VERSION 5.8 ;
BUSBITCHARS "[]" ;
DIVIDERCHAR "/" ;
UNITS
    DATABASE MICRONS 1000 ;
END UNITS

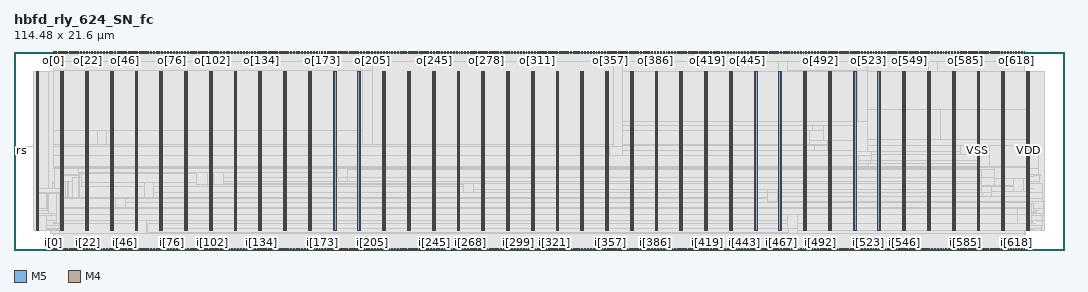
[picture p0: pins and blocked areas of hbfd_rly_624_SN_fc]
MACRO hbfd_rly_624_SN_fc
  FOREIGN hbfd_rly_624_SN_fc 0 0 ;
  CLASS BLOCK ;
  SIZE 114.48 BY 21.6 ;
  PIN clk_in
    DIRECTION INPUT ;
    USE SIGNAL ;
    PORT
      LAYER M5 ;
        RECT  57.216 0 57.24 0.192 ;
    END
  END clk_in
  PIN clk_out
    DIRECTION OUTPUT ;
    USE SIGNAL ;
    PORT
      LAYER M5 ;
        RECT  57.216 21.408 57.24 21.6 ;
    END
  END clk_out
  PIN i[0]
    DIRECTION INPUT ;
    USE SIGNAL ;
    PORT
      LAYER M5 ;
        RECT  4.32 0 4.344 0.192 ;
    END
  END i[0]
  PIN i[100]
    DIRECTION INPUT ;
    USE SIGNAL ;
    PORT
      LAYER M5 ;
        RECT  21.264 0 21.288 0.192 ;
    END
  END i[100]
  PIN i[101]
    DIRECTION INPUT ;
    USE SIGNAL ;
    PORT
      LAYER M5 ;
        RECT  21.456 0 21.48 0.192 ;
    END
  END i[101]
  PIN i[102]
    DIRECTION INPUT ;
    USE SIGNAL ;
    PORT
      LAYER M5 ;
        RECT  21.6 0 21.624 0.192 ;
    END
  END i[102]
  PIN i[103]
    DIRECTION INPUT ;
    USE SIGNAL ;
    PORT
      LAYER M5 ;
        RECT  21.792 0 21.816 0.192 ;
    END
  END i[103]
  PIN i[104]
    DIRECTION INPUT ;
    USE SIGNAL ;
    PORT
      LAYER M5 ;
        RECT  21.936 0 21.96 0.192 ;
    END
  END i[104]
  PIN i[105]
    DIRECTION INPUT ;
    USE SIGNAL ;
    PORT
      LAYER M5 ;
        RECT  22.128 0 22.152 0.192 ;
    END
  END i[105]
  PIN i[106]
    DIRECTION INPUT ;
    USE SIGNAL ;
    PORT
      LAYER M5 ;
        RECT  22.272 0 22.296 0.192 ;
    END
  END i[106]
  PIN i[107]
    DIRECTION INPUT ;
    USE SIGNAL ;
    PORT
      LAYER M5 ;
        RECT  22.464 0 22.488 0.192 ;
    END
  END i[107]
  PIN i[108]
    DIRECTION INPUT ;
    USE SIGNAL ;
    PORT
      LAYER M5 ;
        RECT  22.608 0 22.632 0.192 ;
    END
  END i[108]
  PIN i[109]
    DIRECTION INPUT ;
    USE SIGNAL ;
    PORT
      LAYER M5 ;
        RECT  22.8 0 22.824 0.192 ;
    END
  END i[109]
  PIN i[10]
    DIRECTION INPUT ;
    USE SIGNAL ;
    PORT
      LAYER M5 ;
        RECT  6 0 6.024 0.192 ;
    END
  END i[10]
  PIN i[110]
    DIRECTION INPUT ;
    USE SIGNAL ;
    PORT
      LAYER M5 ;
        RECT  22.944 0 22.968 0.192 ;
    END
  END i[110]
  PIN i[111]
    DIRECTION INPUT ;
    USE SIGNAL ;
    PORT
      LAYER M5 ;
        RECT  23.136 0 23.16 0.192 ;
    END
  END i[111]
  PIN i[112]
    DIRECTION INPUT ;
    USE SIGNAL ;
    PORT
      LAYER M5 ;
        RECT  23.328 0 23.352 0.192 ;
    END
  END i[112]
  PIN i[113]
    DIRECTION INPUT ;
    USE SIGNAL ;
    PORT
      LAYER M5 ;
        RECT  23.472 0 23.496 0.192 ;
    END
  END i[113]
  PIN i[114]
    DIRECTION INPUT ;
    USE SIGNAL ;
    PORT
      LAYER M5 ;
        RECT  23.664 0 23.688 0.192 ;
    END
  END i[114]
  PIN i[115]
    DIRECTION INPUT ;
    USE SIGNAL ;
    PORT
      LAYER M5 ;
        RECT  23.808 0 23.832 0.192 ;
    END
  END i[115]
  PIN i[116]
    DIRECTION INPUT ;
    USE SIGNAL ;
    PORT
      LAYER M5 ;
        RECT  24 0 24.024 0.192 ;
    END
  END i[116]
  PIN i[117]
    DIRECTION INPUT ;
    USE SIGNAL ;
    PORT
      LAYER M5 ;
        RECT  24.144 0 24.168 0.192 ;
    END
  END i[117]
  PIN i[118]
    DIRECTION INPUT ;
    USE SIGNAL ;
    PORT
      LAYER M5 ;
        RECT  24.336 0 24.36 0.192 ;
    END
  END i[118]
  PIN i[119]
    DIRECTION INPUT ;
    USE SIGNAL ;
    PORT
      LAYER M5 ;
        RECT  24.48 0 24.504 0.192 ;
    END
  END i[119]
  PIN i[11]
    DIRECTION INPUT ;
    USE SIGNAL ;
    PORT
      LAYER M5 ;
        RECT  6.192 0 6.216 0.192 ;
    END
  END i[11]
  PIN i[120]
    DIRECTION INPUT ;
    USE SIGNAL ;
    PORT
      LAYER M5 ;
        RECT  24.672 0 24.696 0.192 ;
    END
  END i[120]
  PIN i[121]
    DIRECTION INPUT ;
    USE SIGNAL ;
    PORT
      LAYER M5 ;
        RECT  24.816 0 24.84 0.192 ;
    END
  END i[121]
  PIN i[122]
    DIRECTION INPUT ;
    USE SIGNAL ;
    PORT
      LAYER M5 ;
        RECT  25.008 0 25.032 0.192 ;
    END
  END i[122]
  PIN i[123]
    DIRECTION INPUT ;
    USE SIGNAL ;
    PORT
      LAYER M5 ;
        RECT  25.152 0 25.176 0.192 ;
    END
  END i[123]
  PIN i[124]
    DIRECTION INPUT ;
    USE SIGNAL ;
    PORT
      LAYER M5 ;
        RECT  25.344 0 25.368 0.192 ;
    END
  END i[124]
  PIN i[125]
    DIRECTION INPUT ;
    USE SIGNAL ;
    PORT
      LAYER M5 ;
        RECT  25.488 0 25.512 0.192 ;
    END
  END i[125]
  PIN i[126]
    DIRECTION INPUT ;
    USE SIGNAL ;
    PORT
      LAYER M5 ;
        RECT  25.68 0 25.704 0.192 ;
    END
  END i[126]
  PIN i[127]
    DIRECTION INPUT ;
    USE SIGNAL ;
    PORT
      LAYER M5 ;
        RECT  25.872 0 25.896 0.192 ;
    END
  END i[127]
  PIN i[128]
    DIRECTION INPUT ;
    USE SIGNAL ;
    PORT
      LAYER M5 ;
        RECT  26.016 0 26.04 0.192 ;
    END
  END i[128]
  PIN i[129]
    DIRECTION INPUT ;
    USE SIGNAL ;
    PORT
      LAYER M5 ;
        RECT  26.208 0 26.232 0.192 ;
    END
  END i[129]
  PIN i[12]
    DIRECTION INPUT ;
    USE SIGNAL ;
    PORT
      LAYER M5 ;
        RECT  6.336 0 6.36 0.192 ;
    END
  END i[12]
  PIN i[130]
    DIRECTION INPUT ;
    USE SIGNAL ;
    PORT
      LAYER M5 ;
        RECT  26.352 0 26.376 0.192 ;
    END
  END i[130]
  PIN i[131]
    DIRECTION INPUT ;
    USE SIGNAL ;
    PORT
      LAYER M5 ;
        RECT  26.544 0 26.568 0.192 ;
    END
  END i[131]
  PIN i[132]
    DIRECTION INPUT ;
    USE SIGNAL ;
    PORT
      LAYER M5 ;
        RECT  26.688 0 26.712 0.192 ;
    END
  END i[132]
  PIN i[133]
    DIRECTION INPUT ;
    USE SIGNAL ;
    PORT
      LAYER M5 ;
        RECT  26.88 0 26.904 0.192 ;
    END
  END i[133]
  PIN i[134]
    DIRECTION INPUT ;
    USE SIGNAL ;
    PORT
      LAYER M5 ;
        RECT  27.024 0 27.048 0.192 ;
    END
  END i[134]
  PIN i[135]
    DIRECTION INPUT ;
    USE SIGNAL ;
    PORT
      LAYER M5 ;
        RECT  27.216 0 27.24 0.192 ;
    END
  END i[135]
  PIN i[136]
    DIRECTION INPUT ;
    USE SIGNAL ;
    PORT
      LAYER M5 ;
        RECT  27.36 0 27.384 0.192 ;
    END
  END i[136]
  PIN i[137]
    DIRECTION INPUT ;
    USE SIGNAL ;
    PORT
      LAYER M5 ;
        RECT  27.552 0 27.576 0.192 ;
    END
  END i[137]
  PIN i[138]
    DIRECTION INPUT ;
    USE SIGNAL ;
    PORT
      LAYER M5 ;
        RECT  27.696 0 27.72 0.192 ;
    END
  END i[138]
  PIN i[139]
    DIRECTION INPUT ;
    USE SIGNAL ;
    PORT
      LAYER M5 ;
        RECT  27.888 0 27.912 0.192 ;
    END
  END i[139]
  PIN i[13]
    DIRECTION INPUT ;
    USE SIGNAL ;
    PORT
      LAYER M5 ;
        RECT  6.528 0 6.552 0.192 ;
    END
  END i[13]
  PIN i[140]
    DIRECTION INPUT ;
    USE SIGNAL ;
    PORT
      LAYER M5 ;
        RECT  28.032 0 28.056 0.192 ;
    END
  END i[140]
  PIN i[141]
    DIRECTION INPUT ;
    USE SIGNAL ;
    PORT
      LAYER M5 ;
        RECT  28.224 0 28.248 0.192 ;
    END
  END i[141]
  PIN i[142]
    DIRECTION INPUT ;
    USE SIGNAL ;
    PORT
      LAYER M5 ;
        RECT  28.416 0 28.44 0.192 ;
    END
  END i[142]
  PIN i[143]
    DIRECTION INPUT ;
    USE SIGNAL ;
    PORT
      LAYER M5 ;
        RECT  28.56 0 28.584 0.192 ;
    END
  END i[143]
  PIN i[144]
    DIRECTION INPUT ;
    USE SIGNAL ;
    PORT
      LAYER M5 ;
        RECT  28.752 0 28.776 0.192 ;
    END
  END i[144]
  PIN i[145]
    DIRECTION INPUT ;
    USE SIGNAL ;
    PORT
      LAYER M5 ;
        RECT  28.896 0 28.92 0.192 ;
    END
  END i[145]
  PIN i[146]
    DIRECTION INPUT ;
    USE SIGNAL ;
    PORT
      LAYER M5 ;
        RECT  29.088 0 29.112 0.192 ;
    END
  END i[146]
  PIN i[147]
    DIRECTION INPUT ;
    USE SIGNAL ;
    PORT
      LAYER M5 ;
        RECT  29.232 0 29.256 0.192 ;
    END
  END i[147]
  PIN i[148]
    DIRECTION INPUT ;
    USE SIGNAL ;
    PORT
      LAYER M5 ;
        RECT  29.424 0 29.448 0.192 ;
    END
  END i[148]
  PIN i[149]
    DIRECTION INPUT ;
    USE SIGNAL ;
    PORT
      LAYER M5 ;
        RECT  29.568 0 29.592 0.192 ;
    END
  END i[149]
  PIN i[14]
    DIRECTION INPUT ;
    USE SIGNAL ;
    PORT
      LAYER M5 ;
        RECT  6.672 0 6.696 0.192 ;
    END
  END i[14]
  PIN i[150]
    DIRECTION INPUT ;
    USE SIGNAL ;
    PORT
      LAYER M5 ;
        RECT  29.76 0 29.784 0.192 ;
    END
  END i[150]
  PIN i[151]
    DIRECTION INPUT ;
    USE SIGNAL ;
    PORT
      LAYER M5 ;
        RECT  29.904 0 29.928 0.192 ;
    END
  END i[151]
  PIN i[152]
    DIRECTION INPUT ;
    USE SIGNAL ;
    PORT
      LAYER M5 ;
        RECT  30.096 0 30.12 0.192 ;
    END
  END i[152]
  PIN i[153]
    DIRECTION INPUT ;
    USE SIGNAL ;
    PORT
      LAYER M5 ;
        RECT  30.24 0 30.264 0.192 ;
    END
  END i[153]
  PIN i[154]
    DIRECTION INPUT ;
    USE SIGNAL ;
    PORT
      LAYER M5 ;
        RECT  30.432 0 30.456 0.192 ;
    END
  END i[154]
  PIN i[155]
    DIRECTION INPUT ;
    USE SIGNAL ;
    PORT
      LAYER M5 ;
        RECT  30.576 0 30.6 0.192 ;
    END
  END i[155]
  PIN i[156]
    DIRECTION INPUT ;
    USE SIGNAL ;
    PORT
      LAYER M5 ;
        RECT  30.768 0 30.792 0.192 ;
    END
  END i[156]
  PIN i[157]
    DIRECTION INPUT ;
    USE SIGNAL ;
    PORT
      LAYER M5 ;
        RECT  30.96 0 30.984 0.192 ;
    END
  END i[157]
  PIN i[158]
    DIRECTION INPUT ;
    USE SIGNAL ;
    PORT
      LAYER M5 ;
        RECT  31.104 0 31.128 0.192 ;
    END
  END i[158]
  PIN i[159]
    DIRECTION INPUT ;
    USE SIGNAL ;
    PORT
      LAYER M5 ;
        RECT  31.296 0 31.32 0.192 ;
    END
  END i[159]
  PIN i[15]
    DIRECTION INPUT ;
    USE SIGNAL ;
    PORT
      LAYER M5 ;
        RECT  6.864 0 6.888 0.192 ;
    END
  END i[15]
  PIN i[160]
    DIRECTION INPUT ;
    USE SIGNAL ;
    PORT
      LAYER M5 ;
        RECT  31.44 0 31.464 0.192 ;
    END
  END i[160]
  PIN i[161]
    DIRECTION INPUT ;
    USE SIGNAL ;
    PORT
      LAYER M5 ;
        RECT  31.632 0 31.656 0.192 ;
    END
  END i[161]
  PIN i[162]
    DIRECTION INPUT ;
    USE SIGNAL ;
    PORT
      LAYER M5 ;
        RECT  31.776 0 31.8 0.192 ;
    END
  END i[162]
  PIN i[163]
    DIRECTION INPUT ;
    USE SIGNAL ;
    PORT
      LAYER M5 ;
        RECT  31.968 0 31.992 0.192 ;
    END
  END i[163]
  PIN i[164]
    DIRECTION INPUT ;
    USE SIGNAL ;
    PORT
      LAYER M5 ;
        RECT  32.112 0 32.136 0.192 ;
    END
  END i[164]
  PIN i[165]
    DIRECTION INPUT ;
    USE SIGNAL ;
    PORT
      LAYER M5 ;
        RECT  32.304 0 32.328 0.192 ;
    END
  END i[165]
  PIN i[166]
    DIRECTION INPUT ;
    USE SIGNAL ;
    PORT
      LAYER M5 ;
        RECT  32.448 0 32.472 0.192 ;
    END
  END i[166]
  PIN i[167]
    DIRECTION INPUT ;
    USE SIGNAL ;
    PORT
      LAYER M5 ;
        RECT  32.64 0 32.664 0.192 ;
    END
  END i[167]
  PIN i[168]
    DIRECTION INPUT ;
    USE SIGNAL ;
    PORT
      LAYER M5 ;
        RECT  32.784 0 32.808 0.192 ;
    END
  END i[168]
  PIN i[169]
    DIRECTION INPUT ;
    USE SIGNAL ;
    PORT
      LAYER M5 ;
        RECT  32.976 0 33 0.192 ;
    END
  END i[169]
  PIN i[16]
    DIRECTION INPUT ;
    USE SIGNAL ;
    PORT
      LAYER M5 ;
        RECT  7.008 0 7.032 0.192 ;
    END
  END i[16]
  PIN i[170]
    DIRECTION INPUT ;
    USE SIGNAL ;
    PORT
      LAYER M5 ;
        RECT  33.12 0 33.144 0.192 ;
    END
  END i[170]
  PIN i[171]
    DIRECTION INPUT ;
    USE SIGNAL ;
    PORT
      LAYER M5 ;
        RECT  33.312 0 33.336 0.192 ;
    END
  END i[171]
  PIN i[172]
    DIRECTION INPUT ;
    USE SIGNAL ;
    PORT
      LAYER M5 ;
        RECT  33.504 0 33.528 0.192 ;
    END
  END i[172]
  PIN i[173]
    DIRECTION INPUT ;
    USE SIGNAL ;
    PORT
      LAYER M5 ;
        RECT  33.648 0 33.672 0.192 ;
    END
  END i[173]
  PIN i[174]
    DIRECTION INPUT ;
    USE SIGNAL ;
    PORT
      LAYER M5 ;
        RECT  33.84 0 33.864 0.192 ;
    END
  END i[174]
  PIN i[175]
    DIRECTION INPUT ;
    USE SIGNAL ;
    PORT
      LAYER M5 ;
        RECT  33.984 0 34.008 0.192 ;
    END
  END i[175]
  PIN i[176]
    DIRECTION INPUT ;
    USE SIGNAL ;
    PORT
      LAYER M5 ;
        RECT  34.176 0 34.2 0.192 ;
    END
  END i[176]
  PIN i[177]
    DIRECTION INPUT ;
    USE SIGNAL ;
    PORT
      LAYER M5 ;
        RECT  34.32 0 34.344 0.192 ;
    END
  END i[177]
  PIN i[178]
    DIRECTION INPUT ;
    USE SIGNAL ;
    PORT
      LAYER M5 ;
        RECT  34.512 0 34.536 0.192 ;
    END
  END i[178]
  PIN i[179]
    DIRECTION INPUT ;
    USE SIGNAL ;
    PORT
      LAYER M5 ;
        RECT  34.656 0 34.68 0.192 ;
    END
  END i[179]
  PIN i[17]
    DIRECTION INPUT ;
    USE SIGNAL ;
    PORT
      LAYER M5 ;
        RECT  7.2 0 7.224 0.192 ;
    END
  END i[17]
  PIN i[180]
    DIRECTION INPUT ;
    USE SIGNAL ;
    PORT
      LAYER M5 ;
        RECT  34.848 0 34.872 0.192 ;
    END
  END i[180]
  PIN i[181]
    DIRECTION INPUT ;
    USE SIGNAL ;
    PORT
      LAYER M5 ;
        RECT  34.992 0 35.016 0.192 ;
    END
  END i[181]
  PIN i[182]
    DIRECTION INPUT ;
    USE SIGNAL ;
    PORT
      LAYER M5 ;
        RECT  35.184 0 35.208 0.192 ;
    END
  END i[182]
  PIN i[183]
    DIRECTION INPUT ;
    USE SIGNAL ;
    PORT
      LAYER M5 ;
        RECT  35.328 0 35.352 0.192 ;
    END
  END i[183]
  PIN i[184]
    DIRECTION INPUT ;
    USE SIGNAL ;
    PORT
      LAYER M5 ;
        RECT  35.52 0 35.544 0.192 ;
    END
  END i[184]
  PIN i[185]
    DIRECTION INPUT ;
    USE SIGNAL ;
    PORT
      LAYER M5 ;
        RECT  35.664 0 35.688 0.192 ;
    END
  END i[185]
  PIN i[186]
    DIRECTION INPUT ;
    USE SIGNAL ;
    PORT
      LAYER M5 ;
        RECT  35.856 0 35.88 0.192 ;
    END
  END i[186]
  PIN i[187]
    DIRECTION INPUT ;
    USE SIGNAL ;
    PORT
      LAYER M5 ;
        RECT  36.048 0 36.072 0.192 ;
    END
  END i[187]
  PIN i[188]
    DIRECTION INPUT ;
    USE SIGNAL ;
    PORT
      LAYER M5 ;
        RECT  36.192 0 36.216 0.192 ;
    END
  END i[188]
  PIN i[189]
    DIRECTION INPUT ;
    USE SIGNAL ;
    PORT
      LAYER M5 ;
        RECT  36.384 0 36.408 0.192 ;
    END
  END i[189]
  PIN i[18]
    DIRECTION INPUT ;
    USE SIGNAL ;
    PORT
      LAYER M5 ;
        RECT  7.344 0 7.368 0.192 ;
    END
  END i[18]
  PIN i[190]
    DIRECTION INPUT ;
    USE SIGNAL ;
    PORT
      LAYER M5 ;
        RECT  36.528 0 36.552 0.192 ;
    END
  END i[190]
  PIN i[191]
    DIRECTION INPUT ;
    USE SIGNAL ;
    PORT
      LAYER M5 ;
        RECT  36.72 0 36.744 0.192 ;
    END
  END i[191]
  PIN i[192]
    DIRECTION INPUT ;
    USE SIGNAL ;
    PORT
      LAYER M5 ;
        RECT  36.864 0 36.888 0.192 ;
    END
  END i[192]
  PIN i[193]
    DIRECTION INPUT ;
    USE SIGNAL ;
    PORT
      LAYER M5 ;
        RECT  37.056 0 37.08 0.192 ;
    END
  END i[193]
  PIN i[194]
    DIRECTION INPUT ;
    USE SIGNAL ;
    PORT
      LAYER M5 ;
        RECT  37.2 0 37.224 0.192 ;
    END
  END i[194]
  PIN i[195]
    DIRECTION INPUT ;
    USE SIGNAL ;
    PORT
      LAYER M5 ;
        RECT  37.392 0 37.416 0.192 ;
    END
  END i[195]
  PIN i[196]
    DIRECTION INPUT ;
    USE SIGNAL ;
    PORT
      LAYER M5 ;
        RECT  37.536 0 37.56 0.192 ;
    END
  END i[196]
  PIN i[197]
    DIRECTION INPUT ;
    USE SIGNAL ;
    PORT
      LAYER M5 ;
        RECT  37.728 0 37.752 0.192 ;
    END
  END i[197]
  PIN i[198]
    DIRECTION INPUT ;
    USE SIGNAL ;
    PORT
      LAYER M5 ;
        RECT  37.872 0 37.896 0.192 ;
    END
  END i[198]
  PIN i[199]
    DIRECTION INPUT ;
    USE SIGNAL ;
    PORT
      LAYER M5 ;
        RECT  38.064 0 38.088 0.192 ;
    END
  END i[199]
  PIN i[19]
    DIRECTION INPUT ;
    USE SIGNAL ;
    PORT
      LAYER M5 ;
        RECT  7.536 0 7.56 0.192 ;
    END
  END i[19]
  PIN i[1]
    DIRECTION INPUT ;
    USE SIGNAL ;
    PORT
      LAYER M5 ;
        RECT  4.464 0 4.488 0.192 ;
    END
  END i[1]
  PIN i[200]
    DIRECTION INPUT ;
    USE SIGNAL ;
    PORT
      LAYER M5 ;
        RECT  38.208 0 38.232 0.192 ;
    END
  END i[200]
  PIN i[201]
    DIRECTION INPUT ;
    USE SIGNAL ;
    PORT
      LAYER M5 ;
        RECT  38.4 0 38.424 0.192 ;
    END
  END i[201]
  PIN i[202]
    DIRECTION INPUT ;
    USE SIGNAL ;
    PORT
      LAYER M5 ;
        RECT  38.592 0 38.616 0.192 ;
    END
  END i[202]
  PIN i[203]
    DIRECTION INPUT ;
    USE SIGNAL ;
    PORT
      LAYER M5 ;
        RECT  38.736 0 38.76 0.192 ;
    END
  END i[203]
  PIN i[204]
    DIRECTION INPUT ;
    USE SIGNAL ;
    PORT
      LAYER M5 ;
        RECT  38.928 0 38.952 0.192 ;
    END
  END i[204]
  PIN i[205]
    DIRECTION INPUT ;
    USE SIGNAL ;
    PORT
      LAYER M5 ;
        RECT  39.072 0 39.096 0.192 ;
    END
  END i[205]
  PIN i[206]
    DIRECTION INPUT ;
    USE SIGNAL ;
    PORT
      LAYER M5 ;
        RECT  39.264 0 39.288 0.192 ;
    END
  END i[206]
  PIN i[207]
    DIRECTION INPUT ;
    USE SIGNAL ;
    PORT
      LAYER M5 ;
        RECT  39.408 0 39.432 0.192 ;
    END
  END i[207]
  PIN i[208]
    DIRECTION INPUT ;
    USE SIGNAL ;
    PORT
      LAYER M5 ;
        RECT  39.6 0 39.624 0.192 ;
    END
  END i[208]
  PIN i[209]
    DIRECTION INPUT ;
    USE SIGNAL ;
    PORT
      LAYER M5 ;
        RECT  39.744 0 39.768 0.192 ;
    END
  END i[209]
  PIN i[20]
    DIRECTION INPUT ;
    USE SIGNAL ;
    PORT
      LAYER M5 ;
        RECT  7.68 0 7.704 0.192 ;
    END
  END i[20]
  PIN i[210]
    DIRECTION INPUT ;
    USE SIGNAL ;
    PORT
      LAYER M5 ;
        RECT  39.936 0 39.96 0.192 ;
    END
  END i[210]
  PIN i[211]
    DIRECTION INPUT ;
    USE SIGNAL ;
    PORT
      LAYER M5 ;
        RECT  40.08 0 40.104 0.192 ;
    END
  END i[211]
  PIN i[212]
    DIRECTION INPUT ;
    USE SIGNAL ;
    PORT
      LAYER M5 ;
        RECT  40.272 0 40.296 0.192 ;
    END
  END i[212]
  PIN i[213]
    DIRECTION INPUT ;
    USE SIGNAL ;
    PORT
      LAYER M5 ;
        RECT  40.416 0 40.44 0.192 ;
    END
  END i[213]
  PIN i[214]
    DIRECTION INPUT ;
    USE SIGNAL ;
    PORT
      LAYER M5 ;
        RECT  40.608 0 40.632 0.192 ;
    END
  END i[214]
  PIN i[215]
    DIRECTION INPUT ;
    USE SIGNAL ;
    PORT
      LAYER M5 ;
        RECT  40.752 0 40.776 0.192 ;
    END
  END i[215]
  PIN i[216]
    DIRECTION INPUT ;
    USE SIGNAL ;
    PORT
      LAYER M5 ;
        RECT  40.944 0 40.968 0.192 ;
    END
  END i[216]
  PIN i[217]
    DIRECTION INPUT ;
    USE SIGNAL ;
    PORT
      LAYER M5 ;
        RECT  41.136 0 41.16 0.192 ;
    END
  END i[217]
  PIN i[218]
    DIRECTION INPUT ;
    USE SIGNAL ;
    PORT
      LAYER M5 ;
        RECT  41.28 0 41.304 0.192 ;
    END
  END i[218]
  PIN i[219]
    DIRECTION INPUT ;
    USE SIGNAL ;
    PORT
      LAYER M5 ;
        RECT  41.472 0 41.496 0.192 ;
    END
  END i[219]
  PIN i[21]
    DIRECTION INPUT ;
    USE SIGNAL ;
    PORT
      LAYER M5 ;
        RECT  7.872 0 7.896 0.192 ;
    END
  END i[21]
  PIN i[220]
    DIRECTION INPUT ;
    USE SIGNAL ;
    PORT
      LAYER M5 ;
        RECT  41.616 0 41.64 0.192 ;
    END
  END i[220]
  PIN i[221]
    DIRECTION INPUT ;
    USE SIGNAL ;
    PORT
      LAYER M5 ;
        RECT  41.808 0 41.832 0.192 ;
    END
  END i[221]
  PIN i[222]
    DIRECTION INPUT ;
    USE SIGNAL ;
    PORT
      LAYER M5 ;
        RECT  41.952 0 41.976 0.192 ;
    END
  END i[222]
  PIN i[223]
    DIRECTION INPUT ;
    USE SIGNAL ;
    PORT
      LAYER M5 ;
        RECT  42.144 0 42.168 0.192 ;
    END
  END i[223]
  PIN i[224]
    DIRECTION INPUT ;
    USE SIGNAL ;
    PORT
      LAYER M5 ;
        RECT  42.288 0 42.312 0.192 ;
    END
  END i[224]
  PIN i[225]
    DIRECTION INPUT ;
    USE SIGNAL ;
    PORT
      LAYER M5 ;
        RECT  42.48 0 42.504 0.192 ;
    END
  END i[225]
  PIN i[226]
    DIRECTION INPUT ;
    USE SIGNAL ;
    PORT
      LAYER M5 ;
        RECT  42.624 0 42.648 0.192 ;
    END
  END i[226]
  PIN i[227]
    DIRECTION INPUT ;
    USE SIGNAL ;
    PORT
      LAYER M5 ;
        RECT  42.816 0 42.84 0.192 ;
    END
  END i[227]
  PIN i[228]
    DIRECTION INPUT ;
    USE SIGNAL ;
    PORT
      LAYER M5 ;
        RECT  42.96 0 42.984 0.192 ;
    END
  END i[228]
  PIN i[229]
    DIRECTION INPUT ;
    USE SIGNAL ;
    PORT
      LAYER M5 ;
        RECT  43.152 0 43.176 0.192 ;
    END
  END i[229]
  PIN i[22]
    DIRECTION INPUT ;
    USE SIGNAL ;
    PORT
      LAYER M5 ;
        RECT  8.016 0 8.04 0.192 ;
    END
  END i[22]
  PIN i[230]
    DIRECTION INPUT ;
    USE SIGNAL ;
    PORT
      LAYER M5 ;
        RECT  43.296 0 43.32 0.192 ;
    END
  END i[230]
  PIN i[231]
    DIRECTION INPUT ;
    USE SIGNAL ;
    PORT
      LAYER M5 ;
        RECT  43.488 0 43.512 0.192 ;
    END
  END i[231]
  PIN i[232]
    DIRECTION INPUT ;
    USE SIGNAL ;
    PORT
      LAYER M5 ;
        RECT  43.68 0 43.704 0.192 ;
    END
  END i[232]
  PIN i[233]
    DIRECTION INPUT ;
    USE SIGNAL ;
    PORT
      LAYER M5 ;
        RECT  43.824 0 43.848 0.192 ;
    END
  END i[233]
  PIN i[234]
    DIRECTION INPUT ;
    USE SIGNAL ;
    PORT
      LAYER M5 ;
        RECT  44.016 0 44.04 0.192 ;
    END
  END i[234]
  PIN i[235]
    DIRECTION INPUT ;
    USE SIGNAL ;
    PORT
      LAYER M5 ;
        RECT  44.16 0 44.184 0.192 ;
    END
  END i[235]
  PIN i[236]
    DIRECTION INPUT ;
    USE SIGNAL ;
    PORT
      LAYER M5 ;
        RECT  44.352 0 44.376 0.192 ;
    END
  END i[236]
  PIN i[237]
    DIRECTION INPUT ;
    USE SIGNAL ;
    PORT
      LAYER M5 ;
        RECT  44.496 0 44.52 0.192 ;
    END
  END i[237]
  PIN i[238]
    DIRECTION INPUT ;
    USE SIGNAL ;
    PORT
      LAYER M5 ;
        RECT  44.688 0 44.712 0.192 ;
    END
  END i[238]
  PIN i[239]
    DIRECTION INPUT ;
    USE SIGNAL ;
    PORT
      LAYER M5 ;
        RECT  44.832 0 44.856 0.192 ;
    END
  END i[239]
  PIN i[23]
    DIRECTION INPUT ;
    USE SIGNAL ;
    PORT
      LAYER M5 ;
        RECT  8.208 0 8.232 0.192 ;
    END
  END i[23]
  PIN i[240]
    DIRECTION INPUT ;
    USE SIGNAL ;
    PORT
      LAYER M5 ;
        RECT  45.024 0 45.048 0.192 ;
    END
  END i[240]
  PIN i[241]
    DIRECTION INPUT ;
    USE SIGNAL ;
    PORT
      LAYER M5 ;
        RECT  45.168 0 45.192 0.192 ;
    END
  END i[241]
  PIN i[242]
    DIRECTION INPUT ;
    USE SIGNAL ;
    PORT
      LAYER M5 ;
        RECT  45.36 0 45.384 0.192 ;
    END
  END i[242]
  PIN i[243]
    DIRECTION INPUT ;
    USE SIGNAL ;
    PORT
      LAYER M5 ;
        RECT  45.504 0 45.528 0.192 ;
    END
  END i[243]
  PIN i[244]
    DIRECTION INPUT ;
    USE SIGNAL ;
    PORT
      LAYER M5 ;
        RECT  45.696 0 45.72 0.192 ;
    END
  END i[244]
  PIN i[245]
    DIRECTION INPUT ;
    USE SIGNAL ;
    PORT
      LAYER M5 ;
        RECT  45.84 0 45.864 0.192 ;
    END
  END i[245]
  PIN i[246]
    DIRECTION INPUT ;
    USE SIGNAL ;
    PORT
      LAYER M5 ;
        RECT  46.032 0 46.056 0.192 ;
    END
  END i[246]
  PIN i[247]
    DIRECTION INPUT ;
    USE SIGNAL ;
    PORT
      LAYER M5 ;
        RECT  46.224 0 46.248 0.192 ;
    END
  END i[247]
  PIN i[248]
    DIRECTION INPUT ;
    USE SIGNAL ;
    PORT
      LAYER M5 ;
        RECT  46.368 0 46.392 0.192 ;
    END
  END i[248]
  PIN i[249]
    DIRECTION INPUT ;
    USE SIGNAL ;
    PORT
      LAYER M5 ;
        RECT  46.56 0 46.584 0.192 ;
    END
  END i[249]
  PIN i[24]
    DIRECTION INPUT ;
    USE SIGNAL ;
    PORT
      LAYER M5 ;
        RECT  8.4 0 8.424 0.192 ;
    END
  END i[24]
  PIN i[250]
    DIRECTION INPUT ;
    USE SIGNAL ;
    PORT
      LAYER M5 ;
        RECT  46.704 0 46.728 0.192 ;
    END
  END i[250]
  PIN i[251]
    DIRECTION INPUT ;
    USE SIGNAL ;
    PORT
      LAYER M5 ;
        RECT  46.896 0 46.92 0.192 ;
    END
  END i[251]
  PIN i[252]
    DIRECTION INPUT ;
    USE SIGNAL ;
    PORT
      LAYER M5 ;
        RECT  47.04 0 47.064 0.192 ;
    END
  END i[252]
  PIN i[253]
    DIRECTION INPUT ;
    USE SIGNAL ;
    PORT
      LAYER M5 ;
        RECT  47.232 0 47.256 0.192 ;
    END
  END i[253]
  PIN i[254]
    DIRECTION INPUT ;
    USE SIGNAL ;
    PORT
      LAYER M5 ;
        RECT  47.376 0 47.4 0.192 ;
    END
  END i[254]
  PIN i[255]
    DIRECTION INPUT ;
    USE SIGNAL ;
    PORT
      LAYER M5 ;
        RECT  47.568 0 47.592 0.192 ;
    END
  END i[255]
  PIN i[256]
    DIRECTION INPUT ;
    USE SIGNAL ;
    PORT
      LAYER M5 ;
        RECT  47.712 0 47.736 0.192 ;
    END
  END i[256]
  PIN i[257]
    DIRECTION INPUT ;
    USE SIGNAL ;
    PORT
      LAYER M5 ;
        RECT  47.904 0 47.928 0.192 ;
    END
  END i[257]
  PIN i[258]
    DIRECTION INPUT ;
    USE SIGNAL ;
    PORT
      LAYER M5 ;
        RECT  48.048 0 48.072 0.192 ;
    END
  END i[258]
  PIN i[259]
    DIRECTION INPUT ;
    USE SIGNAL ;
    PORT
      LAYER M5 ;
        RECT  48.24 0 48.264 0.192 ;
    END
  END i[259]
  PIN i[25]
    DIRECTION INPUT ;
    USE SIGNAL ;
    PORT
      LAYER M5 ;
        RECT  8.544 0 8.568 0.192 ;
    END
  END i[25]
  PIN i[260]
    DIRECTION INPUT ;
    USE SIGNAL ;
    PORT
      LAYER M5 ;
        RECT  48.384 0 48.408 0.192 ;
    END
  END i[260]
  PIN i[261]
    DIRECTION INPUT ;
    USE SIGNAL ;
    PORT
      LAYER M5 ;
        RECT  48.576 0 48.6 0.192 ;
    END
  END i[261]
  PIN i[262]
    DIRECTION INPUT ;
    USE SIGNAL ;
    PORT
      LAYER M5 ;
        RECT  48.768 0 48.792 0.192 ;
    END
  END i[262]
  PIN i[263]
    DIRECTION INPUT ;
    USE SIGNAL ;
    PORT
      LAYER M5 ;
        RECT  48.912 0 48.936 0.192 ;
    END
  END i[263]
  PIN i[264]
    DIRECTION INPUT ;
    USE SIGNAL ;
    PORT
      LAYER M5 ;
        RECT  49.104 0 49.128 0.192 ;
    END
  END i[264]
  PIN i[265]
    DIRECTION INPUT ;
    USE SIGNAL ;
    PORT
      LAYER M5 ;
        RECT  49.248 0 49.272 0.192 ;
    END
  END i[265]
  PIN i[266]
    DIRECTION INPUT ;
    USE SIGNAL ;
    PORT
      LAYER M5 ;
        RECT  49.44 0 49.464 0.192 ;
    END
  END i[266]
  PIN i[267]
    DIRECTION INPUT ;
    USE SIGNAL ;
    PORT
      LAYER M5 ;
        RECT  49.584 0 49.608 0.192 ;
    END
  END i[267]
  PIN i[268]
    DIRECTION INPUT ;
    USE SIGNAL ;
    PORT
      LAYER M5 ;
        RECT  49.776 0 49.8 0.192 ;
    END
  END i[268]
  PIN i[269]
    DIRECTION INPUT ;
    USE SIGNAL ;
    PORT
      LAYER M5 ;
        RECT  49.92 0 49.944 0.192 ;
    END
  END i[269]
  PIN i[26]
    DIRECTION INPUT ;
    USE SIGNAL ;
    PORT
      LAYER M5 ;
        RECT  8.736 0 8.76 0.192 ;
    END
  END i[26]
  PIN i[270]
    DIRECTION INPUT ;
    USE SIGNAL ;
    PORT
      LAYER M5 ;
        RECT  50.112 0 50.136 0.192 ;
    END
  END i[270]
  PIN i[271]
    DIRECTION INPUT ;
    USE SIGNAL ;
    PORT
      LAYER M5 ;
        RECT  50.256 0 50.28 0.192 ;
    END
  END i[271]
  PIN i[272]
    DIRECTION INPUT ;
    USE SIGNAL ;
    PORT
      LAYER M5 ;
        RECT  50.448 0 50.472 0.192 ;
    END
  END i[272]
  PIN i[273]
    DIRECTION INPUT ;
    USE SIGNAL ;
    PORT
      LAYER M5 ;
        RECT  50.592 0 50.616 0.192 ;
    END
  END i[273]
  PIN i[274]
    DIRECTION INPUT ;
    USE SIGNAL ;
    PORT
      LAYER M5 ;
        RECT  50.784 0 50.808 0.192 ;
    END
  END i[274]
  PIN i[275]
    DIRECTION INPUT ;
    USE SIGNAL ;
    PORT
      LAYER M5 ;
        RECT  50.976 0 51 0.192 ;
    END
  END i[275]
  PIN i[276]
    DIRECTION INPUT ;
    USE SIGNAL ;
    PORT
      LAYER M5 ;
        RECT  51.12 0 51.144 0.192 ;
    END
  END i[276]
  PIN i[277]
    DIRECTION INPUT ;
    USE SIGNAL ;
    PORT
      LAYER M5 ;
        RECT  51.312 0 51.336 0.192 ;
    END
  END i[277]
  PIN i[278]
    DIRECTION INPUT ;
    USE SIGNAL ;
    PORT
      LAYER M5 ;
        RECT  51.456 0 51.48 0.192 ;
    END
  END i[278]
  PIN i[279]
    DIRECTION INPUT ;
    USE SIGNAL ;
    PORT
      LAYER M5 ;
        RECT  51.648 0 51.672 0.192 ;
    END
  END i[279]
  PIN i[27]
    DIRECTION INPUT ;
    USE SIGNAL ;
    PORT
      LAYER M5 ;
        RECT  8.88 0 8.904 0.192 ;
    END
  END i[27]
  PIN i[280]
    DIRECTION INPUT ;
    USE SIGNAL ;
    PORT
      LAYER M5 ;
        RECT  51.792 0 51.816 0.192 ;
    END
  END i[280]
  PIN i[281]
    DIRECTION INPUT ;
    USE SIGNAL ;
    PORT
      LAYER M5 ;
        RECT  51.984 0 52.008 0.192 ;
    END
  END i[281]
  PIN i[282]
    DIRECTION INPUT ;
    USE SIGNAL ;
    PORT
      LAYER M5 ;
        RECT  52.128 0 52.152 0.192 ;
    END
  END i[282]
  PIN i[283]
    DIRECTION INPUT ;
    USE SIGNAL ;
    PORT
      LAYER M5 ;
        RECT  52.32 0 52.344 0.192 ;
    END
  END i[283]
  PIN i[284]
    DIRECTION INPUT ;
    USE SIGNAL ;
    PORT
      LAYER M5 ;
        RECT  52.464 0 52.488 0.192 ;
    END
  END i[284]
  PIN i[285]
    DIRECTION INPUT ;
    USE SIGNAL ;
    PORT
      LAYER M5 ;
        RECT  52.656 0 52.68 0.192 ;
    END
  END i[285]
  PIN i[286]
    DIRECTION INPUT ;
    USE SIGNAL ;
    PORT
      LAYER M5 ;
        RECT  52.8 0 52.824 0.192 ;
    END
  END i[286]
  PIN i[287]
    DIRECTION INPUT ;
    USE SIGNAL ;
    PORT
      LAYER M5 ;
        RECT  52.992 0 53.016 0.192 ;
    END
  END i[287]
  PIN i[288]
    DIRECTION INPUT ;
    USE SIGNAL ;
    PORT
      LAYER M5 ;
        RECT  53.136 0 53.16 0.192 ;
    END
  END i[288]
  PIN i[289]
    DIRECTION INPUT ;
    USE SIGNAL ;
    PORT
      LAYER M5 ;
        RECT  53.328 0 53.352 0.192 ;
    END
  END i[289]
  PIN i[28]
    DIRECTION INPUT ;
    USE SIGNAL ;
    PORT
      LAYER M5 ;
        RECT  9.072 0 9.096 0.192 ;
    END
  END i[28]
  PIN i[290]
    DIRECTION INPUT ;
    USE SIGNAL ;
    PORT
      LAYER M5 ;
        RECT  53.52 0 53.544 0.192 ;
    END
  END i[290]
  PIN i[291]
    DIRECTION INPUT ;
    USE SIGNAL ;
    PORT
      LAYER M5 ;
        RECT  53.664 0 53.688 0.192 ;
    END
  END i[291]
  PIN i[292]
    DIRECTION INPUT ;
    USE SIGNAL ;
    PORT
      LAYER M5 ;
        RECT  53.856 0 53.88 0.192 ;
    END
  END i[292]
  PIN i[293]
    DIRECTION INPUT ;
    USE SIGNAL ;
    PORT
      LAYER M5 ;
        RECT  54 0 54.024 0.192 ;
    END
  END i[293]
  PIN i[294]
    DIRECTION INPUT ;
    USE SIGNAL ;
    PORT
      LAYER M5 ;
        RECT  54.192 0 54.216 0.192 ;
    END
  END i[294]
  PIN i[295]
    DIRECTION INPUT ;
    USE SIGNAL ;
    PORT
      LAYER M5 ;
        RECT  54.336 0 54.36 0.192 ;
    END
  END i[295]
  PIN i[296]
    DIRECTION INPUT ;
    USE SIGNAL ;
    PORT
      LAYER M5 ;
        RECT  54.528 0 54.552 0.192 ;
    END
  END i[296]
  PIN i[297]
    DIRECTION INPUT ;
    USE SIGNAL ;
    PORT
      LAYER M5 ;
        RECT  54.672 0 54.696 0.192 ;
    END
  END i[297]
  PIN i[298]
    DIRECTION INPUT ;
    USE SIGNAL ;
    PORT
      LAYER M5 ;
        RECT  54.864 0 54.888 0.192 ;
    END
  END i[298]
  PIN i[299]
    DIRECTION INPUT ;
    USE SIGNAL ;
    PORT
      LAYER M5 ;
        RECT  55.008 0 55.032 0.192 ;
    END
  END i[299]
  PIN i[29]
    DIRECTION INPUT ;
    USE SIGNAL ;
    PORT
      LAYER M5 ;
        RECT  9.216 0 9.24 0.192 ;
    END
  END i[29]
  PIN i[2]
    DIRECTION INPUT ;
    USE SIGNAL ;
    PORT
      LAYER M5 ;
        RECT  4.656 0 4.68 0.192 ;
    END
  END i[2]
  PIN i[300]
    DIRECTION INPUT ;
    USE SIGNAL ;
    PORT
      LAYER M5 ;
        RECT  55.2 0 55.224 0.192 ;
    END
  END i[300]
  PIN i[301]
    DIRECTION INPUT ;
    USE SIGNAL ;
    PORT
      LAYER M5 ;
        RECT  55.344 0 55.368 0.192 ;
    END
  END i[301]
  PIN i[302]
    DIRECTION INPUT ;
    USE SIGNAL ;
    PORT
      LAYER M5 ;
        RECT  55.536 0 55.56 0.192 ;
    END
  END i[302]
  PIN i[303]
    DIRECTION INPUT ;
    USE SIGNAL ;
    PORT
      LAYER M5 ;
        RECT  55.68 0 55.704 0.192 ;
    END
  END i[303]
  PIN i[304]
    DIRECTION INPUT ;
    USE SIGNAL ;
    PORT
      LAYER M5 ;
        RECT  55.872 0 55.896 0.192 ;
    END
  END i[304]
  PIN i[305]
    DIRECTION INPUT ;
    USE SIGNAL ;
    PORT
      LAYER M5 ;
        RECT  56.064 0 56.088 0.192 ;
    END
  END i[305]
  PIN i[306]
    DIRECTION INPUT ;
    USE SIGNAL ;
    PORT
      LAYER M5 ;
        RECT  56.208 0 56.232 0.192 ;
    END
  END i[306]
  PIN i[307]
    DIRECTION INPUT ;
    USE SIGNAL ;
    PORT
      LAYER M5 ;
        RECT  56.4 0 56.424 0.192 ;
    END
  END i[307]
  PIN i[308]
    DIRECTION INPUT ;
    USE SIGNAL ;
    PORT
      LAYER M5 ;
        RECT  56.544 0 56.568 0.192 ;
    END
  END i[308]
  PIN i[309]
    DIRECTION INPUT ;
    USE SIGNAL ;
    PORT
      LAYER M5 ;
        RECT  56.736 0 56.76 0.192 ;
    END
  END i[309]
  PIN i[30]
    DIRECTION INPUT ;
    USE SIGNAL ;
    PORT
      LAYER M5 ;
        RECT  9.408 0 9.432 0.192 ;
    END
  END i[30]
  PIN i[310]
    DIRECTION INPUT ;
    USE SIGNAL ;
    PORT
      LAYER M5 ;
        RECT  56.88 0 56.904 0.192 ;
    END
  END i[310]
  PIN i[311]
    DIRECTION INPUT ;
    USE SIGNAL ;
    PORT
      LAYER M5 ;
        RECT  57.072 0 57.096 0.192 ;
    END
  END i[311]
  PIN i[312]
    DIRECTION INPUT ;
    USE SIGNAL ;
    PORT
      LAYER M5 ;
        RECT  57.408 0 57.432 0.192 ;
    END
  END i[312]
  PIN i[313]
    DIRECTION INPUT ;
    USE SIGNAL ;
    PORT
      LAYER M5 ;
        RECT  57.552 0 57.576 0.192 ;
    END
  END i[313]
  PIN i[314]
    DIRECTION INPUT ;
    USE SIGNAL ;
    PORT
      LAYER M5 ;
        RECT  57.744 0 57.768 0.192 ;
    END
  END i[314]
  PIN i[315]
    DIRECTION INPUT ;
    USE SIGNAL ;
    PORT
      LAYER M5 ;
        RECT  57.888 0 57.912 0.192 ;
    END
  END i[315]
  PIN i[316]
    DIRECTION INPUT ;
    USE SIGNAL ;
    PORT
      LAYER M5 ;
        RECT  58.08 0 58.104 0.192 ;
    END
  END i[316]
  PIN i[317]
    DIRECTION INPUT ;
    USE SIGNAL ;
    PORT
      LAYER M5 ;
        RECT  58.224 0 58.248 0.192 ;
    END
  END i[317]
  PIN i[318]
    DIRECTION INPUT ;
    USE SIGNAL ;
    PORT
      LAYER M5 ;
        RECT  58.416 0 58.44 0.192 ;
    END
  END i[318]
  PIN i[319]
    DIRECTION INPUT ;
    USE SIGNAL ;
    PORT
      LAYER M5 ;
        RECT  58.608 0 58.632 0.192 ;
    END
  END i[319]
  PIN i[31]
    DIRECTION INPUT ;
    USE SIGNAL ;
    PORT
      LAYER M5 ;
        RECT  9.552 0 9.576 0.192 ;
    END
  END i[31]
  PIN i[320]
    DIRECTION INPUT ;
    USE SIGNAL ;
    PORT
      LAYER M5 ;
        RECT  58.752 0 58.776 0.192 ;
    END
  END i[320]
  PIN i[321]
    DIRECTION INPUT ;
    USE SIGNAL ;
    PORT
      LAYER M5 ;
        RECT  58.944 0 58.968 0.192 ;
    END
  END i[321]
  PIN i[322]
    DIRECTION INPUT ;
    USE SIGNAL ;
    PORT
      LAYER M5 ;
        RECT  59.088 0 59.112 0.192 ;
    END
  END i[322]
  PIN i[323]
    DIRECTION INPUT ;
    USE SIGNAL ;
    PORT
      LAYER M5 ;
        RECT  59.28 0 59.304 0.192 ;
    END
  END i[323]
  PIN i[324]
    DIRECTION INPUT ;
    USE SIGNAL ;
    PORT
      LAYER M5 ;
        RECT  59.424 0 59.448 0.192 ;
    END
  END i[324]
  PIN i[325]
    DIRECTION INPUT ;
    USE SIGNAL ;
    PORT
      LAYER M5 ;
        RECT  59.616 0 59.64 0.192 ;
    END
  END i[325]
  PIN i[326]
    DIRECTION INPUT ;
    USE SIGNAL ;
    PORT
      LAYER M5 ;
        RECT  59.76 0 59.784 0.192 ;
    END
  END i[326]
  PIN i[327]
    DIRECTION INPUT ;
    USE SIGNAL ;
    PORT
      LAYER M5 ;
        RECT  59.952 0 59.976 0.192 ;
    END
  END i[327]
  PIN i[328]
    DIRECTION INPUT ;
    USE SIGNAL ;
    PORT
      LAYER M5 ;
        RECT  60.096 0 60.12 0.192 ;
    END
  END i[328]
  PIN i[329]
    DIRECTION INPUT ;
    USE SIGNAL ;
    PORT
      LAYER M5 ;
        RECT  60.288 0 60.312 0.192 ;
    END
  END i[329]
  PIN i[32]
    DIRECTION INPUT ;
    USE SIGNAL ;
    PORT
      LAYER M5 ;
        RECT  9.744 0 9.768 0.192 ;
    END
  END i[32]
  PIN i[330]
    DIRECTION INPUT ;
    USE SIGNAL ;
    PORT
      LAYER M5 ;
        RECT  60.432 0 60.456 0.192 ;
    END
  END i[330]
  PIN i[331]
    DIRECTION INPUT ;
    USE SIGNAL ;
    PORT
      LAYER M5 ;
        RECT  60.624 0 60.648 0.192 ;
    END
  END i[331]
  PIN i[332]
    DIRECTION INPUT ;
    USE SIGNAL ;
    PORT
      LAYER M5 ;
        RECT  60.768 0 60.792 0.192 ;
    END
  END i[332]
  PIN i[333]
    DIRECTION INPUT ;
    USE SIGNAL ;
    PORT
      LAYER M5 ;
        RECT  60.96 0 60.984 0.192 ;
    END
  END i[333]
  PIN i[334]
    DIRECTION INPUT ;
    USE SIGNAL ;
    PORT
      LAYER M5 ;
        RECT  61.152 0 61.176 0.192 ;
    END
  END i[334]
  PIN i[335]
    DIRECTION INPUT ;
    USE SIGNAL ;
    PORT
      LAYER M5 ;
        RECT  61.296 0 61.32 0.192 ;
    END
  END i[335]
  PIN i[336]
    DIRECTION INPUT ;
    USE SIGNAL ;
    PORT
      LAYER M5 ;
        RECT  61.488 0 61.512 0.192 ;
    END
  END i[336]
  PIN i[337]
    DIRECTION INPUT ;
    USE SIGNAL ;
    PORT
      LAYER M5 ;
        RECT  61.632 0 61.656 0.192 ;
    END
  END i[337]
  PIN i[338]
    DIRECTION INPUT ;
    USE SIGNAL ;
    PORT
      LAYER M5 ;
        RECT  61.824 0 61.848 0.192 ;
    END
  END i[338]
  PIN i[339]
    DIRECTION INPUT ;
    USE SIGNAL ;
    PORT
      LAYER M5 ;
        RECT  61.968 0 61.992 0.192 ;
    END
  END i[339]
  PIN i[33]
    DIRECTION INPUT ;
    USE SIGNAL ;
    PORT
      LAYER M5 ;
        RECT  9.888 0 9.912 0.192 ;
    END
  END i[33]
  PIN i[340]
    DIRECTION INPUT ;
    USE SIGNAL ;
    PORT
      LAYER M5 ;
        RECT  62.16 0 62.184 0.192 ;
    END
  END i[340]
  PIN i[341]
    DIRECTION INPUT ;
    USE SIGNAL ;
    PORT
      LAYER M5 ;
        RECT  62.304 0 62.328 0.192 ;
    END
  END i[341]
  PIN i[342]
    DIRECTION INPUT ;
    USE SIGNAL ;
    PORT
      LAYER M5 ;
        RECT  62.496 0 62.52 0.192 ;
    END
  END i[342]
  PIN i[343]
    DIRECTION INPUT ;
    USE SIGNAL ;
    PORT
      LAYER M5 ;
        RECT  62.64 0 62.664 0.192 ;
    END
  END i[343]
  PIN i[344]
    DIRECTION INPUT ;
    USE SIGNAL ;
    PORT
      LAYER M5 ;
        RECT  62.832 0 62.856 0.192 ;
    END
  END i[344]
  PIN i[345]
    DIRECTION INPUT ;
    USE SIGNAL ;
    PORT
      LAYER M5 ;
        RECT  62.976 0 63 0.192 ;
    END
  END i[345]
  PIN i[346]
    DIRECTION INPUT ;
    USE SIGNAL ;
    PORT
      LAYER M5 ;
        RECT  63.168 0 63.192 0.192 ;
    END
  END i[346]
  PIN i[347]
    DIRECTION INPUT ;
    USE SIGNAL ;
    PORT
      LAYER M5 ;
        RECT  63.312 0 63.336 0.192 ;
    END
  END i[347]
  PIN i[348]
    DIRECTION INPUT ;
    USE SIGNAL ;
    PORT
      LAYER M5 ;
        RECT  63.504 0 63.528 0.192 ;
    END
  END i[348]
  PIN i[349]
    DIRECTION INPUT ;
    USE SIGNAL ;
    PORT
      LAYER M5 ;
        RECT  63.696 0 63.72 0.192 ;
    END
  END i[349]
  PIN i[34]
    DIRECTION INPUT ;
    USE SIGNAL ;
    PORT
      LAYER M5 ;
        RECT  10.08 0 10.104 0.192 ;
    END
  END i[34]
  PIN i[350]
    DIRECTION INPUT ;
    USE SIGNAL ;
    PORT
      LAYER M5 ;
        RECT  63.84 0 63.864 0.192 ;
    END
  END i[350]
  PIN i[351]
    DIRECTION INPUT ;
    USE SIGNAL ;
    PORT
      LAYER M5 ;
        RECT  64.032 0 64.056 0.192 ;
    END
  END i[351]
  PIN i[352]
    DIRECTION INPUT ;
    USE SIGNAL ;
    PORT
      LAYER M5 ;
        RECT  64.176 0 64.2 0.192 ;
    END
  END i[352]
  PIN i[353]
    DIRECTION INPUT ;
    USE SIGNAL ;
    PORT
      LAYER M5 ;
        RECT  64.368 0 64.392 0.192 ;
    END
  END i[353]
  PIN i[354]
    DIRECTION INPUT ;
    USE SIGNAL ;
    PORT
      LAYER M5 ;
        RECT  64.512 0 64.536 0.192 ;
    END
  END i[354]
  PIN i[355]
    DIRECTION INPUT ;
    USE SIGNAL ;
    PORT
      LAYER M5 ;
        RECT  64.704 0 64.728 0.192 ;
    END
  END i[355]
  PIN i[356]
    DIRECTION INPUT ;
    USE SIGNAL ;
    PORT
      LAYER M5 ;
        RECT  64.848 0 64.872 0.192 ;
    END
  END i[356]
  PIN i[357]
    DIRECTION INPUT ;
    USE SIGNAL ;
    PORT
      LAYER M5 ;
        RECT  65.04 0 65.064 0.192 ;
    END
  END i[357]
  PIN i[358]
    DIRECTION INPUT ;
    USE SIGNAL ;
    PORT
      LAYER M5 ;
        RECT  65.184 0 65.208 0.192 ;
    END
  END i[358]
  PIN i[359]
    DIRECTION INPUT ;
    USE SIGNAL ;
    PORT
      LAYER M5 ;
        RECT  65.376 0 65.4 0.192 ;
    END
  END i[359]
  PIN i[35]
    DIRECTION INPUT ;
    USE SIGNAL ;
    PORT
      LAYER M5 ;
        RECT  10.224 0 10.248 0.192 ;
    END
  END i[35]
  PIN i[360]
    DIRECTION INPUT ;
    USE SIGNAL ;
    PORT
      LAYER M5 ;
        RECT  65.52 0 65.544 0.192 ;
    END
  END i[360]
  PIN i[361]
    DIRECTION INPUT ;
    USE SIGNAL ;
    PORT
      LAYER M5 ;
        RECT  65.712 0 65.736 0.192 ;
    END
  END i[361]
  PIN i[362]
    DIRECTION INPUT ;
    USE SIGNAL ;
    PORT
      LAYER M5 ;
        RECT  65.856 0 65.88 0.192 ;
    END
  END i[362]
  PIN i[363]
    DIRECTION INPUT ;
    USE SIGNAL ;
    PORT
      LAYER M5 ;
        RECT  66.048 0 66.072 0.192 ;
    END
  END i[363]
  PIN i[364]
    DIRECTION INPUT ;
    USE SIGNAL ;
    PORT
      LAYER M5 ;
        RECT  66.24 0 66.264 0.192 ;
    END
  END i[364]
  PIN i[365]
    DIRECTION INPUT ;
    USE SIGNAL ;
    PORT
      LAYER M5 ;
        RECT  66.384 0 66.408 0.192 ;
    END
  END i[365]
  PIN i[366]
    DIRECTION INPUT ;
    USE SIGNAL ;
    PORT
      LAYER M5 ;
        RECT  66.576 0 66.6 0.192 ;
    END
  END i[366]
  PIN i[367]
    DIRECTION INPUT ;
    USE SIGNAL ;
    PORT
      LAYER M5 ;
        RECT  66.72 0 66.744 0.192 ;
    END
  END i[367]
  PIN i[368]
    DIRECTION INPUT ;
    USE SIGNAL ;
    PORT
      LAYER M5 ;
        RECT  66.912 0 66.936 0.192 ;
    END
  END i[368]
  PIN i[369]
    DIRECTION INPUT ;
    USE SIGNAL ;
    PORT
      LAYER M5 ;
        RECT  67.056 0 67.08 0.192 ;
    END
  END i[369]
  PIN i[36]
    DIRECTION INPUT ;
    USE SIGNAL ;
    PORT
      LAYER M5 ;
        RECT  10.416 0 10.44 0.192 ;
    END
  END i[36]
  PIN i[370]
    DIRECTION INPUT ;
    USE SIGNAL ;
    PORT
      LAYER M5 ;
        RECT  67.248 0 67.272 0.192 ;
    END
  END i[370]
  PIN i[371]
    DIRECTION INPUT ;
    USE SIGNAL ;
    PORT
      LAYER M5 ;
        RECT  67.392 0 67.416 0.192 ;
    END
  END i[371]
  PIN i[372]
    DIRECTION INPUT ;
    USE SIGNAL ;
    PORT
      LAYER M5 ;
        RECT  67.584 0 67.608 0.192 ;
    END
  END i[372]
  PIN i[373]
    DIRECTION INPUT ;
    USE SIGNAL ;
    PORT
      LAYER M5 ;
        RECT  67.728 0 67.752 0.192 ;
    END
  END i[373]
  PIN i[374]
    DIRECTION INPUT ;
    USE SIGNAL ;
    PORT
      LAYER M5 ;
        RECT  67.92 0 67.944 0.192 ;
    END
  END i[374]
  PIN i[375]
    DIRECTION INPUT ;
    USE SIGNAL ;
    PORT
      LAYER M5 ;
        RECT  68.064 0 68.088 0.192 ;
    END
  END i[375]
  PIN i[376]
    DIRECTION INPUT ;
    USE SIGNAL ;
    PORT
      LAYER M5 ;
        RECT  68.256 0 68.28 0.192 ;
    END
  END i[376]
  PIN i[377]
    DIRECTION INPUT ;
    USE SIGNAL ;
    PORT
      LAYER M5 ;
        RECT  68.4 0 68.424 0.192 ;
    END
  END i[377]
  PIN i[378]
    DIRECTION INPUT ;
    USE SIGNAL ;
    PORT
      LAYER M5 ;
        RECT  68.592 0 68.616 0.192 ;
    END
  END i[378]
  PIN i[379]
    DIRECTION INPUT ;
    USE SIGNAL ;
    PORT
      LAYER M5 ;
        RECT  68.784 0 68.808 0.192 ;
    END
  END i[379]
  PIN i[37]
    DIRECTION INPUT ;
    USE SIGNAL ;
    PORT
      LAYER M5 ;
        RECT  10.56 0 10.584 0.192 ;
    END
  END i[37]
  PIN i[380]
    DIRECTION INPUT ;
    USE SIGNAL ;
    PORT
      LAYER M5 ;
        RECT  68.928 0 68.952 0.192 ;
    END
  END i[380]
  PIN i[381]
    DIRECTION INPUT ;
    USE SIGNAL ;
    PORT
      LAYER M5 ;
        RECT  69.12 0 69.144 0.192 ;
    END
  END i[381]
  PIN i[382]
    DIRECTION INPUT ;
    USE SIGNAL ;
    PORT
      LAYER M5 ;
        RECT  69.264 0 69.288 0.192 ;
    END
  END i[382]
  PIN i[383]
    DIRECTION INPUT ;
    USE SIGNAL ;
    PORT
      LAYER M5 ;
        RECT  69.456 0 69.48 0.192 ;
    END
  END i[383]
  PIN i[384]
    DIRECTION INPUT ;
    USE SIGNAL ;
    PORT
      LAYER M5 ;
        RECT  69.6 0 69.624 0.192 ;
    END
  END i[384]
  PIN i[385]
    DIRECTION INPUT ;
    USE SIGNAL ;
    PORT
      LAYER M5 ;
        RECT  69.792 0 69.816 0.192 ;
    END
  END i[385]
  PIN i[386]
    DIRECTION INPUT ;
    USE SIGNAL ;
    PORT
      LAYER M5 ;
        RECT  69.936 0 69.96 0.192 ;
    END
  END i[386]
  PIN i[387]
    DIRECTION INPUT ;
    USE SIGNAL ;
    PORT
      LAYER M5 ;
        RECT  70.128 0 70.152 0.192 ;
    END
  END i[387]
  PIN i[388]
    DIRECTION INPUT ;
    USE SIGNAL ;
    PORT
      LAYER M5 ;
        RECT  70.272 0 70.296 0.192 ;
    END
  END i[388]
  PIN i[389]
    DIRECTION INPUT ;
    USE SIGNAL ;
    PORT
      LAYER M5 ;
        RECT  70.464 0 70.488 0.192 ;
    END
  END i[389]
  PIN i[38]
    DIRECTION INPUT ;
    USE SIGNAL ;
    PORT
      LAYER M5 ;
        RECT  10.752 0 10.776 0.192 ;
    END
  END i[38]
  PIN i[390]
    DIRECTION INPUT ;
    USE SIGNAL ;
    PORT
      LAYER M5 ;
        RECT  70.608 0 70.632 0.192 ;
    END
  END i[390]
  PIN i[391]
    DIRECTION INPUT ;
    USE SIGNAL ;
    PORT
      LAYER M5 ;
        RECT  70.8 0 70.824 0.192 ;
    END
  END i[391]
  PIN i[392]
    DIRECTION INPUT ;
    USE SIGNAL ;
    PORT
      LAYER M5 ;
        RECT  70.944 0 70.968 0.192 ;
    END
  END i[392]
  PIN i[393]
    DIRECTION INPUT ;
    USE SIGNAL ;
    PORT
      LAYER M5 ;
        RECT  71.136 0 71.16 0.192 ;
    END
  END i[393]
  PIN i[394]
    DIRECTION INPUT ;
    USE SIGNAL ;
    PORT
      LAYER M5 ;
        RECT  71.328 0 71.352 0.192 ;
    END
  END i[394]
  PIN i[395]
    DIRECTION INPUT ;
    USE SIGNAL ;
    PORT
      LAYER M5 ;
        RECT  71.472 0 71.496 0.192 ;
    END
  END i[395]
  PIN i[396]
    DIRECTION INPUT ;
    USE SIGNAL ;
    PORT
      LAYER M5 ;
        RECT  71.664 0 71.688 0.192 ;
    END
  END i[396]
  PIN i[397]
    DIRECTION INPUT ;
    USE SIGNAL ;
    PORT
      LAYER M5 ;
        RECT  71.808 0 71.832 0.192 ;
    END
  END i[397]
  PIN i[398]
    DIRECTION INPUT ;
    USE SIGNAL ;
    PORT
      LAYER M5 ;
        RECT  72 0 72.024 0.192 ;
    END
  END i[398]
  PIN i[399]
    DIRECTION INPUT ;
    USE SIGNAL ;
    PORT
      LAYER M5 ;
        RECT  72.144 0 72.168 0.192 ;
    END
  END i[399]
  PIN i[39]
    DIRECTION INPUT ;
    USE SIGNAL ;
    PORT
      LAYER M5 ;
        RECT  10.944 0 10.968 0.192 ;
    END
  END i[39]
  PIN i[3]
    DIRECTION INPUT ;
    USE SIGNAL ;
    PORT
      LAYER M5 ;
        RECT  4.8 0 4.824 0.192 ;
    END
  END i[3]
  PIN i[400]
    DIRECTION INPUT ;
    USE SIGNAL ;
    PORT
      LAYER M5 ;
        RECT  72.336 0 72.36 0.192 ;
    END
  END i[400]
  PIN i[401]
    DIRECTION INPUT ;
    USE SIGNAL ;
    PORT
      LAYER M5 ;
        RECT  72.48 0 72.504 0.192 ;
    END
  END i[401]
  PIN i[402]
    DIRECTION INPUT ;
    USE SIGNAL ;
    PORT
      LAYER M5 ;
        RECT  72.672 0 72.696 0.192 ;
    END
  END i[402]
  PIN i[403]
    DIRECTION INPUT ;
    USE SIGNAL ;
    PORT
      LAYER M5 ;
        RECT  72.816 0 72.84 0.192 ;
    END
  END i[403]
  PIN i[404]
    DIRECTION INPUT ;
    USE SIGNAL ;
    PORT
      LAYER M5 ;
        RECT  73.008 0 73.032 0.192 ;
    END
  END i[404]
  PIN i[405]
    DIRECTION INPUT ;
    USE SIGNAL ;
    PORT
      LAYER M5 ;
        RECT  73.152 0 73.176 0.192 ;
    END
  END i[405]
  PIN i[406]
    DIRECTION INPUT ;
    USE SIGNAL ;
    PORT
      LAYER M5 ;
        RECT  73.344 0 73.368 0.192 ;
    END
  END i[406]
  PIN i[407]
    DIRECTION INPUT ;
    USE SIGNAL ;
    PORT
      LAYER M5 ;
        RECT  73.488 0 73.512 0.192 ;
    END
  END i[407]
  PIN i[408]
    DIRECTION INPUT ;
    USE SIGNAL ;
    PORT
      LAYER M5 ;
        RECT  73.68 0 73.704 0.192 ;
    END
  END i[408]
  PIN i[409]
    DIRECTION INPUT ;
    USE SIGNAL ;
    PORT
      LAYER M5 ;
        RECT  73.872 0 73.896 0.192 ;
    END
  END i[409]
  PIN i[40]
    DIRECTION INPUT ;
    USE SIGNAL ;
    PORT
      LAYER M5 ;
        RECT  11.088 0 11.112 0.192 ;
    END
  END i[40]
  PIN i[410]
    DIRECTION INPUT ;
    USE SIGNAL ;
    PORT
      LAYER M5 ;
        RECT  74.016 0 74.04 0.192 ;
    END
  END i[410]
  PIN i[411]
    DIRECTION INPUT ;
    USE SIGNAL ;
    PORT
      LAYER M5 ;
        RECT  74.208 0 74.232 0.192 ;
    END
  END i[411]
  PIN i[412]
    DIRECTION INPUT ;
    USE SIGNAL ;
    PORT
      LAYER M5 ;
        RECT  74.352 0 74.376 0.192 ;
    END
  END i[412]
  PIN i[413]
    DIRECTION INPUT ;
    USE SIGNAL ;
    PORT
      LAYER M5 ;
        RECT  74.544 0 74.568 0.192 ;
    END
  END i[413]
  PIN i[414]
    DIRECTION INPUT ;
    USE SIGNAL ;
    PORT
      LAYER M5 ;
        RECT  74.688 0 74.712 0.192 ;
    END
  END i[414]
  PIN i[415]
    DIRECTION INPUT ;
    USE SIGNAL ;
    PORT
      LAYER M5 ;
        RECT  74.88 0 74.904 0.192 ;
    END
  END i[415]
  PIN i[416]
    DIRECTION INPUT ;
    USE SIGNAL ;
    PORT
      LAYER M5 ;
        RECT  75.024 0 75.048 0.192 ;
    END
  END i[416]
  PIN i[417]
    DIRECTION INPUT ;
    USE SIGNAL ;
    PORT
      LAYER M5 ;
        RECT  75.216 0 75.24 0.192 ;
    END
  END i[417]
  PIN i[418]
    DIRECTION INPUT ;
    USE SIGNAL ;
    PORT
      LAYER M5 ;
        RECT  75.36 0 75.384 0.192 ;
    END
  END i[418]
  PIN i[419]
    DIRECTION INPUT ;
    USE SIGNAL ;
    PORT
      LAYER M5 ;
        RECT  75.552 0 75.576 0.192 ;
    END
  END i[419]
  PIN i[41]
    DIRECTION INPUT ;
    USE SIGNAL ;
    PORT
      LAYER M5 ;
        RECT  11.28 0 11.304 0.192 ;
    END
  END i[41]
  PIN i[420]
    DIRECTION INPUT ;
    USE SIGNAL ;
    PORT
      LAYER M5 ;
        RECT  75.696 0 75.72 0.192 ;
    END
  END i[420]
  PIN i[421]
    DIRECTION INPUT ;
    USE SIGNAL ;
    PORT
      LAYER M5 ;
        RECT  75.888 0 75.912 0.192 ;
    END
  END i[421]
  PIN i[422]
    DIRECTION INPUT ;
    USE SIGNAL ;
    PORT
      LAYER M5 ;
        RECT  76.032 0 76.056 0.192 ;
    END
  END i[422]
  PIN i[423]
    DIRECTION INPUT ;
    USE SIGNAL ;
    PORT
      LAYER M5 ;
        RECT  76.224 0 76.248 0.192 ;
    END
  END i[423]
  PIN i[424]
    DIRECTION INPUT ;
    USE SIGNAL ;
    PORT
      LAYER M5 ;
        RECT  76.416 0 76.44 0.192 ;
    END
  END i[424]
  PIN i[425]
    DIRECTION INPUT ;
    USE SIGNAL ;
    PORT
      LAYER M5 ;
        RECT  76.56 0 76.584 0.192 ;
    END
  END i[425]
  PIN i[426]
    DIRECTION INPUT ;
    USE SIGNAL ;
    PORT
      LAYER M5 ;
        RECT  76.752 0 76.776 0.192 ;
    END
  END i[426]
  PIN i[427]
    DIRECTION INPUT ;
    USE SIGNAL ;
    PORT
      LAYER M5 ;
        RECT  76.896 0 76.92 0.192 ;
    END
  END i[427]
  PIN i[428]
    DIRECTION INPUT ;
    USE SIGNAL ;
    PORT
      LAYER M5 ;
        RECT  77.088 0 77.112 0.192 ;
    END
  END i[428]
  PIN i[429]
    DIRECTION INPUT ;
    USE SIGNAL ;
    PORT
      LAYER M5 ;
        RECT  77.232 0 77.256 0.192 ;
    END
  END i[429]
  PIN i[42]
    DIRECTION INPUT ;
    USE SIGNAL ;
    PORT
      LAYER M5 ;
        RECT  11.424 0 11.448 0.192 ;
    END
  END i[42]
  PIN i[430]
    DIRECTION INPUT ;
    USE SIGNAL ;
    PORT
      LAYER M5 ;
        RECT  77.424 0 77.448 0.192 ;
    END
  END i[430]
  PIN i[431]
    DIRECTION INPUT ;
    USE SIGNAL ;
    PORT
      LAYER M5 ;
        RECT  77.568 0 77.592 0.192 ;
    END
  END i[431]
  PIN i[432]
    DIRECTION INPUT ;
    USE SIGNAL ;
    PORT
      LAYER M5 ;
        RECT  77.76 0 77.784 0.192 ;
    END
  END i[432]
  PIN i[433]
    DIRECTION INPUT ;
    USE SIGNAL ;
    PORT
      LAYER M5 ;
        RECT  77.904 0 77.928 0.192 ;
    END
  END i[433]
  PIN i[434]
    DIRECTION INPUT ;
    USE SIGNAL ;
    PORT
      LAYER M5 ;
        RECT  78.096 0 78.12 0.192 ;
    END
  END i[434]
  PIN i[435]
    DIRECTION INPUT ;
    USE SIGNAL ;
    PORT
      LAYER M5 ;
        RECT  78.24 0 78.264 0.192 ;
    END
  END i[435]
  PIN i[436]
    DIRECTION INPUT ;
    USE SIGNAL ;
    PORT
      LAYER M5 ;
        RECT  78.432 0 78.456 0.192 ;
    END
  END i[436]
  PIN i[437]
    DIRECTION INPUT ;
    USE SIGNAL ;
    PORT
      LAYER M5 ;
        RECT  78.576 0 78.6 0.192 ;
    END
  END i[437]
  PIN i[438]
    DIRECTION INPUT ;
    USE SIGNAL ;
    PORT
      LAYER M5 ;
        RECT  78.768 0 78.792 0.192 ;
    END
  END i[438]
  PIN i[439]
    DIRECTION INPUT ;
    USE SIGNAL ;
    PORT
      LAYER M5 ;
        RECT  78.96 0 78.984 0.192 ;
    END
  END i[439]
  PIN i[43]
    DIRECTION INPUT ;
    USE SIGNAL ;
    PORT
      LAYER M5 ;
        RECT  11.616 0 11.64 0.192 ;
    END
  END i[43]
  PIN i[440]
    DIRECTION INPUT ;
    USE SIGNAL ;
    PORT
      LAYER M5 ;
        RECT  79.104 0 79.128 0.192 ;
    END
  END i[440]
  PIN i[441]
    DIRECTION INPUT ;
    USE SIGNAL ;
    PORT
      LAYER M5 ;
        RECT  79.296 0 79.32 0.192 ;
    END
  END i[441]
  PIN i[442]
    DIRECTION INPUT ;
    USE SIGNAL ;
    PORT
      LAYER M5 ;
        RECT  79.44 0 79.464 0.192 ;
    END
  END i[442]
  PIN i[443]
    DIRECTION INPUT ;
    USE SIGNAL ;
    PORT
      LAYER M5 ;
        RECT  79.632 0 79.656 0.192 ;
    END
  END i[443]
  PIN i[444]
    DIRECTION INPUT ;
    USE SIGNAL ;
    PORT
      LAYER M5 ;
        RECT  79.776 0 79.8 0.192 ;
    END
  END i[444]
  PIN i[445]
    DIRECTION INPUT ;
    USE SIGNAL ;
    PORT
      LAYER M5 ;
        RECT  79.968 0 79.992 0.192 ;
    END
  END i[445]
  PIN i[446]
    DIRECTION INPUT ;
    USE SIGNAL ;
    PORT
      LAYER M5 ;
        RECT  80.112 0 80.136 0.192 ;
    END
  END i[446]
  PIN i[447]
    DIRECTION INPUT ;
    USE SIGNAL ;
    PORT
      LAYER M5 ;
        RECT  80.304 0 80.328 0.192 ;
    END
  END i[447]
  PIN i[448]
    DIRECTION INPUT ;
    USE SIGNAL ;
    PORT
      LAYER M5 ;
        RECT  80.448 0 80.472 0.192 ;
    END
  END i[448]
  PIN i[449]
    DIRECTION INPUT ;
    USE SIGNAL ;
    PORT
      LAYER M5 ;
        RECT  80.64 0 80.664 0.192 ;
    END
  END i[449]
  PIN i[44]
    DIRECTION INPUT ;
    USE SIGNAL ;
    PORT
      LAYER M5 ;
        RECT  11.76 0 11.784 0.192 ;
    END
  END i[44]
  PIN i[450]
    DIRECTION INPUT ;
    USE SIGNAL ;
    PORT
      LAYER M5 ;
        RECT  80.784 0 80.808 0.192 ;
    END
  END i[450]
  PIN i[451]
    DIRECTION INPUT ;
    USE SIGNAL ;
    PORT
      LAYER M5 ;
        RECT  80.976 0 81 0.192 ;
    END
  END i[451]
  PIN i[452]
    DIRECTION INPUT ;
    USE SIGNAL ;
    PORT
      LAYER M5 ;
        RECT  81.12 0 81.144 0.192 ;
    END
  END i[452]
  PIN i[453]
    DIRECTION INPUT ;
    USE SIGNAL ;
    PORT
      LAYER M5 ;
        RECT  81.312 0 81.336 0.192 ;
    END
  END i[453]
  PIN i[454]
    DIRECTION INPUT ;
    USE SIGNAL ;
    PORT
      LAYER M5 ;
        RECT  81.504 0 81.528 0.192 ;
    END
  END i[454]
  PIN i[455]
    DIRECTION INPUT ;
    USE SIGNAL ;
    PORT
      LAYER M5 ;
        RECT  81.648 0 81.672 0.192 ;
    END
  END i[455]
  PIN i[456]
    DIRECTION INPUT ;
    USE SIGNAL ;
    PORT
      LAYER M5 ;
        RECT  81.84 0 81.864 0.192 ;
    END
  END i[456]
  PIN i[457]
    DIRECTION INPUT ;
    USE SIGNAL ;
    PORT
      LAYER M5 ;
        RECT  81.984 0 82.008 0.192 ;
    END
  END i[457]
  PIN i[458]
    DIRECTION INPUT ;
    USE SIGNAL ;
    PORT
      LAYER M5 ;
        RECT  82.176 0 82.2 0.192 ;
    END
  END i[458]
  PIN i[459]
    DIRECTION INPUT ;
    USE SIGNAL ;
    PORT
      LAYER M5 ;
        RECT  82.32 0 82.344 0.192 ;
    END
  END i[459]
  PIN i[45]
    DIRECTION INPUT ;
    USE SIGNAL ;
    PORT
      LAYER M5 ;
        RECT  11.952 0 11.976 0.192 ;
    END
  END i[45]
  PIN i[460]
    DIRECTION INPUT ;
    USE SIGNAL ;
    PORT
      LAYER M5 ;
        RECT  82.512 0 82.536 0.192 ;
    END
  END i[460]
  PIN i[461]
    DIRECTION INPUT ;
    USE SIGNAL ;
    PORT
      LAYER M5 ;
        RECT  82.656 0 82.68 0.192 ;
    END
  END i[461]
  PIN i[462]
    DIRECTION INPUT ;
    USE SIGNAL ;
    PORT
      LAYER M5 ;
        RECT  82.848 0 82.872 0.192 ;
    END
  END i[462]
  PIN i[463]
    DIRECTION INPUT ;
    USE SIGNAL ;
    PORT
      LAYER M5 ;
        RECT  82.992 0 83.016 0.192 ;
    END
  END i[463]
  PIN i[464]
    DIRECTION INPUT ;
    USE SIGNAL ;
    PORT
      LAYER M5 ;
        RECT  83.184 0 83.208 0.192 ;
    END
  END i[464]
  PIN i[465]
    DIRECTION INPUT ;
    USE SIGNAL ;
    PORT
      LAYER M5 ;
        RECT  83.328 0 83.352 0.192 ;
    END
  END i[465]
  PIN i[466]
    DIRECTION INPUT ;
    USE SIGNAL ;
    PORT
      LAYER M5 ;
        RECT  83.52 0 83.544 0.192 ;
    END
  END i[466]
  PIN i[467]
    DIRECTION INPUT ;
    USE SIGNAL ;
    PORT
      LAYER M5 ;
        RECT  83.664 0 83.688 0.192 ;
    END
  END i[467]
  PIN i[468]
    DIRECTION INPUT ;
    USE SIGNAL ;
    PORT
      LAYER M5 ;
        RECT  83.856 0 83.88 0.192 ;
    END
  END i[468]
  PIN i[469]
    DIRECTION INPUT ;
    USE SIGNAL ;
    PORT
      LAYER M5 ;
        RECT  84.048 0 84.072 0.192 ;
    END
  END i[469]
  PIN i[46]
    DIRECTION INPUT ;
    USE SIGNAL ;
    PORT
      LAYER M5 ;
        RECT  12.096 0 12.12 0.192 ;
    END
  END i[46]
  PIN i[470]
    DIRECTION INPUT ;
    USE SIGNAL ;
    PORT
      LAYER M5 ;
        RECT  84.192 0 84.216 0.192 ;
    END
  END i[470]
  PIN i[471]
    DIRECTION INPUT ;
    USE SIGNAL ;
    PORT
      LAYER M5 ;
        RECT  84.384 0 84.408 0.192 ;
    END
  END i[471]
  PIN i[472]
    DIRECTION INPUT ;
    USE SIGNAL ;
    PORT
      LAYER M5 ;
        RECT  84.528 0 84.552 0.192 ;
    END
  END i[472]
  PIN i[473]
    DIRECTION INPUT ;
    USE SIGNAL ;
    PORT
      LAYER M5 ;
        RECT  84.72 0 84.744 0.192 ;
    END
  END i[473]
  PIN i[474]
    DIRECTION INPUT ;
    USE SIGNAL ;
    PORT
      LAYER M5 ;
        RECT  84.864 0 84.888 0.192 ;
    END
  END i[474]
  PIN i[475]
    DIRECTION INPUT ;
    USE SIGNAL ;
    PORT
      LAYER M5 ;
        RECT  85.056 0 85.08 0.192 ;
    END
  END i[475]
  PIN i[476]
    DIRECTION INPUT ;
    USE SIGNAL ;
    PORT
      LAYER M5 ;
        RECT  85.2 0 85.224 0.192 ;
    END
  END i[476]
  PIN i[477]
    DIRECTION INPUT ;
    USE SIGNAL ;
    PORT
      LAYER M5 ;
        RECT  85.392 0 85.416 0.192 ;
    END
  END i[477]
  PIN i[478]
    DIRECTION INPUT ;
    USE SIGNAL ;
    PORT
      LAYER M5 ;
        RECT  85.536 0 85.56 0.192 ;
    END
  END i[478]
  PIN i[479]
    DIRECTION INPUT ;
    USE SIGNAL ;
    PORT
      LAYER M5 ;
        RECT  85.728 0 85.752 0.192 ;
    END
  END i[479]
  PIN i[47]
    DIRECTION INPUT ;
    USE SIGNAL ;
    PORT
      LAYER M5 ;
        RECT  12.288 0 12.312 0.192 ;
    END
  END i[47]
  PIN i[480]
    DIRECTION INPUT ;
    USE SIGNAL ;
    PORT
      LAYER M5 ;
        RECT  85.872 0 85.896 0.192 ;
    END
  END i[480]
  PIN i[481]
    DIRECTION INPUT ;
    USE SIGNAL ;
    PORT
      LAYER M5 ;
        RECT  86.064 0 86.088 0.192 ;
    END
  END i[481]
  PIN i[482]
    DIRECTION INPUT ;
    USE SIGNAL ;
    PORT
      LAYER M5 ;
        RECT  86.256 0 86.28 0.192 ;
    END
  END i[482]
  PIN i[483]
    DIRECTION INPUT ;
    USE SIGNAL ;
    PORT
      LAYER M5 ;
        RECT  86.4 0 86.424 0.192 ;
    END
  END i[483]
  PIN i[484]
    DIRECTION INPUT ;
    USE SIGNAL ;
    PORT
      LAYER M5 ;
        RECT  86.592 0 86.616 0.192 ;
    END
  END i[484]
  PIN i[485]
    DIRECTION INPUT ;
    USE SIGNAL ;
    PORT
      LAYER M5 ;
        RECT  86.736 0 86.76 0.192 ;
    END
  END i[485]
  PIN i[486]
    DIRECTION INPUT ;
    USE SIGNAL ;
    PORT
      LAYER M5 ;
        RECT  86.928 0 86.952 0.192 ;
    END
  END i[486]
  PIN i[487]
    DIRECTION INPUT ;
    USE SIGNAL ;
    PORT
      LAYER M5 ;
        RECT  87.072 0 87.096 0.192 ;
    END
  END i[487]
  PIN i[488]
    DIRECTION INPUT ;
    USE SIGNAL ;
    PORT
      LAYER M5 ;
        RECT  87.264 0 87.288 0.192 ;
    END
  END i[488]
  PIN i[489]
    DIRECTION INPUT ;
    USE SIGNAL ;
    PORT
      LAYER M5 ;
        RECT  87.408 0 87.432 0.192 ;
    END
  END i[489]
  PIN i[48]
    DIRECTION INPUT ;
    USE SIGNAL ;
    PORT
      LAYER M5 ;
        RECT  12.432 0 12.456 0.192 ;
    END
  END i[48]
  PIN i[490]
    DIRECTION INPUT ;
    USE SIGNAL ;
    PORT
      LAYER M5 ;
        RECT  87.6 0 87.624 0.192 ;
    END
  END i[490]
  PIN i[491]
    DIRECTION INPUT ;
    USE SIGNAL ;
    PORT
      LAYER M5 ;
        RECT  87.744 0 87.768 0.192 ;
    END
  END i[491]
  PIN i[492]
    DIRECTION INPUT ;
    USE SIGNAL ;
    PORT
      LAYER M5 ;
        RECT  87.936 0 87.96 0.192 ;
    END
  END i[492]
  PIN i[493]
    DIRECTION INPUT ;
    USE SIGNAL ;
    PORT
      LAYER M5 ;
        RECT  88.08 0 88.104 0.192 ;
    END
  END i[493]
  PIN i[494]
    DIRECTION INPUT ;
    USE SIGNAL ;
    PORT
      LAYER M5 ;
        RECT  88.272 0 88.296 0.192 ;
    END
  END i[494]
  PIN i[495]
    DIRECTION INPUT ;
    USE SIGNAL ;
    PORT
      LAYER M5 ;
        RECT  88.416 0 88.44 0.192 ;
    END
  END i[495]
  PIN i[496]
    DIRECTION INPUT ;
    USE SIGNAL ;
    PORT
      LAYER M5 ;
        RECT  88.608 0 88.632 0.192 ;
    END
  END i[496]
  PIN i[497]
    DIRECTION INPUT ;
    USE SIGNAL ;
    PORT
      LAYER M5 ;
        RECT  88.8 0 88.824 0.192 ;
    END
  END i[497]
  PIN i[498]
    DIRECTION INPUT ;
    USE SIGNAL ;
    PORT
      LAYER M5 ;
        RECT  88.944 0 88.968 0.192 ;
    END
  END i[498]
  PIN i[499]
    DIRECTION INPUT ;
    USE SIGNAL ;
    PORT
      LAYER M5 ;
        RECT  89.136 0 89.16 0.192 ;
    END
  END i[499]
  PIN i[49]
    DIRECTION INPUT ;
    USE SIGNAL ;
    PORT
      LAYER M5 ;
        RECT  12.624 0 12.648 0.192 ;
    END
  END i[49]
  PIN i[4]
    DIRECTION INPUT ;
    USE SIGNAL ;
    PORT
      LAYER M5 ;
        RECT  4.992 0 5.016 0.192 ;
    END
  END i[4]
  PIN i[500]
    DIRECTION INPUT ;
    USE SIGNAL ;
    PORT
      LAYER M5 ;
        RECT  89.28 0 89.304 0.192 ;
    END
  END i[500]
  PIN i[501]
    DIRECTION INPUT ;
    USE SIGNAL ;
    PORT
      LAYER M5 ;
        RECT  89.472 0 89.496 0.192 ;
    END
  END i[501]
  PIN i[502]
    DIRECTION INPUT ;
    USE SIGNAL ;
    PORT
      LAYER M5 ;
        RECT  89.616 0 89.64 0.192 ;
    END
  END i[502]
  PIN i[503]
    DIRECTION INPUT ;
    USE SIGNAL ;
    PORT
      LAYER M5 ;
        RECT  89.808 0 89.832 0.192 ;
    END
  END i[503]
  PIN i[504]
    DIRECTION INPUT ;
    USE SIGNAL ;
    PORT
      LAYER M5 ;
        RECT  89.952 0 89.976 0.192 ;
    END
  END i[504]
  PIN i[505]
    DIRECTION INPUT ;
    USE SIGNAL ;
    PORT
      LAYER M5 ;
        RECT  90.144 0 90.168 0.192 ;
    END
  END i[505]
  PIN i[506]
    DIRECTION INPUT ;
    USE SIGNAL ;
    PORT
      LAYER M5 ;
        RECT  90.288 0 90.312 0.192 ;
    END
  END i[506]
  PIN i[507]
    DIRECTION INPUT ;
    USE SIGNAL ;
    PORT
      LAYER M5 ;
        RECT  90.48 0 90.504 0.192 ;
    END
  END i[507]
  PIN i[508]
    DIRECTION INPUT ;
    USE SIGNAL ;
    PORT
      LAYER M5 ;
        RECT  90.624 0 90.648 0.192 ;
    END
  END i[508]
  PIN i[509]
    DIRECTION INPUT ;
    USE SIGNAL ;
    PORT
      LAYER M5 ;
        RECT  90.816 0 90.84 0.192 ;
    END
  END i[509]
  PIN i[50]
    DIRECTION INPUT ;
    USE SIGNAL ;
    PORT
      LAYER M5 ;
        RECT  12.768 0 12.792 0.192 ;
    END
  END i[50]
  PIN i[510]
    DIRECTION INPUT ;
    USE SIGNAL ;
    PORT
      LAYER M5 ;
        RECT  90.96 0 90.984 0.192 ;
    END
  END i[510]
  PIN i[511]
    DIRECTION INPUT ;
    USE SIGNAL ;
    PORT
      LAYER M5 ;
        RECT  91.152 0 91.176 0.192 ;
    END
  END i[511]
  PIN i[512]
    DIRECTION INPUT ;
    USE SIGNAL ;
    PORT
      LAYER M5 ;
        RECT  91.344 0 91.368 0.192 ;
    END
  END i[512]
  PIN i[513]
    DIRECTION INPUT ;
    USE SIGNAL ;
    PORT
      LAYER M5 ;
        RECT  91.488 0 91.512 0.192 ;
    END
  END i[513]
  PIN i[514]
    DIRECTION INPUT ;
    USE SIGNAL ;
    PORT
      LAYER M5 ;
        RECT  91.68 0 91.704 0.192 ;
    END
  END i[514]
  PIN i[515]
    DIRECTION INPUT ;
    USE SIGNAL ;
    PORT
      LAYER M5 ;
        RECT  91.824 0 91.848 0.192 ;
    END
  END i[515]
  PIN i[516]
    DIRECTION INPUT ;
    USE SIGNAL ;
    PORT
      LAYER M5 ;
        RECT  92.016 0 92.04 0.192 ;
    END
  END i[516]
  PIN i[517]
    DIRECTION INPUT ;
    USE SIGNAL ;
    PORT
      LAYER M5 ;
        RECT  92.16 0 92.184 0.192 ;
    END
  END i[517]
  PIN i[518]
    DIRECTION INPUT ;
    USE SIGNAL ;
    PORT
      LAYER M5 ;
        RECT  92.352 0 92.376 0.192 ;
    END
  END i[518]
  PIN i[519]
    DIRECTION INPUT ;
    USE SIGNAL ;
    PORT
      LAYER M5 ;
        RECT  92.496 0 92.52 0.192 ;
    END
  END i[519]
  PIN i[51]
    DIRECTION INPUT ;
    USE SIGNAL ;
    PORT
      LAYER M5 ;
        RECT  12.96 0 12.984 0.192 ;
    END
  END i[51]
  PIN i[520]
    DIRECTION INPUT ;
    USE SIGNAL ;
    PORT
      LAYER M5 ;
        RECT  92.688 0 92.712 0.192 ;
    END
  END i[520]
  PIN i[521]
    DIRECTION INPUT ;
    USE SIGNAL ;
    PORT
      LAYER M5 ;
        RECT  92.832 0 92.856 0.192 ;
    END
  END i[521]
  PIN i[522]
    DIRECTION INPUT ;
    USE SIGNAL ;
    PORT
      LAYER M5 ;
        RECT  93.024 0 93.048 0.192 ;
    END
  END i[522]
  PIN i[523]
    DIRECTION INPUT ;
    USE SIGNAL ;
    PORT
      LAYER M5 ;
        RECT  93.168 0 93.192 0.192 ;
    END
  END i[523]
  PIN i[524]
    DIRECTION INPUT ;
    USE SIGNAL ;
    PORT
      LAYER M5 ;
        RECT  93.36 0 93.384 0.192 ;
    END
  END i[524]
  PIN i[525]
    DIRECTION INPUT ;
    USE SIGNAL ;
    PORT
      LAYER M5 ;
        RECT  93.504 0 93.528 0.192 ;
    END
  END i[525]
  PIN i[526]
    DIRECTION INPUT ;
    USE SIGNAL ;
    PORT
      LAYER M5 ;
        RECT  93.696 0 93.72 0.192 ;
    END
  END i[526]
  PIN i[527]
    DIRECTION INPUT ;
    USE SIGNAL ;
    PORT
      LAYER M5 ;
        RECT  93.888 0 93.912 0.192 ;
    END
  END i[527]
  PIN i[528]
    DIRECTION INPUT ;
    USE SIGNAL ;
    PORT
      LAYER M5 ;
        RECT  94.032 0 94.056 0.192 ;
    END
  END i[528]
  PIN i[529]
    DIRECTION INPUT ;
    USE SIGNAL ;
    PORT
      LAYER M5 ;
        RECT  94.224 0 94.248 0.192 ;
    END
  END i[529]
  PIN i[52]
    DIRECTION INPUT ;
    USE SIGNAL ;
    PORT
      LAYER M5 ;
        RECT  13.152 0 13.176 0.192 ;
    END
  END i[52]
  PIN i[530]
    DIRECTION INPUT ;
    USE SIGNAL ;
    PORT
      LAYER M5 ;
        RECT  94.368 0 94.392 0.192 ;
    END
  END i[530]
  PIN i[531]
    DIRECTION INPUT ;
    USE SIGNAL ;
    PORT
      LAYER M5 ;
        RECT  94.56 0 94.584 0.192 ;
    END
  END i[531]
  PIN i[532]
    DIRECTION INPUT ;
    USE SIGNAL ;
    PORT
      LAYER M5 ;
        RECT  94.704 0 94.728 0.192 ;
    END
  END i[532]
  PIN i[533]
    DIRECTION INPUT ;
    USE SIGNAL ;
    PORT
      LAYER M5 ;
        RECT  94.896 0 94.92 0.192 ;
    END
  END i[533]
  PIN i[534]
    DIRECTION INPUT ;
    USE SIGNAL ;
    PORT
      LAYER M5 ;
        RECT  95.04 0 95.064 0.192 ;
    END
  END i[534]
  PIN i[535]
    DIRECTION INPUT ;
    USE SIGNAL ;
    PORT
      LAYER M5 ;
        RECT  95.232 0 95.256 0.192 ;
    END
  END i[535]
  PIN i[536]
    DIRECTION INPUT ;
    USE SIGNAL ;
    PORT
      LAYER M5 ;
        RECT  95.376 0 95.4 0.192 ;
    END
  END i[536]
  PIN i[537]
    DIRECTION INPUT ;
    USE SIGNAL ;
    PORT
      LAYER M5 ;
        RECT  95.568 0 95.592 0.192 ;
    END
  END i[537]
  PIN i[538]
    DIRECTION INPUT ;
    USE SIGNAL ;
    PORT
      LAYER M5 ;
        RECT  95.712 0 95.736 0.192 ;
    END
  END i[538]
  PIN i[539]
    DIRECTION INPUT ;
    USE SIGNAL ;
    PORT
      LAYER M5 ;
        RECT  95.904 0 95.928 0.192 ;
    END
  END i[539]
  PIN i[53]
    DIRECTION INPUT ;
    USE SIGNAL ;
    PORT
      LAYER M5 ;
        RECT  13.296 0 13.32 0.192 ;
    END
  END i[53]
  PIN i[540]
    DIRECTION INPUT ;
    USE SIGNAL ;
    PORT
      LAYER M5 ;
        RECT  96.048 0 96.072 0.192 ;
    END
  END i[540]
  PIN i[541]
    DIRECTION INPUT ;
    USE SIGNAL ;
    PORT
      LAYER M5 ;
        RECT  96.24 0 96.264 0.192 ;
    END
  END i[541]
  PIN i[542]
    DIRECTION INPUT ;
    USE SIGNAL ;
    PORT
      LAYER M5 ;
        RECT  96.432 0 96.456 0.192 ;
    END
  END i[542]
  PIN i[543]
    DIRECTION INPUT ;
    USE SIGNAL ;
    PORT
      LAYER M5 ;
        RECT  96.576 0 96.6 0.192 ;
    END
  END i[543]
  PIN i[544]
    DIRECTION INPUT ;
    USE SIGNAL ;
    PORT
      LAYER M5 ;
        RECT  96.768 0 96.792 0.192 ;
    END
  END i[544]
  PIN i[545]
    DIRECTION INPUT ;
    USE SIGNAL ;
    PORT
      LAYER M5 ;
        RECT  96.912 0 96.936 0.192 ;
    END
  END i[545]
  PIN i[546]
    DIRECTION INPUT ;
    USE SIGNAL ;
    PORT
      LAYER M5 ;
        RECT  97.104 0 97.128 0.192 ;
    END
  END i[546]
  PIN i[547]
    DIRECTION INPUT ;
    USE SIGNAL ;
    PORT
      LAYER M5 ;
        RECT  97.248 0 97.272 0.192 ;
    END
  END i[547]
  PIN i[548]
    DIRECTION INPUT ;
    USE SIGNAL ;
    PORT
      LAYER M5 ;
        RECT  97.44 0 97.464 0.192 ;
    END
  END i[548]
  PIN i[549]
    DIRECTION INPUT ;
    USE SIGNAL ;
    PORT
      LAYER M5 ;
        RECT  97.584 0 97.608 0.192 ;
    END
  END i[549]
  PIN i[54]
    DIRECTION INPUT ;
    USE SIGNAL ;
    PORT
      LAYER M5 ;
        RECT  13.488 0 13.512 0.192 ;
    END
  END i[54]
  PIN i[550]
    DIRECTION INPUT ;
    USE SIGNAL ;
    PORT
      LAYER M5 ;
        RECT  97.776 0 97.8 0.192 ;
    END
  END i[550]
  PIN i[551]
    DIRECTION INPUT ;
    USE SIGNAL ;
    PORT
      LAYER M5 ;
        RECT  97.92 0 97.944 0.192 ;
    END
  END i[551]
  PIN i[552]
    DIRECTION INPUT ;
    USE SIGNAL ;
    PORT
      LAYER M5 ;
        RECT  98.112 0 98.136 0.192 ;
    END
  END i[552]
  PIN i[553]
    DIRECTION INPUT ;
    USE SIGNAL ;
    PORT
      LAYER M5 ;
        RECT  98.256 0 98.28 0.192 ;
    END
  END i[553]
  PIN i[554]
    DIRECTION INPUT ;
    USE SIGNAL ;
    PORT
      LAYER M5 ;
        RECT  98.448 0 98.472 0.192 ;
    END
  END i[554]
  PIN i[555]
    DIRECTION INPUT ;
    USE SIGNAL ;
    PORT
      LAYER M5 ;
        RECT  98.592 0 98.616 0.192 ;
    END
  END i[555]
  PIN i[556]
    DIRECTION INPUT ;
    USE SIGNAL ;
    PORT
      LAYER M5 ;
        RECT  98.784 0 98.808 0.192 ;
    END
  END i[556]
  PIN i[557]
    DIRECTION INPUT ;
    USE SIGNAL ;
    PORT
      LAYER M5 ;
        RECT  98.976 0 99 0.192 ;
    END
  END i[557]
  PIN i[558]
    DIRECTION INPUT ;
    USE SIGNAL ;
    PORT
      LAYER M5 ;
        RECT  99.12 0 99.144 0.192 ;
    END
  END i[558]
  PIN i[559]
    DIRECTION INPUT ;
    USE SIGNAL ;
    PORT
      LAYER M5 ;
        RECT  99.312 0 99.336 0.192 ;
    END
  END i[559]
  PIN i[55]
    DIRECTION INPUT ;
    USE SIGNAL ;
    PORT
      LAYER M5 ;
        RECT  13.632 0 13.656 0.192 ;
    END
  END i[55]
  PIN i[560]
    DIRECTION INPUT ;
    USE SIGNAL ;
    PORT
      LAYER M5 ;
        RECT  99.456 0 99.48 0.192 ;
    END
  END i[560]
  PIN i[561]
    DIRECTION INPUT ;
    USE SIGNAL ;
    PORT
      LAYER M5 ;
        RECT  99.648 0 99.672 0.192 ;
    END
  END i[561]
  PIN i[562]
    DIRECTION INPUT ;
    USE SIGNAL ;
    PORT
      LAYER M5 ;
        RECT  99.792 0 99.816 0.192 ;
    END
  END i[562]
  PIN i[563]
    DIRECTION INPUT ;
    USE SIGNAL ;
    PORT
      LAYER M5 ;
        RECT  99.984 0 100.008 0.192 ;
    END
  END i[563]
  PIN i[564]
    DIRECTION INPUT ;
    USE SIGNAL ;
    PORT
      LAYER M5 ;
        RECT  100.128 0 100.152 0.192 ;
    END
  END i[564]
  PIN i[565]
    DIRECTION INPUT ;
    USE SIGNAL ;
    PORT
      LAYER M5 ;
        RECT  100.32 0 100.344 0.192 ;
    END
  END i[565]
  PIN i[566]
    DIRECTION INPUT ;
    USE SIGNAL ;
    PORT
      LAYER M5 ;
        RECT  100.464 0 100.488 0.192 ;
    END
  END i[566]
  PIN i[567]
    DIRECTION INPUT ;
    USE SIGNAL ;
    PORT
      LAYER M5 ;
        RECT  100.656 0 100.68 0.192 ;
    END
  END i[567]
  PIN i[568]
    DIRECTION INPUT ;
    USE SIGNAL ;
    PORT
      LAYER M5 ;
        RECT  100.8 0 100.824 0.192 ;
    END
  END i[568]
  PIN i[569]
    DIRECTION INPUT ;
    USE SIGNAL ;
    PORT
      LAYER M5 ;
        RECT  100.992 0 101.016 0.192 ;
    END
  END i[569]
  PIN i[56]
    DIRECTION INPUT ;
    USE SIGNAL ;
    PORT
      LAYER M5 ;
        RECT  13.824 0 13.848 0.192 ;
    END
  END i[56]
  PIN i[570]
    DIRECTION INPUT ;
    USE SIGNAL ;
    PORT
      LAYER M5 ;
        RECT  101.136 0 101.16 0.192 ;
    END
  END i[570]
  PIN i[571]
    DIRECTION INPUT ;
    USE SIGNAL ;
    PORT
      LAYER M5 ;
        RECT  101.328 0 101.352 0.192 ;
    END
  END i[571]
  PIN i[572]
    DIRECTION INPUT ;
    USE SIGNAL ;
    PORT
      LAYER M5 ;
        RECT  101.52 0 101.544 0.192 ;
    END
  END i[572]
  PIN i[573]
    DIRECTION INPUT ;
    USE SIGNAL ;
    PORT
      LAYER M5 ;
        RECT  101.664 0 101.688 0.192 ;
    END
  END i[573]
  PIN i[574]
    DIRECTION INPUT ;
    USE SIGNAL ;
    PORT
      LAYER M5 ;
        RECT  101.856 0 101.88 0.192 ;
    END
  END i[574]
  PIN i[575]
    DIRECTION INPUT ;
    USE SIGNAL ;
    PORT
      LAYER M5 ;
        RECT  102 0 102.024 0.192 ;
    END
  END i[575]
  PIN i[576]
    DIRECTION INPUT ;
    USE SIGNAL ;
    PORT
      LAYER M5 ;
        RECT  102.192 0 102.216 0.192 ;
    END
  END i[576]
  PIN i[577]
    DIRECTION INPUT ;
    USE SIGNAL ;
    PORT
      LAYER M5 ;
        RECT  102.336 0 102.36 0.192 ;
    END
  END i[577]
  PIN i[578]
    DIRECTION INPUT ;
    USE SIGNAL ;
    PORT
      LAYER M5 ;
        RECT  102.528 0 102.552 0.192 ;
    END
  END i[578]
  PIN i[579]
    DIRECTION INPUT ;
    USE SIGNAL ;
    PORT
      LAYER M5 ;
        RECT  102.672 0 102.696 0.192 ;
    END
  END i[579]
  PIN i[57]
    DIRECTION INPUT ;
    USE SIGNAL ;
    PORT
      LAYER M5 ;
        RECT  13.968 0 13.992 0.192 ;
    END
  END i[57]
  PIN i[580]
    DIRECTION INPUT ;
    USE SIGNAL ;
    PORT
      LAYER M5 ;
        RECT  102.864 0 102.888 0.192 ;
    END
  END i[580]
  PIN i[581]
    DIRECTION INPUT ;
    USE SIGNAL ;
    PORT
      LAYER M5 ;
        RECT  103.008 0 103.032 0.192 ;
    END
  END i[581]
  PIN i[582]
    DIRECTION INPUT ;
    USE SIGNAL ;
    PORT
      LAYER M5 ;
        RECT  103.2 0 103.224 0.192 ;
    END
  END i[582]
  PIN i[583]
    DIRECTION INPUT ;
    USE SIGNAL ;
    PORT
      LAYER M5 ;
        RECT  103.344 0 103.368 0.192 ;
    END
  END i[583]
  PIN i[584]
    DIRECTION INPUT ;
    USE SIGNAL ;
    PORT
      LAYER M5 ;
        RECT  103.536 0 103.56 0.192 ;
    END
  END i[584]
  PIN i[585]
    DIRECTION INPUT ;
    USE SIGNAL ;
    PORT
      LAYER M5 ;
        RECT  103.68 0 103.704 0.192 ;
    END
  END i[585]
  PIN i[586]
    DIRECTION INPUT ;
    USE SIGNAL ;
    PORT
      LAYER M5 ;
        RECT  103.872 0 103.896 0.192 ;
    END
  END i[586]
  PIN i[587]
    DIRECTION INPUT ;
    USE SIGNAL ;
    PORT
      LAYER M5 ;
        RECT  104.064 0 104.088 0.192 ;
    END
  END i[587]
  PIN i[588]
    DIRECTION INPUT ;
    USE SIGNAL ;
    PORT
      LAYER M5 ;
        RECT  104.208 0 104.232 0.192 ;
    END
  END i[588]
  PIN i[589]
    DIRECTION INPUT ;
    USE SIGNAL ;
    PORT
      LAYER M5 ;
        RECT  104.4 0 104.424 0.192 ;
    END
  END i[589]
  PIN i[58]
    DIRECTION INPUT ;
    USE SIGNAL ;
    PORT
      LAYER M5 ;
        RECT  14.16 0 14.184 0.192 ;
    END
  END i[58]
  PIN i[590]
    DIRECTION INPUT ;
    USE SIGNAL ;
    PORT
      LAYER M5 ;
        RECT  104.544 0 104.568 0.192 ;
    END
  END i[590]
  PIN i[591]
    DIRECTION INPUT ;
    USE SIGNAL ;
    PORT
      LAYER M5 ;
        RECT  104.736 0 104.76 0.192 ;
    END
  END i[591]
  PIN i[592]
    DIRECTION INPUT ;
    USE SIGNAL ;
    PORT
      LAYER M5 ;
        RECT  104.88 0 104.904 0.192 ;
    END
  END i[592]
  PIN i[593]
    DIRECTION INPUT ;
    USE SIGNAL ;
    PORT
      LAYER M5 ;
        RECT  105.072 0 105.096 0.192 ;
    END
  END i[593]
  PIN i[594]
    DIRECTION INPUT ;
    USE SIGNAL ;
    PORT
      LAYER M5 ;
        RECT  105.216 0 105.24 0.192 ;
    END
  END i[594]
  PIN i[595]
    DIRECTION INPUT ;
    USE SIGNAL ;
    PORT
      LAYER M5 ;
        RECT  105.408 0 105.432 0.192 ;
    END
  END i[595]
  PIN i[596]
    DIRECTION INPUT ;
    USE SIGNAL ;
    PORT
      LAYER M5 ;
        RECT  105.552 0 105.576 0.192 ;
    END
  END i[596]
  PIN i[597]
    DIRECTION INPUT ;
    USE SIGNAL ;
    PORT
      LAYER M5 ;
        RECT  105.744 0 105.768 0.192 ;
    END
  END i[597]
  PIN i[598]
    DIRECTION INPUT ;
    USE SIGNAL ;
    PORT
      LAYER M5 ;
        RECT  105.888 0 105.912 0.192 ;
    END
  END i[598]
  PIN i[599]
    DIRECTION INPUT ;
    USE SIGNAL ;
    PORT
      LAYER M5 ;
        RECT  106.08 0 106.104 0.192 ;
    END
  END i[599]
  PIN i[59]
    DIRECTION INPUT ;
    USE SIGNAL ;
    PORT
      LAYER M5 ;
        RECT  14.304 0 14.328 0.192 ;
    END
  END i[59]
  PIN i[5]
    DIRECTION INPUT ;
    USE SIGNAL ;
    PORT
      LAYER M5 ;
        RECT  5.136 0 5.16 0.192 ;
    END
  END i[5]
  PIN i[600]
    DIRECTION INPUT ;
    USE SIGNAL ;
    PORT
      LAYER M5 ;
        RECT  106.224 0 106.248 0.192 ;
    END
  END i[600]
  PIN i[601]
    DIRECTION INPUT ;
    USE SIGNAL ;
    PORT
      LAYER M5 ;
        RECT  106.416 0 106.44 0.192 ;
    END
  END i[601]
  PIN i[602]
    DIRECTION INPUT ;
    USE SIGNAL ;
    PORT
      LAYER M5 ;
        RECT  106.608 0 106.632 0.192 ;
    END
  END i[602]
  PIN i[603]
    DIRECTION INPUT ;
    USE SIGNAL ;
    PORT
      LAYER M5 ;
        RECT  106.752 0 106.776 0.192 ;
    END
  END i[603]
  PIN i[604]
    DIRECTION INPUT ;
    USE SIGNAL ;
    PORT
      LAYER M5 ;
        RECT  106.944 0 106.968 0.192 ;
    END
  END i[604]
  PIN i[605]
    DIRECTION INPUT ;
    USE SIGNAL ;
    PORT
      LAYER M5 ;
        RECT  107.088 0 107.112 0.192 ;
    END
  END i[605]
  PIN i[606]
    DIRECTION INPUT ;
    USE SIGNAL ;
    PORT
      LAYER M5 ;
        RECT  107.28 0 107.304 0.192 ;
    END
  END i[606]
  PIN i[607]
    DIRECTION INPUT ;
    USE SIGNAL ;
    PORT
      LAYER M5 ;
        RECT  107.424 0 107.448 0.192 ;
    END
  END i[607]
  PIN i[608]
    DIRECTION INPUT ;
    USE SIGNAL ;
    PORT
      LAYER M5 ;
        RECT  107.616 0 107.64 0.192 ;
    END
  END i[608]
  PIN i[609]
    DIRECTION INPUT ;
    USE SIGNAL ;
    PORT
      LAYER M5 ;
        RECT  107.76 0 107.784 0.192 ;
    END
  END i[609]
  PIN i[60]
    DIRECTION INPUT ;
    USE SIGNAL ;
    PORT
      LAYER M5 ;
        RECT  14.496 0 14.52 0.192 ;
    END
  END i[60]
  PIN i[610]
    DIRECTION INPUT ;
    USE SIGNAL ;
    PORT
      LAYER M5 ;
        RECT  107.952 0 107.976 0.192 ;
    END
  END i[610]
  PIN i[611]
    DIRECTION INPUT ;
    USE SIGNAL ;
    PORT
      LAYER M5 ;
        RECT  108.096 0 108.12 0.192 ;
    END
  END i[611]
  PIN i[612]
    DIRECTION INPUT ;
    USE SIGNAL ;
    PORT
      LAYER M5 ;
        RECT  108.288 0 108.312 0.192 ;
    END
  END i[612]
  PIN i[613]
    DIRECTION INPUT ;
    USE SIGNAL ;
    PORT
      LAYER M5 ;
        RECT  108.432 0 108.456 0.192 ;
    END
  END i[613]
  PIN i[614]
    DIRECTION INPUT ;
    USE SIGNAL ;
    PORT
      LAYER M5 ;
        RECT  108.624 0 108.648 0.192 ;
    END
  END i[614]
  PIN i[615]
    DIRECTION INPUT ;
    USE SIGNAL ;
    PORT
      LAYER M5 ;
        RECT  108.768 0 108.792 0.192 ;
    END
  END i[615]
  PIN i[616]
    DIRECTION INPUT ;
    USE SIGNAL ;
    PORT
      LAYER M5 ;
        RECT  108.96 0 108.984 0.192 ;
    END
  END i[616]
  PIN i[617]
    DIRECTION INPUT ;
    USE SIGNAL ;
    PORT
      LAYER M5 ;
        RECT  109.152 0 109.176 0.192 ;
    END
  END i[617]
  PIN i[618]
    DIRECTION INPUT ;
    USE SIGNAL ;
    PORT
      LAYER M5 ;
        RECT  109.296 0 109.32 0.192 ;
    END
  END i[618]
  PIN i[619]
    DIRECTION INPUT ;
    USE SIGNAL ;
    PORT
      LAYER M5 ;
        RECT  109.488 0 109.512 0.192 ;
    END
  END i[619]
  PIN i[61]
    DIRECTION INPUT ;
    USE SIGNAL ;
    PORT
      LAYER M5 ;
        RECT  14.64 0 14.664 0.192 ;
    END
  END i[61]
  PIN i[620]
    DIRECTION INPUT ;
    USE SIGNAL ;
    PORT
      LAYER M5 ;
        RECT  109.632 0 109.656 0.192 ;
    END
  END i[620]
  PIN i[621]
    DIRECTION INPUT ;
    USE SIGNAL ;
    PORT
      LAYER M5 ;
        RECT  109.824 0 109.848 0.192 ;
    END
  END i[621]
  PIN i[622]
    DIRECTION INPUT ;
    USE SIGNAL ;
    PORT
      LAYER M5 ;
        RECT  109.968 0 109.992 0.192 ;
    END
  END i[622]
  PIN i[623]
    DIRECTION INPUT ;
    USE SIGNAL ;
    PORT
      LAYER M5 ;
        RECT  110.16 0 110.184 0.192 ;
    END
  END i[623]
  PIN i[62]
    DIRECTION INPUT ;
    USE SIGNAL ;
    PORT
      LAYER M5 ;
        RECT  14.832 0 14.856 0.192 ;
    END
  END i[62]
  PIN i[63]
    DIRECTION INPUT ;
    USE SIGNAL ;
    PORT
      LAYER M5 ;
        RECT  14.976 0 15 0.192 ;
    END
  END i[63]
  PIN i[64]
    DIRECTION INPUT ;
    USE SIGNAL ;
    PORT
      LAYER M5 ;
        RECT  15.168 0 15.192 0.192 ;
    END
  END i[64]
  PIN i[65]
    DIRECTION INPUT ;
    USE SIGNAL ;
    PORT
      LAYER M5 ;
        RECT  15.312 0 15.336 0.192 ;
    END
  END i[65]
  PIN i[66]
    DIRECTION INPUT ;
    USE SIGNAL ;
    PORT
      LAYER M5 ;
        RECT  15.504 0 15.528 0.192 ;
    END
  END i[66]
  PIN i[67]
    DIRECTION INPUT ;
    USE SIGNAL ;
    PORT
      LAYER M5 ;
        RECT  15.696 0 15.72 0.192 ;
    END
  END i[67]
  PIN i[68]
    DIRECTION INPUT ;
    USE SIGNAL ;
    PORT
      LAYER M5 ;
        RECT  15.84 0 15.864 0.192 ;
    END
  END i[68]
  PIN i[69]
    DIRECTION INPUT ;
    USE SIGNAL ;
    PORT
      LAYER M5 ;
        RECT  16.032 0 16.056 0.192 ;
    END
  END i[69]
  PIN i[6]
    DIRECTION INPUT ;
    USE SIGNAL ;
    PORT
      LAYER M5 ;
        RECT  5.328 0 5.352 0.192 ;
    END
  END i[6]
  PIN i[70]
    DIRECTION INPUT ;
    USE SIGNAL ;
    PORT
      LAYER M5 ;
        RECT  16.176 0 16.2 0.192 ;
    END
  END i[70]
  PIN i[71]
    DIRECTION INPUT ;
    USE SIGNAL ;
    PORT
      LAYER M5 ;
        RECT  16.368 0 16.392 0.192 ;
    END
  END i[71]
  PIN i[72]
    DIRECTION INPUT ;
    USE SIGNAL ;
    PORT
      LAYER M5 ;
        RECT  16.512 0 16.536 0.192 ;
    END
  END i[72]
  PIN i[73]
    DIRECTION INPUT ;
    USE SIGNAL ;
    PORT
      LAYER M5 ;
        RECT  16.704 0 16.728 0.192 ;
    END
  END i[73]
  PIN i[74]
    DIRECTION INPUT ;
    USE SIGNAL ;
    PORT
      LAYER M5 ;
        RECT  16.848 0 16.872 0.192 ;
    END
  END i[74]
  PIN i[75]
    DIRECTION INPUT ;
    USE SIGNAL ;
    PORT
      LAYER M5 ;
        RECT  17.04 0 17.064 0.192 ;
    END
  END i[75]
  PIN i[76]
    DIRECTION INPUT ;
    USE SIGNAL ;
    PORT
      LAYER M5 ;
        RECT  17.184 0 17.208 0.192 ;
    END
  END i[76]
  PIN i[77]
    DIRECTION INPUT ;
    USE SIGNAL ;
    PORT
      LAYER M5 ;
        RECT  17.376 0 17.4 0.192 ;
    END
  END i[77]
  PIN i[78]
    DIRECTION INPUT ;
    USE SIGNAL ;
    PORT
      LAYER M5 ;
        RECT  17.52 0 17.544 0.192 ;
    END
  END i[78]
  PIN i[79]
    DIRECTION INPUT ;
    USE SIGNAL ;
    PORT
      LAYER M5 ;
        RECT  17.712 0 17.736 0.192 ;
    END
  END i[79]
  PIN i[7]
    DIRECTION INPUT ;
    USE SIGNAL ;
    PORT
      LAYER M5 ;
        RECT  5.472 0 5.496 0.192 ;
    END
  END i[7]
  PIN i[80]
    DIRECTION INPUT ;
    USE SIGNAL ;
    PORT
      LAYER M5 ;
        RECT  17.856 0 17.88 0.192 ;
    END
  END i[80]
  PIN i[81]
    DIRECTION INPUT ;
    USE SIGNAL ;
    PORT
      LAYER M5 ;
        RECT  18.048 0 18.072 0.192 ;
    END
  END i[81]
  PIN i[82]
    DIRECTION INPUT ;
    USE SIGNAL ;
    PORT
      LAYER M5 ;
        RECT  18.24 0 18.264 0.192 ;
    END
  END i[82]
  PIN i[83]
    DIRECTION INPUT ;
    USE SIGNAL ;
    PORT
      LAYER M5 ;
        RECT  18.384 0 18.408 0.192 ;
    END
  END i[83]
  PIN i[84]
    DIRECTION INPUT ;
    USE SIGNAL ;
    PORT
      LAYER M5 ;
        RECT  18.576 0 18.6 0.192 ;
    END
  END i[84]
  PIN i[85]
    DIRECTION INPUT ;
    USE SIGNAL ;
    PORT
      LAYER M5 ;
        RECT  18.72 0 18.744 0.192 ;
    END
  END i[85]
  PIN i[86]
    DIRECTION INPUT ;
    USE SIGNAL ;
    PORT
      LAYER M5 ;
        RECT  18.912 0 18.936 0.192 ;
    END
  END i[86]
  PIN i[87]
    DIRECTION INPUT ;
    USE SIGNAL ;
    PORT
      LAYER M5 ;
        RECT  19.056 0 19.08 0.192 ;
    END
  END i[87]
  PIN i[88]
    DIRECTION INPUT ;
    USE SIGNAL ;
    PORT
      LAYER M5 ;
        RECT  19.248 0 19.272 0.192 ;
    END
  END i[88]
  PIN i[89]
    DIRECTION INPUT ;
    USE SIGNAL ;
    PORT
      LAYER M5 ;
        RECT  19.392 0 19.416 0.192 ;
    END
  END i[89]
  PIN i[8]
    DIRECTION INPUT ;
    USE SIGNAL ;
    PORT
      LAYER M5 ;
        RECT  5.664 0 5.688 0.192 ;
    END
  END i[8]
  PIN i[90]
    DIRECTION INPUT ;
    USE SIGNAL ;
    PORT
      LAYER M5 ;
        RECT  19.584 0 19.608 0.192 ;
    END
  END i[90]
  PIN i[91]
    DIRECTION INPUT ;
    USE SIGNAL ;
    PORT
      LAYER M5 ;
        RECT  19.728 0 19.752 0.192 ;
    END
  END i[91]
  PIN i[92]
    DIRECTION INPUT ;
    USE SIGNAL ;
    PORT
      LAYER M5 ;
        RECT  19.92 0 19.944 0.192 ;
    END
  END i[92]
  PIN i[93]
    DIRECTION INPUT ;
    USE SIGNAL ;
    PORT
      LAYER M5 ;
        RECT  20.064 0 20.088 0.192 ;
    END
  END i[93]
  PIN i[94]
    DIRECTION INPUT ;
    USE SIGNAL ;
    PORT
      LAYER M5 ;
        RECT  20.256 0 20.28 0.192 ;
    END
  END i[94]
  PIN i[95]
    DIRECTION INPUT ;
    USE SIGNAL ;
    PORT
      LAYER M5 ;
        RECT  20.4 0 20.424 0.192 ;
    END
  END i[95]
  PIN i[96]
    DIRECTION INPUT ;
    USE SIGNAL ;
    PORT
      LAYER M5 ;
        RECT  20.592 0 20.616 0.192 ;
    END
  END i[96]
  PIN i[97]
    DIRECTION INPUT ;
    USE SIGNAL ;
    PORT
      LAYER M5 ;
        RECT  20.784 0 20.808 0.192 ;
    END
  END i[97]
  PIN i[98]
    DIRECTION INPUT ;
    USE SIGNAL ;
    PORT
      LAYER M5 ;
        RECT  20.928 0 20.952 0.192 ;
    END
  END i[98]
  PIN i[99]
    DIRECTION INPUT ;
    USE SIGNAL ;
    PORT
      LAYER M5 ;
        RECT  21.12 0 21.144 0.192 ;
    END
  END i[99]
  PIN i[9]
    DIRECTION INPUT ;
    USE SIGNAL ;
    PORT
      LAYER M5 ;
        RECT  5.856 0 5.88 0.192 ;
    END
  END i[9]
  PIN o[0]
    DIRECTION OUTPUT ;
    USE SIGNAL ;
    PORT
      LAYER M5 ;
        RECT  4.32 21.408 4.344 21.6 ;
    END
  END o[0]
  PIN o[100]
    DIRECTION OUTPUT ;
    USE SIGNAL ;
    PORT
      LAYER M5 ;
        RECT  21.264 21.408 21.288 21.6 ;
    END
  END o[100]
  PIN o[101]
    DIRECTION OUTPUT ;
    USE SIGNAL ;
    PORT
      LAYER M5 ;
        RECT  21.456 21.408 21.48 21.6 ;
    END
  END o[101]
  PIN o[102]
    DIRECTION OUTPUT ;
    USE SIGNAL ;
    PORT
      LAYER M5 ;
        RECT  21.6 21.408 21.624 21.6 ;
    END
  END o[102]
  PIN o[103]
    DIRECTION OUTPUT ;
    USE SIGNAL ;
    PORT
      LAYER M5 ;
        RECT  21.792 21.408 21.816 21.6 ;
    END
  END o[103]
  PIN o[104]
    DIRECTION OUTPUT ;
    USE SIGNAL ;
    PORT
      LAYER M5 ;
        RECT  21.936 21.408 21.96 21.6 ;
    END
  END o[104]
  PIN o[105]
    DIRECTION OUTPUT ;
    USE SIGNAL ;
    PORT
      LAYER M5 ;
        RECT  22.128 21.408 22.152 21.6 ;
    END
  END o[105]
  PIN o[106]
    DIRECTION OUTPUT ;
    USE SIGNAL ;
    PORT
      LAYER M5 ;
        RECT  22.272 21.408 22.296 21.6 ;
    END
  END o[106]
  PIN o[107]
    DIRECTION OUTPUT ;
    USE SIGNAL ;
    PORT
      LAYER M5 ;
        RECT  22.464 21.408 22.488 21.6 ;
    END
  END o[107]
  PIN o[108]
    DIRECTION OUTPUT ;
    USE SIGNAL ;
    PORT
      LAYER M5 ;
        RECT  22.608 21.408 22.632 21.6 ;
    END
  END o[108]
  PIN o[109]
    DIRECTION OUTPUT ;
    USE SIGNAL ;
    PORT
      LAYER M5 ;
        RECT  22.8 21.408 22.824 21.6 ;
    END
  END o[109]
  PIN o[10]
    DIRECTION OUTPUT ;
    USE SIGNAL ;
    PORT
      LAYER M5 ;
        RECT  6 21.408 6.024 21.6 ;
    END
  END o[10]
  PIN o[110]
    DIRECTION OUTPUT ;
    USE SIGNAL ;
    PORT
      LAYER M5 ;
        RECT  22.944 21.408 22.968 21.6 ;
    END
  END o[110]
  PIN o[111]
    DIRECTION OUTPUT ;
    USE SIGNAL ;
    PORT
      LAYER M5 ;
        RECT  23.136 21.408 23.16 21.6 ;
    END
  END o[111]
  PIN o[112]
    DIRECTION OUTPUT ;
    USE SIGNAL ;
    PORT
      LAYER M5 ;
        RECT  23.328 21.408 23.352 21.6 ;
    END
  END o[112]
  PIN o[113]
    DIRECTION OUTPUT ;
    USE SIGNAL ;
    PORT
      LAYER M5 ;
        RECT  23.472 21.408 23.496 21.6 ;
    END
  END o[113]
  PIN o[114]
    DIRECTION OUTPUT ;
    USE SIGNAL ;
    PORT
      LAYER M5 ;
        RECT  23.664 21.408 23.688 21.6 ;
    END
  END o[114]
  PIN o[115]
    DIRECTION OUTPUT ;
    USE SIGNAL ;
    PORT
      LAYER M5 ;
        RECT  23.808 21.408 23.832 21.6 ;
    END
  END o[115]
  PIN o[116]
    DIRECTION OUTPUT ;
    USE SIGNAL ;
    PORT
      LAYER M5 ;
        RECT  24 21.408 24.024 21.6 ;
    END
  END o[116]
  PIN o[117]
    DIRECTION OUTPUT ;
    USE SIGNAL ;
    PORT
      LAYER M5 ;
        RECT  24.144 21.408 24.168 21.6 ;
    END
  END o[117]
  PIN o[118]
    DIRECTION OUTPUT ;
    USE SIGNAL ;
    PORT
      LAYER M5 ;
        RECT  24.336 21.408 24.36 21.6 ;
    END
  END o[118]
  PIN o[119]
    DIRECTION OUTPUT ;
    USE SIGNAL ;
    PORT
      LAYER M5 ;
        RECT  24.48 21.408 24.504 21.6 ;
    END
  END o[119]
  PIN o[11]
    DIRECTION OUTPUT ;
    USE SIGNAL ;
    PORT
      LAYER M5 ;
        RECT  6.192 21.408 6.216 21.6 ;
    END
  END o[11]
  PIN o[120]
    DIRECTION OUTPUT ;
    USE SIGNAL ;
    PORT
      LAYER M5 ;
        RECT  24.672 21.408 24.696 21.6 ;
    END
  END o[120]
  PIN o[121]
    DIRECTION OUTPUT ;
    USE SIGNAL ;
    PORT
      LAYER M5 ;
        RECT  24.816 21.408 24.84 21.6 ;
    END
  END o[121]
  PIN o[122]
    DIRECTION OUTPUT ;
    USE SIGNAL ;
    PORT
      LAYER M5 ;
        RECT  25.008 21.408 25.032 21.6 ;
    END
  END o[122]
  PIN o[123]
    DIRECTION OUTPUT ;
    USE SIGNAL ;
    PORT
      LAYER M5 ;
        RECT  25.152 21.408 25.176 21.6 ;
    END
  END o[123]
  PIN o[124]
    DIRECTION OUTPUT ;
    USE SIGNAL ;
    PORT
      LAYER M5 ;
        RECT  25.344 21.408 25.368 21.6 ;
    END
  END o[124]
  PIN o[125]
    DIRECTION OUTPUT ;
    USE SIGNAL ;
    PORT
      LAYER M5 ;
        RECT  25.488 21.408 25.512 21.6 ;
    END
  END o[125]
  PIN o[126]
    DIRECTION OUTPUT ;
    USE SIGNAL ;
    PORT
      LAYER M5 ;
        RECT  25.68 21.408 25.704 21.6 ;
    END
  END o[126]
  PIN o[127]
    DIRECTION OUTPUT ;
    USE SIGNAL ;
    PORT
      LAYER M5 ;
        RECT  25.872 21.408 25.896 21.6 ;
    END
  END o[127]
  PIN o[128]
    DIRECTION OUTPUT ;
    USE SIGNAL ;
    PORT
      LAYER M5 ;
        RECT  26.016 21.408 26.04 21.6 ;
    END
  END o[128]
  PIN o[129]
    DIRECTION OUTPUT ;
    USE SIGNAL ;
    PORT
      LAYER M5 ;
        RECT  26.208 21.408 26.232 21.6 ;
    END
  END o[129]
  PIN o[12]
    DIRECTION OUTPUT ;
    USE SIGNAL ;
    PORT
      LAYER M5 ;
        RECT  6.336 21.408 6.36 21.6 ;
    END
  END o[12]
  PIN o[130]
    DIRECTION OUTPUT ;
    USE SIGNAL ;
    PORT
      LAYER M5 ;
        RECT  26.352 21.408 26.376 21.6 ;
    END
  END o[130]
  PIN o[131]
    DIRECTION OUTPUT ;
    USE SIGNAL ;
    PORT
      LAYER M5 ;
        RECT  26.544 21.408 26.568 21.6 ;
    END
  END o[131]
  PIN o[132]
    DIRECTION OUTPUT ;
    USE SIGNAL ;
    PORT
      LAYER M5 ;
        RECT  26.688 21.408 26.712 21.6 ;
    END
  END o[132]
  PIN o[133]
    DIRECTION OUTPUT ;
    USE SIGNAL ;
    PORT
      LAYER M5 ;
        RECT  26.88 21.408 26.904 21.6 ;
    END
  END o[133]
  PIN o[134]
    DIRECTION OUTPUT ;
    USE SIGNAL ;
    PORT
      LAYER M5 ;
        RECT  27.024 21.408 27.048 21.6 ;
    END
  END o[134]
  PIN o[135]
    DIRECTION OUTPUT ;
    USE SIGNAL ;
    PORT
      LAYER M5 ;
        RECT  27.216 21.408 27.24 21.6 ;
    END
  END o[135]
  PIN o[136]
    DIRECTION OUTPUT ;
    USE SIGNAL ;
    PORT
      LAYER M5 ;
        RECT  27.36 21.408 27.384 21.6 ;
    END
  END o[136]
  PIN o[137]
    DIRECTION OUTPUT ;
    USE SIGNAL ;
    PORT
      LAYER M5 ;
        RECT  27.552 21.408 27.576 21.6 ;
    END
  END o[137]
  PIN o[138]
    DIRECTION OUTPUT ;
    USE SIGNAL ;
    PORT
      LAYER M5 ;
        RECT  27.696 21.408 27.72 21.6 ;
    END
  END o[138]
  PIN o[139]
    DIRECTION OUTPUT ;
    USE SIGNAL ;
    PORT
      LAYER M5 ;
        RECT  27.888 21.408 27.912 21.6 ;
    END
  END o[139]
  PIN o[13]
    DIRECTION OUTPUT ;
    USE SIGNAL ;
    PORT
      LAYER M5 ;
        RECT  6.528 21.408 6.552 21.6 ;
    END
  END o[13]
  PIN o[140]
    DIRECTION OUTPUT ;
    USE SIGNAL ;
    PORT
      LAYER M5 ;
        RECT  28.032 21.408 28.056 21.6 ;
    END
  END o[140]
  PIN o[141]
    DIRECTION OUTPUT ;
    USE SIGNAL ;
    PORT
      LAYER M5 ;
        RECT  28.224 21.408 28.248 21.6 ;
    END
  END o[141]
  PIN o[142]
    DIRECTION OUTPUT ;
    USE SIGNAL ;
    PORT
      LAYER M5 ;
        RECT  28.416 21.408 28.44 21.6 ;
    END
  END o[142]
  PIN o[143]
    DIRECTION OUTPUT ;
    USE SIGNAL ;
    PORT
      LAYER M5 ;
        RECT  28.56 21.408 28.584 21.6 ;
    END
  END o[143]
  PIN o[144]
    DIRECTION OUTPUT ;
    USE SIGNAL ;
    PORT
      LAYER M5 ;
        RECT  28.752 21.408 28.776 21.6 ;
    END
  END o[144]
  PIN o[145]
    DIRECTION OUTPUT ;
    USE SIGNAL ;
    PORT
      LAYER M5 ;
        RECT  28.896 21.408 28.92 21.6 ;
    END
  END o[145]
  PIN o[146]
    DIRECTION OUTPUT ;
    USE SIGNAL ;
    PORT
      LAYER M5 ;
        RECT  29.088 21.408 29.112 21.6 ;
    END
  END o[146]
  PIN o[147]
    DIRECTION OUTPUT ;
    USE SIGNAL ;
    PORT
      LAYER M5 ;
        RECT  29.232 21.408 29.256 21.6 ;
    END
  END o[147]
  PIN o[148]
    DIRECTION OUTPUT ;
    USE SIGNAL ;
    PORT
      LAYER M5 ;
        RECT  29.424 21.408 29.448 21.6 ;
    END
  END o[148]
  PIN o[149]
    DIRECTION OUTPUT ;
    USE SIGNAL ;
    PORT
      LAYER M5 ;
        RECT  29.568 21.408 29.592 21.6 ;
    END
  END o[149]
  PIN o[14]
    DIRECTION OUTPUT ;
    USE SIGNAL ;
    PORT
      LAYER M5 ;
        RECT  6.672 21.408 6.696 21.6 ;
    END
  END o[14]
  PIN o[150]
    DIRECTION OUTPUT ;
    USE SIGNAL ;
    PORT
      LAYER M5 ;
        RECT  29.76 21.408 29.784 21.6 ;
    END
  END o[150]
  PIN o[151]
    DIRECTION OUTPUT ;
    USE SIGNAL ;
    PORT
      LAYER M5 ;
        RECT  29.904 21.408 29.928 21.6 ;
    END
  END o[151]
  PIN o[152]
    DIRECTION OUTPUT ;
    USE SIGNAL ;
    PORT
      LAYER M5 ;
        RECT  30.096 21.408 30.12 21.6 ;
    END
  END o[152]
  PIN o[153]
    DIRECTION OUTPUT ;
    USE SIGNAL ;
    PORT
      LAYER M5 ;
        RECT  30.24 21.408 30.264 21.6 ;
    END
  END o[153]
  PIN o[154]
    DIRECTION OUTPUT ;
    USE SIGNAL ;
    PORT
      LAYER M5 ;
        RECT  30.432 21.408 30.456 21.6 ;
    END
  END o[154]
  PIN o[155]
    DIRECTION OUTPUT ;
    USE SIGNAL ;
    PORT
      LAYER M5 ;
        RECT  30.576 21.408 30.6 21.6 ;
    END
  END o[155]
  PIN o[156]
    DIRECTION OUTPUT ;
    USE SIGNAL ;
    PORT
      LAYER M5 ;
        RECT  30.768 21.408 30.792 21.6 ;
    END
  END o[156]
  PIN o[157]
    DIRECTION OUTPUT ;
    USE SIGNAL ;
    PORT
      LAYER M5 ;
        RECT  30.96 21.408 30.984 21.6 ;
    END
  END o[157]
  PIN o[158]
    DIRECTION OUTPUT ;
    USE SIGNAL ;
    PORT
      LAYER M5 ;
        RECT  31.104 21.408 31.128 21.6 ;
    END
  END o[158]
  PIN o[159]
    DIRECTION OUTPUT ;
    USE SIGNAL ;
    PORT
      LAYER M5 ;
        RECT  31.296 21.408 31.32 21.6 ;
    END
  END o[159]
  PIN o[15]
    DIRECTION OUTPUT ;
    USE SIGNAL ;
    PORT
      LAYER M5 ;
        RECT  6.864 21.408 6.888 21.6 ;
    END
  END o[15]
  PIN o[160]
    DIRECTION OUTPUT ;
    USE SIGNAL ;
    PORT
      LAYER M5 ;
        RECT  31.44 21.408 31.464 21.6 ;
    END
  END o[160]
  PIN o[161]
    DIRECTION OUTPUT ;
    USE SIGNAL ;
    PORT
      LAYER M5 ;
        RECT  31.632 21.408 31.656 21.6 ;
    END
  END o[161]
  PIN o[162]
    DIRECTION OUTPUT ;
    USE SIGNAL ;
    PORT
      LAYER M5 ;
        RECT  31.776 21.408 31.8 21.6 ;
    END
  END o[162]
  PIN o[163]
    DIRECTION OUTPUT ;
    USE SIGNAL ;
    PORT
      LAYER M5 ;
        RECT  31.968 21.408 31.992 21.6 ;
    END
  END o[163]
  PIN o[164]
    DIRECTION OUTPUT ;
    USE SIGNAL ;
    PORT
      LAYER M5 ;
        RECT  32.112 21.408 32.136 21.6 ;
    END
  END o[164]
  PIN o[165]
    DIRECTION OUTPUT ;
    USE SIGNAL ;
    PORT
      LAYER M5 ;
        RECT  32.304 21.408 32.328 21.6 ;
    END
  END o[165]
  PIN o[166]
    DIRECTION OUTPUT ;
    USE SIGNAL ;
    PORT
      LAYER M5 ;
        RECT  32.448 21.408 32.472 21.6 ;
    END
  END o[166]
  PIN o[167]
    DIRECTION OUTPUT ;
    USE SIGNAL ;
    PORT
      LAYER M5 ;
        RECT  32.64 21.408 32.664 21.6 ;
    END
  END o[167]
  PIN o[168]
    DIRECTION OUTPUT ;
    USE SIGNAL ;
    PORT
      LAYER M5 ;
        RECT  32.784 21.408 32.808 21.6 ;
    END
  END o[168]
  PIN o[169]
    DIRECTION OUTPUT ;
    USE SIGNAL ;
    PORT
      LAYER M5 ;
        RECT  32.976 21.408 33 21.6 ;
    END
  END o[169]
  PIN o[16]
    DIRECTION OUTPUT ;
    USE SIGNAL ;
    PORT
      LAYER M5 ;
        RECT  7.008 21.408 7.032 21.6 ;
    END
  END o[16]
  PIN o[170]
    DIRECTION OUTPUT ;
    USE SIGNAL ;
    PORT
      LAYER M5 ;
        RECT  33.12 21.408 33.144 21.6 ;
    END
  END o[170]
  PIN o[171]
    DIRECTION OUTPUT ;
    USE SIGNAL ;
    PORT
      LAYER M5 ;
        RECT  33.312 21.408 33.336 21.6 ;
    END
  END o[171]
  PIN o[172]
    DIRECTION OUTPUT ;
    USE SIGNAL ;
    PORT
      LAYER M5 ;
        RECT  33.504 21.408 33.528 21.6 ;
    END
  END o[172]
  PIN o[173]
    DIRECTION OUTPUT ;
    USE SIGNAL ;
    PORT
      LAYER M5 ;
        RECT  33.648 21.408 33.672 21.6 ;
    END
  END o[173]
  PIN o[174]
    DIRECTION OUTPUT ;
    USE SIGNAL ;
    PORT
      LAYER M5 ;
        RECT  33.84 21.408 33.864 21.6 ;
    END
  END o[174]
  PIN o[175]
    DIRECTION OUTPUT ;
    USE SIGNAL ;
    PORT
      LAYER M5 ;
        RECT  33.984 21.408 34.008 21.6 ;
    END
  END o[175]
  PIN o[176]
    DIRECTION OUTPUT ;
    USE SIGNAL ;
    PORT
      LAYER M5 ;
        RECT  34.176 21.408 34.2 21.6 ;
    END
  END o[176]
  PIN o[177]
    DIRECTION OUTPUT ;
    USE SIGNAL ;
    PORT
      LAYER M5 ;
        RECT  34.32 21.408 34.344 21.6 ;
    END
  END o[177]
  PIN o[178]
    DIRECTION OUTPUT ;
    USE SIGNAL ;
    PORT
      LAYER M5 ;
        RECT  34.512 21.408 34.536 21.6 ;
    END
  END o[178]
  PIN o[179]
    DIRECTION OUTPUT ;
    USE SIGNAL ;
    PORT
      LAYER M5 ;
        RECT  34.656 21.408 34.68 21.6 ;
    END
  END o[179]
  PIN o[17]
    DIRECTION OUTPUT ;
    USE SIGNAL ;
    PORT
      LAYER M5 ;
        RECT  7.2 21.408 7.224 21.6 ;
    END
  END o[17]
  PIN o[180]
    DIRECTION OUTPUT ;
    USE SIGNAL ;
    PORT
      LAYER M5 ;
        RECT  34.848 21.408 34.872 21.6 ;
    END
  END o[180]
  PIN o[181]
    DIRECTION OUTPUT ;
    USE SIGNAL ;
    PORT
      LAYER M5 ;
        RECT  34.992 21.408 35.016 21.6 ;
    END
  END o[181]
  PIN o[182]
    DIRECTION OUTPUT ;
    USE SIGNAL ;
    PORT
      LAYER M5 ;
        RECT  35.184 21.408 35.208 21.6 ;
    END
  END o[182]
  PIN o[183]
    DIRECTION OUTPUT ;
    USE SIGNAL ;
    PORT
      LAYER M5 ;
        RECT  35.328 21.408 35.352 21.6 ;
    END
  END o[183]
  PIN o[184]
    DIRECTION OUTPUT ;
    USE SIGNAL ;
    PORT
      LAYER M5 ;
        RECT  35.52 21.408 35.544 21.6 ;
    END
  END o[184]
  PIN o[185]
    DIRECTION OUTPUT ;
    USE SIGNAL ;
    PORT
      LAYER M5 ;
        RECT  35.664 21.408 35.688 21.6 ;
    END
  END o[185]
  PIN o[186]
    DIRECTION OUTPUT ;
    USE SIGNAL ;
    PORT
      LAYER M5 ;
        RECT  35.856 21.408 35.88 21.6 ;
    END
  END o[186]
  PIN o[187]
    DIRECTION OUTPUT ;
    USE SIGNAL ;
    PORT
      LAYER M5 ;
        RECT  36.048 21.408 36.072 21.6 ;
    END
  END o[187]
  PIN o[188]
    DIRECTION OUTPUT ;
    USE SIGNAL ;
    PORT
      LAYER M5 ;
        RECT  36.192 21.408 36.216 21.6 ;
    END
  END o[188]
  PIN o[189]
    DIRECTION OUTPUT ;
    USE SIGNAL ;
    PORT
      LAYER M5 ;
        RECT  36.384 21.408 36.408 21.6 ;
    END
  END o[189]
  PIN o[18]
    DIRECTION OUTPUT ;
    USE SIGNAL ;
    PORT
      LAYER M5 ;
        RECT  7.344 21.408 7.368 21.6 ;
    END
  END o[18]
  PIN o[190]
    DIRECTION OUTPUT ;
    USE SIGNAL ;
    PORT
      LAYER M5 ;
        RECT  36.528 21.408 36.552 21.6 ;
    END
  END o[190]
  PIN o[191]
    DIRECTION OUTPUT ;
    USE SIGNAL ;
    PORT
      LAYER M5 ;
        RECT  36.72 21.408 36.744 21.6 ;
    END
  END o[191]
  PIN o[192]
    DIRECTION OUTPUT ;
    USE SIGNAL ;
    PORT
      LAYER M5 ;
        RECT  36.864 21.408 36.888 21.6 ;
    END
  END o[192]
  PIN o[193]
    DIRECTION OUTPUT ;
    USE SIGNAL ;
    PORT
      LAYER M5 ;
        RECT  37.056 21.408 37.08 21.6 ;
    END
  END o[193]
  PIN o[194]
    DIRECTION OUTPUT ;
    USE SIGNAL ;
    PORT
      LAYER M5 ;
        RECT  37.2 21.408 37.224 21.6 ;
    END
  END o[194]
  PIN o[195]
    DIRECTION OUTPUT ;
    USE SIGNAL ;
    PORT
      LAYER M5 ;
        RECT  37.392 21.408 37.416 21.6 ;
    END
  END o[195]
  PIN o[196]
    DIRECTION OUTPUT ;
    USE SIGNAL ;
    PORT
      LAYER M5 ;
        RECT  37.536 21.408 37.56 21.6 ;
    END
  END o[196]
  PIN o[197]
    DIRECTION OUTPUT ;
    USE SIGNAL ;
    PORT
      LAYER M5 ;
        RECT  37.728 21.408 37.752 21.6 ;
    END
  END o[197]
  PIN o[198]
    DIRECTION OUTPUT ;
    USE SIGNAL ;
    PORT
      LAYER M5 ;
        RECT  37.872 21.408 37.896 21.6 ;
    END
  END o[198]
  PIN o[199]
    DIRECTION OUTPUT ;
    USE SIGNAL ;
    PORT
      LAYER M5 ;
        RECT  38.064 21.408 38.088 21.6 ;
    END
  END o[199]
  PIN o[19]
    DIRECTION OUTPUT ;
    USE SIGNAL ;
    PORT
      LAYER M5 ;
        RECT  7.536 21.408 7.56 21.6 ;
    END
  END o[19]
  PIN o[1]
    DIRECTION OUTPUT ;
    USE SIGNAL ;
    PORT
      LAYER M5 ;
        RECT  4.464 21.408 4.488 21.6 ;
    END
  END o[1]
  PIN o[200]
    DIRECTION OUTPUT ;
    USE SIGNAL ;
    PORT
      LAYER M5 ;
        RECT  38.208 21.408 38.232 21.6 ;
    END
  END o[200]
  PIN o[201]
    DIRECTION OUTPUT ;
    USE SIGNAL ;
    PORT
      LAYER M5 ;
        RECT  38.4 21.408 38.424 21.6 ;
    END
  END o[201]
  PIN o[202]
    DIRECTION OUTPUT ;
    USE SIGNAL ;
    PORT
      LAYER M5 ;
        RECT  38.592 21.408 38.616 21.6 ;
    END
  END o[202]
  PIN o[203]
    DIRECTION OUTPUT ;
    USE SIGNAL ;
    PORT
      LAYER M5 ;
        RECT  38.736 21.408 38.76 21.6 ;
    END
  END o[203]
  PIN o[204]
    DIRECTION OUTPUT ;
    USE SIGNAL ;
    PORT
      LAYER M5 ;
        RECT  38.928 21.408 38.952 21.6 ;
    END
  END o[204]
  PIN o[205]
    DIRECTION OUTPUT ;
    USE SIGNAL ;
    PORT
      LAYER M5 ;
        RECT  39.072 21.408 39.096 21.6 ;
    END
  END o[205]
  PIN o[206]
    DIRECTION OUTPUT ;
    USE SIGNAL ;
    PORT
      LAYER M5 ;
        RECT  39.264 21.408 39.288 21.6 ;
    END
  END o[206]
  PIN o[207]
    DIRECTION OUTPUT ;
    USE SIGNAL ;
    PORT
      LAYER M5 ;
        RECT  39.408 21.408 39.432 21.6 ;
    END
  END o[207]
  PIN o[208]
    DIRECTION OUTPUT ;
    USE SIGNAL ;
    PORT
      LAYER M5 ;
        RECT  39.6 21.408 39.624 21.6 ;
    END
  END o[208]
  PIN o[209]
    DIRECTION OUTPUT ;
    USE SIGNAL ;
    PORT
      LAYER M5 ;
        RECT  39.744 21.408 39.768 21.6 ;
    END
  END o[209]
  PIN o[20]
    DIRECTION OUTPUT ;
    USE SIGNAL ;
    PORT
      LAYER M5 ;
        RECT  7.68 21.408 7.704 21.6 ;
    END
  END o[20]
  PIN o[210]
    DIRECTION OUTPUT ;
    USE SIGNAL ;
    PORT
      LAYER M5 ;
        RECT  39.936 21.408 39.96 21.6 ;
    END
  END o[210]
  PIN o[211]
    DIRECTION OUTPUT ;
    USE SIGNAL ;
    PORT
      LAYER M5 ;
        RECT  40.08 21.408 40.104 21.6 ;
    END
  END o[211]
  PIN o[212]
    DIRECTION OUTPUT ;
    USE SIGNAL ;
    PORT
      LAYER M5 ;
        RECT  40.272 21.408 40.296 21.6 ;
    END
  END o[212]
  PIN o[213]
    DIRECTION OUTPUT ;
    USE SIGNAL ;
    PORT
      LAYER M5 ;
        RECT  40.416 21.408 40.44 21.6 ;
    END
  END o[213]
  PIN o[214]
    DIRECTION OUTPUT ;
    USE SIGNAL ;
    PORT
      LAYER M5 ;
        RECT  40.608 21.408 40.632 21.6 ;
    END
  END o[214]
  PIN o[215]
    DIRECTION OUTPUT ;
    USE SIGNAL ;
    PORT
      LAYER M5 ;
        RECT  40.752 21.408 40.776 21.6 ;
    END
  END o[215]
  PIN o[216]
    DIRECTION OUTPUT ;
    USE SIGNAL ;
    PORT
      LAYER M5 ;
        RECT  40.944 21.408 40.968 21.6 ;
    END
  END o[216]
  PIN o[217]
    DIRECTION OUTPUT ;
    USE SIGNAL ;
    PORT
      LAYER M5 ;
        RECT  41.136 21.408 41.16 21.6 ;
    END
  END o[217]
  PIN o[218]
    DIRECTION OUTPUT ;
    USE SIGNAL ;
    PORT
      LAYER M5 ;
        RECT  41.28 21.408 41.304 21.6 ;
    END
  END o[218]
  PIN o[219]
    DIRECTION OUTPUT ;
    USE SIGNAL ;
    PORT
      LAYER M5 ;
        RECT  41.472 21.408 41.496 21.6 ;
    END
  END o[219]
  PIN o[21]
    DIRECTION OUTPUT ;
    USE SIGNAL ;
    PORT
      LAYER M5 ;
        RECT  7.872 21.408 7.896 21.6 ;
    END
  END o[21]
  PIN o[220]
    DIRECTION OUTPUT ;
    USE SIGNAL ;
    PORT
      LAYER M5 ;
        RECT  41.616 21.408 41.64 21.6 ;
    END
  END o[220]
  PIN o[221]
    DIRECTION OUTPUT ;
    USE SIGNAL ;
    PORT
      LAYER M5 ;
        RECT  41.808 21.408 41.832 21.6 ;
    END
  END o[221]
  PIN o[222]
    DIRECTION OUTPUT ;
    USE SIGNAL ;
    PORT
      LAYER M5 ;
        RECT  41.952 21.408 41.976 21.6 ;
    END
  END o[222]
  PIN o[223]
    DIRECTION OUTPUT ;
    USE SIGNAL ;
    PORT
      LAYER M5 ;
        RECT  42.144 21.408 42.168 21.6 ;
    END
  END o[223]
  PIN o[224]
    DIRECTION OUTPUT ;
    USE SIGNAL ;
    PORT
      LAYER M5 ;
        RECT  42.288 21.408 42.312 21.6 ;
    END
  END o[224]
  PIN o[225]
    DIRECTION OUTPUT ;
    USE SIGNAL ;
    PORT
      LAYER M5 ;
        RECT  42.48 21.408 42.504 21.6 ;
    END
  END o[225]
  PIN o[226]
    DIRECTION OUTPUT ;
    USE SIGNAL ;
    PORT
      LAYER M5 ;
        RECT  42.624 21.408 42.648 21.6 ;
    END
  END o[226]
  PIN o[227]
    DIRECTION OUTPUT ;
    USE SIGNAL ;
    PORT
      LAYER M5 ;
        RECT  42.816 21.408 42.84 21.6 ;
    END
  END o[227]
  PIN o[228]
    DIRECTION OUTPUT ;
    USE SIGNAL ;
    PORT
      LAYER M5 ;
        RECT  42.96 21.408 42.984 21.6 ;
    END
  END o[228]
  PIN o[229]
    DIRECTION OUTPUT ;
    USE SIGNAL ;
    PORT
      LAYER M5 ;
        RECT  43.152 21.408 43.176 21.6 ;
    END
  END o[229]
  PIN o[22]
    DIRECTION OUTPUT ;
    USE SIGNAL ;
    PORT
      LAYER M5 ;
        RECT  8.016 21.408 8.04 21.6 ;
    END
  END o[22]
  PIN o[230]
    DIRECTION OUTPUT ;
    USE SIGNAL ;
    PORT
      LAYER M5 ;
        RECT  43.296 21.408 43.32 21.6 ;
    END
  END o[230]
  PIN o[231]
    DIRECTION OUTPUT ;
    USE SIGNAL ;
    PORT
      LAYER M5 ;
        RECT  43.488 21.408 43.512 21.6 ;
    END
  END o[231]
  PIN o[232]
    DIRECTION OUTPUT ;
    USE SIGNAL ;
    PORT
      LAYER M5 ;
        RECT  43.68 21.408 43.704 21.6 ;
    END
  END o[232]
  PIN o[233]
    DIRECTION OUTPUT ;
    USE SIGNAL ;
    PORT
      LAYER M5 ;
        RECT  43.824 21.408 43.848 21.6 ;
    END
  END o[233]
  PIN o[234]
    DIRECTION OUTPUT ;
    USE SIGNAL ;
    PORT
      LAYER M5 ;
        RECT  44.016 21.408 44.04 21.6 ;
    END
  END o[234]
  PIN o[235]
    DIRECTION OUTPUT ;
    USE SIGNAL ;
    PORT
      LAYER M5 ;
        RECT  44.16 21.408 44.184 21.6 ;
    END
  END o[235]
  PIN o[236]
    DIRECTION OUTPUT ;
    USE SIGNAL ;
    PORT
      LAYER M5 ;
        RECT  44.352 21.408 44.376 21.6 ;
    END
  END o[236]
  PIN o[237]
    DIRECTION OUTPUT ;
    USE SIGNAL ;
    PORT
      LAYER M5 ;
        RECT  44.496 21.408 44.52 21.6 ;
    END
  END o[237]
  PIN o[238]
    DIRECTION OUTPUT ;
    USE SIGNAL ;
    PORT
      LAYER M5 ;
        RECT  44.688 21.408 44.712 21.6 ;
    END
  END o[238]
  PIN o[239]
    DIRECTION OUTPUT ;
    USE SIGNAL ;
    PORT
      LAYER M5 ;
        RECT  44.832 21.408 44.856 21.6 ;
    END
  END o[239]
  PIN o[23]
    DIRECTION OUTPUT ;
    USE SIGNAL ;
    PORT
      LAYER M5 ;
        RECT  8.208 21.408 8.232 21.6 ;
    END
  END o[23]
  PIN o[240]
    DIRECTION OUTPUT ;
    USE SIGNAL ;
    PORT
      LAYER M5 ;
        RECT  45.024 21.408 45.048 21.6 ;
    END
  END o[240]
  PIN o[241]
    DIRECTION OUTPUT ;
    USE SIGNAL ;
    PORT
      LAYER M5 ;
        RECT  45.168 21.408 45.192 21.6 ;
    END
  END o[241]
  PIN o[242]
    DIRECTION OUTPUT ;
    USE SIGNAL ;
    PORT
      LAYER M5 ;
        RECT  45.36 21.408 45.384 21.6 ;
    END
  END o[242]
  PIN o[243]
    DIRECTION OUTPUT ;
    USE SIGNAL ;
    PORT
      LAYER M5 ;
        RECT  45.504 21.408 45.528 21.6 ;
    END
  END o[243]
  PIN o[244]
    DIRECTION OUTPUT ;
    USE SIGNAL ;
    PORT
      LAYER M5 ;
        RECT  45.696 21.408 45.72 21.6 ;
    END
  END o[244]
  PIN o[245]
    DIRECTION OUTPUT ;
    USE SIGNAL ;
    PORT
      LAYER M5 ;
        RECT  45.84 21.408 45.864 21.6 ;
    END
  END o[245]
  PIN o[246]
    DIRECTION OUTPUT ;
    USE SIGNAL ;
    PORT
      LAYER M5 ;
        RECT  46.032 21.408 46.056 21.6 ;
    END
  END o[246]
  PIN o[247]
    DIRECTION OUTPUT ;
    USE SIGNAL ;
    PORT
      LAYER M5 ;
        RECT  46.224 21.408 46.248 21.6 ;
    END
  END o[247]
  PIN o[248]
    DIRECTION OUTPUT ;
    USE SIGNAL ;
    PORT
      LAYER M5 ;
        RECT  46.368 21.408 46.392 21.6 ;
    END
  END o[248]
  PIN o[249]
    DIRECTION OUTPUT ;
    USE SIGNAL ;
    PORT
      LAYER M5 ;
        RECT  46.56 21.408 46.584 21.6 ;
    END
  END o[249]
  PIN o[24]
    DIRECTION OUTPUT ;
    USE SIGNAL ;
    PORT
      LAYER M5 ;
        RECT  8.4 21.408 8.424 21.6 ;
    END
  END o[24]
  PIN o[250]
    DIRECTION OUTPUT ;
    USE SIGNAL ;
    PORT
      LAYER M5 ;
        RECT  46.704 21.408 46.728 21.6 ;
    END
  END o[250]
  PIN o[251]
    DIRECTION OUTPUT ;
    USE SIGNAL ;
    PORT
      LAYER M5 ;
        RECT  46.896 21.408 46.92 21.6 ;
    END
  END o[251]
  PIN o[252]
    DIRECTION OUTPUT ;
    USE SIGNAL ;
    PORT
      LAYER M5 ;
        RECT  47.04 21.408 47.064 21.6 ;
    END
  END o[252]
  PIN o[253]
    DIRECTION OUTPUT ;
    USE SIGNAL ;
    PORT
      LAYER M5 ;
        RECT  47.232 21.408 47.256 21.6 ;
    END
  END o[253]
  PIN o[254]
    DIRECTION OUTPUT ;
    USE SIGNAL ;
    PORT
      LAYER M5 ;
        RECT  47.376 21.408 47.4 21.6 ;
    END
  END o[254]
  PIN o[255]
    DIRECTION OUTPUT ;
    USE SIGNAL ;
    PORT
      LAYER M5 ;
        RECT  47.568 21.408 47.592 21.6 ;
    END
  END o[255]
  PIN o[256]
    DIRECTION OUTPUT ;
    USE SIGNAL ;
    PORT
      LAYER M5 ;
        RECT  47.712 21.408 47.736 21.6 ;
    END
  END o[256]
  PIN o[257]
    DIRECTION OUTPUT ;
    USE SIGNAL ;
    PORT
      LAYER M5 ;
        RECT  47.904 21.408 47.928 21.6 ;
    END
  END o[257]
  PIN o[258]
    DIRECTION OUTPUT ;
    USE SIGNAL ;
    PORT
      LAYER M5 ;
        RECT  48.048 21.408 48.072 21.6 ;
    END
  END o[258]
  PIN o[259]
    DIRECTION OUTPUT ;
    USE SIGNAL ;
    PORT
      LAYER M5 ;
        RECT  48.24 21.408 48.264 21.6 ;
    END
  END o[259]
  PIN o[25]
    DIRECTION OUTPUT ;
    USE SIGNAL ;
    PORT
      LAYER M5 ;
        RECT  8.544 21.408 8.568 21.6 ;
    END
  END o[25]
  PIN o[260]
    DIRECTION OUTPUT ;
    USE SIGNAL ;
    PORT
      LAYER M5 ;
        RECT  48.384 21.408 48.408 21.6 ;
    END
  END o[260]
  PIN o[261]
    DIRECTION OUTPUT ;
    USE SIGNAL ;
    PORT
      LAYER M5 ;
        RECT  48.576 21.408 48.6 21.6 ;
    END
  END o[261]
  PIN o[262]
    DIRECTION OUTPUT ;
    USE SIGNAL ;
    PORT
      LAYER M5 ;
        RECT  48.768 21.408 48.792 21.6 ;
    END
  END o[262]
  PIN o[263]
    DIRECTION OUTPUT ;
    USE SIGNAL ;
    PORT
      LAYER M5 ;
        RECT  48.912 21.408 48.936 21.6 ;
    END
  END o[263]
  PIN o[264]
    DIRECTION OUTPUT ;
    USE SIGNAL ;
    PORT
      LAYER M5 ;
        RECT  49.104 21.408 49.128 21.6 ;
    END
  END o[264]
  PIN o[265]
    DIRECTION OUTPUT ;
    USE SIGNAL ;
    PORT
      LAYER M5 ;
        RECT  49.248 21.408 49.272 21.6 ;
    END
  END o[265]
  PIN o[266]
    DIRECTION OUTPUT ;
    USE SIGNAL ;
    PORT
      LAYER M5 ;
        RECT  49.44 21.408 49.464 21.6 ;
    END
  END o[266]
  PIN o[267]
    DIRECTION OUTPUT ;
    USE SIGNAL ;
    PORT
      LAYER M5 ;
        RECT  49.584 21.408 49.608 21.6 ;
    END
  END o[267]
  PIN o[268]
    DIRECTION OUTPUT ;
    USE SIGNAL ;
    PORT
      LAYER M5 ;
        RECT  49.776 21.408 49.8 21.6 ;
    END
  END o[268]
  PIN o[269]
    DIRECTION OUTPUT ;
    USE SIGNAL ;
    PORT
      LAYER M5 ;
        RECT  49.92 21.408 49.944 21.6 ;
    END
  END o[269]
  PIN o[26]
    DIRECTION OUTPUT ;
    USE SIGNAL ;
    PORT
      LAYER M5 ;
        RECT  8.736 21.408 8.76 21.6 ;
    END
  END o[26]
  PIN o[270]
    DIRECTION OUTPUT ;
    USE SIGNAL ;
    PORT
      LAYER M5 ;
        RECT  50.112 21.408 50.136 21.6 ;
    END
  END o[270]
  PIN o[271]
    DIRECTION OUTPUT ;
    USE SIGNAL ;
    PORT
      LAYER M5 ;
        RECT  50.256 21.408 50.28 21.6 ;
    END
  END o[271]
  PIN o[272]
    DIRECTION OUTPUT ;
    USE SIGNAL ;
    PORT
      LAYER M5 ;
        RECT  50.448 21.408 50.472 21.6 ;
    END
  END o[272]
  PIN o[273]
    DIRECTION OUTPUT ;
    USE SIGNAL ;
    PORT
      LAYER M5 ;
        RECT  50.592 21.408 50.616 21.6 ;
    END
  END o[273]
  PIN o[274]
    DIRECTION OUTPUT ;
    USE SIGNAL ;
    PORT
      LAYER M5 ;
        RECT  50.784 21.408 50.808 21.6 ;
    END
  END o[274]
  PIN o[275]
    DIRECTION OUTPUT ;
    USE SIGNAL ;
    PORT
      LAYER M5 ;
        RECT  50.976 21.408 51 21.6 ;
    END
  END o[275]
  PIN o[276]
    DIRECTION OUTPUT ;
    USE SIGNAL ;
    PORT
      LAYER M5 ;
        RECT  51.12 21.408 51.144 21.6 ;
    END
  END o[276]
  PIN o[277]
    DIRECTION OUTPUT ;
    USE SIGNAL ;
    PORT
      LAYER M5 ;
        RECT  51.312 21.408 51.336 21.6 ;
    END
  END o[277]
  PIN o[278]
    DIRECTION OUTPUT ;
    USE SIGNAL ;
    PORT
      LAYER M5 ;
        RECT  51.456 21.408 51.48 21.6 ;
    END
  END o[278]
  PIN o[279]
    DIRECTION OUTPUT ;
    USE SIGNAL ;
    PORT
      LAYER M5 ;
        RECT  51.648 21.408 51.672 21.6 ;
    END
  END o[279]
  PIN o[27]
    DIRECTION OUTPUT ;
    USE SIGNAL ;
    PORT
      LAYER M5 ;
        RECT  8.88 21.408 8.904 21.6 ;
    END
  END o[27]
  PIN o[280]
    DIRECTION OUTPUT ;
    USE SIGNAL ;
    PORT
      LAYER M5 ;
        RECT  51.792 21.408 51.816 21.6 ;
    END
  END o[280]
  PIN o[281]
    DIRECTION OUTPUT ;
    USE SIGNAL ;
    PORT
      LAYER M5 ;
        RECT  51.984 21.408 52.008 21.6 ;
    END
  END o[281]
  PIN o[282]
    DIRECTION OUTPUT ;
    USE SIGNAL ;
    PORT
      LAYER M5 ;
        RECT  52.128 21.408 52.152 21.6 ;
    END
  END o[282]
  PIN o[283]
    DIRECTION OUTPUT ;
    USE SIGNAL ;
    PORT
      LAYER M5 ;
        RECT  52.32 21.408 52.344 21.6 ;
    END
  END o[283]
  PIN o[284]
    DIRECTION OUTPUT ;
    USE SIGNAL ;
    PORT
      LAYER M5 ;
        RECT  52.464 21.408 52.488 21.6 ;
    END
  END o[284]
  PIN o[285]
    DIRECTION OUTPUT ;
    USE SIGNAL ;
    PORT
      LAYER M5 ;
        RECT  52.656 21.408 52.68 21.6 ;
    END
  END o[285]
  PIN o[286]
    DIRECTION OUTPUT ;
    USE SIGNAL ;
    PORT
      LAYER M5 ;
        RECT  52.8 21.408 52.824 21.6 ;
    END
  END o[286]
  PIN o[287]
    DIRECTION OUTPUT ;
    USE SIGNAL ;
    PORT
      LAYER M5 ;
        RECT  52.992 21.408 53.016 21.6 ;
    END
  END o[287]
  PIN o[288]
    DIRECTION OUTPUT ;
    USE SIGNAL ;
    PORT
      LAYER M5 ;
        RECT  53.136 21.408 53.16 21.6 ;
    END
  END o[288]
  PIN o[289]
    DIRECTION OUTPUT ;
    USE SIGNAL ;
    PORT
      LAYER M5 ;
        RECT  53.328 21.408 53.352 21.6 ;
    END
  END o[289]
  PIN o[28]
    DIRECTION OUTPUT ;
    USE SIGNAL ;
    PORT
      LAYER M5 ;
        RECT  9.072 21.408 9.096 21.6 ;
    END
  END o[28]
  PIN o[290]
    DIRECTION OUTPUT ;
    USE SIGNAL ;
    PORT
      LAYER M5 ;
        RECT  53.52 21.408 53.544 21.6 ;
    END
  END o[290]
  PIN o[291]
    DIRECTION OUTPUT ;
    USE SIGNAL ;
    PORT
      LAYER M5 ;
        RECT  53.664 21.408 53.688 21.6 ;
    END
  END o[291]
  PIN o[292]
    DIRECTION OUTPUT ;
    USE SIGNAL ;
    PORT
      LAYER M5 ;
        RECT  53.856 21.408 53.88 21.6 ;
    END
  END o[292]
  PIN o[293]
    DIRECTION OUTPUT ;
    USE SIGNAL ;
    PORT
      LAYER M5 ;
        RECT  54 21.408 54.024 21.6 ;
    END
  END o[293]
  PIN o[294]
    DIRECTION OUTPUT ;
    USE SIGNAL ;
    PORT
      LAYER M5 ;
        RECT  54.192 21.408 54.216 21.6 ;
    END
  END o[294]
  PIN o[295]
    DIRECTION OUTPUT ;
    USE SIGNAL ;
    PORT
      LAYER M5 ;
        RECT  54.336 21.408 54.36 21.6 ;
    END
  END o[295]
  PIN o[296]
    DIRECTION OUTPUT ;
    USE SIGNAL ;
    PORT
      LAYER M5 ;
        RECT  54.528 21.408 54.552 21.6 ;
    END
  END o[296]
  PIN o[297]
    DIRECTION OUTPUT ;
    USE SIGNAL ;
    PORT
      LAYER M5 ;
        RECT  54.672 21.408 54.696 21.6 ;
    END
  END o[297]
  PIN o[298]
    DIRECTION OUTPUT ;
    USE SIGNAL ;
    PORT
      LAYER M5 ;
        RECT  54.864 21.408 54.888 21.6 ;
    END
  END o[298]
  PIN o[299]
    DIRECTION OUTPUT ;
    USE SIGNAL ;
    PORT
      LAYER M5 ;
        RECT  55.008 21.408 55.032 21.6 ;
    END
  END o[299]
  PIN o[29]
    DIRECTION OUTPUT ;
    USE SIGNAL ;
    PORT
      LAYER M5 ;
        RECT  9.216 21.408 9.24 21.6 ;
    END
  END o[29]
  PIN o[2]
    DIRECTION OUTPUT ;
    USE SIGNAL ;
    PORT
      LAYER M5 ;
        RECT  4.656 21.408 4.68 21.6 ;
    END
  END o[2]
  PIN o[300]
    DIRECTION OUTPUT ;
    USE SIGNAL ;
    PORT
      LAYER M5 ;
        RECT  55.2 21.408 55.224 21.6 ;
    END
  END o[300]
  PIN o[301]
    DIRECTION OUTPUT ;
    USE SIGNAL ;
    PORT
      LAYER M5 ;
        RECT  55.344 21.408 55.368 21.6 ;
    END
  END o[301]
  PIN o[302]
    DIRECTION OUTPUT ;
    USE SIGNAL ;
    PORT
      LAYER M5 ;
        RECT  55.536 21.408 55.56 21.6 ;
    END
  END o[302]
  PIN o[303]
    DIRECTION OUTPUT ;
    USE SIGNAL ;
    PORT
      LAYER M5 ;
        RECT  55.68 21.408 55.704 21.6 ;
    END
  END o[303]
  PIN o[304]
    DIRECTION OUTPUT ;
    USE SIGNAL ;
    PORT
      LAYER M5 ;
        RECT  55.872 21.408 55.896 21.6 ;
    END
  END o[304]
  PIN o[305]
    DIRECTION OUTPUT ;
    USE SIGNAL ;
    PORT
      LAYER M5 ;
        RECT  56.064 21.408 56.088 21.6 ;
    END
  END o[305]
  PIN o[306]
    DIRECTION OUTPUT ;
    USE SIGNAL ;
    PORT
      LAYER M5 ;
        RECT  56.208 21.408 56.232 21.6 ;
    END
  END o[306]
  PIN o[307]
    DIRECTION OUTPUT ;
    USE SIGNAL ;
    PORT
      LAYER M5 ;
        RECT  56.4 21.408 56.424 21.6 ;
    END
  END o[307]
  PIN o[308]
    DIRECTION OUTPUT ;
    USE SIGNAL ;
    PORT
      LAYER M5 ;
        RECT  56.544 21.408 56.568 21.6 ;
    END
  END o[308]
  PIN o[309]
    DIRECTION OUTPUT ;
    USE SIGNAL ;
    PORT
      LAYER M5 ;
        RECT  56.736 21.408 56.76 21.6 ;
    END
  END o[309]
  PIN o[30]
    DIRECTION OUTPUT ;
    USE SIGNAL ;
    PORT
      LAYER M5 ;
        RECT  9.408 21.408 9.432 21.6 ;
    END
  END o[30]
  PIN o[310]
    DIRECTION OUTPUT ;
    USE SIGNAL ;
    PORT
      LAYER M5 ;
        RECT  56.88 21.408 56.904 21.6 ;
    END
  END o[310]
  PIN o[311]
    DIRECTION OUTPUT ;
    USE SIGNAL ;
    PORT
      LAYER M5 ;
        RECT  57.072 21.408 57.096 21.6 ;
    END
  END o[311]
  PIN o[312]
    DIRECTION OUTPUT ;
    USE SIGNAL ;
    PORT
      LAYER M5 ;
        RECT  57.408 21.408 57.432 21.6 ;
    END
  END o[312]
  PIN o[313]
    DIRECTION OUTPUT ;
    USE SIGNAL ;
    PORT
      LAYER M5 ;
        RECT  57.552 21.408 57.576 21.6 ;
    END
  END o[313]
  PIN o[314]
    DIRECTION OUTPUT ;
    USE SIGNAL ;
    PORT
      LAYER M5 ;
        RECT  57.744 21.408 57.768 21.6 ;
    END
  END o[314]
  PIN o[315]
    DIRECTION OUTPUT ;
    USE SIGNAL ;
    PORT
      LAYER M5 ;
        RECT  57.888 21.408 57.912 21.6 ;
    END
  END o[315]
  PIN o[316]
    DIRECTION OUTPUT ;
    USE SIGNAL ;
    PORT
      LAYER M5 ;
        RECT  58.08 21.408 58.104 21.6 ;
    END
  END o[316]
  PIN o[317]
    DIRECTION OUTPUT ;
    USE SIGNAL ;
    PORT
      LAYER M5 ;
        RECT  58.224 21.408 58.248 21.6 ;
    END
  END o[317]
  PIN o[318]
    DIRECTION OUTPUT ;
    USE SIGNAL ;
    PORT
      LAYER M5 ;
        RECT  58.416 21.408 58.44 21.6 ;
    END
  END o[318]
  PIN o[319]
    DIRECTION OUTPUT ;
    USE SIGNAL ;
    PORT
      LAYER M5 ;
        RECT  58.608 21.408 58.632 21.6 ;
    END
  END o[319]
  PIN o[31]
    DIRECTION OUTPUT ;
    USE SIGNAL ;
    PORT
      LAYER M5 ;
        RECT  9.552 21.408 9.576 21.6 ;
    END
  END o[31]
  PIN o[320]
    DIRECTION OUTPUT ;
    USE SIGNAL ;
    PORT
      LAYER M5 ;
        RECT  58.752 21.408 58.776 21.6 ;
    END
  END o[320]
  PIN o[321]
    DIRECTION OUTPUT ;
    USE SIGNAL ;
    PORT
      LAYER M5 ;
        RECT  58.944 21.408 58.968 21.6 ;
    END
  END o[321]
  PIN o[322]
    DIRECTION OUTPUT ;
    USE SIGNAL ;
    PORT
      LAYER M5 ;
        RECT  59.088 21.408 59.112 21.6 ;
    END
  END o[322]
  PIN o[323]
    DIRECTION OUTPUT ;
    USE SIGNAL ;
    PORT
      LAYER M5 ;
        RECT  59.28 21.408 59.304 21.6 ;
    END
  END o[323]
  PIN o[324]
    DIRECTION OUTPUT ;
    USE SIGNAL ;
    PORT
      LAYER M5 ;
        RECT  59.424 21.408 59.448 21.6 ;
    END
  END o[324]
  PIN o[325]
    DIRECTION OUTPUT ;
    USE SIGNAL ;
    PORT
      LAYER M5 ;
        RECT  59.616 21.408 59.64 21.6 ;
    END
  END o[325]
  PIN o[326]
    DIRECTION OUTPUT ;
    USE SIGNAL ;
    PORT
      LAYER M5 ;
        RECT  59.76 21.408 59.784 21.6 ;
    END
  END o[326]
  PIN o[327]
    DIRECTION OUTPUT ;
    USE SIGNAL ;
    PORT
      LAYER M5 ;
        RECT  59.952 21.408 59.976 21.6 ;
    END
  END o[327]
  PIN o[328]
    DIRECTION OUTPUT ;
    USE SIGNAL ;
    PORT
      LAYER M5 ;
        RECT  60.096 21.408 60.12 21.6 ;
    END
  END o[328]
  PIN o[329]
    DIRECTION OUTPUT ;
    USE SIGNAL ;
    PORT
      LAYER M5 ;
        RECT  60.288 21.408 60.312 21.6 ;
    END
  END o[329]
  PIN o[32]
    DIRECTION OUTPUT ;
    USE SIGNAL ;
    PORT
      LAYER M5 ;
        RECT  9.744 21.408 9.768 21.6 ;
    END
  END o[32]
  PIN o[330]
    DIRECTION OUTPUT ;
    USE SIGNAL ;
    PORT
      LAYER M5 ;
        RECT  60.432 21.408 60.456 21.6 ;
    END
  END o[330]
  PIN o[331]
    DIRECTION OUTPUT ;
    USE SIGNAL ;
    PORT
      LAYER M5 ;
        RECT  60.624 21.408 60.648 21.6 ;
    END
  END o[331]
  PIN o[332]
    DIRECTION OUTPUT ;
    USE SIGNAL ;
    PORT
      LAYER M5 ;
        RECT  60.768 21.408 60.792 21.6 ;
    END
  END o[332]
  PIN o[333]
    DIRECTION OUTPUT ;
    USE SIGNAL ;
    PORT
      LAYER M5 ;
        RECT  60.96 21.408 60.984 21.6 ;
    END
  END o[333]
  PIN o[334]
    DIRECTION OUTPUT ;
    USE SIGNAL ;
    PORT
      LAYER M5 ;
        RECT  61.152 21.408 61.176 21.6 ;
    END
  END o[334]
  PIN o[335]
    DIRECTION OUTPUT ;
    USE SIGNAL ;
    PORT
      LAYER M5 ;
        RECT  61.296 21.408 61.32 21.6 ;
    END
  END o[335]
  PIN o[336]
    DIRECTION OUTPUT ;
    USE SIGNAL ;
    PORT
      LAYER M5 ;
        RECT  61.488 21.408 61.512 21.6 ;
    END
  END o[336]
  PIN o[337]
    DIRECTION OUTPUT ;
    USE SIGNAL ;
    PORT
      LAYER M5 ;
        RECT  61.632 21.408 61.656 21.6 ;
    END
  END o[337]
  PIN o[338]
    DIRECTION OUTPUT ;
    USE SIGNAL ;
    PORT
      LAYER M5 ;
        RECT  61.824 21.408 61.848 21.6 ;
    END
  END o[338]
  PIN o[339]
    DIRECTION OUTPUT ;
    USE SIGNAL ;
    PORT
      LAYER M5 ;
        RECT  61.968 21.408 61.992 21.6 ;
    END
  END o[339]
  PIN o[33]
    DIRECTION OUTPUT ;
    USE SIGNAL ;
    PORT
      LAYER M5 ;
        RECT  9.888 21.408 9.912 21.6 ;
    END
  END o[33]
  PIN o[340]
    DIRECTION OUTPUT ;
    USE SIGNAL ;
    PORT
      LAYER M5 ;
        RECT  62.16 21.408 62.184 21.6 ;
    END
  END o[340]
  PIN o[341]
    DIRECTION OUTPUT ;
    USE SIGNAL ;
    PORT
      LAYER M5 ;
        RECT  62.304 21.408 62.328 21.6 ;
    END
  END o[341]
  PIN o[342]
    DIRECTION OUTPUT ;
    USE SIGNAL ;
    PORT
      LAYER M5 ;
        RECT  62.496 21.408 62.52 21.6 ;
    END
  END o[342]
  PIN o[343]
    DIRECTION OUTPUT ;
    USE SIGNAL ;
    PORT
      LAYER M5 ;
        RECT  62.64 21.408 62.664 21.6 ;
    END
  END o[343]
  PIN o[344]
    DIRECTION OUTPUT ;
    USE SIGNAL ;
    PORT
      LAYER M5 ;
        RECT  62.832 21.408 62.856 21.6 ;
    END
  END o[344]
  PIN o[345]
    DIRECTION OUTPUT ;
    USE SIGNAL ;
    PORT
      LAYER M5 ;
        RECT  62.976 21.408 63 21.6 ;
    END
  END o[345]
  PIN o[346]
    DIRECTION OUTPUT ;
    USE SIGNAL ;
    PORT
      LAYER M5 ;
        RECT  63.168 21.408 63.192 21.6 ;
    END
  END o[346]
  PIN o[347]
    DIRECTION OUTPUT ;
    USE SIGNAL ;
    PORT
      LAYER M5 ;
        RECT  63.312 21.408 63.336 21.6 ;
    END
  END o[347]
  PIN o[348]
    DIRECTION OUTPUT ;
    USE SIGNAL ;
    PORT
      LAYER M5 ;
        RECT  63.504 21.408 63.528 21.6 ;
    END
  END o[348]
  PIN o[349]
    DIRECTION OUTPUT ;
    USE SIGNAL ;
    PORT
      LAYER M5 ;
        RECT  63.696 21.408 63.72 21.6 ;
    END
  END o[349]
  PIN o[34]
    DIRECTION OUTPUT ;
    USE SIGNAL ;
    PORT
      LAYER M5 ;
        RECT  10.08 21.408 10.104 21.6 ;
    END
  END o[34]
  PIN o[350]
    DIRECTION OUTPUT ;
    USE SIGNAL ;
    PORT
      LAYER M5 ;
        RECT  63.84 21.408 63.864 21.6 ;
    END
  END o[350]
  PIN o[351]
    DIRECTION OUTPUT ;
    USE SIGNAL ;
    PORT
      LAYER M5 ;
        RECT  64.032 21.408 64.056 21.6 ;
    END
  END o[351]
  PIN o[352]
    DIRECTION OUTPUT ;
    USE SIGNAL ;
    PORT
      LAYER M5 ;
        RECT  64.176 21.408 64.2 21.6 ;
    END
  END o[352]
  PIN o[353]
    DIRECTION OUTPUT ;
    USE SIGNAL ;
    PORT
      LAYER M5 ;
        RECT  64.368 21.408 64.392 21.6 ;
    END
  END o[353]
  PIN o[354]
    DIRECTION OUTPUT ;
    USE SIGNAL ;
    PORT
      LAYER M5 ;
        RECT  64.512 21.408 64.536 21.6 ;
    END
  END o[354]
  PIN o[355]
    DIRECTION OUTPUT ;
    USE SIGNAL ;
    PORT
      LAYER M5 ;
        RECT  64.704 21.408 64.728 21.6 ;
    END
  END o[355]
  PIN o[356]
    DIRECTION OUTPUT ;
    USE SIGNAL ;
    PORT
      LAYER M5 ;
        RECT  64.848 21.408 64.872 21.6 ;
    END
  END o[356]
  PIN o[357]
    DIRECTION OUTPUT ;
    USE SIGNAL ;
    PORT
      LAYER M5 ;
        RECT  65.04 21.408 65.064 21.6 ;
    END
  END o[357]
  PIN o[358]
    DIRECTION OUTPUT ;
    USE SIGNAL ;
    PORT
      LAYER M5 ;
        RECT  65.184 21.408 65.208 21.6 ;
    END
  END o[358]
  PIN o[359]
    DIRECTION OUTPUT ;
    USE SIGNAL ;
    PORT
      LAYER M5 ;
        RECT  65.376 21.408 65.4 21.6 ;
    END
  END o[359]
  PIN o[35]
    DIRECTION OUTPUT ;
    USE SIGNAL ;
    PORT
      LAYER M5 ;
        RECT  10.224 21.408 10.248 21.6 ;
    END
  END o[35]
  PIN o[360]
    DIRECTION OUTPUT ;
    USE SIGNAL ;
    PORT
      LAYER M5 ;
        RECT  65.52 21.408 65.544 21.6 ;
    END
  END o[360]
  PIN o[361]
    DIRECTION OUTPUT ;
    USE SIGNAL ;
    PORT
      LAYER M5 ;
        RECT  65.712 21.408 65.736 21.6 ;
    END
  END o[361]
  PIN o[362]
    DIRECTION OUTPUT ;
    USE SIGNAL ;
    PORT
      LAYER M5 ;
        RECT  65.856 21.408 65.88 21.6 ;
    END
  END o[362]
  PIN o[363]
    DIRECTION OUTPUT ;
    USE SIGNAL ;
    PORT
      LAYER M5 ;
        RECT  66.048 21.408 66.072 21.6 ;
    END
  END o[363]
  PIN o[364]
    DIRECTION OUTPUT ;
    USE SIGNAL ;
    PORT
      LAYER M5 ;
        RECT  66.24 21.408 66.264 21.6 ;
    END
  END o[364]
  PIN o[365]
    DIRECTION OUTPUT ;
    USE SIGNAL ;
    PORT
      LAYER M5 ;
        RECT  66.384 21.408 66.408 21.6 ;
    END
  END o[365]
  PIN o[366]
    DIRECTION OUTPUT ;
    USE SIGNAL ;
    PORT
      LAYER M5 ;
        RECT  66.576 21.408 66.6 21.6 ;
    END
  END o[366]
  PIN o[367]
    DIRECTION OUTPUT ;
    USE SIGNAL ;
    PORT
      LAYER M5 ;
        RECT  66.72 21.408 66.744 21.6 ;
    END
  END o[367]
  PIN o[368]
    DIRECTION OUTPUT ;
    USE SIGNAL ;
    PORT
      LAYER M5 ;
        RECT  66.912 21.408 66.936 21.6 ;
    END
  END o[368]
  PIN o[369]
    DIRECTION OUTPUT ;
    USE SIGNAL ;
    PORT
      LAYER M5 ;
        RECT  67.056 21.408 67.08 21.6 ;
    END
  END o[369]
  PIN o[36]
    DIRECTION OUTPUT ;
    USE SIGNAL ;
    PORT
      LAYER M5 ;
        RECT  10.416 21.408 10.44 21.6 ;
    END
  END o[36]
  PIN o[370]
    DIRECTION OUTPUT ;
    USE SIGNAL ;
    PORT
      LAYER M5 ;
        RECT  67.248 21.408 67.272 21.6 ;
    END
  END o[370]
  PIN o[371]
    DIRECTION OUTPUT ;
    USE SIGNAL ;
    PORT
      LAYER M5 ;
        RECT  67.392 21.408 67.416 21.6 ;
    END
  END o[371]
  PIN o[372]
    DIRECTION OUTPUT ;
    USE SIGNAL ;
    PORT
      LAYER M5 ;
        RECT  67.584 21.408 67.608 21.6 ;
    END
  END o[372]
  PIN o[373]
    DIRECTION OUTPUT ;
    USE SIGNAL ;
    PORT
      LAYER M5 ;
        RECT  67.728 21.408 67.752 21.6 ;
    END
  END o[373]
  PIN o[374]
    DIRECTION OUTPUT ;
    USE SIGNAL ;
    PORT
      LAYER M5 ;
        RECT  67.92 21.408 67.944 21.6 ;
    END
  END o[374]
  PIN o[375]
    DIRECTION OUTPUT ;
    USE SIGNAL ;
    PORT
      LAYER M5 ;
        RECT  68.064 21.408 68.088 21.6 ;
    END
  END o[375]
  PIN o[376]
    DIRECTION OUTPUT ;
    USE SIGNAL ;
    PORT
      LAYER M5 ;
        RECT  68.256 21.408 68.28 21.6 ;
    END
  END o[376]
  PIN o[377]
    DIRECTION OUTPUT ;
    USE SIGNAL ;
    PORT
      LAYER M5 ;
        RECT  68.4 21.408 68.424 21.6 ;
    END
  END o[377]
  PIN o[378]
    DIRECTION OUTPUT ;
    USE SIGNAL ;
    PORT
      LAYER M5 ;
        RECT  68.592 21.408 68.616 21.6 ;
    END
  END o[378]
  PIN o[379]
    DIRECTION OUTPUT ;
    USE SIGNAL ;
    PORT
      LAYER M5 ;
        RECT  68.784 21.408 68.808 21.6 ;
    END
  END o[379]
  PIN o[37]
    DIRECTION OUTPUT ;
    USE SIGNAL ;
    PORT
      LAYER M5 ;
        RECT  10.56 21.408 10.584 21.6 ;
    END
  END o[37]
  PIN o[380]
    DIRECTION OUTPUT ;
    USE SIGNAL ;
    PORT
      LAYER M5 ;
        RECT  68.928 21.408 68.952 21.6 ;
    END
  END o[380]
  PIN o[381]
    DIRECTION OUTPUT ;
    USE SIGNAL ;
    PORT
      LAYER M5 ;
        RECT  69.12 21.408 69.144 21.6 ;
    END
  END o[381]
  PIN o[382]
    DIRECTION OUTPUT ;
    USE SIGNAL ;
    PORT
      LAYER M5 ;
        RECT  69.264 21.408 69.288 21.6 ;
    END
  END o[382]
  PIN o[383]
    DIRECTION OUTPUT ;
    USE SIGNAL ;
    PORT
      LAYER M5 ;
        RECT  69.456 21.408 69.48 21.6 ;
    END
  END o[383]
  PIN o[384]
    DIRECTION OUTPUT ;
    USE SIGNAL ;
    PORT
      LAYER M5 ;
        RECT  69.6 21.408 69.624 21.6 ;
    END
  END o[384]
  PIN o[385]
    DIRECTION OUTPUT ;
    USE SIGNAL ;
    PORT
      LAYER M5 ;
        RECT  69.792 21.408 69.816 21.6 ;
    END
  END o[385]
  PIN o[386]
    DIRECTION OUTPUT ;
    USE SIGNAL ;
    PORT
      LAYER M5 ;
        RECT  69.936 21.408 69.96 21.6 ;
    END
  END o[386]
  PIN o[387]
    DIRECTION OUTPUT ;
    USE SIGNAL ;
    PORT
      LAYER M5 ;
        RECT  70.128 21.408 70.152 21.6 ;
    END
  END o[387]
  PIN o[388]
    DIRECTION OUTPUT ;
    USE SIGNAL ;
    PORT
      LAYER M5 ;
        RECT  70.272 21.408 70.296 21.6 ;
    END
  END o[388]
  PIN o[389]
    DIRECTION OUTPUT ;
    USE SIGNAL ;
    PORT
      LAYER M5 ;
        RECT  70.464 21.408 70.488 21.6 ;
    END
  END o[389]
  PIN o[38]
    DIRECTION OUTPUT ;
    USE SIGNAL ;
    PORT
      LAYER M5 ;
        RECT  10.752 21.408 10.776 21.6 ;
    END
  END o[38]
  PIN o[390]
    DIRECTION OUTPUT ;
    USE SIGNAL ;
    PORT
      LAYER M5 ;
        RECT  70.608 21.408 70.632 21.6 ;
    END
  END o[390]
  PIN o[391]
    DIRECTION OUTPUT ;
    USE SIGNAL ;
    PORT
      LAYER M5 ;
        RECT  70.8 21.408 70.824 21.6 ;
    END
  END o[391]
  PIN o[392]
    DIRECTION OUTPUT ;
    USE SIGNAL ;
    PORT
      LAYER M5 ;
        RECT  70.944 21.408 70.968 21.6 ;
    END
  END o[392]
  PIN o[393]
    DIRECTION OUTPUT ;
    USE SIGNAL ;
    PORT
      LAYER M5 ;
        RECT  71.136 21.408 71.16 21.6 ;
    END
  END o[393]
  PIN o[394]
    DIRECTION OUTPUT ;
    USE SIGNAL ;
    PORT
      LAYER M5 ;
        RECT  71.328 21.408 71.352 21.6 ;
    END
  END o[394]
  PIN o[395]
    DIRECTION OUTPUT ;
    USE SIGNAL ;
    PORT
      LAYER M5 ;
        RECT  71.472 21.408 71.496 21.6 ;
    END
  END o[395]
  PIN o[396]
    DIRECTION OUTPUT ;
    USE SIGNAL ;
    PORT
      LAYER M5 ;
        RECT  71.664 21.408 71.688 21.6 ;
    END
  END o[396]
  PIN o[397]
    DIRECTION OUTPUT ;
    USE SIGNAL ;
    PORT
      LAYER M5 ;
        RECT  71.808 21.408 71.832 21.6 ;
    END
  END o[397]
  PIN o[398]
    DIRECTION OUTPUT ;
    USE SIGNAL ;
    PORT
      LAYER M5 ;
        RECT  72 21.408 72.024 21.6 ;
    END
  END o[398]
  PIN o[399]
    DIRECTION OUTPUT ;
    USE SIGNAL ;
    PORT
      LAYER M5 ;
        RECT  72.144 21.408 72.168 21.6 ;
    END
  END o[399]
  PIN o[39]
    DIRECTION OUTPUT ;
    USE SIGNAL ;
    PORT
      LAYER M5 ;
        RECT  10.944 21.408 10.968 21.6 ;
    END
  END o[39]
  PIN o[3]
    DIRECTION OUTPUT ;
    USE SIGNAL ;
    PORT
      LAYER M5 ;
        RECT  4.8 21.408 4.824 21.6 ;
    END
  END o[3]
  PIN o[400]
    DIRECTION OUTPUT ;
    USE SIGNAL ;
    PORT
      LAYER M5 ;
        RECT  72.336 21.408 72.36 21.6 ;
    END
  END o[400]
  PIN o[401]
    DIRECTION OUTPUT ;
    USE SIGNAL ;
    PORT
      LAYER M5 ;
        RECT  72.48 21.408 72.504 21.6 ;
    END
  END o[401]
  PIN o[402]
    DIRECTION OUTPUT ;
    USE SIGNAL ;
    PORT
      LAYER M5 ;
        RECT  72.672 21.408 72.696 21.6 ;
    END
  END o[402]
  PIN o[403]
    DIRECTION OUTPUT ;
    USE SIGNAL ;
    PORT
      LAYER M5 ;
        RECT  72.816 21.408 72.84 21.6 ;
    END
  END o[403]
  PIN o[404]
    DIRECTION OUTPUT ;
    USE SIGNAL ;
    PORT
      LAYER M5 ;
        RECT  73.008 21.408 73.032 21.6 ;
    END
  END o[404]
  PIN o[405]
    DIRECTION OUTPUT ;
    USE SIGNAL ;
    PORT
      LAYER M5 ;
        RECT  73.152 21.408 73.176 21.6 ;
    END
  END o[405]
  PIN o[406]
    DIRECTION OUTPUT ;
    USE SIGNAL ;
    PORT
      LAYER M5 ;
        RECT  73.344 21.408 73.368 21.6 ;
    END
  END o[406]
  PIN o[407]
    DIRECTION OUTPUT ;
    USE SIGNAL ;
    PORT
      LAYER M5 ;
        RECT  73.488 21.408 73.512 21.6 ;
    END
  END o[407]
  PIN o[408]
    DIRECTION OUTPUT ;
    USE SIGNAL ;
    PORT
      LAYER M5 ;
        RECT  73.68 21.408 73.704 21.6 ;
    END
  END o[408]
  PIN o[409]
    DIRECTION OUTPUT ;
    USE SIGNAL ;
    PORT
      LAYER M5 ;
        RECT  73.872 21.408 73.896 21.6 ;
    END
  END o[409]
  PIN o[40]
    DIRECTION OUTPUT ;
    USE SIGNAL ;
    PORT
      LAYER M5 ;
        RECT  11.088 21.408 11.112 21.6 ;
    END
  END o[40]
  PIN o[410]
    DIRECTION OUTPUT ;
    USE SIGNAL ;
    PORT
      LAYER M5 ;
        RECT  74.016 21.408 74.04 21.6 ;
    END
  END o[410]
  PIN o[411]
    DIRECTION OUTPUT ;
    USE SIGNAL ;
    PORT
      LAYER M5 ;
        RECT  74.208 21.408 74.232 21.6 ;
    END
  END o[411]
  PIN o[412]
    DIRECTION OUTPUT ;
    USE SIGNAL ;
    PORT
      LAYER M5 ;
        RECT  74.352 21.408 74.376 21.6 ;
    END
  END o[412]
  PIN o[413]
    DIRECTION OUTPUT ;
    USE SIGNAL ;
    PORT
      LAYER M5 ;
        RECT  74.544 21.408 74.568 21.6 ;
    END
  END o[413]
  PIN o[414]
    DIRECTION OUTPUT ;
    USE SIGNAL ;
    PORT
      LAYER M5 ;
        RECT  74.688 21.408 74.712 21.6 ;
    END
  END o[414]
  PIN o[415]
    DIRECTION OUTPUT ;
    USE SIGNAL ;
    PORT
      LAYER M5 ;
        RECT  74.88 21.408 74.904 21.6 ;
    END
  END o[415]
  PIN o[416]
    DIRECTION OUTPUT ;
    USE SIGNAL ;
    PORT
      LAYER M5 ;
        RECT  75.024 21.408 75.048 21.6 ;
    END
  END o[416]
  PIN o[417]
    DIRECTION OUTPUT ;
    USE SIGNAL ;
    PORT
      LAYER M5 ;
        RECT  75.216 21.408 75.24 21.6 ;
    END
  END o[417]
  PIN o[418]
    DIRECTION OUTPUT ;
    USE SIGNAL ;
    PORT
      LAYER M5 ;
        RECT  75.36 21.408 75.384 21.6 ;
    END
  END o[418]
  PIN o[419]
    DIRECTION OUTPUT ;
    USE SIGNAL ;
    PORT
      LAYER M5 ;
        RECT  75.552 21.408 75.576 21.6 ;
    END
  END o[419]
  PIN o[41]
    DIRECTION OUTPUT ;
    USE SIGNAL ;
    PORT
      LAYER M5 ;
        RECT  11.28 21.408 11.304 21.6 ;
    END
  END o[41]
  PIN o[420]
    DIRECTION OUTPUT ;
    USE SIGNAL ;
    PORT
      LAYER M5 ;
        RECT  75.696 21.408 75.72 21.6 ;
    END
  END o[420]
  PIN o[421]
    DIRECTION OUTPUT ;
    USE SIGNAL ;
    PORT
      LAYER M5 ;
        RECT  75.888 21.408 75.912 21.6 ;
    END
  END o[421]
  PIN o[422]
    DIRECTION OUTPUT ;
    USE SIGNAL ;
    PORT
      LAYER M5 ;
        RECT  76.032 21.408 76.056 21.6 ;
    END
  END o[422]
  PIN o[423]
    DIRECTION OUTPUT ;
    USE SIGNAL ;
    PORT
      LAYER M5 ;
        RECT  76.224 21.408 76.248 21.6 ;
    END
  END o[423]
  PIN o[424]
    DIRECTION OUTPUT ;
    USE SIGNAL ;
    PORT
      LAYER M5 ;
        RECT  76.416 21.408 76.44 21.6 ;
    END
  END o[424]
  PIN o[425]
    DIRECTION OUTPUT ;
    USE SIGNAL ;
    PORT
      LAYER M5 ;
        RECT  76.56 21.408 76.584 21.6 ;
    END
  END o[425]
  PIN o[426]
    DIRECTION OUTPUT ;
    USE SIGNAL ;
    PORT
      LAYER M5 ;
        RECT  76.752 21.408 76.776 21.6 ;
    END
  END o[426]
  PIN o[427]
    DIRECTION OUTPUT ;
    USE SIGNAL ;
    PORT
      LAYER M5 ;
        RECT  76.896 21.408 76.92 21.6 ;
    END
  END o[427]
  PIN o[428]
    DIRECTION OUTPUT ;
    USE SIGNAL ;
    PORT
      LAYER M5 ;
        RECT  77.088 21.408 77.112 21.6 ;
    END
  END o[428]
  PIN o[429]
    DIRECTION OUTPUT ;
    USE SIGNAL ;
    PORT
      LAYER M5 ;
        RECT  77.232 21.408 77.256 21.6 ;
    END
  END o[429]
  PIN o[42]
    DIRECTION OUTPUT ;
    USE SIGNAL ;
    PORT
      LAYER M5 ;
        RECT  11.424 21.408 11.448 21.6 ;
    END
  END o[42]
  PIN o[430]
    DIRECTION OUTPUT ;
    USE SIGNAL ;
    PORT
      LAYER M5 ;
        RECT  77.424 21.408 77.448 21.6 ;
    END
  END o[430]
  PIN o[431]
    DIRECTION OUTPUT ;
    USE SIGNAL ;
    PORT
      LAYER M5 ;
        RECT  77.568 21.408 77.592 21.6 ;
    END
  END o[431]
  PIN o[432]
    DIRECTION OUTPUT ;
    USE SIGNAL ;
    PORT
      LAYER M5 ;
        RECT  77.76 21.408 77.784 21.6 ;
    END
  END o[432]
  PIN o[433]
    DIRECTION OUTPUT ;
    USE SIGNAL ;
    PORT
      LAYER M5 ;
        RECT  77.904 21.408 77.928 21.6 ;
    END
  END o[433]
  PIN o[434]
    DIRECTION OUTPUT ;
    USE SIGNAL ;
    PORT
      LAYER M5 ;
        RECT  78.096 21.408 78.12 21.6 ;
    END
  END o[434]
  PIN o[435]
    DIRECTION OUTPUT ;
    USE SIGNAL ;
    PORT
      LAYER M5 ;
        RECT  78.24 21.408 78.264 21.6 ;
    END
  END o[435]
  PIN o[436]
    DIRECTION OUTPUT ;
    USE SIGNAL ;
    PORT
      LAYER M5 ;
        RECT  78.432 21.408 78.456 21.6 ;
    END
  END o[436]
  PIN o[437]
    DIRECTION OUTPUT ;
    USE SIGNAL ;
    PORT
      LAYER M5 ;
        RECT  78.576 21.408 78.6 21.6 ;
    END
  END o[437]
  PIN o[438]
    DIRECTION OUTPUT ;
    USE SIGNAL ;
    PORT
      LAYER M5 ;
        RECT  78.768 21.408 78.792 21.6 ;
    END
  END o[438]
  PIN o[439]
    DIRECTION OUTPUT ;
    USE SIGNAL ;
    PORT
      LAYER M5 ;
        RECT  78.96 21.408 78.984 21.6 ;
    END
  END o[439]
  PIN o[43]
    DIRECTION OUTPUT ;
    USE SIGNAL ;
    PORT
      LAYER M5 ;
        RECT  11.616 21.408 11.64 21.6 ;
    END
  END o[43]
  PIN o[440]
    DIRECTION OUTPUT ;
    USE SIGNAL ;
    PORT
      LAYER M5 ;
        RECT  79.104 21.408 79.128 21.6 ;
    END
  END o[440]
  PIN o[441]
    DIRECTION OUTPUT ;
    USE SIGNAL ;
    PORT
      LAYER M5 ;
        RECT  79.296 21.408 79.32 21.6 ;
    END
  END o[441]
  PIN o[442]
    DIRECTION OUTPUT ;
    USE SIGNAL ;
    PORT
      LAYER M5 ;
        RECT  79.44 21.408 79.464 21.6 ;
    END
  END o[442]
  PIN o[443]
    DIRECTION OUTPUT ;
    USE SIGNAL ;
    PORT
      LAYER M5 ;
        RECT  79.632 21.408 79.656 21.6 ;
    END
  END o[443]
  PIN o[444]
    DIRECTION OUTPUT ;
    USE SIGNAL ;
    PORT
      LAYER M5 ;
        RECT  79.776 21.408 79.8 21.6 ;
    END
  END o[444]
  PIN o[445]
    DIRECTION OUTPUT ;
    USE SIGNAL ;
    PORT
      LAYER M5 ;
        RECT  79.968 21.408 79.992 21.6 ;
    END
  END o[445]
  PIN o[446]
    DIRECTION OUTPUT ;
    USE SIGNAL ;
    PORT
      LAYER M5 ;
        RECT  80.112 21.408 80.136 21.6 ;
    END
  END o[446]
  PIN o[447]
    DIRECTION OUTPUT ;
    USE SIGNAL ;
    PORT
      LAYER M5 ;
        RECT  80.304 21.408 80.328 21.6 ;
    END
  END o[447]
  PIN o[448]
    DIRECTION OUTPUT ;
    USE SIGNAL ;
    PORT
      LAYER M5 ;
        RECT  80.448 21.408 80.472 21.6 ;
    END
  END o[448]
  PIN o[449]
    DIRECTION OUTPUT ;
    USE SIGNAL ;
    PORT
      LAYER M5 ;
        RECT  80.64 21.408 80.664 21.6 ;
    END
  END o[449]
  PIN o[44]
    DIRECTION OUTPUT ;
    USE SIGNAL ;
    PORT
      LAYER M5 ;
        RECT  11.76 21.408 11.784 21.6 ;
    END
  END o[44]
  PIN o[450]
    DIRECTION OUTPUT ;
    USE SIGNAL ;
    PORT
      LAYER M5 ;
        RECT  80.784 21.408 80.808 21.6 ;
    END
  END o[450]
  PIN o[451]
    DIRECTION OUTPUT ;
    USE SIGNAL ;
    PORT
      LAYER M5 ;
        RECT  80.976 21.408 81 21.6 ;
    END
  END o[451]
  PIN o[452]
    DIRECTION OUTPUT ;
    USE SIGNAL ;
    PORT
      LAYER M5 ;
        RECT  81.12 21.408 81.144 21.6 ;
    END
  END o[452]
  PIN o[453]
    DIRECTION OUTPUT ;
    USE SIGNAL ;
    PORT
      LAYER M5 ;
        RECT  81.312 21.408 81.336 21.6 ;
    END
  END o[453]
  PIN o[454]
    DIRECTION OUTPUT ;
    USE SIGNAL ;
    PORT
      LAYER M5 ;
        RECT  81.504 21.408 81.528 21.6 ;
    END
  END o[454]
  PIN o[455]
    DIRECTION OUTPUT ;
    USE SIGNAL ;
    PORT
      LAYER M5 ;
        RECT  81.648 21.408 81.672 21.6 ;
    END
  END o[455]
  PIN o[456]
    DIRECTION OUTPUT ;
    USE SIGNAL ;
    PORT
      LAYER M5 ;
        RECT  81.84 21.408 81.864 21.6 ;
    END
  END o[456]
  PIN o[457]
    DIRECTION OUTPUT ;
    USE SIGNAL ;
    PORT
      LAYER M5 ;
        RECT  81.984 21.408 82.008 21.6 ;
    END
  END o[457]
  PIN o[458]
    DIRECTION OUTPUT ;
    USE SIGNAL ;
    PORT
      LAYER M5 ;
        RECT  82.176 21.408 82.2 21.6 ;
    END
  END o[458]
  PIN o[459]
    DIRECTION OUTPUT ;
    USE SIGNAL ;
    PORT
      LAYER M5 ;
        RECT  82.32 21.408 82.344 21.6 ;
    END
  END o[459]
  PIN o[45]
    DIRECTION OUTPUT ;
    USE SIGNAL ;
    PORT
      LAYER M5 ;
        RECT  11.952 21.408 11.976 21.6 ;
    END
  END o[45]
  PIN o[460]
    DIRECTION OUTPUT ;
    USE SIGNAL ;
    PORT
      LAYER M5 ;
        RECT  82.512 21.408 82.536 21.6 ;
    END
  END o[460]
  PIN o[461]
    DIRECTION OUTPUT ;
    USE SIGNAL ;
    PORT
      LAYER M5 ;
        RECT  82.656 21.408 82.68 21.6 ;
    END
  END o[461]
  PIN o[462]
    DIRECTION OUTPUT ;
    USE SIGNAL ;
    PORT
      LAYER M5 ;
        RECT  82.848 21.408 82.872 21.6 ;
    END
  END o[462]
  PIN o[463]
    DIRECTION OUTPUT ;
    USE SIGNAL ;
    PORT
      LAYER M5 ;
        RECT  82.992 21.408 83.016 21.6 ;
    END
  END o[463]
  PIN o[464]
    DIRECTION OUTPUT ;
    USE SIGNAL ;
    PORT
      LAYER M5 ;
        RECT  83.184 21.408 83.208 21.6 ;
    END
  END o[464]
  PIN o[465]
    DIRECTION OUTPUT ;
    USE SIGNAL ;
    PORT
      LAYER M5 ;
        RECT  83.328 21.408 83.352 21.6 ;
    END
  END o[465]
  PIN o[466]
    DIRECTION OUTPUT ;
    USE SIGNAL ;
    PORT
      LAYER M5 ;
        RECT  83.52 21.408 83.544 21.6 ;
    END
  END o[466]
  PIN o[467]
    DIRECTION OUTPUT ;
    USE SIGNAL ;
    PORT
      LAYER M5 ;
        RECT  83.664 21.408 83.688 21.6 ;
    END
  END o[467]
  PIN o[468]
    DIRECTION OUTPUT ;
    USE SIGNAL ;
    PORT
      LAYER M5 ;
        RECT  83.856 21.408 83.88 21.6 ;
    END
  END o[468]
  PIN o[469]
    DIRECTION OUTPUT ;
    USE SIGNAL ;
    PORT
      LAYER M5 ;
        RECT  84.048 21.408 84.072 21.6 ;
    END
  END o[469]
  PIN o[46]
    DIRECTION OUTPUT ;
    USE SIGNAL ;
    PORT
      LAYER M5 ;
        RECT  12.096 21.408 12.12 21.6 ;
    END
  END o[46]
  PIN o[470]
    DIRECTION OUTPUT ;
    USE SIGNAL ;
    PORT
      LAYER M5 ;
        RECT  84.192 21.408 84.216 21.6 ;
    END
  END o[470]
  PIN o[471]
    DIRECTION OUTPUT ;
    USE SIGNAL ;
    PORT
      LAYER M5 ;
        RECT  84.384 21.408 84.408 21.6 ;
    END
  END o[471]
  PIN o[472]
    DIRECTION OUTPUT ;
    USE SIGNAL ;
    PORT
      LAYER M5 ;
        RECT  84.528 21.408 84.552 21.6 ;
    END
  END o[472]
  PIN o[473]
    DIRECTION OUTPUT ;
    USE SIGNAL ;
    PORT
      LAYER M5 ;
        RECT  84.72 21.408 84.744 21.6 ;
    END
  END o[473]
  PIN o[474]
    DIRECTION OUTPUT ;
    USE SIGNAL ;
    PORT
      LAYER M5 ;
        RECT  84.864 21.408 84.888 21.6 ;
    END
  END o[474]
  PIN o[475]
    DIRECTION OUTPUT ;
    USE SIGNAL ;
    PORT
      LAYER M5 ;
        RECT  85.056 21.408 85.08 21.6 ;
    END
  END o[475]
  PIN o[476]
    DIRECTION OUTPUT ;
    USE SIGNAL ;
    PORT
      LAYER M5 ;
        RECT  85.2 21.408 85.224 21.6 ;
    END
  END o[476]
  PIN o[477]
    DIRECTION OUTPUT ;
    USE SIGNAL ;
    PORT
      LAYER M5 ;
        RECT  85.392 21.408 85.416 21.6 ;
    END
  END o[477]
  PIN o[478]
    DIRECTION OUTPUT ;
    USE SIGNAL ;
    PORT
      LAYER M5 ;
        RECT  85.536 21.408 85.56 21.6 ;
    END
  END o[478]
  PIN o[479]
    DIRECTION OUTPUT ;
    USE SIGNAL ;
    PORT
      LAYER M5 ;
        RECT  85.728 21.408 85.752 21.6 ;
    END
  END o[479]
  PIN o[47]
    DIRECTION OUTPUT ;
    USE SIGNAL ;
    PORT
      LAYER M5 ;
        RECT  12.288 21.408 12.312 21.6 ;
    END
  END o[47]
  PIN o[480]
    DIRECTION OUTPUT ;
    USE SIGNAL ;
    PORT
      LAYER M5 ;
        RECT  85.872 21.408 85.896 21.6 ;
    END
  END o[480]
  PIN o[481]
    DIRECTION OUTPUT ;
    USE SIGNAL ;
    PORT
      LAYER M5 ;
        RECT  86.064 21.408 86.088 21.6 ;
    END
  END o[481]
  PIN o[482]
    DIRECTION OUTPUT ;
    USE SIGNAL ;
    PORT
      LAYER M5 ;
        RECT  86.256 21.408 86.28 21.6 ;
    END
  END o[482]
  PIN o[483]
    DIRECTION OUTPUT ;
    USE SIGNAL ;
    PORT
      LAYER M5 ;
        RECT  86.4 21.408 86.424 21.6 ;
    END
  END o[483]
  PIN o[484]
    DIRECTION OUTPUT ;
    USE SIGNAL ;
    PORT
      LAYER M5 ;
        RECT  86.592 21.408 86.616 21.6 ;
    END
  END o[484]
  PIN o[485]
    DIRECTION OUTPUT ;
    USE SIGNAL ;
    PORT
      LAYER M5 ;
        RECT  86.736 21.408 86.76 21.6 ;
    END
  END o[485]
  PIN o[486]
    DIRECTION OUTPUT ;
    USE SIGNAL ;
    PORT
      LAYER M5 ;
        RECT  86.928 21.408 86.952 21.6 ;
    END
  END o[486]
  PIN o[487]
    DIRECTION OUTPUT ;
    USE SIGNAL ;
    PORT
      LAYER M5 ;
        RECT  87.072 21.408 87.096 21.6 ;
    END
  END o[487]
  PIN o[488]
    DIRECTION OUTPUT ;
    USE SIGNAL ;
    PORT
      LAYER M5 ;
        RECT  87.264 21.408 87.288 21.6 ;
    END
  END o[488]
  PIN o[489]
    DIRECTION OUTPUT ;
    USE SIGNAL ;
    PORT
      LAYER M5 ;
        RECT  87.408 21.408 87.432 21.6 ;
    END
  END o[489]
  PIN o[48]
    DIRECTION OUTPUT ;
    USE SIGNAL ;
    PORT
      LAYER M5 ;
        RECT  12.432 21.408 12.456 21.6 ;
    END
  END o[48]
  PIN o[490]
    DIRECTION OUTPUT ;
    USE SIGNAL ;
    PORT
      LAYER M5 ;
        RECT  87.6 21.408 87.624 21.6 ;
    END
  END o[490]
  PIN o[491]
    DIRECTION OUTPUT ;
    USE SIGNAL ;
    PORT
      LAYER M5 ;
        RECT  87.744 21.408 87.768 21.6 ;
    END
  END o[491]
  PIN o[492]
    DIRECTION OUTPUT ;
    USE SIGNAL ;
    PORT
      LAYER M5 ;
        RECT  87.936 21.408 87.96 21.6 ;
    END
  END o[492]
  PIN o[493]
    DIRECTION OUTPUT ;
    USE SIGNAL ;
    PORT
      LAYER M5 ;
        RECT  88.08 21.408 88.104 21.6 ;
    END
  END o[493]
  PIN o[494]
    DIRECTION OUTPUT ;
    USE SIGNAL ;
    PORT
      LAYER M5 ;
        RECT  88.272 21.408 88.296 21.6 ;
    END
  END o[494]
  PIN o[495]
    DIRECTION OUTPUT ;
    USE SIGNAL ;
    PORT
      LAYER M5 ;
        RECT  88.416 21.408 88.44 21.6 ;
    END
  END o[495]
  PIN o[496]
    DIRECTION OUTPUT ;
    USE SIGNAL ;
    PORT
      LAYER M5 ;
        RECT  88.608 21.408 88.632 21.6 ;
    END
  END o[496]
  PIN o[497]
    DIRECTION OUTPUT ;
    USE SIGNAL ;
    PORT
      LAYER M5 ;
        RECT  88.8 21.408 88.824 21.6 ;
    END
  END o[497]
  PIN o[498]
    DIRECTION OUTPUT ;
    USE SIGNAL ;
    PORT
      LAYER M5 ;
        RECT  88.944 21.408 88.968 21.6 ;
    END
  END o[498]
  PIN o[499]
    DIRECTION OUTPUT ;
    USE SIGNAL ;
    PORT
      LAYER M5 ;
        RECT  89.136 21.408 89.16 21.6 ;
    END
  END o[499]
  PIN o[49]
    DIRECTION OUTPUT ;
    USE SIGNAL ;
    PORT
      LAYER M5 ;
        RECT  12.624 21.408 12.648 21.6 ;
    END
  END o[49]
  PIN o[4]
    DIRECTION OUTPUT ;
    USE SIGNAL ;
    PORT
      LAYER M5 ;
        RECT  4.992 21.408 5.016 21.6 ;
    END
  END o[4]
  PIN o[500]
    DIRECTION OUTPUT ;
    USE SIGNAL ;
    PORT
      LAYER M5 ;
        RECT  89.28 21.408 89.304 21.6 ;
    END
  END o[500]
  PIN o[501]
    DIRECTION OUTPUT ;
    USE SIGNAL ;
    PORT
      LAYER M5 ;
        RECT  89.472 21.408 89.496 21.6 ;
    END
  END o[501]
  PIN o[502]
    DIRECTION OUTPUT ;
    USE SIGNAL ;
    PORT
      LAYER M5 ;
        RECT  89.616 21.408 89.64 21.6 ;
    END
  END o[502]
  PIN o[503]
    DIRECTION OUTPUT ;
    USE SIGNAL ;
    PORT
      LAYER M5 ;
        RECT  89.808 21.408 89.832 21.6 ;
    END
  END o[503]
  PIN o[504]
    DIRECTION OUTPUT ;
    USE SIGNAL ;
    PORT
      LAYER M5 ;
        RECT  89.952 21.408 89.976 21.6 ;
    END
  END o[504]
  PIN o[505]
    DIRECTION OUTPUT ;
    USE SIGNAL ;
    PORT
      LAYER M5 ;
        RECT  90.144 21.408 90.168 21.6 ;
    END
  END o[505]
  PIN o[506]
    DIRECTION OUTPUT ;
    USE SIGNAL ;
    PORT
      LAYER M5 ;
        RECT  90.288 21.408 90.312 21.6 ;
    END
  END o[506]
  PIN o[507]
    DIRECTION OUTPUT ;
    USE SIGNAL ;
    PORT
      LAYER M5 ;
        RECT  90.48 21.408 90.504 21.6 ;
    END
  END o[507]
  PIN o[508]
    DIRECTION OUTPUT ;
    USE SIGNAL ;
    PORT
      LAYER M5 ;
        RECT  90.624 21.408 90.648 21.6 ;
    END
  END o[508]
  PIN o[509]
    DIRECTION OUTPUT ;
    USE SIGNAL ;
    PORT
      LAYER M5 ;
        RECT  90.816 21.408 90.84 21.6 ;
    END
  END o[509]
  PIN o[50]
    DIRECTION OUTPUT ;
    USE SIGNAL ;
    PORT
      LAYER M5 ;
        RECT  12.768 21.408 12.792 21.6 ;
    END
  END o[50]
  PIN o[510]
    DIRECTION OUTPUT ;
    USE SIGNAL ;
    PORT
      LAYER M5 ;
        RECT  90.96 21.408 90.984 21.6 ;
    END
  END o[510]
  PIN o[511]
    DIRECTION OUTPUT ;
    USE SIGNAL ;
    PORT
      LAYER M5 ;
        RECT  91.152 21.408 91.176 21.6 ;
    END
  END o[511]
  PIN o[512]
    DIRECTION OUTPUT ;
    USE SIGNAL ;
    PORT
      LAYER M5 ;
        RECT  91.344 21.408 91.368 21.6 ;
    END
  END o[512]
  PIN o[513]
    DIRECTION OUTPUT ;
    USE SIGNAL ;
    PORT
      LAYER M5 ;
        RECT  91.488 21.408 91.512 21.6 ;
    END
  END o[513]
  PIN o[514]
    DIRECTION OUTPUT ;
    USE SIGNAL ;
    PORT
      LAYER M5 ;
        RECT  91.68 21.408 91.704 21.6 ;
    END
  END o[514]
  PIN o[515]
    DIRECTION OUTPUT ;
    USE SIGNAL ;
    PORT
      LAYER M5 ;
        RECT  91.824 21.408 91.848 21.6 ;
    END
  END o[515]
  PIN o[516]
    DIRECTION OUTPUT ;
    USE SIGNAL ;
    PORT
      LAYER M5 ;
        RECT  92.016 21.408 92.04 21.6 ;
    END
  END o[516]
  PIN o[517]
    DIRECTION OUTPUT ;
    USE SIGNAL ;
    PORT
      LAYER M5 ;
        RECT  92.16 21.408 92.184 21.6 ;
    END
  END o[517]
  PIN o[518]
    DIRECTION OUTPUT ;
    USE SIGNAL ;
    PORT
      LAYER M5 ;
        RECT  92.352 21.408 92.376 21.6 ;
    END
  END o[518]
  PIN o[519]
    DIRECTION OUTPUT ;
    USE SIGNAL ;
    PORT
      LAYER M5 ;
        RECT  92.496 21.408 92.52 21.6 ;
    END
  END o[519]
  PIN o[51]
    DIRECTION OUTPUT ;
    USE SIGNAL ;
    PORT
      LAYER M5 ;
        RECT  12.96 21.408 12.984 21.6 ;
    END
  END o[51]
  PIN o[520]
    DIRECTION OUTPUT ;
    USE SIGNAL ;
    PORT
      LAYER M5 ;
        RECT  92.688 21.408 92.712 21.6 ;
    END
  END o[520]
  PIN o[521]
    DIRECTION OUTPUT ;
    USE SIGNAL ;
    PORT
      LAYER M5 ;
        RECT  92.832 21.408 92.856 21.6 ;
    END
  END o[521]
  PIN o[522]
    DIRECTION OUTPUT ;
    USE SIGNAL ;
    PORT
      LAYER M5 ;
        RECT  93.024 21.408 93.048 21.6 ;
    END
  END o[522]
  PIN o[523]
    DIRECTION OUTPUT ;
    USE SIGNAL ;
    PORT
      LAYER M5 ;
        RECT  93.168 21.408 93.192 21.6 ;
    END
  END o[523]
  PIN o[524]
    DIRECTION OUTPUT ;
    USE SIGNAL ;
    PORT
      LAYER M5 ;
        RECT  93.36 21.408 93.384 21.6 ;
    END
  END o[524]
  PIN o[525]
    DIRECTION OUTPUT ;
    USE SIGNAL ;
    PORT
      LAYER M5 ;
        RECT  93.504 21.408 93.528 21.6 ;
    END
  END o[525]
  PIN o[526]
    DIRECTION OUTPUT ;
    USE SIGNAL ;
    PORT
      LAYER M5 ;
        RECT  93.696 21.408 93.72 21.6 ;
    END
  END o[526]
  PIN o[527]
    DIRECTION OUTPUT ;
    USE SIGNAL ;
    PORT
      LAYER M5 ;
        RECT  93.888 21.408 93.912 21.6 ;
    END
  END o[527]
  PIN o[528]
    DIRECTION OUTPUT ;
    USE SIGNAL ;
    PORT
      LAYER M5 ;
        RECT  94.032 21.408 94.056 21.6 ;
    END
  END o[528]
  PIN o[529]
    DIRECTION OUTPUT ;
    USE SIGNAL ;
    PORT
      LAYER M5 ;
        RECT  94.224 21.408 94.248 21.6 ;
    END
  END o[529]
  PIN o[52]
    DIRECTION OUTPUT ;
    USE SIGNAL ;
    PORT
      LAYER M5 ;
        RECT  13.152 21.408 13.176 21.6 ;
    END
  END o[52]
  PIN o[530]
    DIRECTION OUTPUT ;
    USE SIGNAL ;
    PORT
      LAYER M5 ;
        RECT  94.368 21.408 94.392 21.6 ;
    END
  END o[530]
  PIN o[531]
    DIRECTION OUTPUT ;
    USE SIGNAL ;
    PORT
      LAYER M5 ;
        RECT  94.56 21.408 94.584 21.6 ;
    END
  END o[531]
  PIN o[532]
    DIRECTION OUTPUT ;
    USE SIGNAL ;
    PORT
      LAYER M5 ;
        RECT  94.704 21.408 94.728 21.6 ;
    END
  END o[532]
  PIN o[533]
    DIRECTION OUTPUT ;
    USE SIGNAL ;
    PORT
      LAYER M5 ;
        RECT  94.896 21.408 94.92 21.6 ;
    END
  END o[533]
  PIN o[534]
    DIRECTION OUTPUT ;
    USE SIGNAL ;
    PORT
      LAYER M5 ;
        RECT  95.04 21.408 95.064 21.6 ;
    END
  END o[534]
  PIN o[535]
    DIRECTION OUTPUT ;
    USE SIGNAL ;
    PORT
      LAYER M5 ;
        RECT  95.232 21.408 95.256 21.6 ;
    END
  END o[535]
  PIN o[536]
    DIRECTION OUTPUT ;
    USE SIGNAL ;
    PORT
      LAYER M5 ;
        RECT  95.376 21.408 95.4 21.6 ;
    END
  END o[536]
  PIN o[537]
    DIRECTION OUTPUT ;
    USE SIGNAL ;
    PORT
      LAYER M5 ;
        RECT  95.568 21.408 95.592 21.6 ;
    END
  END o[537]
  PIN o[538]
    DIRECTION OUTPUT ;
    USE SIGNAL ;
    PORT
      LAYER M5 ;
        RECT  95.712 21.408 95.736 21.6 ;
    END
  END o[538]
  PIN o[539]
    DIRECTION OUTPUT ;
    USE SIGNAL ;
    PORT
      LAYER M5 ;
        RECT  95.904 21.408 95.928 21.6 ;
    END
  END o[539]
  PIN o[53]
    DIRECTION OUTPUT ;
    USE SIGNAL ;
    PORT
      LAYER M5 ;
        RECT  13.296 21.408 13.32 21.6 ;
    END
  END o[53]
  PIN o[540]
    DIRECTION OUTPUT ;
    USE SIGNAL ;
    PORT
      LAYER M5 ;
        RECT  96.048 21.408 96.072 21.6 ;
    END
  END o[540]
  PIN o[541]
    DIRECTION OUTPUT ;
    USE SIGNAL ;
    PORT
      LAYER M5 ;
        RECT  96.24 21.408 96.264 21.6 ;
    END
  END o[541]
  PIN o[542]
    DIRECTION OUTPUT ;
    USE SIGNAL ;
    PORT
      LAYER M5 ;
        RECT  96.432 21.408 96.456 21.6 ;
    END
  END o[542]
  PIN o[543]
    DIRECTION OUTPUT ;
    USE SIGNAL ;
    PORT
      LAYER M5 ;
        RECT  96.576 21.408 96.6 21.6 ;
    END
  END o[543]
  PIN o[544]
    DIRECTION OUTPUT ;
    USE SIGNAL ;
    PORT
      LAYER M5 ;
        RECT  96.768 21.408 96.792 21.6 ;
    END
  END o[544]
  PIN o[545]
    DIRECTION OUTPUT ;
    USE SIGNAL ;
    PORT
      LAYER M5 ;
        RECT  96.912 21.408 96.936 21.6 ;
    END
  END o[545]
  PIN o[546]
    DIRECTION OUTPUT ;
    USE SIGNAL ;
    PORT
      LAYER M5 ;
        RECT  97.104 21.408 97.128 21.6 ;
    END
  END o[546]
  PIN o[547]
    DIRECTION OUTPUT ;
    USE SIGNAL ;
    PORT
      LAYER M5 ;
        RECT  97.248 21.408 97.272 21.6 ;
    END
  END o[547]
  PIN o[548]
    DIRECTION OUTPUT ;
    USE SIGNAL ;
    PORT
      LAYER M5 ;
        RECT  97.44 21.408 97.464 21.6 ;
    END
  END o[548]
  PIN o[549]
    DIRECTION OUTPUT ;
    USE SIGNAL ;
    PORT
      LAYER M5 ;
        RECT  97.584 21.408 97.608 21.6 ;
    END
  END o[549]
  PIN o[54]
    DIRECTION OUTPUT ;
    USE SIGNAL ;
    PORT
      LAYER M5 ;
        RECT  13.488 21.408 13.512 21.6 ;
    END
  END o[54]
  PIN o[550]
    DIRECTION OUTPUT ;
    USE SIGNAL ;
    PORT
      LAYER M5 ;
        RECT  97.776 21.408 97.8 21.6 ;
    END
  END o[550]
  PIN o[551]
    DIRECTION OUTPUT ;
    USE SIGNAL ;
    PORT
      LAYER M5 ;
        RECT  97.92 21.408 97.944 21.6 ;
    END
  END o[551]
  PIN o[552]
    DIRECTION OUTPUT ;
    USE SIGNAL ;
    PORT
      LAYER M5 ;
        RECT  98.112 21.408 98.136 21.6 ;
    END
  END o[552]
  PIN o[553]
    DIRECTION OUTPUT ;
    USE SIGNAL ;
    PORT
      LAYER M5 ;
        RECT  98.256 21.408 98.28 21.6 ;
    END
  END o[553]
  PIN o[554]
    DIRECTION OUTPUT ;
    USE SIGNAL ;
    PORT
      LAYER M5 ;
        RECT  98.448 21.408 98.472 21.6 ;
    END
  END o[554]
  PIN o[555]
    DIRECTION OUTPUT ;
    USE SIGNAL ;
    PORT
      LAYER M5 ;
        RECT  98.592 21.408 98.616 21.6 ;
    END
  END o[555]
  PIN o[556]
    DIRECTION OUTPUT ;
    USE SIGNAL ;
    PORT
      LAYER M5 ;
        RECT  98.784 21.408 98.808 21.6 ;
    END
  END o[556]
  PIN o[557]
    DIRECTION OUTPUT ;
    USE SIGNAL ;
    PORT
      LAYER M5 ;
        RECT  98.976 21.408 99 21.6 ;
    END
  END o[557]
  PIN o[558]
    DIRECTION OUTPUT ;
    USE SIGNAL ;
    PORT
      LAYER M5 ;
        RECT  99.12 21.408 99.144 21.6 ;
    END
  END o[558]
  PIN o[559]
    DIRECTION OUTPUT ;
    USE SIGNAL ;
    PORT
      LAYER M5 ;
        RECT  99.312 21.408 99.336 21.6 ;
    END
  END o[559]
  PIN o[55]
    DIRECTION OUTPUT ;
    USE SIGNAL ;
    PORT
      LAYER M5 ;
        RECT  13.632 21.408 13.656 21.6 ;
    END
  END o[55]
  PIN o[560]
    DIRECTION OUTPUT ;
    USE SIGNAL ;
    PORT
      LAYER M5 ;
        RECT  99.456 21.408 99.48 21.6 ;
    END
  END o[560]
  PIN o[561]
    DIRECTION OUTPUT ;
    USE SIGNAL ;
    PORT
      LAYER M5 ;
        RECT  99.648 21.408 99.672 21.6 ;
    END
  END o[561]
  PIN o[562]
    DIRECTION OUTPUT ;
    USE SIGNAL ;
    PORT
      LAYER M5 ;
        RECT  99.792 21.408 99.816 21.6 ;
    END
  END o[562]
  PIN o[563]
    DIRECTION OUTPUT ;
    USE SIGNAL ;
    PORT
      LAYER M5 ;
        RECT  99.984 21.408 100.008 21.6 ;
    END
  END o[563]
  PIN o[564]
    DIRECTION OUTPUT ;
    USE SIGNAL ;
    PORT
      LAYER M5 ;
        RECT  100.128 21.408 100.152 21.6 ;
    END
  END o[564]
  PIN o[565]
    DIRECTION OUTPUT ;
    USE SIGNAL ;
    PORT
      LAYER M5 ;
        RECT  100.32 21.408 100.344 21.6 ;
    END
  END o[565]
  PIN o[566]
    DIRECTION OUTPUT ;
    USE SIGNAL ;
    PORT
      LAYER M5 ;
        RECT  100.464 21.408 100.488 21.6 ;
    END
  END o[566]
  PIN o[567]
    DIRECTION OUTPUT ;
    USE SIGNAL ;
    PORT
      LAYER M5 ;
        RECT  100.656 21.408 100.68 21.6 ;
    END
  END o[567]
  PIN o[568]
    DIRECTION OUTPUT ;
    USE SIGNAL ;
    PORT
      LAYER M5 ;
        RECT  100.8 21.408 100.824 21.6 ;
    END
  END o[568]
  PIN o[569]
    DIRECTION OUTPUT ;
    USE SIGNAL ;
    PORT
      LAYER M5 ;
        RECT  100.992 21.408 101.016 21.6 ;
    END
  END o[569]
  PIN o[56]
    DIRECTION OUTPUT ;
    USE SIGNAL ;
    PORT
      LAYER M5 ;
        RECT  13.824 21.408 13.848 21.6 ;
    END
  END o[56]
  PIN o[570]
    DIRECTION OUTPUT ;
    USE SIGNAL ;
    PORT
      LAYER M5 ;
        RECT  101.136 21.408 101.16 21.6 ;
    END
  END o[570]
  PIN o[571]
    DIRECTION OUTPUT ;
    USE SIGNAL ;
    PORT
      LAYER M5 ;
        RECT  101.328 21.408 101.352 21.6 ;
    END
  END o[571]
  PIN o[572]
    DIRECTION OUTPUT ;
    USE SIGNAL ;
    PORT
      LAYER M5 ;
        RECT  101.52 21.408 101.544 21.6 ;
    END
  END o[572]
  PIN o[573]
    DIRECTION OUTPUT ;
    USE SIGNAL ;
    PORT
      LAYER M5 ;
        RECT  101.664 21.408 101.688 21.6 ;
    END
  END o[573]
  PIN o[574]
    DIRECTION OUTPUT ;
    USE SIGNAL ;
    PORT
      LAYER M5 ;
        RECT  101.856 21.408 101.88 21.6 ;
    END
  END o[574]
  PIN o[575]
    DIRECTION OUTPUT ;
    USE SIGNAL ;
    PORT
      LAYER M5 ;
        RECT  102 21.408 102.024 21.6 ;
    END
  END o[575]
  PIN o[576]
    DIRECTION OUTPUT ;
    USE SIGNAL ;
    PORT
      LAYER M5 ;
        RECT  102.192 21.408 102.216 21.6 ;
    END
  END o[576]
  PIN o[577]
    DIRECTION OUTPUT ;
    USE SIGNAL ;
    PORT
      LAYER M5 ;
        RECT  102.336 21.408 102.36 21.6 ;
    END
  END o[577]
  PIN o[578]
    DIRECTION OUTPUT ;
    USE SIGNAL ;
    PORT
      LAYER M5 ;
        RECT  102.528 21.408 102.552 21.6 ;
    END
  END o[578]
  PIN o[579]
    DIRECTION OUTPUT ;
    USE SIGNAL ;
    PORT
      LAYER M5 ;
        RECT  102.672 21.408 102.696 21.6 ;
    END
  END o[579]
  PIN o[57]
    DIRECTION OUTPUT ;
    USE SIGNAL ;
    PORT
      LAYER M5 ;
        RECT  13.968 21.408 13.992 21.6 ;
    END
  END o[57]
  PIN o[580]
    DIRECTION OUTPUT ;
    USE SIGNAL ;
    PORT
      LAYER M5 ;
        RECT  102.864 21.408 102.888 21.6 ;
    END
  END o[580]
  PIN o[581]
    DIRECTION OUTPUT ;
    USE SIGNAL ;
    PORT
      LAYER M5 ;
        RECT  103.008 21.408 103.032 21.6 ;
    END
  END o[581]
  PIN o[582]
    DIRECTION OUTPUT ;
    USE SIGNAL ;
    PORT
      LAYER M5 ;
        RECT  103.2 21.408 103.224 21.6 ;
    END
  END o[582]
  PIN o[583]
    DIRECTION OUTPUT ;
    USE SIGNAL ;
    PORT
      LAYER M5 ;
        RECT  103.344 21.408 103.368 21.6 ;
    END
  END o[583]
  PIN o[584]
    DIRECTION OUTPUT ;
    USE SIGNAL ;
    PORT
      LAYER M5 ;
        RECT  103.536 21.408 103.56 21.6 ;
    END
  END o[584]
  PIN o[585]
    DIRECTION OUTPUT ;
    USE SIGNAL ;
    PORT
      LAYER M5 ;
        RECT  103.68 21.408 103.704 21.6 ;
    END
  END o[585]
  PIN o[586]
    DIRECTION OUTPUT ;
    USE SIGNAL ;
    PORT
      LAYER M5 ;
        RECT  103.872 21.408 103.896 21.6 ;
    END
  END o[586]
  PIN o[587]
    DIRECTION OUTPUT ;
    USE SIGNAL ;
    PORT
      LAYER M5 ;
        RECT  104.064 21.408 104.088 21.6 ;
    END
  END o[587]
  PIN o[588]
    DIRECTION OUTPUT ;
    USE SIGNAL ;
    PORT
      LAYER M5 ;
        RECT  104.208 21.408 104.232 21.6 ;
    END
  END o[588]
  PIN o[589]
    DIRECTION OUTPUT ;
    USE SIGNAL ;
    PORT
      LAYER M5 ;
        RECT  104.4 21.408 104.424 21.6 ;
    END
  END o[589]
  PIN o[58]
    DIRECTION OUTPUT ;
    USE SIGNAL ;
    PORT
      LAYER M5 ;
        RECT  14.16 21.408 14.184 21.6 ;
    END
  END o[58]
  PIN o[590]
    DIRECTION OUTPUT ;
    USE SIGNAL ;
    PORT
      LAYER M5 ;
        RECT  104.544 21.408 104.568 21.6 ;
    END
  END o[590]
  PIN o[591]
    DIRECTION OUTPUT ;
    USE SIGNAL ;
    PORT
      LAYER M5 ;
        RECT  104.736 21.408 104.76 21.6 ;
    END
  END o[591]
  PIN o[592]
    DIRECTION OUTPUT ;
    USE SIGNAL ;
    PORT
      LAYER M5 ;
        RECT  104.88 21.408 104.904 21.6 ;
    END
  END o[592]
  PIN o[593]
    DIRECTION OUTPUT ;
    USE SIGNAL ;
    PORT
      LAYER M5 ;
        RECT  105.072 21.408 105.096 21.6 ;
    END
  END o[593]
  PIN o[594]
    DIRECTION OUTPUT ;
    USE SIGNAL ;
    PORT
      LAYER M5 ;
        RECT  105.216 21.408 105.24 21.6 ;
    END
  END o[594]
  PIN o[595]
    DIRECTION OUTPUT ;
    USE SIGNAL ;
    PORT
      LAYER M5 ;
        RECT  105.408 21.408 105.432 21.6 ;
    END
  END o[595]
  PIN o[596]
    DIRECTION OUTPUT ;
    USE SIGNAL ;
    PORT
      LAYER M5 ;
        RECT  105.552 21.408 105.576 21.6 ;
    END
  END o[596]
  PIN o[597]
    DIRECTION OUTPUT ;
    USE SIGNAL ;
    PORT
      LAYER M5 ;
        RECT  105.744 21.408 105.768 21.6 ;
    END
  END o[597]
  PIN o[598]
    DIRECTION OUTPUT ;
    USE SIGNAL ;
    PORT
      LAYER M5 ;
        RECT  105.888 21.408 105.912 21.6 ;
    END
  END o[598]
  PIN o[599]
    DIRECTION OUTPUT ;
    USE SIGNAL ;
    PORT
      LAYER M5 ;
        RECT  106.08 21.408 106.104 21.6 ;
    END
  END o[599]
  PIN o[59]
    DIRECTION OUTPUT ;
    USE SIGNAL ;
    PORT
      LAYER M5 ;
        RECT  14.304 21.408 14.328 21.6 ;
    END
  END o[59]
  PIN o[5]
    DIRECTION OUTPUT ;
    USE SIGNAL ;
    PORT
      LAYER M5 ;
        RECT  5.136 21.408 5.16 21.6 ;
    END
  END o[5]
  PIN o[600]
    DIRECTION OUTPUT ;
    USE SIGNAL ;
    PORT
      LAYER M5 ;
        RECT  106.224 21.408 106.248 21.6 ;
    END
  END o[600]
  PIN o[601]
    DIRECTION OUTPUT ;
    USE SIGNAL ;
    PORT
      LAYER M5 ;
        RECT  106.416 21.408 106.44 21.6 ;
    END
  END o[601]
  PIN o[602]
    DIRECTION OUTPUT ;
    USE SIGNAL ;
    PORT
      LAYER M5 ;
        RECT  106.608 21.408 106.632 21.6 ;
    END
  END o[602]
  PIN o[603]
    DIRECTION OUTPUT ;
    USE SIGNAL ;
    PORT
      LAYER M5 ;
        RECT  106.752 21.408 106.776 21.6 ;
    END
  END o[603]
  PIN o[604]
    DIRECTION OUTPUT ;
    USE SIGNAL ;
    PORT
      LAYER M5 ;
        RECT  106.944 21.408 106.968 21.6 ;
    END
  END o[604]
  PIN o[605]
    DIRECTION OUTPUT ;
    USE SIGNAL ;
    PORT
      LAYER M5 ;
        RECT  107.088 21.408 107.112 21.6 ;
    END
  END o[605]
  PIN o[606]
    DIRECTION OUTPUT ;
    USE SIGNAL ;
    PORT
      LAYER M5 ;
        RECT  107.28 21.408 107.304 21.6 ;
    END
  END o[606]
  PIN o[607]
    DIRECTION OUTPUT ;
    USE SIGNAL ;
    PORT
      LAYER M5 ;
        RECT  107.424 21.408 107.448 21.6 ;
    END
  END o[607]
  PIN o[608]
    DIRECTION OUTPUT ;
    USE SIGNAL ;
    PORT
      LAYER M5 ;
        RECT  107.616 21.408 107.64 21.6 ;
    END
  END o[608]
  PIN o[609]
    DIRECTION OUTPUT ;
    USE SIGNAL ;
    PORT
      LAYER M5 ;
        RECT  107.76 21.408 107.784 21.6 ;
    END
  END o[609]
  PIN o[60]
    DIRECTION OUTPUT ;
    USE SIGNAL ;
    PORT
      LAYER M5 ;
        RECT  14.496 21.408 14.52 21.6 ;
    END
  END o[60]
  PIN o[610]
    DIRECTION OUTPUT ;
    USE SIGNAL ;
    PORT
      LAYER M5 ;
        RECT  107.952 21.408 107.976 21.6 ;
    END
  END o[610]
  PIN o[611]
    DIRECTION OUTPUT ;
    USE SIGNAL ;
    PORT
      LAYER M5 ;
        RECT  108.096 21.408 108.12 21.6 ;
    END
  END o[611]
  PIN o[612]
    DIRECTION OUTPUT ;
    USE SIGNAL ;
    PORT
      LAYER M5 ;
        RECT  108.288 21.408 108.312 21.6 ;
    END
  END o[612]
  PIN o[613]
    DIRECTION OUTPUT ;
    USE SIGNAL ;
    PORT
      LAYER M5 ;
        RECT  108.432 21.408 108.456 21.6 ;
    END
  END o[613]
  PIN o[614]
    DIRECTION OUTPUT ;
    USE SIGNAL ;
    PORT
      LAYER M5 ;
        RECT  108.624 21.408 108.648 21.6 ;
    END
  END o[614]
  PIN o[615]
    DIRECTION OUTPUT ;
    USE SIGNAL ;
    PORT
      LAYER M5 ;
        RECT  108.768 21.408 108.792 21.6 ;
    END
  END o[615]
  PIN o[616]
    DIRECTION OUTPUT ;
    USE SIGNAL ;
    PORT
      LAYER M5 ;
        RECT  108.96 21.408 108.984 21.6 ;
    END
  END o[616]
  PIN o[617]
    DIRECTION OUTPUT ;
    USE SIGNAL ;
    PORT
      LAYER M5 ;
        RECT  109.152 21.408 109.176 21.6 ;
    END
  END o[617]
  PIN o[618]
    DIRECTION OUTPUT ;
    USE SIGNAL ;
    PORT
      LAYER M5 ;
        RECT  109.296 21.408 109.32 21.6 ;
    END
  END o[618]
  PIN o[619]
    DIRECTION OUTPUT ;
    USE SIGNAL ;
    PORT
      LAYER M5 ;
        RECT  109.488 21.408 109.512 21.6 ;
    END
  END o[619]
  PIN o[61]
    DIRECTION OUTPUT ;
    USE SIGNAL ;
    PORT
      LAYER M5 ;
        RECT  14.64 21.408 14.664 21.6 ;
    END
  END o[61]
  PIN o[620]
    DIRECTION OUTPUT ;
    USE SIGNAL ;
    PORT
      LAYER M5 ;
        RECT  109.632 21.408 109.656 21.6 ;
    END
  END o[620]
  PIN o[621]
    DIRECTION OUTPUT ;
    USE SIGNAL ;
    PORT
      LAYER M5 ;
        RECT  109.824 21.408 109.848 21.6 ;
    END
  END o[621]
  PIN o[622]
    DIRECTION OUTPUT ;
    USE SIGNAL ;
    PORT
      LAYER M5 ;
        RECT  109.968 21.408 109.992 21.6 ;
    END
  END o[622]
  PIN o[623]
    DIRECTION OUTPUT ;
    USE SIGNAL ;
    PORT
      LAYER M5 ;
        RECT  110.16 21.408 110.184 21.6 ;
    END
  END o[623]
  PIN o[62]
    DIRECTION OUTPUT ;
    USE SIGNAL ;
    PORT
      LAYER M5 ;
        RECT  14.832 21.408 14.856 21.6 ;
    END
  END o[62]
  PIN o[63]
    DIRECTION OUTPUT ;
    USE SIGNAL ;
    PORT
      LAYER M5 ;
        RECT  14.976 21.408 15 21.6 ;
    END
  END o[63]
  PIN o[64]
    DIRECTION OUTPUT ;
    USE SIGNAL ;
    PORT
      LAYER M5 ;
        RECT  15.168 21.408 15.192 21.6 ;
    END
  END o[64]
  PIN o[65]
    DIRECTION OUTPUT ;
    USE SIGNAL ;
    PORT
      LAYER M5 ;
        RECT  15.312 21.408 15.336 21.6 ;
    END
  END o[65]
  PIN o[66]
    DIRECTION OUTPUT ;
    USE SIGNAL ;
    PORT
      LAYER M5 ;
        RECT  15.504 21.408 15.528 21.6 ;
    END
  END o[66]
  PIN o[67]
    DIRECTION OUTPUT ;
    USE SIGNAL ;
    PORT
      LAYER M5 ;
        RECT  15.696 21.408 15.72 21.6 ;
    END
  END o[67]
  PIN o[68]
    DIRECTION OUTPUT ;
    USE SIGNAL ;
    PORT
      LAYER M5 ;
        RECT  15.84 21.408 15.864 21.6 ;
    END
  END o[68]
  PIN o[69]
    DIRECTION OUTPUT ;
    USE SIGNAL ;
    PORT
      LAYER M5 ;
        RECT  16.032 21.408 16.056 21.6 ;
    END
  END o[69]
  PIN o[6]
    DIRECTION OUTPUT ;
    USE SIGNAL ;
    PORT
      LAYER M5 ;
        RECT  5.328 21.408 5.352 21.6 ;
    END
  END o[6]
  PIN o[70]
    DIRECTION OUTPUT ;
    USE SIGNAL ;
    PORT
      LAYER M5 ;
        RECT  16.176 21.408 16.2 21.6 ;
    END
  END o[70]
  PIN o[71]
    DIRECTION OUTPUT ;
    USE SIGNAL ;
    PORT
      LAYER M5 ;
        RECT  16.368 21.408 16.392 21.6 ;
    END
  END o[71]
  PIN o[72]
    DIRECTION OUTPUT ;
    USE SIGNAL ;
    PORT
      LAYER M5 ;
        RECT  16.512 21.408 16.536 21.6 ;
    END
  END o[72]
  PIN o[73]
    DIRECTION OUTPUT ;
    USE SIGNAL ;
    PORT
      LAYER M5 ;
        RECT  16.704 21.408 16.728 21.6 ;
    END
  END o[73]
  PIN o[74]
    DIRECTION OUTPUT ;
    USE SIGNAL ;
    PORT
      LAYER M5 ;
        RECT  16.848 21.408 16.872 21.6 ;
    END
  END o[74]
  PIN o[75]
    DIRECTION OUTPUT ;
    USE SIGNAL ;
    PORT
      LAYER M5 ;
        RECT  17.04 21.408 17.064 21.6 ;
    END
  END o[75]
  PIN o[76]
    DIRECTION OUTPUT ;
    USE SIGNAL ;
    PORT
      LAYER M5 ;
        RECT  17.184 21.408 17.208 21.6 ;
    END
  END o[76]
  PIN o[77]
    DIRECTION OUTPUT ;
    USE SIGNAL ;
    PORT
      LAYER M5 ;
        RECT  17.376 21.408 17.4 21.6 ;
    END
  END o[77]
  PIN o[78]
    DIRECTION OUTPUT ;
    USE SIGNAL ;
    PORT
      LAYER M5 ;
        RECT  17.52 21.408 17.544 21.6 ;
    END
  END o[78]
  PIN o[79]
    DIRECTION OUTPUT ;
    USE SIGNAL ;
    PORT
      LAYER M5 ;
        RECT  17.712 21.408 17.736 21.6 ;
    END
  END o[79]
  PIN o[7]
    DIRECTION OUTPUT ;
    USE SIGNAL ;
    PORT
      LAYER M5 ;
        RECT  5.472 21.408 5.496 21.6 ;
    END
  END o[7]
  PIN o[80]
    DIRECTION OUTPUT ;
    USE SIGNAL ;
    PORT
      LAYER M5 ;
        RECT  17.856 21.408 17.88 21.6 ;
    END
  END o[80]
  PIN o[81]
    DIRECTION OUTPUT ;
    USE SIGNAL ;
    PORT
      LAYER M5 ;
        RECT  18.048 21.408 18.072 21.6 ;
    END
  END o[81]
  PIN o[82]
    DIRECTION OUTPUT ;
    USE SIGNAL ;
    PORT
      LAYER M5 ;
        RECT  18.24 21.408 18.264 21.6 ;
    END
  END o[82]
  PIN o[83]
    DIRECTION OUTPUT ;
    USE SIGNAL ;
    PORT
      LAYER M5 ;
        RECT  18.384 21.408 18.408 21.6 ;
    END
  END o[83]
  PIN o[84]
    DIRECTION OUTPUT ;
    USE SIGNAL ;
    PORT
      LAYER M5 ;
        RECT  18.576 21.408 18.6 21.6 ;
    END
  END o[84]
  PIN o[85]
    DIRECTION OUTPUT ;
    USE SIGNAL ;
    PORT
      LAYER M5 ;
        RECT  18.72 21.408 18.744 21.6 ;
    END
  END o[85]
  PIN o[86]
    DIRECTION OUTPUT ;
    USE SIGNAL ;
    PORT
      LAYER M5 ;
        RECT  18.912 21.408 18.936 21.6 ;
    END
  END o[86]
  PIN o[87]
    DIRECTION OUTPUT ;
    USE SIGNAL ;
    PORT
      LAYER M5 ;
        RECT  19.056 21.408 19.08 21.6 ;
    END
  END o[87]
  PIN o[88]
    DIRECTION OUTPUT ;
    USE SIGNAL ;
    PORT
      LAYER M5 ;
        RECT  19.248 21.408 19.272 21.6 ;
    END
  END o[88]
  PIN o[89]
    DIRECTION OUTPUT ;
    USE SIGNAL ;
    PORT
      LAYER M5 ;
        RECT  19.392 21.408 19.416 21.6 ;
    END
  END o[89]
  PIN o[8]
    DIRECTION OUTPUT ;
    USE SIGNAL ;
    PORT
      LAYER M5 ;
        RECT  5.664 21.408 5.688 21.6 ;
    END
  END o[8]
  PIN o[90]
    DIRECTION OUTPUT ;
    USE SIGNAL ;
    PORT
      LAYER M5 ;
        RECT  19.584 21.408 19.608 21.6 ;
    END
  END o[90]
  PIN o[91]
    DIRECTION OUTPUT ;
    USE SIGNAL ;
    PORT
      LAYER M5 ;
        RECT  19.728 21.408 19.752 21.6 ;
    END
  END o[91]
  PIN o[92]
    DIRECTION OUTPUT ;
    USE SIGNAL ;
    PORT
      LAYER M5 ;
        RECT  19.92 21.408 19.944 21.6 ;
    END
  END o[92]
  PIN o[93]
    DIRECTION OUTPUT ;
    USE SIGNAL ;
    PORT
      LAYER M5 ;
        RECT  20.064 21.408 20.088 21.6 ;
    END
  END o[93]
  PIN o[94]
    DIRECTION OUTPUT ;
    USE SIGNAL ;
    PORT
      LAYER M5 ;
        RECT  20.256 21.408 20.28 21.6 ;
    END
  END o[94]
  PIN o[95]
    DIRECTION OUTPUT ;
    USE SIGNAL ;
    PORT
      LAYER M5 ;
        RECT  20.4 21.408 20.424 21.6 ;
    END
  END o[95]
  PIN o[96]
    DIRECTION OUTPUT ;
    USE SIGNAL ;
    PORT
      LAYER M5 ;
        RECT  20.592 21.408 20.616 21.6 ;
    END
  END o[96]
  PIN o[97]
    DIRECTION OUTPUT ;
    USE SIGNAL ;
    PORT
      LAYER M5 ;
        RECT  20.784 21.408 20.808 21.6 ;
    END
  END o[97]
  PIN o[98]
    DIRECTION OUTPUT ;
    USE SIGNAL ;
    PORT
      LAYER M5 ;
        RECT  20.928 21.408 20.952 21.6 ;
    END
  END o[98]
  PIN o[99]
    DIRECTION OUTPUT ;
    USE SIGNAL ;
    PORT
      LAYER M5 ;
        RECT  21.12 21.408 21.144 21.6 ;
    END
  END o[99]
  PIN o[9]
    DIRECTION OUTPUT ;
    USE SIGNAL ;
    PORT
      LAYER M5 ;
        RECT  5.856 21.408 5.88 21.6 ;
    END
  END o[9]
  PIN rs
    DIRECTION INPUT ;
    USE SIGNAL ;
    PORT
      LAYER M4 ;
        RECT  0 10.8 0.192 10.824 ;
    END
    PORT
      LAYER M4 ;
        RECT  0.156 10.8 0.245 10.824 ;
    END
  END rs
  PIN VDD
    DIRECTION INOUT ;
    USE POWER ;
    PORT
      LAYER M5 ;
        RECT  110.592 2.151 110.712 19.449 ;
        RECT  107.892 2.151 108.012 19.449 ;
        RECT  105.192 2.151 105.312 19.449 ;
        RECT  102.492 2.151 102.612 19.449 ;
        RECT  99.792 2.151 99.912 19.449 ;
        RECT  97.092 2.151 97.212 19.449 ;
        RECT  94.392 2.151 94.512 19.449 ;
        RECT  91.692 2.151 91.812 19.449 ;
        RECT  88.992 2.151 89.112 19.449 ;
        RECT  86.292 2.151 86.412 19.449 ;
        RECT  83.592 2.151 83.712 19.449 ;
        RECT  80.892 2.151 81.012 19.449 ;
        RECT  78.192 2.151 78.312 19.449 ;
        RECT  75.492 2.151 75.612 19.449 ;
        RECT  72.792 2.151 72.912 19.449 ;
        RECT  70.092 2.151 70.212 19.449 ;
        RECT  67.392 2.151 67.512 19.449 ;
        RECT  64.692 2.151 64.812 19.449 ;
        RECT  61.992 2.151 62.112 19.449 ;
        RECT  59.292 2.151 59.412 19.449 ;
        RECT  56.592 2.151 56.712 19.449 ;
        RECT  53.892 2.151 54.012 19.449 ;
        RECT  51.192 2.151 51.312 19.449 ;
        RECT  48.492 2.151 48.612 19.449 ;
        RECT  45.792 2.151 45.912 19.449 ;
        RECT  43.092 2.151 43.212 19.449 ;
        RECT  40.392 2.151 40.512 19.449 ;
        RECT  37.692 2.151 37.812 19.449 ;
        RECT  34.992 2.151 35.112 19.449 ;
        RECT  32.292 2.151 32.412 19.449 ;
        RECT  29.592 2.151 29.712 19.449 ;
        RECT  26.892 2.151 27.012 19.449 ;
        RECT  24.192 2.151 24.312 19.449 ;
        RECT  21.492 2.151 21.612 19.449 ;
        RECT  18.792 2.151 18.912 19.449 ;
        RECT  16.092 2.151 16.212 19.449 ;
        RECT  13.392 2.151 13.512 19.449 ;
        RECT  10.692 2.151 10.812 19.449 ;
        RECT  7.992 2.151 8.112 19.449 ;
        RECT  5.292 2.151 5.412 19.449 ;
        RECT  2.592 2.151 2.712 19.449 ;
    END
  END VDD
  PIN VSS
    DIRECTION INOUT ;
    USE GROUND ;
    PORT
      LAYER M5 ;
        RECT  110.4 2.137 110.52 19.463 ;
        RECT  107.7 2.137 107.82 19.463 ;
        RECT  105 2.137 105.12 19.463 ;
        RECT  102.3 2.137 102.42 19.463 ;
        RECT  99.6 2.137 99.72 19.463 ;
        RECT  96.9 2.137 97.02 19.463 ;
        RECT  94.2 2.137 94.32 19.463 ;
        RECT  91.5 2.137 91.62 19.463 ;
        RECT  88.8 2.137 88.92 19.463 ;
        RECT  86.1 2.137 86.22 19.463 ;
        RECT  83.4 2.137 83.52 19.463 ;
        RECT  80.7 2.137 80.82 19.463 ;
        RECT  78 2.137 78.12 19.463 ;
        RECT  75.3 2.137 75.42 19.463 ;
        RECT  72.6 2.137 72.72 19.463 ;
        RECT  69.9 2.137 70.02 19.463 ;
        RECT  67.2 2.137 67.32 19.463 ;
        RECT  64.5 2.137 64.62 19.463 ;
        RECT  61.8 2.137 61.92 19.463 ;
        RECT  59.1 2.137 59.22 19.463 ;
        RECT  56.4 2.137 56.52 19.463 ;
        RECT  53.7 2.137 53.82 19.463 ;
        RECT  51 2.137 51.12 19.463 ;
        RECT  48.3 2.137 48.42 19.463 ;
        RECT  45.6 2.137 45.72 19.463 ;
        RECT  42.9 2.137 43.02 19.463 ;
        RECT  40.2 2.137 40.32 19.463 ;
        RECT  37.5 2.137 37.62 19.463 ;
        RECT  34.8 2.137 34.92 19.463 ;
        RECT  32.1 2.137 32.22 19.463 ;
        RECT  29.4 2.137 29.52 19.463 ;
        RECT  26.7 2.137 26.82 19.463 ;
        RECT  24 2.137 24.12 19.463 ;
        RECT  21.3 2.137 21.42 19.463 ;
        RECT  18.6 2.137 18.72 19.463 ;
        RECT  15.9 2.137 16.02 19.463 ;
        RECT  13.2 2.137 13.32 19.463 ;
        RECT  10.5 2.137 10.62 19.463 ;
        RECT  7.8 2.137 7.92 19.463 ;
        RECT  5.1 2.137 5.22 19.463 ;
        RECT  2.4 2.137 2.52 19.463 ;
    END
  END VSS
  # OT_OBS_CLOSED layer=M5 d_um=1.536 added=58
  OBS
    LAYER RVTN ;
     RECT  2.16 2.16 112.32 2.295 ;
     RECT  2.16 2.565 112.32 2.835 ;
     RECT  2.16 3.105 112.32 3.375 ;
     RECT  2.16 3.645 112.32 3.915 ;
     RECT  2.16 4.185 112.32 4.455 ;
     RECT  2.16 4.725 112.32 4.995 ;
     RECT  2.16 5.265 112.32 5.535 ;
     RECT  2.16 5.805 112.32 6.075 ;
     RECT  2.16 6.345 112.32 6.615 ;
     RECT  2.16 6.885 112.32 7.155 ;
     RECT  2.16 7.425 112.32 7.695 ;
     RECT  2.16 7.965 112.32 8.235 ;
     RECT  2.16 8.505 112.32 8.775 ;
     RECT  2.16 9.045 112.32 9.315 ;
     RECT  2.16 9.585 112.32 9.855 ;
     RECT  2.16 10.125 112.32 10.395 ;
     RECT  2.16 10.665 112.32 10.935 ;
     RECT  2.16 11.205 112.32 11.475 ;
     RECT  2.16 11.745 112.32 12.015 ;
     RECT  2.16 12.285 112.32 12.555 ;
     RECT  2.16 12.825 112.32 13.095 ;
     RECT  2.16 13.365 112.32 13.635 ;
     RECT  2.16 13.905 112.32 14.175 ;
     RECT  2.16 14.445 112.32 14.715 ;
     RECT  2.16 14.985 112.32 15.255 ;
     RECT  2.16 15.525 112.32 15.795 ;
     RECT  2.16 16.065 112.32 16.335 ;
     RECT  2.16 16.605 112.32 16.875 ;
     RECT  2.16 17.145 112.32 17.415 ;
     RECT  2.16 17.685 112.32 17.955 ;
     RECT  2.16 18.225 112.32 18.495 ;
     RECT  2.16 18.765 112.32 19.035 ;
     RECT  2.16 19.305 112.32 19.44 ;
    LAYER RVTP ;
     RECT  2.16 2.295 112.32 2.565 ;
     RECT  2.16 2.835 112.32 3.105 ;
     RECT  2.16 3.375 112.32 3.645 ;
     RECT  2.16 3.915 112.32 4.185 ;
     RECT  2.16 4.455 112.32 4.725 ;
     RECT  2.16 4.995 112.32 5.265 ;
     RECT  2.16 5.535 112.32 5.805 ;
     RECT  2.16 6.075 112.32 6.345 ;
     RECT  2.16 6.615 112.32 6.885 ;
     RECT  2.16 7.155 112.32 7.425 ;
     RECT  2.16 7.695 112.32 7.965 ;
     RECT  2.16 8.235 112.32 8.505 ;
     RECT  2.16 8.775 112.32 9.045 ;
     RECT  2.16 9.315 112.32 9.585 ;
     RECT  2.16 9.855 112.32 10.125 ;
     RECT  2.16 10.395 112.32 10.665 ;
     RECT  2.16 10.935 112.32 11.205 ;
     RECT  2.16 11.475 112.32 11.745 ;
     RECT  2.16 12.015 112.32 12.285 ;
     RECT  2.16 12.555 112.32 12.825 ;
     RECT  2.16 13.095 112.32 13.365 ;
     RECT  2.16 13.635 112.32 13.905 ;
     RECT  2.16 14.175 112.32 14.445 ;
     RECT  2.16 14.715 112.32 14.985 ;
     RECT  2.16 15.255 112.32 15.525 ;
     RECT  2.16 15.795 112.32 16.065 ;
     RECT  2.16 16.335 112.32 16.605 ;
     RECT  2.16 16.875 112.32 17.145 ;
     RECT  2.16 17.415 112.32 17.685 ;
     RECT  2.16 17.955 112.32 18.225 ;
     RECT  2.16 18.495 112.32 18.765 ;
     RECT  2.16 19.035 112.32 19.305 ;
    LAYER M1 ;
     RECT  2.16 2.151 112.32 19.449 ;
    LAYER M2 ;
     RECT  0.211 11.286 2.16 11.304 ;
     RECT  2.16 2.151 3.811 19.449 ;
     RECT  3.811 2.106 4.639 19.449 ;
     RECT  4.639 2.034 5.063 19.449 ;
     RECT  5.063 2.151 17.959 19.449 ;
     RECT  17.959 2.106 18.239 19.449 ;
     RECT  18.239 2.151 21.199 19.449 ;
     RECT  21.199 2.106 23.495 19.449 ;
     RECT  23.495 2.151 27.859 19.449 ;
     RECT  27.859 2.106 28.031 19.449 ;
     RECT  28.031 2.151 43.843 19.449 ;
     RECT  43.843 2.106 44.023 19.449 ;
     RECT  44.023 2.07 44.519 19.449 ;
     RECT  44.519 2.106 45.527 19.449 ;
     RECT  45.527 2.151 56.191 19.449 ;
     RECT  56.191 2.106 56.615 19.449 ;
     RECT  56.615 2.151 83.371 19.449 ;
     RECT  83.371 2.106 83.867 19.449 ;
     RECT  83.867 2.151 85.099 19.449 ;
     RECT  85.099 2.106 85.523 19.449 ;
     RECT  85.523 2.151 90.607 19.449 ;
     RECT  90.607 2.106 90.995 19.449 ;
     RECT  90.995 2.151 95.827 19.449 ;
     RECT  95.827 2.034 96.143 19.449 ;
     RECT  96.143 2.106 97.115 19.449 ;
     RECT  97.115 2.151 99.463 19.449 ;
     RECT  99.463 2.106 100.463 19.449 ;
     RECT  100.463 2.151 112.32 19.449 ;
    LAYER M3 ;
     RECT  4.5 0.523 4.518 1.147 ;
     RECT  5.256 0.187 5.274 1.147 ;
     RECT  13.716 0.571 13.734 1.147 ;
     RECT  90.648 0.571 90.666 1.147 ;
     RECT  4.5 1.147 5.274 1.723 ;
     RECT  6.264 0.523 6.282 1.723 ;
     RECT  8.568 0.187 8.586 1.723 ;
     RECT  10.908 0.571 10.926 1.723 ;
     RECT  13.716 1.147 14.31 1.723 ;
     RECT  19.332 0.523 19.35 1.723 ;
     RECT  29.88 0.571 29.898 1.723 ;
     RECT  73.548 0.187 73.566 1.723 ;
     RECT  90.468 1.147 90.666 1.723 ;
     RECT  93.852 1.099 93.87 1.723 ;
     RECT  94.644 0.283 94.662 1.723 ;
     RECT  4.356 1.723 33.858 1.771 ;
     RECT  44.892 1.723 52.218 1.771 ;
     RECT  52.956 1.723 56.394 1.771 ;
     RECT  34.776 1.723 35.298 1.819 ;
     RECT  36.108 1.723 44.118 1.819 ;
     RECT  97.272 1.723 110.25 1.963 ;
     RECT  44.892 1.771 56.394 2.011 ;
     RECT  97.236 1.963 110.25 2.011 ;
     RECT  44.892 2.011 56.754 2.059 ;
     RECT  57.528 1.723 59.814 2.059 ;
     RECT  34.776 1.819 44.118 2.065 ;
     RECT  44.892 2.059 59.814 2.065 ;
     RECT  4.032 1.771 33.858 2.101 ;
     RECT  69.732 1.723 96.318 2.143 ;
     RECT  97.056 2.011 110.25 2.143 ;
     RECT  3.816 2.101 33.858 2.191 ;
     RECT  34.776 2.065 59.814 2.191 ;
     RECT  61.2 1.723 62.586 2.191 ;
     RECT  63.36 1.723 68.094 2.191 ;
     RECT  68.868 1.723 68.886 2.191 ;
     RECT  69.732 2.143 110.505 2.191 ;
     RECT  3.816 2.191 111.006 2.263 ;
     RECT  3.528 2.263 111.006 2.299 ;
     RECT  112.032 2.191 112.05 2.299 ;
     RECT  2.415 2.143 2.505 2.413 ;
     RECT  3.528 2.299 112.05 2.641 ;
     RECT  3.528 2.641 112.086 3.181 ;
     RECT  2.415 2.413 2.697 3.721 ;
     RECT  3.528 3.181 112.122 3.721 ;
     RECT  2.415 3.721 112.122 3.955 ;
     RECT  2.415 3.955 112.194 4.523 ;
     RECT  3.492 4.523 112.194 4.541 ;
     RECT  3.708 4.541 112.194 5.261 ;
     RECT  3.708 5.261 112.122 5.575 ;
     RECT  3.564 5.575 112.122 6.221 ;
     RECT  3.852 6.221 112.122 6.269 ;
     RECT  4.176 6.269 112.122 7.259 ;
     RECT  4.176 7.259 111.798 7.421 ;
     RECT  4.788 7.421 111.798 8.131 ;
     RECT  4.788 8.131 111.87 8.189 ;
     RECT  4.788 8.189 111.654 8.851 ;
     RECT  4.752 8.851 111.654 8.909 ;
     RECT  4.788 8.909 111.654 10.661 ;
     RECT  4.788 10.661 111.15 10.685 ;
     RECT  4.788 10.685 77.022 11.003 ;
     RECT  4.788 11.003 21.798 11.039 ;
     RECT  4.788 11.039 18.897 11.129 ;
     RECT  0.216 10.795 0.234 11.309 ;
     RECT  4.788 11.129 6.858 11.399 ;
     RECT  22.536 11.003 77.022 11.399 ;
     RECT  28.08 11.399 77.022 11.419 ;
     RECT  77.904 10.685 111.15 11.419 ;
     RECT  28.08 11.419 111.15 11.435 ;
     RECT  28.08 11.435 58.194 11.543 ;
     RECT  61.668 11.435 68.994 11.669 ;
     RECT  69.768 11.435 110.697 11.669 ;
     RECT  69.915 11.669 110.697 11.705 ;
     RECT  61.668 11.669 67.842 11.777 ;
     RECT  7.776 11.129 18.897 11.821 ;
     RECT  19.728 11.039 21.798 11.821 ;
     RECT  22.536 11.399 27.234 11.821 ;
     RECT  42.228 11.543 58.194 11.849 ;
     RECT  61.668 11.777 67.806 11.849 ;
     RECT  45.396 11.849 58.194 11.939 ;
     RECT  69.915 11.705 79.29 11.939 ;
     RECT  28.08 11.543 41.31 11.975 ;
     RECT  68.796 11.669 68.994 11.975 ;
     RECT  69.915 11.939 79.254 11.981 ;
     RECT  80.208 11.705 110.697 12.119 ;
     RECT  45.432 11.939 56.754 12.209 ;
     RECT  42.228 11.849 44.55 12.353 ;
     RECT  4.788 11.399 6.606 12.361 ;
     RECT  7.776 11.821 27.234 12.361 ;
     RECT  28.08 11.975 30.51 12.361 ;
     RECT  31.284 11.975 41.31 12.361 ;
     RECT  42.228 12.353 44.514 12.361 ;
     RECT  57.672 11.939 58.194 12.361 ;
     RECT  59.004 11.435 60.894 12.361 ;
     RECT  61.668 11.849 63.702 12.361 ;
     RECT  45.468 12.209 56.754 12.479 ;
     RECT  48.24 12.479 56.754 12.515 ;
     RECT  64.476 11.849 67.806 12.515 ;
     RECT  73.692 11.981 79.254 12.515 ;
     RECT  4.788 12.361 30.51 12.557 ;
     RECT  95.256 12.119 110.697 12.557 ;
     RECT  69.915 11.981 72.954 12.631 ;
     RECT  69.912 12.631 72.954 12.721 ;
     RECT  73.692 12.515 79.218 12.721 ;
     RECT  4.788 12.557 27.594 12.749 ;
     RECT  80.208 12.119 94.497 12.785 ;
     RECT  28.368 12.557 30.51 12.821 ;
     RECT  64.476 12.515 67.698 12.821 ;
     RECT  95.256 12.557 97.29 12.821 ;
     RECT  31.284 12.361 44.514 12.893 ;
     RECT  28.44 12.821 30.51 12.901 ;
     RECT  31.284 12.893 41.418 12.901 ;
     RECT  68.904 11.975 68.994 12.901 ;
     RECT  69.912 12.721 79.218 12.901 ;
     RECT  80.208 12.785 84.438 12.901 ;
     RECT  85.248 12.785 94.497 12.901 ;
     RECT  95.256 12.821 97.197 12.901 ;
     RECT  12.348 12.749 27.594 13.055 ;
     RECT  57.672 12.361 63.702 13.063 ;
     RECT  57.6 13.063 63.702 13.085 ;
     RECT  85.248 12.901 97.197 13.085 ;
     RECT  12.348 13.055 27.486 13.091 ;
     RECT  68.904 12.901 79.218 13.091 ;
     RECT  85.248 13.085 93.438 13.091 ;
     RECT  45.468 12.479 47.43 13.261 ;
     RECT  48.24 12.515 51.966 13.261 ;
     RECT  28.44 12.901 41.418 13.289 ;
     RECT  59.004 13.085 63.702 13.289 ;
     RECT  94.215 13.085 97.197 13.361 ;
     RECT  12.348 13.091 21.762 13.433 ;
     RECT  68.904 13.091 74.502 13.433 ;
     RECT  75.24 13.091 79.218 13.441 ;
     RECT  34.668 13.289 41.418 13.517 ;
     RECT  69.84 13.433 74.502 13.517 ;
     RECT  45.468 13.261 51.966 13.531 ;
     RECT  52.704 12.515 56.754 13.531 ;
     RECT  75.24 13.441 79.434 13.531 ;
     RECT  80.172 12.901 84.438 13.531 ;
     RECT  45.468 13.531 56.754 13.559 ;
     RECT  12.348 13.433 14.85 13.595 ;
     RECT  34.668 13.517 36.738 13.595 ;
     RECT  45.468 13.559 47.502 13.631 ;
     RECT  15.588 13.433 21.762 13.661 ;
     RECT  22.536 13.091 27.486 13.661 ;
     RECT  28.44 13.289 33.93 13.661 ;
     RECT  68.724 13.441 68.742 13.661 ;
     RECT  75.24 13.531 84.438 13.661 ;
     RECT  59.076 13.289 63.702 13.829 ;
     RECT  69.84 13.517 71.73 13.865 ;
     RECT  59.115 13.829 63.702 13.909 ;
     RECT  64.476 12.821 64.797 13.909 ;
     RECT  59.115 13.909 64.797 14.009 ;
     RECT  48.24 13.559 56.754 14.071 ;
     RECT  98.1 12.557 110.697 14.099 ;
     RECT  98.1 14.099 101.034 14.135 ;
     RECT  69.876 13.865 71.73 14.141 ;
     RECT  75.24 13.661 79.146 14.141 ;
     RECT  64.515 14.009 64.797 14.203 ;
     RECT  65.52 12.821 67.698 14.203 ;
     RECT  22.536 13.661 26.997 14.237 ;
     RECT  59.115 14.009 63.702 14.237 ;
     RECT  48.24 14.071 56.862 14.243 ;
     RECT  95.256 13.361 97.197 14.251 ;
     RECT  98.1 14.135 98.118 14.251 ;
     RECT  101.844 14.099 110.697 14.405 ;
     RECT  28.44 13.661 30.51 14.521 ;
     RECT  94.215 13.361 94.497 14.521 ;
     RECT  95.256 14.251 98.118 14.521 ;
     RECT  48.24 14.243 56.79 14.675 ;
     RECT  101.844 14.405 106.434 14.711 ;
     RECT  94.215 14.521 98.118 14.813 ;
     RECT  31.284 13.661 33.93 14.819 ;
     RECT  34.815 13.595 36.738 14.819 ;
     RECT  69.915 14.141 71.73 14.819 ;
     RECT  80.208 13.661 84.438 14.819 ;
     RECT  2.415 4.523 2.697 19.187 ;
     RECT  25.38 14.237 26.997 19.187 ;
     RECT  48.24 14.675 56.754 19.187 ;
     RECT  94.215 14.813 97.197 19.187 ;
     RECT  107.172 14.405 110.697 19.187 ;
     RECT  51.948 19.187 56.754 19.435 ;
     RECT  72.615 13.517 74.502 19.435 ;
     RECT  75.315 14.141 79.146 19.435 ;
     RECT  80.208 14.819 82.674 19.435 ;
     RECT  83.415 14.819 84.438 19.435 ;
     RECT  101.844 14.711 102.597 19.435 ;
     RECT  103.428 14.711 106.434 19.435 ;
     RECT  2.415 19.187 2.505 19.457 ;
     RECT  15.876 13.661 21.762 19.457 ;
     RECT  22.536 14.237 24.498 19.457 ;
     RECT  25.38 19.187 26.805 19.457 ;
     RECT  31.284 14.819 33.858 19.457 ;
     RECT  34.815 14.819 35.946 19.457 ;
     RECT  37.515 13.517 41.418 19.457 ;
     RECT  45.468 13.631 46.89 19.457 ;
     RECT  48.24 19.187 51.105 19.457 ;
     RECT  59.115 14.237 59.994 19.457 ;
     RECT  60.876 14.237 63.702 19.457 ;
     RECT  64.515 14.203 67.698 19.457 ;
     RECT  69.915 14.819 71.658 19.457 ;
     RECT  72.615 19.435 79.146 19.457 ;
     RECT  85.248 13.091 93.366 19.457 ;
     RECT  94.215 19.187 97.005 19.457 ;
     RECT  101.844 19.435 106.434 19.457 ;
     RECT  107.172 19.187 110.505 19.457 ;
     RECT  48.24 19.457 50.634 19.483 ;
     RECT  51.948 19.435 56.79 19.565 ;
     RECT  73.044 19.457 79.146 19.565 ;
     RECT  80.208 19.435 84.438 19.565 ;
     RECT  102.708 19.457 106.434 19.565 ;
     RECT  107.172 19.457 109.926 19.565 ;
     RECT  48.204 19.483 50.634 19.613 ;
     RECT  42.444 12.893 44.514 19.661 ;
     RECT  65.016 19.457 67.698 19.757 ;
     RECT  85.248 19.457 91.098 19.805 ;
     RECT  24.48 19.457 24.498 19.901 ;
     RECT  4.788 12.749 11.61 20.573 ;
     RECT  12.456 13.595 14.85 20.573 ;
     RECT  15.876 19.457 17.982 20.573 ;
     RECT  18.756 19.457 21.762 20.573 ;
     RECT  22.536 19.457 23.49 20.573 ;
     RECT  25.38 19.457 26.37 20.573 ;
     RECT  27.792 14.521 30.51 20.573 ;
     RECT  31.284 19.457 32.094 20.573 ;
     RECT  32.868 19.457 33.858 20.573 ;
     RECT  35.244 19.457 35.946 20.573 ;
     RECT  36.72 14.819 36.738 20.573 ;
     RECT  37.944 19.457 40.122 20.573 ;
     RECT  40.896 19.457 41.418 20.573 ;
     RECT  42.444 19.661 42.894 20.573 ;
     RECT  43.74 19.661 44.514 20.573 ;
     RECT  45.468 19.457 45.558 20.573 ;
     RECT  46.332 19.457 46.89 20.573 ;
     RECT  48.24 19.613 50.634 20.573 ;
     RECT  51.948 19.565 56.754 20.573 ;
     RECT  57.6 13.085 58.122 20.573 ;
     RECT  59.868 19.457 59.994 20.573 ;
     RECT  60.876 19.457 61.794 20.573 ;
     RECT  62.568 19.457 63.702 20.573 ;
     RECT  65.448 19.757 67.698 20.573 ;
     RECT  70.236 19.457 71.658 20.573 ;
     RECT  73.044 19.565 74.502 20.573 ;
     RECT  75.636 19.565 79.146 20.573 ;
     RECT  80.208 19.565 82.674 20.573 ;
     RECT  83.772 19.565 84.438 20.573 ;
     RECT  85.248 19.805 85.914 20.573 ;
     RECT  86.976 19.805 91.098 20.573 ;
     RECT  91.944 19.457 93.366 20.573 ;
     RECT  94.356 19.457 96.858 20.573 ;
     RECT  98.1 14.813 98.118 20.573 ;
     RECT  98.856 14.135 101.034 20.573 ;
     RECT  101.844 19.457 101.934 20.573 ;
     RECT  103.428 19.565 106.434 20.573 ;
     RECT  107.172 19.565 107.19 20.573 ;
     RECT  4.788 20.573 4.806 20.621 ;
     RECT  5.58 20.573 6.21 20.621 ;
     RECT  6.948 20.573 6.966 20.621 ;
     RECT  10.008 20.573 10.026 20.621 ;
     RECT  11.088 20.573 11.106 20.621 ;
     RECT  12.456 20.573 13.014 20.621 ;
     RECT  14.472 20.573 14.706 20.621 ;
     RECT  17.568 20.573 17.982 20.621 ;
     RECT  19.152 20.573 19.17 20.621 ;
     RECT  21.744 20.573 21.762 20.621 ;
     RECT  22.932 20.573 22.95 20.621 ;
     RECT  25.92 20.573 26.37 20.621 ;
     RECT  28.44 20.573 28.674 20.621 ;
     RECT  33.552 20.573 33.786 20.621 ;
     RECT  35.892 20.573 35.946 20.621 ;
     RECT  38.196 20.573 39.258 20.621 ;
     RECT  43.992 20.573 44.514 20.621 ;
     RECT  45.468 20.573 45.486 20.621 ;
     RECT  46.368 20.573 46.71 20.621 ;
     RECT  48.996 20.573 49.842 20.621 ;
     RECT  52.956 20.573 52.974 20.621 ;
     RECT  55.8 20.573 56.286 20.621 ;
     RECT  59.976 20.573 59.994 20.621 ;
     RECT  62.604 20.573 63.702 20.621 ;
     RECT  65.592 20.573 66.258 20.621 ;
     RECT  67.608 20.573 67.626 20.621 ;
     RECT  71.46 20.573 71.478 20.621 ;
     RECT  76.284 20.573 76.302 20.621 ;
     RECT  79.128 20.573 79.146 20.621 ;
     RECT  80.208 20.573 80.262 20.621 ;
     RECT  83.952 20.573 84.438 20.621 ;
     RECT  85.248 20.573 85.806 20.621 ;
     RECT  87.516 20.573 87.858 20.621 ;
     RECT  89.532 20.573 90.414 20.621 ;
     RECT  92.124 20.573 92.538 20.621 ;
     RECT  96.804 20.573 96.858 20.621 ;
     RECT  100.188 20.573 100.638 20.621 ;
     RECT  101.916 20.573 101.934 20.621 ;
     RECT  104.688 20.573 104.706 20.621 ;
     RECT  105.732 20.573 106.326 20.621 ;
     RECT  108.252 19.565 109.926 20.621 ;
     RECT  14.688 20.621 14.706 20.669 ;
     RECT  17.964 20.621 17.982 20.669 ;
     RECT  30.096 20.573 30.51 20.669 ;
     RECT  33.552 20.621 33.57 20.669 ;
     RECT  38.196 20.621 38.574 20.669 ;
     RECT  46.368 20.621 46.386 20.669 ;
     RECT  54.576 20.573 54.594 20.669 ;
     RECT  62.604 20.621 62.622 20.669 ;
     RECT  63.684 20.621 63.702 20.669 ;
     RECT  77.976 20.573 77.994 20.669 ;
     RECT  84.348 20.621 84.366 20.669 ;
     RECT  87.84 20.621 87.858 20.669 ;
     RECT  89.532 20.621 89.91 20.669 ;
     RECT  92.52 20.621 92.538 20.669 ;
     RECT  100.188 20.621 100.602 20.669 ;
     RECT  108.252 20.621 108.81 20.669 ;
     RECT  109.8 20.621 109.818 20.669 ;
     RECT  6.192 20.621 6.21 20.717 ;
     RECT  30.492 20.669 30.51 20.717 ;
     RECT  35.928 20.621 35.946 20.717 ;
     RECT  80.244 20.621 80.262 20.717 ;
     RECT  89.532 20.669 89.55 20.717 ;
     RECT  96.804 20.621 96.822 20.717 ;
     RECT  100.584 20.669 100.602 20.717 ;
     RECT  108.252 20.669 108.27 20.717 ;
     RECT  31.284 20.573 31.302 21.389 ;
     RECT  11.124 21.355 11.142 21.485 ;
     RECT  15.3 21.355 15.318 21.485 ;
     RECT  33.012 21.355 33.03 21.485 ;
     RECT  34.164 21.355 34.182 21.485 ;
     RECT  37.368 21.355 37.386 21.485 ;
     RECT  69.624 21.355 69.642 21.485 ;
     RECT  70.488 21.355 71.01 21.485 ;
     RECT  102.168 21.355 102.87 21.485 ;
     RECT  106.452 21.355 106.47 21.485 ;
    LAYER M4 ;
     RECT  2.408 2.148 2.512 19.452 ;
     RECT  2.512 2.418 2.704 19.182 ;
     RECT  2.704 4.272 3.697 4.536 ;
     RECT  2.704 5.76 3.697 6.696 ;
     RECT  3.697 4.272 3.805 6.696 ;
     RECT  4.021 1.776 4.301 1.8 ;
     RECT  4.489 0.528 4.597 0.552 ;
     RECT  4.301 1.728 4.597 1.8 ;
     RECT  4.273 2.928 4.633 2.952 ;
     RECT  3.805 3.936 4.633 6.696 ;
     RECT  4.645 20.544 4.748 20.568 ;
     RECT  4.633 2.928 4.949 6.696 ;
     RECT  4.597 0.528 4.981 1.8 ;
     RECT  4.949 2.832 4.981 6.696 ;
     RECT  4.981 0.528 5.027 6.696 ;
     RECT  5.027 1.728 5.108 6.696 ;
     RECT  4.309 8.88 5.108 8.904 ;
     RECT  4.981 10.704 5.108 10.728 ;
     RECT  5.125 0.288 5.245 0.312 ;
     RECT  5.245 0.192 5.363 0.312 ;
     RECT  5.108 1.728 5.404 19.452 ;
     RECT  5.404 19.44 5.461 19.452 ;
     RECT  5.461 19.44 5.548 19.56 ;
     RECT  5.363 0.288 5.555 0.312 ;
     RECT  5.548 19.44 5.581 19.464 ;
     RECT  5.404 3.984 5.653 7.416 ;
     RECT  5.653 5.136 5.833 7.416 ;
     RECT  4.748 20.544 5.845 20.616 ;
     RECT  5.833 5.232 5.897 7.416 ;
     RECT  5.897 5.664 5.939 7.416 ;
     RECT  5.653 3.984 5.969 4.152 ;
     RECT  5.404 13.488 6.077 13.512 ;
     RECT  5.845 20.544 6.221 20.712 ;
     RECT  5.404 1.728 6.329 2.808 ;
     RECT  6.253 0.528 6.371 0.552 ;
     RECT  5.939 5.712 6.397 7.416 ;
     RECT  6.329 1.728 6.401 2.712 ;
     RECT  5.404 8.88 6.517 8.904 ;
     RECT  6.221 20.544 6.977 20.616 ;
     RECT  6.397 5.712 6.997 7.896 ;
     RECT  6.517 8.88 6.997 9.096 ;
     RECT  5.969 3.984 7.141 4.008 ;
     RECT  6.997 5.712 7.189 9.096 ;
     RECT  7.141 3.984 7.333 4.056 ;
     RECT  7.333 3.984 7.381 4.584 ;
     RECT  7.189 5.712 7.381 9.672 ;
     RECT  7.381 3.984 7.429 9.672 ;
     RECT  7.429 3.936 7.477 9.672 ;
     RECT  7.333 10.944 7.549 10.968 ;
     RECT  7.477 3.408 7.573 9.672 ;
     RECT  7.525 18.816 7.621 18.84 ;
     RECT  6.977 20.544 7.621 20.568 ;
     RECT  6.401 1.728 7.808 1.8 ;
     RECT  7.573 3.36 7.808 9.672 ;
     RECT  7.549 10.848 7.808 10.968 ;
     RECT  7.621 18.816 7.808 20.568 ;
     RECT  7.808 1.728 7.907 20.568 ;
     RECT  7.907 1.728 7.912 19.452 ;
     RECT  7.912 1.728 8.104 19.182 ;
     RECT  8.104 9.696 8.525 11.496 ;
     RECT  8.104 1.728 8.572 7.992 ;
     RECT  8.513 0.192 8.597 0.216 ;
     RECT  8.104 14.544 9.209 14.568 ;
     RECT  8.572 2.736 9.421 7.992 ;
     RECT  9.421 2.736 9.533 8.28 ;
     RECT  7.907 20.544 9.541 20.568 ;
     RECT  8.525 10.368 9.601 11.496 ;
     RECT  9.533 2.784 9.733 8.28 ;
     RECT  8.572 1.728 9.853 1.752 ;
     RECT  9.601 10.272 10.213 11.496 ;
     RECT  10.309 0.192 10.357 0.216 ;
     RECT  10.309 19.536 10.357 19.56 ;
     RECT  9.541 20.544 10.357 20.616 ;
     RECT  9.853 1.728 10.508 1.8 ;
     RECT  9.733 2.784 10.508 9.192 ;
     RECT  10.213 10.272 10.508 11.976 ;
     RECT  9.397 13.056 10.508 13.08 ;
     RECT  10.357 19.536 10.508 20.616 ;
     RECT  10.357 0.192 10.595 0.312 ;
     RECT  10.508 1.728 10.595 20.616 ;
     RECT  10.595 1.728 10.612 19.452 ;
     RECT  10.595 0.288 10.787 0.312 ;
     RECT  10.612 1.728 10.804 19.182 ;
     RECT  10.897 0.576 10.981 0.6 ;
     RECT  10.804 2.832 11.027 3.432 ;
     RECT  10.595 20.544 11.077 20.616 ;
     RECT  11.077 20.544 11.113 21.384 ;
     RECT  11.113 20.544 11.197 21.48 ;
     RECT  10.804 4.512 11.441 12.408 ;
     RECT  11.441 4.56 12.017 12.408 ;
     RECT  11.197 20.544 12.277 20.568 ;
     RECT  11.027 3.216 12.613 3.432 ;
     RECT  12.017 4.56 12.613 7.896 ;
     RECT  12.613 3.216 12.841 7.896 ;
     RECT  10.804 1.728 12.916 1.752 ;
     RECT  12.841 2.832 13.057 7.896 ;
     RECT  12.017 8.928 13.057 12.408 ;
     RECT  12.916 1.728 13.208 1.8 ;
     RECT  13.057 2.832 13.208 12.408 ;
     RECT  13.208 1.728 13.477 19.452 ;
     RECT  13.477 1.728 13.504 19.56 ;
     RECT  13.504 3.216 13.637 10.152 ;
     RECT  13.637 3.216 13.66 9.096 ;
     RECT  13.66 3.552 13.667 9.096 ;
     RECT  13.504 19.536 13.667 19.56 ;
     RECT  13.667 3.648 13.709 9.096 ;
     RECT  13.705 0.576 14.003 0.6 ;
     RECT  13.504 11.424 14.033 12.552 ;
     RECT  14.033 11.424 14.257 11.448 ;
     RECT  13.504 1.728 14.281 1.752 ;
     RECT  12.277 20.544 14.293 20.616 ;
     RECT  14.281 1.152 14.365 1.752 ;
     RECT  14.033 12.528 14.429 12.552 ;
     RECT  13.709 6.288 14.641 9.096 ;
     RECT  13.637 10.128 14.641 10.152 ;
     RECT  13.709 3.648 14.713 5.256 ;
     RECT  14.713 3.312 14.821 5.256 ;
     RECT  14.641 6.288 14.821 10.152 ;
     RECT  14.821 3.312 14.917 10.152 ;
     RECT  14.365 1.728 14.965 1.752 ;
     RECT  14.917 2.976 14.972 10.152 ;
     RECT  14.293 20.544 15.245 20.664 ;
     RECT  15.245 20.544 15.329 21.48 ;
     RECT  15.329 20.544 15.347 21.384 ;
     RECT  14.965 13.632 15.637 13.656 ;
     RECT  14.972 2.88 15.733 10.152 ;
     RECT  15.685 11.136 15.733 11.16 ;
     RECT  15.347 20.544 15.733 20.568 ;
     RECT  15.733 19.584 15.875 20.568 ;
     RECT  14.965 1.728 15.908 1.848 ;
     RECT  15.733 2.88 15.908 11.16 ;
     RECT  15.637 13.056 15.908 13.656 ;
     RECT  15.908 1.728 16.204 19.56 ;
     RECT  16.204 19.536 16.355 19.56 ;
     RECT  15.875 20.544 16.804 20.568 ;
     RECT  16.204 12.384 16.985 12.408 ;
     RECT  16.204 13.632 17.021 13.656 ;
     RECT  16.204 1.728 17.075 10.392 ;
     RECT  17.075 2.784 17.453 10.392 ;
     RECT  17.453 10.272 17.557 10.392 ;
     RECT  16.204 11.376 17.557 11.4 ;
     RECT  16.804 20.544 17.845 20.616 ;
     RECT  17.845 20.544 17.993 20.664 ;
     RECT  17.993 20.544 18.083 20.616 ;
     RECT  18.277 0.288 18.419 0.312 ;
     RECT  17.075 1.728 18.469 1.752 ;
     RECT  17.453 2.784 18.469 9.096 ;
     RECT  18.083 20.544 18.469 20.568 ;
     RECT  18.469 1.728 18.608 9.096 ;
     RECT  17.557 10.272 18.608 11.4 ;
     RECT  17.509 13.008 18.608 13.032 ;
     RECT  18.469 19.584 18.608 20.568 ;
     RECT  18.608 1.728 18.755 20.568 ;
     RECT  18.755 1.728 18.904 19.182 ;
     RECT  18.755 20.544 19.045 20.568 ;
     RECT  19.045 20.544 19.181 20.616 ;
     RECT  19.321 0.528 19.427 0.552 ;
     RECT  18.904 1.728 19.793 10.728 ;
     RECT  19.793 1.728 20.153 10.248 ;
     RECT  18.904 11.952 20.389 11.976 ;
     RECT  20.245 13.488 20.389 13.512 ;
     RECT  19.181 20.544 21.109 20.568 ;
     RECT  20.917 10.704 21.301 10.728 ;
     RECT  20.153 1.728 21.308 9.432 ;
     RECT  21.301 10.704 21.308 10.92 ;
     RECT  20.389 11.952 21.308 13.512 ;
     RECT  21.109 19.584 21.308 20.616 ;
     RECT  21.308 1.728 21.604 20.616 ;
     RECT  21.604 19.68 21.635 20.616 ;
     RECT  21.604 11.904 21.701 13.08 ;
     RECT  21.701 11.904 21.989 12.552 ;
     RECT  21.604 1.728 22.643 10.92 ;
     RECT  21.635 20.544 22.961 20.616 ;
     RECT  21.989 11.904 23.125 11.976 ;
     RECT  22.961 20.544 23.501 20.568 ;
     RECT  22.643 1.728 23.612 2.856 ;
     RECT  22.643 3.936 23.612 10.92 ;
     RECT  23.612 1.728 24.008 10.92 ;
     RECT  23.125 11.904 24.008 12.552 ;
     RECT  22.933 13.536 24.008 13.56 ;
     RECT  23.989 19.584 24.008 19.896 ;
     RECT  24.008 1.728 24.304 19.896 ;
     RECT  24.304 19.584 24.419 19.896 ;
     RECT  24.325 0.288 24.467 0.312 ;
     RECT  24.419 19.68 24.467 19.896 ;
     RECT  24.467 19.776 24.515 19.896 ;
     RECT  24.304 1.728 24.797 11.352 ;
     RECT  24.304 13.632 25.229 14.232 ;
     RECT  25.229 13.632 25.337 13.656 ;
     RECT  24.997 20.544 25.909 20.568 ;
     RECT  24.797 11.328 25.945 11.352 ;
     RECT  25.945 11.328 26.081 12.072 ;
     RECT  26.081 11.328 26.341 12.216 ;
     RECT  25.909 20.544 26.381 20.616 ;
     RECT  26.341 11.232 26.389 12.216 ;
     RECT  24.797 1.728 26.444 9.864 ;
     RECT  26.389 10.896 26.444 12.216 ;
     RECT  26.444 1.728 26.533 12.216 ;
     RECT  25.861 13.488 26.533 13.512 ;
     RECT  26.381 20.544 26.581 20.568 ;
     RECT  26.533 1.728 26.708 13.512 ;
     RECT  26.581 19.584 26.708 20.568 ;
     RECT  26.708 1.728 27.004 20.568 ;
     RECT  27.004 19.536 27.155 20.568 ;
     RECT  27.155 19.632 27.203 20.568 ;
     RECT  27.004 1.728 27.251 13.656 ;
     RECT  27.251 1.728 27.491 12.552 ;
     RECT  27.251 13.632 27.497 13.656 ;
     RECT  27.491 12.528 27.821 12.552 ;
     RECT  27.203 20.544 28.021 20.568 ;
     RECT  28.021 20.544 28.685 20.616 ;
     RECT  27.491 1.728 29.125 11.544 ;
     RECT  28.685 20.544 29.269 20.568 ;
     RECT  29.125 1.728 29.408 11.976 ;
     RECT  28.213 12.96 29.408 13.08 ;
     RECT  28.885 14.784 29.408 14.808 ;
     RECT  29.269 19.584 29.408 20.568 ;
     RECT  29.408 1.728 29.459 20.568 ;
     RECT  29.459 1.728 29.512 19.452 ;
     RECT  29.512 1.728 29.704 19.182 ;
     RECT  29.704 1.728 29.729 11.976 ;
     RECT  29.459 20.544 29.749 20.568 ;
     RECT  29.749 20.544 29.893 20.616 ;
     RECT  29.729 3.264 29.909 11.976 ;
     RECT  29.869 0.576 29.953 0.6 ;
     RECT  29.893 20.544 30.053 20.664 ;
     RECT  30.053 20.592 30.085 20.664 ;
     RECT  29.909 3.264 30.179 9 ;
     RECT  30.085 20.592 30.197 20.712 ;
     RECT  29.909 10.272 30.305 11.976 ;
     RECT  30.197 20.688 30.521 20.712 ;
     RECT  29.704 13.632 30.881 13.656 ;
     RECT  30.757 0.192 30.899 0.216 ;
     RECT  30.179 8.976 30.949 9 ;
     RECT  30.305 10.272 30.949 11.544 ;
     RECT  30.949 13.056 31.091 13.08 ;
     RECT  29.729 1.728 31.093 2.28 ;
     RECT  30.179 3.264 31.093 7.992 ;
     RECT  30.757 21.36 31.313 21.384 ;
     RECT  31.093 1.728 31.765 7.992 ;
     RECT  30.949 8.976 31.765 11.544 ;
     RECT  31.621 20.544 31.909 20.568 ;
     RECT  31.909 19.68 31.957 20.568 ;
     RECT  31.765 1.728 32.108 11.544 ;
     RECT  31.285 12.528 32.108 12.936 ;
     RECT  31.957 19.584 32.108 20.568 ;
     RECT  32.108 1.728 32.339 20.568 ;
     RECT  32.339 1.728 32.404 19.182 ;
     RECT  32.339 20.544 32.965 20.568 ;
     RECT  32.965 20.544 33.001 21.384 ;
     RECT  33.001 20.544 33.085 21.48 ;
     RECT  33.085 20.544 33.875 20.664 ;
     RECT  34.109 21.36 34.193 21.48 ;
     RECT  34.193 21.36 34.211 21.384 ;
     RECT  32.404 1.728 34.501 11.976 ;
     RECT  34.501 1.728 34.808 12.504 ;
     RECT  34.645 13.632 34.808 13.656 ;
     RECT  34.808 1.728 34.837 19.452 ;
     RECT  34.837 1.728 34.981 19.608 ;
     RECT  34.981 1.248 35.104 20.568 ;
     RECT  35.104 1.248 35.173 11.976 ;
     RECT  35.104 19.584 35.173 20.568 ;
     RECT  35.173 19.584 35.267 20.616 ;
     RECT  35.267 20.544 35.273 20.616 ;
     RECT  35.173 1.152 35.315 11.976 ;
     RECT  35.104 13.488 35.489 13.656 ;
     RECT  35.273 20.592 35.653 20.616 ;
     RECT  35.653 20.592 35.957 20.712 ;
     RECT  35.315 1.728 36.029 11.976 ;
     RECT  36.029 1.728 36.065 7.224 ;
     RECT  36.373 20.544 36.749 20.568 ;
     RECT  36.065 1.728 37.045 6.888 ;
     RECT  36.029 8.4 37.189 11.976 ;
     RECT  35.489 13.488 37.189 13.512 ;
     RECT  37.189 8.4 37.333 13.512 ;
     RECT  37.313 21.36 37.397 21.48 ;
     RECT  37.397 21.36 37.427 21.384 ;
     RECT  37.045 1.728 37.508 7.416 ;
     RECT  37.333 8.4 37.508 14.136 ;
     RECT  37.285 19.584 37.508 19.608 ;
     RECT  37.508 1.728 37.571 19.608 ;
     RECT  37.571 1.728 37.804 19.56 ;
     RECT  37.804 14.112 37.937 14.136 ;
     RECT  37.804 19.536 37.955 19.56 ;
     RECT  37.804 8.976 38.261 11.976 ;
     RECT  38.261 8.976 38.627 11.448 ;
     RECT  37.861 20.544 38.627 20.664 ;
     RECT  37.804 1.728 38.773 7.944 ;
     RECT  38.773 1.728 38.86 7.992 ;
     RECT  38.627 8.976 38.869 10.824 ;
     RECT  38.627 20.544 39.269 20.616 ;
     RECT  38.869 8.544 39.589 10.824 ;
     RECT  39.397 11.952 39.589 11.976 ;
     RECT  39.589 8.544 39.973 11.976 ;
     RECT  38.86 1.728 40.021 7.416 ;
     RECT  39.973 8.496 40.021 11.976 ;
     RECT  39.269 20.544 40.021 20.568 ;
     RECT  40.021 1.728 40.208 11.976 ;
     RECT  39.925 13.056 40.208 13.08 ;
     RECT  40.021 19.584 40.208 20.568 ;
     RECT  40.208 1.728 40.307 20.568 ;
     RECT  40.307 1.728 40.312 19.452 ;
     RECT  39.973 0.288 40.451 0.312 ;
     RECT  40.312 1.728 40.504 19.182 ;
     RECT  40.504 1.728 40.745 11.976 ;
     RECT  40.504 13.056 40.961 13.08 ;
     RECT  40.745 1.728 41.645 11.4 ;
     RECT  41.645 1.728 42.757 10.392 ;
     RECT  41.645 11.376 42.757 11.4 ;
     RECT  40.307 20.544 42.757 20.568 ;
     RECT  42.757 19.632 42.805 20.568 ;
     RECT  42.757 1.728 42.908 11.4 ;
     RECT  42.613 12.528 42.908 12.552 ;
     RECT  40.504 14.208 42.908 14.232 ;
     RECT  42.805 19.536 42.908 20.568 ;
     RECT  42.908 1.728 43.204 20.568 ;
     RECT  43.204 19.536 43.331 20.568 ;
     RECT  43.331 19.632 43.372 20.568 ;
     RECT  43.204 1.728 43.379 11.448 ;
     RECT  43.204 12.528 43.409 13.56 ;
     RECT  43.409 13.536 43.661 13.56 ;
     RECT  43.372 20.544 43.813 20.568 ;
     RECT  43.379 2.784 44.193 11.448 ;
     RECT  43.409 12.528 44.339 12.552 ;
     RECT  43.379 1.728 44.341 1.752 ;
     RECT  44.193 2.784 44.341 5.16 ;
     RECT  44.193 6.192 44.597 11.448 ;
     RECT  44.341 1.728 45.241 5.16 ;
     RECT  44.597 6.24 45.253 11.448 ;
     RECT  45.253 6.24 45.493 12.024 ;
     RECT  44.821 13.056 45.493 13.08 ;
     RECT  45.241 1.728 45.565 5.208 ;
     RECT  45.493 6.24 45.565 13.08 ;
     RECT  45.565 1.728 45.608 13.08 ;
     RECT  45.608 1.728 45.685 19.452 ;
     RECT  43.813 20.544 45.685 20.616 ;
     RECT  45.685 1.728 45.904 20.616 ;
     RECT  45.904 1.728 46.019 12.552 ;
     RECT  45.904 19.584 46.067 20.616 ;
     RECT  45.904 14.784 46.115 14.808 ;
     RECT  46.019 12.048 46.181 12.552 ;
     RECT  46.067 20.544 46.213 20.616 ;
     RECT  46.213 20.544 46.397 20.664 ;
     RECT  46.397 20.544 46.739 20.616 ;
     RECT  46.019 1.728 46.787 11.016 ;
     RECT  46.739 20.544 46.901 20.568 ;
     RECT  46.787 5.616 46.937 11.016 ;
     RECT  46.937 5.616 47.905 10.728 ;
     RECT  46.787 1.728 48.013 4.584 ;
     RECT  47.905 5.616 48.013 10.824 ;
     RECT  48.037 20.544 48.133 20.568 ;
     RECT  48.133 19.632 48.149 20.568 ;
     RECT  48.013 1.728 48.308 10.824 ;
     RECT  46.181 12.048 48.308 12.408 ;
     RECT  47.557 13.92 48.308 13.944 ;
     RECT  48.149 19.488 48.308 20.568 ;
     RECT  48.308 1.728 48.419 20.568 ;
     RECT  48.419 1.728 48.604 19.182 ;
     RECT  48.181 0.288 48.755 0.312 ;
     RECT  48.419 20.544 48.757 20.568 ;
     RECT  48.604 12.336 49.241 12.36 ;
     RECT  48.757 20.544 49.853 20.616 ;
     RECT  49.573 12.48 50.245 12.504 ;
     RECT  49.853 20.544 50.645 20.568 ;
     RECT  48.604 1.728 51.008 10.632 ;
     RECT  50.245 12.48 51.008 13.08 ;
     RECT  50.773 14.208 51.008 14.232 ;
     RECT  50.821 19.584 51.008 19.704 ;
     RECT  50.869 0.192 51.155 0.216 ;
     RECT  51.008 1.728 51.155 19.704 ;
     RECT  51.155 1.728 51.304 19.56 ;
     RECT  51.304 12.864 51.365 12.888 ;
     RECT  51.304 14.208 51.365 14.232 ;
     RECT  51.304 19.536 51.443 19.56 ;
     RECT  51.781 20.544 52.309 20.568 ;
     RECT  51.304 1.728 52.453 1.752 ;
     RECT  51.304 2.832 52.453 11.4 ;
     RECT  52.309 20.544 52.985 20.616 ;
     RECT  52.981 15.312 53.125 15.336 ;
     RECT  52.453 1.728 53.708 11.4 ;
     RECT  52.789 12.48 53.708 12.504 ;
     RECT  53.125 14.784 53.708 15.336 ;
     RECT  53.557 19.536 53.708 19.56 ;
     RECT  53.708 1.728 53.845 19.56 ;
     RECT  52.985 20.544 53.845 20.568 ;
     RECT  53.845 1.728 54.004 20.568 ;
     RECT  54.004 12.48 54.029 12.504 ;
     RECT  54.004 19.536 54.035 20.568 ;
     RECT  54.035 19.584 54.131 20.568 ;
     RECT  54.004 15.312 54.173 15.336 ;
     RECT  54.004 5.616 54.323 11.16 ;
     RECT  54.131 20.544 54.325 20.568 ;
     RECT  54.323 5.616 54.425 9.336 ;
     RECT  54.323 10.368 54.461 11.16 ;
     RECT  54.004 1.728 54.569 4.632 ;
     RECT  54.325 20.544 54.605 20.664 ;
     RECT  54.569 3.936 55.177 4.632 ;
     RECT  54.425 5.616 55.177 9.144 ;
     RECT  55.525 13.056 55.669 13.08 ;
     RECT  54.569 1.728 55.789 2.904 ;
     RECT  55.177 3.936 55.789 9.144 ;
     RECT  55.789 1.728 55.861 9.144 ;
     RECT  54.461 10.368 56.005 10.872 ;
     RECT  55.669 12.384 56.005 13.08 ;
     RECT  55.957 0.192 56.243 0.216 ;
     RECT  54.997 14.208 56.293 14.232 ;
     RECT  54.605 20.544 56.293 20.616 ;
     RECT  56.293 19.584 56.297 20.616 ;
     RECT  55.861 1.728 56.408 9.384 ;
     RECT  56.005 10.368 56.408 13.08 ;
     RECT  56.293 14.208 56.408 14.808 ;
     RECT  56.297 19.584 56.408 20.568 ;
     RECT  56.408 1.728 56.435 20.568 ;
     RECT  56.435 1.728 56.449 19.56 ;
     RECT  56.449 2.016 56.704 19.56 ;
     RECT  56.704 19.44 56.812 19.56 ;
     RECT  56.812 19.44 56.845 19.464 ;
     RECT  56.704 14.784 56.963 14.808 ;
     RECT  56.704 2.016 57.491 12.552 ;
     RECT  57.491 2.016 57.517 11.496 ;
     RECT  56.435 20.544 58.133 20.568 ;
     RECT  57.491 12.528 58.405 12.552 ;
     RECT  57.517 1.728 58.597 11.496 ;
     RECT  58.405 12.528 58.597 13.08 ;
     RECT  58.597 1.728 59.108 13.08 ;
     RECT  57.877 14.64 59.108 14.664 ;
     RECT  58.981 19.584 59.108 19.608 ;
     RECT  59.108 1.728 59.404 19.608 ;
     RECT  59.404 19.536 59.413 19.608 ;
     RECT  59.413 19.536 59.555 19.656 ;
     RECT  59.555 19.536 59.603 19.56 ;
     RECT  59.404 1.728 59.825 11.976 ;
     RECT  59.825 2.304 59.933 11.976 ;
     RECT  59.749 20.544 59.941 20.568 ;
     RECT  59.941 20.544 60.028 20.616 ;
     RECT  59.404 14.208 60.221 14.232 ;
     RECT  59.404 13.056 60.613 13.08 ;
     RECT  59.933 2.304 60.821 11.4 ;
     RECT  60.821 2.256 61.141 11.4 ;
     RECT  61.141 1.728 61.808 11.4 ;
     RECT  60.613 13.056 61.808 14.04 ;
     RECT  61.808 1.728 62.104 19.452 ;
     RECT  62.104 1.728 62.245 11.448 ;
     RECT  62.149 19.536 62.291 19.56 ;
     RECT  60.028 20.544 62.293 20.568 ;
     RECT  62.104 12.48 63.101 12.504 ;
     RECT  62.293 20.544 63.677 20.664 ;
     RECT  63.677 20.64 63.713 20.664 ;
     RECT  62.245 1.728 64.117 10.968 ;
     RECT  64.021 11.952 64.117 11.976 ;
     RECT  64.117 1.728 64.508 11.976 ;
     RECT  63.829 13.056 64.508 13.08 ;
     RECT  64.501 19.584 64.508 19.608 ;
     RECT  64.508 1.728 64.693 19.608 ;
     RECT  64.693 1.728 64.804 19.704 ;
     RECT  64.804 19.584 64.837 19.704 ;
     RECT  64.837 19.584 64.931 19.752 ;
     RECT  64.931 19.68 64.979 19.752 ;
     RECT  64.804 14.208 65.009 14.952 ;
     RECT  64.979 19.728 65.029 19.752 ;
     RECT  64.804 9.84 65.045 12.408 ;
     RECT  65.009 14.208 65.045 14.856 ;
     RECT  65.029 19.728 65.045 20.568 ;
     RECT  64.804 1.728 65.125 8.616 ;
     RECT  65.045 20.544 65.476 20.568 ;
     RECT  65.045 9.84 65.693 11.352 ;
     RECT  65.045 12.384 65.765 12.408 ;
     RECT  65.045 14.208 65.945 14.232 ;
     RECT  65.476 20.544 66.275 20.616 ;
     RECT  65.125 1.728 66.337 8.568 ;
     RECT  65.693 9.84 66.337 10.92 ;
     RECT  66.337 1.728 67.045 10.92 ;
     RECT  67.045 1.728 67.208 11.16 ;
     RECT  66.565 12.48 67.208 12.504 ;
     RECT  67.208 1.728 67.381 19.452 ;
     RECT  67.381 1.728 67.504 19.56 ;
     RECT  66.275 20.544 67.573 20.568 ;
     RECT  67.573 20.544 67.66 20.616 ;
     RECT  67.504 18.816 67.667 19.56 ;
     RECT  67.66 20.544 67.709 20.568 ;
     RECT  67.667 18.816 68.387 18.84 ;
     RECT  67.504 1.728 68.531 11.448 ;
     RECT  67.504 13.056 68.753 13.656 ;
     RECT  68.821 0.288 68.963 0.312 ;
     RECT  68.753 13.056 69.445 13.08 ;
     RECT  69.589 21.36 69.613 21.384 ;
     RECT  68.531 1.728 69.733 11.4 ;
     RECT  69.733 1.728 69.908 11.976 ;
     RECT  69.445 13.008 69.908 13.08 ;
     RECT  69.253 14.112 69.908 14.136 ;
     RECT  69.733 19.584 69.908 19.608 ;
     RECT  69.908 1.728 69.971 19.608 ;
     RECT  69.971 1.728 70.204 19.56 ;
     RECT  69.613 21.36 70.22 21.48 ;
     RECT  70.117 0.288 70.355 0.312 ;
     RECT  70.204 19.536 70.355 19.56 ;
     RECT  70.22 20.544 71.065 21.48 ;
     RECT  70.204 1.728 71.129 10.92 ;
     RECT  70.204 11.952 71.129 11.976 ;
     RECT  71.065 20.544 71.489 20.616 ;
     RECT  71.489 20.544 71.669 20.568 ;
     RECT  71.989 13.488 72.133 13.512 ;
     RECT  71.129 1.728 72.181 10.392 ;
     RECT  71.461 11.376 72.181 11.4 ;
     RECT  72.181 1.728 72.421 11.4 ;
     RECT  72.133 12.528 72.421 13.512 ;
     RECT  72.421 1.728 72.608 13.512 ;
     RECT  71.797 14.784 72.608 14.808 ;
     RECT  72.421 19.584 72.608 19.608 ;
     RECT  72.608 1.728 72.707 19.608 ;
     RECT  72.707 1.728 72.712 19.452 ;
     RECT  72.712 1.728 72.904 19.182 ;
     RECT  73.477 0.192 73.577 0.216 ;
     RECT  72.904 1.728 74.005 11.976 ;
     RECT  74.869 14.112 75.013 14.136 ;
     RECT  75.149 19.44 75.164 19.464 ;
     RECT  74.005 1.728 75.308 12.552 ;
     RECT  75.013 14.112 75.308 14.808 ;
     RECT  75.164 19.44 75.308 19.56 ;
     RECT  75.308 1.728 75.604 19.56 ;
     RECT  75.604 19.536 75.779 19.56 ;
     RECT  75.604 1.728 75.925 4.584 ;
     RECT  75.604 5.568 76.205 11.976 ;
     RECT  72.805 20.544 76.213 20.568 ;
     RECT  75.925 2.736 76.307 4.584 ;
     RECT  76.213 20.544 76.313 20.616 ;
     RECT  75.604 14.784 76.691 14.808 ;
     RECT  76.307 2.832 76.885 4.584 ;
     RECT  76.205 5.568 76.885 11.544 ;
     RECT  76.741 13.056 77.221 13.08 ;
     RECT  75.925 1.728 77.269 1.752 ;
     RECT  76.885 2.832 77.269 11.544 ;
     RECT  77.269 1.728 77.317 11.544 ;
     RECT  76.313 20.544 77.749 20.568 ;
     RECT  77.749 20.544 78.005 20.664 ;
     RECT  77.317 1.728 78.008 11.736 ;
     RECT  77.221 13.008 78.008 13.08 ;
     RECT  78.008 1.728 78.085 19.452 ;
     RECT  78.005 20.544 78.085 20.616 ;
     RECT  78.085 1.728 78.304 20.616 ;
     RECT  78.304 19.584 78.419 20.616 ;
     RECT  78.085 0.288 78.515 0.312 ;
     RECT  78.304 14.784 78.515 14.808 ;
     RECT  78.304 1.728 79.139 11.448 ;
     RECT  79.139 3.936 79.337 11.448 ;
     RECT  78.304 13.632 79.621 13.656 ;
     RECT  78.419 20.544 80.101 20.616 ;
     RECT  80.101 20.544 80.273 20.712 ;
     RECT  79.139 1.728 80.293 2.856 ;
     RECT  79.337 3.936 80.293 11.208 ;
     RECT  79.621 13.056 80.389 13.656 ;
     RECT  80.273 20.544 80.485 20.568 ;
     RECT  80.485 19.68 80.533 20.568 ;
     RECT  80.293 1.728 80.708 11.208 ;
     RECT  80.389 12.528 80.708 13.656 ;
     RECT  80.533 19.584 80.708 20.568 ;
     RECT  80.708 1.728 80.819 20.568 ;
     RECT  80.819 1.728 81.004 19.182 ;
     RECT  81.004 14.784 81.251 14.808 ;
     RECT  81.004 1.728 81.389 13.656 ;
     RECT  81.389 1.728 81.929 13.512 ;
     RECT  81.929 1.728 81.971 12.504 ;
     RECT  81.971 9.888 82.037 12.504 ;
     RECT  81.929 13.488 82.217 13.512 ;
     RECT  81.971 1.728 83.077 8.856 ;
     RECT  83.077 1.728 83.185 9.096 ;
     RECT  82.037 10.08 83.185 12.504 ;
     RECT  83.249 19.44 83.276 19.464 ;
     RECT  83.276 19.44 83.363 19.56 ;
     RECT  83.185 1.728 83.408 12.504 ;
     RECT  83.363 19.44 83.408 19.452 ;
     RECT  83.408 1.728 83.512 19.452 ;
     RECT  80.819 20.544 83.653 20.568 ;
     RECT  83.512 1.728 83.704 19.182 ;
     RECT  83.704 1.728 83.765 12.936 ;
     RECT  83.653 20.544 83.845 20.616 ;
     RECT  83.845 20.544 84.377 20.664 ;
     RECT  83.269 0.288 84.563 0.312 ;
     RECT  83.765 1.728 84.953 11.208 ;
     RECT  84.953 8.832 85.525 11.208 ;
     RECT  83.765 12.912 85.717 12.936 ;
     RECT  84.377 20.544 85.817 20.616 ;
     RECT  85.817 20.544 85.948 20.568 ;
     RECT  84.953 1.728 86.108 7.656 ;
     RECT  85.525 8.832 86.108 11.256 ;
     RECT  85.717 12.912 86.108 13.08 ;
     RECT  85.045 14.208 86.108 14.232 ;
     RECT  86.053 19.584 86.108 19.8 ;
     RECT  86.108 1.728 86.404 19.8 ;
     RECT  86.404 14.592 86.573 14.808 ;
     RECT  86.573 14.688 86.627 14.808 ;
     RECT  86.404 19.536 86.627 19.8 ;
     RECT  86.404 1.728 86.969 11.448 ;
     RECT  86.969 8.832 87.113 11.448 ;
     RECT  87.113 8.832 87.299 11.4 ;
     RECT  86.917 20.544 87.397 20.568 ;
     RECT  87.397 20.544 87.589 20.616 ;
     RECT  86.404 13.056 87.733 13.512 ;
     RECT  87.589 20.544 87.869 20.664 ;
     RECT  87.299 8.928 88.261 11.4 ;
     RECT  86.969 1.728 88.693 7.656 ;
     RECT  88.261 8.928 88.693 11.976 ;
     RECT  87.869 20.544 88.693 20.568 ;
     RECT  88.693 1.728 88.808 11.976 ;
     RECT  87.733 13.056 88.808 13.656 ;
     RECT  88.693 19.584 88.808 20.568 ;
     RECT  88.808 1.728 88.835 20.568 ;
     RECT  88.835 1.728 89.104 19.56 ;
     RECT  89.104 19.44 89.212 19.56 ;
     RECT  89.104 1.728 89.237 11.976 ;
     RECT  89.212 19.44 89.245 19.464 ;
     RECT  88.835 20.544 89.521 20.568 ;
     RECT  89.104 14.016 89.669 14.04 ;
     RECT  89.521 20.544 89.987 20.712 ;
     RECT  89.237 1.728 90.277 11.016 ;
     RECT  89.987 20.544 90.425 20.616 ;
     RECT  90.277 1.728 90.457 11.4 ;
     RECT  90.457 1.152 90.541 11.4 ;
     RECT  90.613 0.576 90.7 0.6 ;
     RECT  90.425 20.544 91.189 20.568 ;
     RECT  90.541 1.728 91.508 11.4 ;
     RECT  91.141 12.48 91.508 12.504 ;
     RECT  91.189 19.584 91.508 20.568 ;
     RECT  91.508 1.728 91.523 20.568 ;
     RECT  91.523 1.728 91.804 19.56 ;
     RECT  91.804 19.536 91.955 19.56 ;
     RECT  91.523 20.544 91.972 20.568 ;
     RECT  91.804 12.48 92.261 12.504 ;
     RECT  91.972 20.544 92.485 20.616 ;
     RECT  92.485 20.544 92.572 20.664 ;
     RECT  91.804 14.016 92.585 14.04 ;
     RECT  91.804 1.728 93.013 10.296 ;
     RECT  93.013 1.728 93.493 10.728 ;
     RECT  93.493 1.728 93.841 11.64 ;
     RECT  93.841 1.104 94.069 11.64 ;
     RECT  92.572 20.544 94.069 20.568 ;
     RECT  94.069 1.104 94.208 11.976 ;
     RECT  93.157 13.056 94.208 13.08 ;
     RECT  93.493 14.784 94.208 14.808 ;
     RECT  94.069 19.584 94.208 20.568 ;
     RECT  94.208 1.104 94.259 20.568 ;
     RECT  94.259 1.104 94.312 19.452 ;
     RECT  94.312 1.104 94.357 19.182 ;
     RECT  94.357 0.288 94.504 19.182 ;
     RECT  94.504 0.288 94.645 2.904 ;
     RECT  94.645 0.288 94.673 2.712 ;
     RECT  94.673 1.152 94.684 2.712 ;
     RECT  94.504 3.936 95.429 11.976 ;
     RECT  94.684 1.728 95.701 2.712 ;
     RECT  95.701 1.728 95.965 2.856 ;
     RECT  95.429 3.936 95.965 11.4 ;
     RECT  94.259 20.544 96.004 20.568 ;
     RECT  96.004 20.544 96.421 20.616 ;
     RECT  95.893 13.632 96.661 13.656 ;
     RECT  96.421 20.544 96.833 20.712 ;
     RECT  96.833 20.544 96.869 20.616 ;
     RECT  95.965 1.728 96.908 11.4 ;
     RECT  96.661 13.056 96.908 13.656 ;
     RECT  96.901 19.584 96.908 19.8 ;
     RECT  96.908 1.728 97.204 19.8 ;
     RECT  97.204 19.584 97.379 19.8 ;
     RECT  97.204 14.448 97.409 14.808 ;
     RECT  97.379 19.776 97.427 19.8 ;
     RECT  97.409 14.544 97.475 14.808 ;
     RECT  97.204 1.728 97.517 12.552 ;
     RECT  97.475 14.544 97.553 14.568 ;
     RECT  97.517 1.728 97.715 12.024 ;
     RECT  97.715 1.728 97.913 11.736 ;
     RECT  97.913 5.136 98.051 11.736 ;
     RECT  98.051 5.472 99.097 11.736 ;
     RECT  97.913 1.728 99.164 4.056 ;
     RECT  99.097 5.136 99.164 11.736 ;
     RECT  99.164 1.728 99.397 11.736 ;
     RECT  98.437 13.008 99.397 13.032 ;
     RECT  97.909 20.544 99.493 20.568 ;
     RECT  99.397 1.728 99.608 13.032 ;
     RECT  98.581 14.208 99.608 14.232 ;
     RECT  99.493 19.584 99.608 20.568 ;
     RECT  99.608 1.728 99.683 20.568 ;
     RECT  99.683 1.728 99.712 19.452 ;
     RECT  99.712 1.728 99.904 19.182 ;
     RECT  99.683 20.544 99.973 20.568 ;
     RECT  99.973 20.544 100.117 20.616 ;
     RECT  99.904 1.728 100.289 12.024 ;
     RECT  100.117 20.544 100.453 20.664 ;
     RECT  100.453 20.544 100.613 20.712 ;
     RECT  100.289 12 100.793 12.024 ;
     RECT  99.904 15.36 100.937 15.384 ;
     RECT  100.289 1.728 101.317 10.92 ;
     RECT  100.613 20.544 101.945 20.616 ;
     RECT  101.317 1.728 102.085 11.256 ;
     RECT  102.085 19.68 102.181 19.704 ;
     RECT  102.085 1.728 102.308 11.976 ;
     RECT  101.989 14.784 102.308 14.808 ;
     RECT  102.181 19.584 102.308 19.704 ;
     RECT  102.308 1.728 102.563 19.704 ;
     RECT  102.563 1.728 102.604 19.56 ;
     RECT  102.604 19.44 102.748 19.56 ;
     RECT  102.748 19.44 102.781 19.464 ;
     RECT  102.113 21.36 102.881 21.48 ;
     RECT  102.881 21.36 102.899 21.384 ;
     RECT  102.604 1.728 103.033 12.552 ;
     RECT  103.033 1.728 103.283 12.504 ;
     RECT  103.283 1.728 104.389 1.752 ;
     RECT  103.283 2.784 104.389 12.504 ;
     RECT  104.389 1.728 104.461 12.504 ;
     RECT  103.333 20.544 104.533 20.568 ;
     RECT  104.533 20.544 104.717 20.616 ;
     RECT  104.717 20.544 104.869 20.568 ;
     RECT  104.461 1.728 105.008 13.128 ;
     RECT  104.725 14.208 105.008 14.232 ;
     RECT  104.869 19.584 105.008 20.568 ;
     RECT  105.008 1.728 105.107 20.568 ;
     RECT  105.107 1.728 105.304 19.56 ;
     RECT  105.304 19.536 105.443 19.56 ;
     RECT  105.304 1.728 105.539 11.4 ;
     RECT  105.107 20.544 105.692 20.568 ;
     RECT  105.539 1.728 105.833 7.416 ;
     RECT  105.304 12.48 106.121 12.504 ;
     RECT  105.539 8.736 106.157 11.4 ;
     RECT  105.692 20.544 106.405 20.616 ;
     RECT  106.405 20.544 106.441 21.384 ;
     RECT  106.157 10.848 106.445 11.4 ;
     RECT  106.441 20.544 106.525 21.48 ;
     RECT  105.833 1.728 106.933 7.368 ;
     RECT  106.157 8.736 106.933 9.384 ;
     RECT  106.933 1.728 107.413 9.384 ;
     RECT  106.445 10.848 107.413 11.256 ;
     RECT  107.549 19.44 107.564 19.464 ;
     RECT  107.564 19.44 107.651 19.56 ;
     RECT  107.413 1.728 107.708 11.256 ;
     RECT  106.741 12.384 107.708 12.408 ;
     RECT  106.597 13.536 107.708 13.56 ;
     RECT  107.651 19.44 107.708 19.452 ;
     RECT  107.708 1.728 107.812 19.452 ;
     RECT  106.525 20.544 107.941 20.568 ;
     RECT  107.812 1.728 108.004 19.182 ;
     RECT  107.941 20.544 108.085 20.616 ;
     RECT  107.749 0.288 108.179 0.312 ;
     RECT  108.085 20.544 108.281 20.712 ;
     RECT  108.004 1.728 108.353 10.104 ;
     RECT  108.353 1.728 108.389 10.056 ;
     RECT  108.389 1.728 108.707 6.84 ;
     RECT  108.707 3.84 108.851 6.84 ;
     RECT  108.851 3.936 108.899 6.84 ;
     RECT  108.389 8.16 108.947 10.056 ;
     RECT  108.947 9.696 109.073 10.056 ;
     RECT  108.947 8.16 109.361 8.52 ;
     RECT  108.281 20.544 109.757 20.664 ;
     RECT  109.361 8.16 109.813 8.376 ;
     RECT  109.757 20.592 109.829 20.664 ;
     RECT  109.829 20.592 109.937 20.616 ;
     RECT  108.707 1.728 109.957 2.856 ;
     RECT  108.899 3.936 110.149 6.36 ;
     RECT  109.957 1.728 110.261 2.904 ;
     RECT  110.261 2.148 110.408 2.904 ;
     RECT  110.149 3.936 110.408 6.696 ;
     RECT  109.813 7.776 110.408 8.376 ;
     RECT  109.073 9.696 110.408 9.96 ;
     RECT  109.285 12.912 110.408 12.936 ;
     RECT  110.408 2.148 110.512 19.452 ;
     RECT  110.512 2.418 110.704 19.182 ;
     RECT  110.704 7.968 110.765 8.232 ;
     RECT  110.704 2.88 110.909 5.016 ;
     RECT  110.909 2.88 111.017 3.096 ;
     RECT  110.704 6.672 111.125 6.696 ;
     RECT  110.909 4.128 111.197 5.016 ;
     RECT  110.765 7.968 111.197 8.184 ;
     RECT  111.017 2.88 111.341 2.904 ;
     RECT  111.197 4.128 111.485 4.296 ;
     RECT  111.485 4.272 111.737 4.296 ;
     RECT  111.197 8.16 111.881 8.184 ;
    LAYER M5 ;
     RECT  4.344 0.144 4.464 0.192 ;
     RECT  4.488 0.144 4.656 0.192 ;
     RECT  4.68 0.144 4.8 0.192 ;
     RECT  4.824 0.144 4.992 0.192 ;
     RECT  5.016 0.144 5.136 0.192 ;
     RECT  5.16 0.144 5.328 0.192 ;
     RECT  5.352 0.144 5.472 0.192 ;
     RECT  5.496 0.144 5.664 0.192 ;
     RECT  5.688 0.144 5.856 0.192 ;
     RECT  5.88 0.144 6 0.192 ;
     RECT  6.024 0.144 6.192 0.192 ;
     RECT  6.216 0.144 6.336 0.192 ;
     RECT  6.36 0.144 6.528 0.192 ;
     RECT  6.552 0.144 6.672 0.192 ;
     RECT  6.696 0.144 6.864 0.192 ;
     RECT  6.888 0.144 7.008 0.192 ;
     RECT  7.032 0.144 7.2 0.192 ;
     RECT  7.224 0.144 7.344 0.192 ;
     RECT  7.368 0.144 7.536 0.192 ;
     RECT  7.56 0.144 7.68 0.192 ;
     RECT  7.704 0.144 7.872 0.192 ;
     RECT  7.896 0.144 8.016 0.192 ;
     RECT  8.04 0.144 8.208 0.192 ;
     RECT  8.232 0.144 8.4 0.192 ;
     RECT  8.424 0.144 8.544 0.192 ;
     RECT  8.568 0.144 8.736 0.192 ;
     RECT  8.76 0.144 8.88 0.192 ;
     RECT  8.904 0.144 9.072 0.192 ;
     RECT  9.096 0.144 9.216 0.192 ;
     RECT  9.24 0.144 9.408 0.192 ;
     RECT  9.432 0.144 9.552 0.192 ;
     RECT  9.576 0.144 9.744 0.192 ;
     RECT  9.768 0.144 9.888 0.192 ;
     RECT  9.912 0.144 10.08 0.192 ;
     RECT  10.104 0.144 10.224 0.192 ;
     RECT  10.248 0.144 10.416 0.192 ;
     RECT  10.44 0.144 10.56 0.192 ;
     RECT  10.584 0.144 10.752 0.192 ;
     RECT  10.776 0.144 10.944 0.192 ;
     RECT  10.968 0.144 11.088 0.192 ;
     RECT  11.112 0.144 11.28 0.192 ;
     RECT  11.304 0.144 11.424 0.192 ;
     RECT  11.448 0.144 11.616 0.192 ;
     RECT  11.64 0.144 11.76 0.192 ;
     RECT  11.784 0.144 11.952 0.192 ;
     RECT  11.976 0.144 12.096 0.192 ;
     RECT  12.12 0.144 12.288 0.192 ;
     RECT  12.312 0.144 12.432 0.192 ;
     RECT  12.456 0.144 12.624 0.192 ;
     RECT  12.648 0.144 12.768 0.192 ;
     RECT  12.792 0.144 12.96 0.192 ;
     RECT  12.984 0.144 13.152 0.192 ;
     RECT  13.176 0.144 13.296 0.192 ;
     RECT  13.32 0.144 13.488 0.192 ;
     RECT  13.512 0.144 13.632 0.192 ;
     RECT  13.656 0.144 13.824 0.192 ;
     RECT  13.848 0.144 13.968 0.192 ;
     RECT  13.992 0.144 14.16 0.192 ;
     RECT  14.184 0.144 14.304 0.192 ;
     RECT  14.328 0.144 14.496 0.192 ;
     RECT  14.52 0.144 14.64 0.192 ;
     RECT  14.664 0.144 14.832 0.192 ;
     RECT  14.856 0.144 14.976 0.192 ;
     RECT  15 0.144 15.168 0.192 ;
     RECT  15.192 0.144 15.312 0.192 ;
     RECT  15.336 0.144 15.504 0.192 ;
     RECT  15.528 0.144 15.696 0.192 ;
     RECT  15.72 0.144 15.84 0.192 ;
     RECT  15.864 0.144 16.032 0.192 ;
     RECT  16.056 0.144 16.176 0.192 ;
     RECT  16.2 0.144 16.368 0.192 ;
     RECT  16.392 0.144 16.512 0.192 ;
     RECT  16.536 0.144 16.704 0.192 ;
     RECT  16.728 0.144 16.848 0.192 ;
     RECT  16.872 0.144 17.04 0.192 ;
     RECT  17.064 0.144 17.184 0.192 ;
     RECT  17.208 0.144 17.376 0.192 ;
     RECT  17.4 0.144 17.52 0.192 ;
     RECT  17.544 0.144 17.712 0.192 ;
     RECT  17.736 0.144 17.856 0.192 ;
     RECT  17.88 0.144 18.048 0.192 ;
     RECT  18.072 0.144 18.24 0.192 ;
     RECT  18.264 0.144 18.384 0.192 ;
     RECT  18.408 0.144 18.576 0.192 ;
     RECT  18.6 0.144 18.72 0.192 ;
     RECT  18.744 0.144 18.912 0.192 ;
     RECT  18.936 0.144 19.056 0.192 ;
     RECT  19.08 0.144 19.248 0.192 ;
     RECT  19.272 0.144 19.392 0.192 ;
     RECT  19.416 0.144 19.584 0.192 ;
     RECT  19.608 0.144 19.728 0.192 ;
     RECT  19.752 0.144 19.92 0.192 ;
     RECT  19.944 0.144 20.064 0.192 ;
     RECT  20.088 0.144 20.256 0.192 ;
     RECT  20.28 0.144 20.4 0.192 ;
     RECT  20.424 0.144 20.592 0.192 ;
     RECT  20.616 0.144 20.784 0.192 ;
     RECT  20.808 0.144 20.928 0.192 ;
     RECT  20.952 0.144 21.12 0.192 ;
     RECT  21.144 0.144 21.264 0.192 ;
     RECT  21.288 0.144 21.456 0.192 ;
     RECT  21.48 0.144 21.6 0.192 ;
     RECT  21.624 0.144 21.792 0.192 ;
     RECT  21.816 0.144 21.936 0.192 ;
     RECT  21.96 0.144 22.128 0.192 ;
     RECT  22.152 0.144 22.272 0.192 ;
     RECT  22.296 0.144 22.464 0.192 ;
     RECT  22.488 0.144 22.608 0.192 ;
     RECT  22.632 0.144 22.8 0.192 ;
     RECT  22.824 0.144 22.944 0.192 ;
     RECT  22.968 0.144 23.136 0.192 ;
     RECT  23.16 0.144 23.328 0.192 ;
     RECT  23.352 0.144 23.472 0.192 ;
     RECT  23.496 0.144 23.664 0.192 ;
     RECT  23.688 0.144 23.808 0.192 ;
     RECT  23.832 0.144 24 0.192 ;
     RECT  24.024 0.144 24.144 0.192 ;
     RECT  24.168 0.144 24.336 0.192 ;
     RECT  24.36 0.144 24.48 0.192 ;
     RECT  24.504 0.144 24.672 0.192 ;
     RECT  24.696 0.144 24.816 0.192 ;
     RECT  24.84 0.144 25.008 0.192 ;
     RECT  25.032 0.144 25.152 0.192 ;
     RECT  25.176 0.144 25.344 0.192 ;
     RECT  25.368 0.144 25.488 0.192 ;
     RECT  25.512 0.144 25.68 0.192 ;
     RECT  25.704 0.144 25.872 0.192 ;
     RECT  25.896 0.144 26.016 0.192 ;
     RECT  26.04 0.144 26.208 0.192 ;
     RECT  26.232 0.144 26.352 0.192 ;
     RECT  26.376 0.144 26.544 0.192 ;
     RECT  26.568 0.144 26.688 0.192 ;
     RECT  26.712 0.144 26.88 0.192 ;
     RECT  26.904 0.144 27.024 0.192 ;
     RECT  27.048 0.144 27.216 0.192 ;
     RECT  27.24 0.144 27.36 0.192 ;
     RECT  27.384 0.144 27.552 0.192 ;
     RECT  27.576 0.144 27.696 0.192 ;
     RECT  27.72 0.144 27.888 0.192 ;
     RECT  27.912 0.144 28.032 0.192 ;
     RECT  28.056 0.144 28.224 0.192 ;
     RECT  28.248 0.144 28.416 0.192 ;
     RECT  28.44 0.144 28.56 0.192 ;
     RECT  28.584 0.144 28.752 0.192 ;
     RECT  28.776 0.144 28.896 0.192 ;
     RECT  28.92 0.144 29.088 0.192 ;
     RECT  29.112 0.144 29.232 0.192 ;
     RECT  29.256 0.144 29.424 0.192 ;
     RECT  29.448 0.144 29.568 0.192 ;
     RECT  29.592 0.144 29.76 0.192 ;
     RECT  29.784 0.144 29.904 0.192 ;
     RECT  29.928 0.144 30.096 0.192 ;
     RECT  30.12 0.144 30.24 0.192 ;
     RECT  30.264 0.144 30.432 0.192 ;
     RECT  30.456 0.144 30.576 0.192 ;
     RECT  30.6 0.144 30.768 0.192 ;
     RECT  30.792 0.144 30.96 0.192 ;
     RECT  30.984 0.144 31.104 0.192 ;
     RECT  31.128 0.144 31.296 0.192 ;
     RECT  31.32 0.144 31.44 0.192 ;
     RECT  31.464 0.144 31.632 0.192 ;
     RECT  31.656 0.144 31.776 0.192 ;
     RECT  31.8 0.144 31.968 0.192 ;
     RECT  31.992 0.144 32.112 0.192 ;
     RECT  32.136 0.144 32.304 0.192 ;
     RECT  32.328 0.144 32.448 0.192 ;
     RECT  32.472 0.144 32.64 0.192 ;
     RECT  32.664 0.144 32.784 0.192 ;
     RECT  32.808 0.144 32.976 0.192 ;
     RECT  33 0.144 33.12 0.192 ;
     RECT  33.144 0.144 33.312 0.192 ;
     RECT  33.336 0.144 33.504 0.192 ;
     RECT  33.528 0.144 33.648 0.192 ;
     RECT  33.672 0.144 33.84 0.192 ;
     RECT  33.864 0.144 33.984 0.192 ;
     RECT  34.008 0.144 34.176 0.192 ;
     RECT  34.2 0.144 34.32 0.192 ;
     RECT  34.344 0.144 34.512 0.192 ;
     RECT  34.536 0.144 34.656 0.192 ;
     RECT  34.68 0.144 34.848 0.192 ;
     RECT  34.872 0.144 34.992 0.192 ;
     RECT  35.016 0.144 35.184 0.192 ;
     RECT  35.208 0.144 35.328 0.192 ;
     RECT  35.352 0.144 35.52 0.192 ;
     RECT  35.544 0.144 35.664 0.192 ;
     RECT  35.688 0.144 35.856 0.192 ;
     RECT  35.88 0.144 36.048 0.192 ;
     RECT  36.072 0.144 36.192 0.192 ;
     RECT  36.216 0.144 36.384 0.192 ;
     RECT  36.408 0.144 36.528 0.192 ;
     RECT  36.552 0.144 36.72 0.192 ;
     RECT  36.744 0.144 36.864 0.192 ;
     RECT  36.888 0.144 37.056 0.192 ;
     RECT  37.08 0.144 37.2 0.192 ;
     RECT  37.224 0.144 37.392 0.192 ;
     RECT  37.416 0.144 37.536 0.192 ;
     RECT  37.56 0.144 37.728 0.192 ;
     RECT  37.752 0.144 37.872 0.192 ;
     RECT  37.896 0.144 38.064 0.192 ;
     RECT  38.088 0.144 38.208 0.192 ;
     RECT  38.232 0.144 38.4 0.192 ;
     RECT  38.424 0.144 38.592 0.192 ;
     RECT  38.616 0.144 38.736 0.192 ;
     RECT  38.76 0.144 38.928 0.192 ;
     RECT  38.952 0.144 39.072 0.192 ;
     RECT  39.096 0.144 39.264 0.192 ;
     RECT  39.288 0.144 39.408 0.192 ;
     RECT  39.432 0.144 39.6 0.192 ;
     RECT  39.624 0.144 39.744 0.192 ;
     RECT  39.768 0.144 39.936 0.192 ;
     RECT  39.96 0.144 40.08 0.192 ;
     RECT  40.104 0.144 40.272 0.192 ;
     RECT  40.296 0.144 40.416 0.192 ;
     RECT  40.44 0.144 40.608 0.192 ;
     RECT  40.632 0.144 40.752 0.192 ;
     RECT  40.776 0.144 40.944 0.192 ;
     RECT  40.968 0.144 41.136 0.192 ;
     RECT  41.16 0.144 41.28 0.192 ;
     RECT  41.304 0.144 41.472 0.192 ;
     RECT  41.496 0.144 41.616 0.192 ;
     RECT  41.64 0.144 41.808 0.192 ;
     RECT  41.832 0.144 41.952 0.192 ;
     RECT  41.976 0.144 42.144 0.192 ;
     RECT  42.168 0.144 42.288 0.192 ;
     RECT  42.312 0.144 42.48 0.192 ;
     RECT  42.504 0.144 42.624 0.192 ;
     RECT  42.648 0.144 42.816 0.192 ;
     RECT  42.84 0.144 42.96 0.192 ;
     RECT  42.984 0.144 43.152 0.192 ;
     RECT  43.176 0.144 43.296 0.192 ;
     RECT  43.32 0.144 43.488 0.192 ;
     RECT  43.512 0.144 43.68 0.192 ;
     RECT  43.704 0.144 43.824 0.192 ;
     RECT  43.848 0.144 44.016 0.192 ;
     RECT  44.04 0.144 44.16 0.192 ;
     RECT  44.184 0.144 44.352 0.192 ;
     RECT  44.376 0.144 44.496 0.192 ;
     RECT  44.52 0.144 44.688 0.192 ;
     RECT  44.712 0.144 44.832 0.192 ;
     RECT  44.856 0.144 45.024 0.192 ;
     RECT  45.048 0.144 45.168 0.192 ;
     RECT  45.192 0.144 45.36 0.192 ;
     RECT  45.384 0.144 45.504 0.192 ;
     RECT  45.528 0.144 45.696 0.192 ;
     RECT  45.72 0.144 45.84 0.192 ;
     RECT  45.864 0.144 46.032 0.192 ;
     RECT  46.056 0.144 46.224 0.192 ;
     RECT  46.248 0.144 46.368 0.192 ;
     RECT  46.392 0.144 46.56 0.192 ;
     RECT  46.584 0.144 46.704 0.192 ;
     RECT  46.728 0.144 46.896 0.192 ;
     RECT  46.92 0.144 47.04 0.192 ;
     RECT  47.064 0.144 47.232 0.192 ;
     RECT  47.256 0.144 47.376 0.192 ;
     RECT  47.4 0.144 47.568 0.192 ;
     RECT  47.592 0.144 47.712 0.192 ;
     RECT  47.736 0.144 47.904 0.192 ;
     RECT  47.928 0.144 48.048 0.192 ;
     RECT  48.072 0.144 48.24 0.192 ;
     RECT  48.264 0.144 48.384 0.192 ;
     RECT  48.408 0.144 48.576 0.192 ;
     RECT  48.6 0.144 48.768 0.192 ;
     RECT  48.792 0.144 48.912 0.192 ;
     RECT  48.936 0.144 49.104 0.192 ;
     RECT  49.128 0.144 49.248 0.192 ;
     RECT  49.272 0.144 49.44 0.192 ;
     RECT  49.464 0.144 49.584 0.192 ;
     RECT  49.608 0.144 49.776 0.192 ;
     RECT  49.8 0.144 49.92 0.192 ;
     RECT  49.944 0.144 50.112 0.192 ;
     RECT  50.136 0.144 50.256 0.192 ;
     RECT  50.28 0.144 50.448 0.192 ;
     RECT  50.472 0.144 50.592 0.192 ;
     RECT  50.616 0.144 50.784 0.192 ;
     RECT  50.808 0.144 50.976 0.192 ;
     RECT  51 0.144 51.12 0.192 ;
     RECT  51.144 0.144 51.312 0.192 ;
     RECT  51.336 0.144 51.456 0.192 ;
     RECT  51.48 0.144 51.648 0.192 ;
     RECT  51.672 0.144 51.792 0.192 ;
     RECT  51.816 0.144 51.984 0.192 ;
     RECT  52.008 0.144 52.128 0.192 ;
     RECT  52.152 0.144 52.32 0.192 ;
     RECT  52.344 0.144 52.464 0.192 ;
     RECT  52.488 0.144 52.656 0.192 ;
     RECT  52.68 0.144 52.8 0.192 ;
     RECT  52.824 0.144 52.992 0.192 ;
     RECT  53.016 0.144 53.136 0.192 ;
     RECT  53.16 0.144 53.328 0.192 ;
     RECT  53.352 0.144 53.52 0.192 ;
     RECT  53.544 0.144 53.664 0.192 ;
     RECT  53.688 0.144 53.856 0.192 ;
     RECT  53.88 0.144 54 0.192 ;
     RECT  54.024 0.144 54.192 0.192 ;
     RECT  54.216 0.144 54.336 0.192 ;
     RECT  54.36 0.144 54.528 0.192 ;
     RECT  54.552 0.144 54.672 0.192 ;
     RECT  54.696 0.144 54.864 0.192 ;
     RECT  54.888 0.144 55.008 0.192 ;
     RECT  55.032 0.144 55.2 0.192 ;
     RECT  55.224 0.144 55.344 0.192 ;
     RECT  55.368 0.144 55.536 0.192 ;
     RECT  55.56 0.144 55.68 0.192 ;
     RECT  55.704 0.144 55.872 0.192 ;
     RECT  55.896 0.144 56.064 0.192 ;
     RECT  56.088 0.144 56.208 0.192 ;
     RECT  56.232 0.144 56.4 0.192 ;
     RECT  56.424 0.144 56.544 0.192 ;
     RECT  56.568 0.144 56.736 0.192 ;
     RECT  56.76 0.144 56.88 0.192 ;
     RECT  56.904 0.144 57.072 0.192 ;
     RECT  57.096 0.144 57.216 0.192 ;
     RECT  57.24 0.144 57.408 0.192 ;
     RECT  57.432 0.144 57.552 0.192 ;
     RECT  57.576 0.144 57.744 0.192 ;
     RECT  57.768 0.144 57.888 0.192 ;
     RECT  57.912 0.144 58.08 0.192 ;
     RECT  58.104 0.144 58.224 0.192 ;
     RECT  58.248 0.144 58.416 0.192 ;
     RECT  58.44 0.144 58.608 0.192 ;
     RECT  58.632 0.144 58.752 0.192 ;
     RECT  58.776 0.144 58.944 0.192 ;
     RECT  58.968 0.144 59.088 0.192 ;
     RECT  59.112 0.144 59.28 0.192 ;
     RECT  59.304 0.144 59.424 0.192 ;
     RECT  59.448 0.144 59.616 0.192 ;
     RECT  59.64 0.144 59.76 0.192 ;
     RECT  59.784 0.144 59.952 0.192 ;
     RECT  59.976 0.144 60.096 0.192 ;
     RECT  60.12 0.144 60.288 0.192 ;
     RECT  60.312 0.144 60.432 0.192 ;
     RECT  60.456 0.144 60.624 0.192 ;
     RECT  60.648 0.144 60.768 0.192 ;
     RECT  60.792 0.144 60.96 0.192 ;
     RECT  60.984 0.144 61.152 0.192 ;
     RECT  61.176 0.144 61.296 0.192 ;
     RECT  61.32 0.144 61.488 0.192 ;
     RECT  61.512 0.144 61.632 0.192 ;
     RECT  61.656 0.144 61.824 0.192 ;
     RECT  61.848 0.144 61.968 0.192 ;
     RECT  61.992 0.144 62.16 0.192 ;
     RECT  62.184 0.144 62.304 0.192 ;
     RECT  62.328 0.144 62.496 0.192 ;
     RECT  62.52 0.144 62.64 0.192 ;
     RECT  62.664 0.144 62.832 0.192 ;
     RECT  62.856 0.144 62.976 0.192 ;
     RECT  63 0.144 63.168 0.192 ;
     RECT  63.192 0.144 63.312 0.192 ;
     RECT  63.336 0.144 63.504 0.192 ;
     RECT  63.528 0.144 63.696 0.192 ;
     RECT  63.72 0.144 63.84 0.192 ;
     RECT  63.864 0.144 64.032 0.192 ;
     RECT  64.056 0.144 64.176 0.192 ;
     RECT  64.2 0.144 64.368 0.192 ;
     RECT  64.392 0.144 64.512 0.192 ;
     RECT  64.536 0.144 64.704 0.192 ;
     RECT  64.728 0.144 64.848 0.192 ;
     RECT  64.872 0.144 65.04 0.192 ;
     RECT  65.064 0.144 65.184 0.192 ;
     RECT  65.208 0.144 65.376 0.192 ;
     RECT  65.4 0.144 65.52 0.192 ;
     RECT  65.544 0.144 65.712 0.192 ;
     RECT  65.736 0.144 65.856 0.192 ;
     RECT  65.88 0.144 66.048 0.192 ;
     RECT  66.072 0.144 66.24 0.192 ;
     RECT  66.264 0.144 66.384 0.192 ;
     RECT  66.408 0.144 66.576 0.192 ;
     RECT  66.6 0.144 66.72 0.192 ;
     RECT  66.744 0.144 66.912 0.192 ;
     RECT  66.936 0.144 67.056 0.192 ;
     RECT  67.08 0.144 67.248 0.192 ;
     RECT  67.272 0.144 67.392 0.192 ;
     RECT  67.416 0.144 67.584 0.192 ;
     RECT  67.608 0.144 67.728 0.192 ;
     RECT  67.752 0.144 67.92 0.192 ;
     RECT  67.944 0.144 68.064 0.192 ;
     RECT  68.088 0.144 68.256 0.192 ;
     RECT  68.28 0.144 68.4 0.192 ;
     RECT  68.424 0.144 68.592 0.192 ;
     RECT  68.616 0.144 68.784 0.192 ;
     RECT  68.808 0.144 68.928 0.192 ;
     RECT  68.952 0.144 69.12 0.192 ;
     RECT  69.144 0.144 69.264 0.192 ;
     RECT  69.288 0.144 69.456 0.192 ;
     RECT  69.48 0.144 69.6 0.192 ;
     RECT  69.624 0.144 69.792 0.192 ;
     RECT  69.816 0.144 69.936 0.192 ;
     RECT  69.96 0.144 70.128 0.192 ;
     RECT  70.152 0.144 70.272 0.192 ;
     RECT  70.296 0.144 70.464 0.192 ;
     RECT  70.488 0.144 70.608 0.192 ;
     RECT  70.632 0.144 70.8 0.192 ;
     RECT  70.824 0.144 70.944 0.192 ;
     RECT  70.968 0.144 71.136 0.192 ;
     RECT  71.16 0.144 71.328 0.192 ;
     RECT  71.352 0.144 71.472 0.192 ;
     RECT  71.496 0.144 71.664 0.192 ;
     RECT  71.688 0.144 71.808 0.192 ;
     RECT  71.832 0.144 72 0.192 ;
     RECT  72.024 0.144 72.144 0.192 ;
     RECT  72.168 0.144 72.336 0.192 ;
     RECT  72.36 0.144 72.48 0.192 ;
     RECT  72.504 0.144 72.672 0.192 ;
     RECT  72.696 0.144 72.816 0.192 ;
     RECT  72.84 0.144 73.008 0.192 ;
     RECT  73.032 0.144 73.152 0.192 ;
     RECT  73.176 0.144 73.344 0.192 ;
     RECT  73.368 0.144 73.488 0.192 ;
     RECT  73.512 0.144 73.68 0.192 ;
     RECT  73.704 0.144 73.872 0.192 ;
     RECT  73.896 0.144 74.016 0.192 ;
     RECT  74.04 0.144 74.208 0.192 ;
     RECT  74.232 0.144 74.352 0.192 ;
     RECT  74.376 0.144 74.544 0.192 ;
     RECT  74.568 0.144 74.688 0.192 ;
     RECT  74.712 0.144 74.88 0.192 ;
     RECT  74.904 0.144 75.024 0.192 ;
     RECT  75.048 0.144 75.216 0.192 ;
     RECT  75.24 0.144 75.36 0.192 ;
     RECT  75.384 0.144 75.552 0.192 ;
     RECT  75.576 0.144 75.696 0.192 ;
     RECT  75.72 0.144 75.888 0.192 ;
     RECT  75.912 0.144 76.032 0.192 ;
     RECT  76.056 0.144 76.224 0.192 ;
     RECT  76.248 0.144 76.416 0.192 ;
     RECT  76.44 0.144 76.56 0.192 ;
     RECT  76.584 0.144 76.752 0.192 ;
     RECT  76.776 0.144 76.896 0.192 ;
     RECT  76.92 0.144 77.088 0.192 ;
     RECT  77.112 0.144 77.232 0.192 ;
     RECT  77.256 0.144 77.424 0.192 ;
     RECT  77.448 0.144 77.568 0.192 ;
     RECT  77.592 0.144 77.76 0.192 ;
     RECT  77.784 0.144 77.904 0.192 ;
     RECT  77.928 0.144 78.096 0.192 ;
     RECT  78.12 0.144 78.24 0.192 ;
     RECT  78.264 0.144 78.432 0.192 ;
     RECT  78.456 0.144 78.576 0.192 ;
     RECT  78.6 0.144 78.768 0.192 ;
     RECT  78.792 0.144 78.96 0.192 ;
     RECT  78.984 0.144 79.104 0.192 ;
     RECT  79.128 0.144 79.296 0.192 ;
     RECT  79.32 0.144 79.44 0.192 ;
     RECT  79.464 0.144 79.632 0.192 ;
     RECT  79.656 0.144 79.776 0.192 ;
     RECT  79.8 0.144 79.968 0.192 ;
     RECT  79.992 0.144 80.112 0.192 ;
     RECT  80.136 0.144 80.304 0.192 ;
     RECT  80.328 0.144 80.448 0.192 ;
     RECT  80.472 0.144 80.64 0.192 ;
     RECT  80.664 0.144 80.784 0.192 ;
     RECT  80.808 0.144 80.976 0.192 ;
     RECT  81 0.144 81.12 0.192 ;
     RECT  81.144 0.144 81.312 0.192 ;
     RECT  81.336 0.144 81.504 0.192 ;
     RECT  81.528 0.144 81.648 0.192 ;
     RECT  81.672 0.144 81.84 0.192 ;
     RECT  81.864 0.144 81.984 0.192 ;
     RECT  82.008 0.144 82.176 0.192 ;
     RECT  82.2 0.144 82.32 0.192 ;
     RECT  82.344 0.144 82.512 0.192 ;
     RECT  82.536 0.144 82.656 0.192 ;
     RECT  82.68 0.144 82.848 0.192 ;
     RECT  82.872 0.144 82.992 0.192 ;
     RECT  83.016 0.144 83.184 0.192 ;
     RECT  83.208 0.144 83.328 0.192 ;
     RECT  83.352 0.144 83.52 0.192 ;
     RECT  83.544 0.144 83.664 0.192 ;
     RECT  83.688 0.144 83.856 0.192 ;
     RECT  83.88 0.144 84.048 0.192 ;
     RECT  84.072 0.144 84.192 0.192 ;
     RECT  84.216 0.144 84.384 0.192 ;
     RECT  84.408 0.144 84.528 0.192 ;
     RECT  84.552 0.144 84.72 0.192 ;
     RECT  84.744 0.144 84.864 0.192 ;
     RECT  84.888 0.144 85.056 0.192 ;
     RECT  85.08 0.144 85.2 0.192 ;
     RECT  85.224 0.144 85.392 0.192 ;
     RECT  85.416 0.144 85.536 0.192 ;
     RECT  85.56 0.144 85.728 0.192 ;
     RECT  85.752 0.144 85.872 0.192 ;
     RECT  85.896 0.144 86.064 0.192 ;
     RECT  86.088 0.144 86.256 0.192 ;
     RECT  86.28 0.144 86.4 0.192 ;
     RECT  86.424 0.144 86.592 0.192 ;
     RECT  86.616 0.144 86.736 0.192 ;
     RECT  86.76 0.144 86.928 0.192 ;
     RECT  86.952 0.144 87.072 0.192 ;
     RECT  87.096 0.144 87.264 0.192 ;
     RECT  87.288 0.144 87.408 0.192 ;
     RECT  87.432 0.144 87.6 0.192 ;
     RECT  87.624 0.144 87.744 0.192 ;
     RECT  87.768 0.144 87.936 0.192 ;
     RECT  87.96 0.144 88.08 0.192 ;
     RECT  88.104 0.144 88.272 0.192 ;
     RECT  88.296 0.144 88.416 0.192 ;
     RECT  88.44 0.144 88.608 0.192 ;
     RECT  88.632 0.144 88.8 0.192 ;
     RECT  88.824 0.144 88.944 0.192 ;
     RECT  88.968 0.144 89.136 0.192 ;
     RECT  89.16 0.144 89.28 0.192 ;
     RECT  89.304 0.144 89.472 0.192 ;
     RECT  89.496 0.144 89.616 0.192 ;
     RECT  89.64 0.144 89.808 0.192 ;
     RECT  89.832 0.144 89.952 0.192 ;
     RECT  89.976 0.144 90.144 0.192 ;
     RECT  90.168 0.144 90.288 0.192 ;
     RECT  90.312 0.144 90.48 0.192 ;
     RECT  90.504 0.144 90.624 0.192 ;
     RECT  90.648 0.144 90.816 0.192 ;
     RECT  90.84 0.144 90.96 0.192 ;
     RECT  90.984 0.144 91.152 0.192 ;
     RECT  91.176 0.144 91.344 0.192 ;
     RECT  91.368 0.144 91.488 0.192 ;
     RECT  91.512 0.144 91.68 0.192 ;
     RECT  91.704 0.144 91.824 0.192 ;
     RECT  91.848 0.144 92.016 0.192 ;
     RECT  92.04 0.144 92.16 0.192 ;
     RECT  92.184 0.144 92.352 0.192 ;
     RECT  92.376 0.144 92.496 0.192 ;
     RECT  92.52 0.144 92.688 0.192 ;
     RECT  92.712 0.144 92.832 0.192 ;
     RECT  92.856 0.144 93.024 0.192 ;
     RECT  93.048 0.144 93.168 0.192 ;
     RECT  93.192 0.144 93.36 0.192 ;
     RECT  93.384 0.144 93.504 0.192 ;
     RECT  93.528 0.144 93.696 0.192 ;
     RECT  93.72 0.144 93.888 0.192 ;
     RECT  93.912 0.144 94.032 0.192 ;
     RECT  94.056 0.144 94.224 0.192 ;
     RECT  94.248 0.144 94.368 0.192 ;
     RECT  94.392 0.144 94.56 0.192 ;
     RECT  94.584 0.144 94.704 0.192 ;
     RECT  94.728 0.144 94.896 0.192 ;
     RECT  94.92 0.144 95.04 0.192 ;
     RECT  95.064 0.144 95.232 0.192 ;
     RECT  95.256 0.144 95.376 0.192 ;
     RECT  95.4 0.144 95.568 0.192 ;
     RECT  95.592 0.144 95.712 0.192 ;
     RECT  95.736 0.144 95.904 0.192 ;
     RECT  95.928 0.144 96.048 0.192 ;
     RECT  96.072 0.144 96.24 0.192 ;
     RECT  96.264 0.144 96.432 0.192 ;
     RECT  96.456 0.144 96.576 0.192 ;
     RECT  96.6 0.144 96.768 0.192 ;
     RECT  96.792 0.144 96.912 0.192 ;
     RECT  96.936 0.144 97.104 0.192 ;
     RECT  97.128 0.144 97.248 0.192 ;
     RECT  97.272 0.144 97.44 0.192 ;
     RECT  97.464 0.144 97.584 0.192 ;
     RECT  97.608 0.144 97.776 0.192 ;
     RECT  97.8 0.144 97.92 0.192 ;
     RECT  97.944 0.144 98.112 0.192 ;
     RECT  98.136 0.144 98.256 0.192 ;
     RECT  98.28 0.144 98.448 0.192 ;
     RECT  98.472 0.144 98.592 0.192 ;
     RECT  98.616 0.144 98.784 0.192 ;
     RECT  98.808 0.144 98.976 0.192 ;
     RECT  99 0.144 99.12 0.192 ;
     RECT  99.144 0.144 99.312 0.192 ;
     RECT  99.336 0.144 99.456 0.192 ;
     RECT  99.48 0.144 99.648 0.192 ;
     RECT  99.672 0.144 99.792 0.192 ;
     RECT  99.816 0.144 99.984 0.192 ;
     RECT  100.008 0.144 100.128 0.192 ;
     RECT  100.152 0.144 100.32 0.192 ;
     RECT  100.344 0.144 100.464 0.192 ;
     RECT  100.488 0.144 100.656 0.192 ;
     RECT  100.68 0.144 100.8 0.192 ;
     RECT  100.824 0.144 100.992 0.192 ;
     RECT  101.016 0.144 101.136 0.192 ;
     RECT  101.16 0.144 101.328 0.192 ;
     RECT  101.352 0.144 101.52 0.192 ;
     RECT  101.544 0.144 101.664 0.192 ;
     RECT  101.688 0.144 101.856 0.192 ;
     RECT  101.88 0.144 102 0.192 ;
     RECT  102.024 0.144 102.192 0.192 ;
     RECT  102.216 0.144 102.336 0.192 ;
     RECT  102.36 0.144 102.528 0.192 ;
     RECT  102.552 0.144 102.672 0.192 ;
     RECT  102.696 0.144 102.864 0.192 ;
     RECT  102.888 0.144 103.008 0.192 ;
     RECT  103.032 0.144 103.2 0.192 ;
     RECT  103.224 0.144 103.344 0.192 ;
     RECT  103.368 0.144 103.536 0.192 ;
     RECT  103.56 0.144 103.68 0.192 ;
     RECT  103.704 0.144 103.872 0.192 ;
     RECT  103.896 0.144 104.064 0.192 ;
     RECT  104.088 0.144 104.208 0.192 ;
     RECT  104.232 0.144 104.4 0.192 ;
     RECT  104.424 0.144 104.544 0.192 ;
     RECT  104.568 0.144 104.736 0.192 ;
     RECT  104.76 0.144 104.88 0.192 ;
     RECT  104.904 0.144 105.072 0.192 ;
     RECT  105.096 0.144 105.216 0.192 ;
     RECT  105.24 0.144 105.408 0.192 ;
     RECT  105.432 0.144 105.552 0.192 ;
     RECT  105.576 0.144 105.744 0.192 ;
     RECT  105.768 0.144 105.888 0.192 ;
     RECT  105.912 0.144 106.08 0.192 ;
     RECT  106.104 0.144 106.224 0.192 ;
     RECT  106.248 0.144 106.416 0.192 ;
     RECT  106.44 0.144 106.608 0.192 ;
     RECT  106.632 0.144 106.752 0.192 ;
     RECT  106.776 0.144 106.944 0.192 ;
     RECT  106.968 0.144 107.088 0.192 ;
     RECT  107.112 0.144 107.28 0.192 ;
     RECT  107.304 0.144 107.424 0.192 ;
     RECT  107.448 0.144 107.616 0.192 ;
     RECT  107.64 0.144 107.76 0.192 ;
     RECT  107.784 0.144 107.952 0.192 ;
     RECT  107.976 0.144 108.096 0.192 ;
     RECT  108.12 0.144 108.288 0.192 ;
     RECT  108.312 0.144 108.432 0.192 ;
     RECT  108.456 0.144 108.624 0.192 ;
     RECT  108.648 0.144 108.768 0.192 ;
     RECT  108.792 0.144 108.96 0.192 ;
     RECT  108.984 0.144 109.152 0.192 ;
     RECT  109.176 0.144 109.296 0.192 ;
     RECT  109.32 0.144 109.488 0.192 ;
     RECT  109.512 0.144 109.632 0.192 ;
     RECT  109.656 0.144 109.824 0.192 ;
     RECT  109.848 0.144 109.968 0.192 ;
     RECT  109.992 0.144 110.16 0.192 ;
     RECT  4.32 0.192 110.184 1.763 ;
     RECT  4.464 1.763 13.512 1.811 ;
     RECT  14.496 1.763 110.184 1.811 ;
     RECT  14.496 1.811 84.408 1.859 ;
     RECT  85.392 1.811 110.184 2.137 ;
     RECT  2.4 2.137 2.52 2.151 ;
     RECT  85.392 2.137 110.52 2.151 ;
     RECT  15.9 1.859 84.408 2.339 ;
     RECT  4.992 1.811 13.512 2.867 ;
     RECT  14.496 1.859 14.52 2.869 ;
     RECT  15.9 2.339 84.36 2.869 ;
     RECT  85.392 2.151 110.712 2.915 ;
     RECT  5.1 2.867 13.512 3.205 ;
     RECT  14.496 2.869 84.36 3.205 ;
     RECT  5.1 3.205 84.36 3.925 ;
     RECT  85.392 2.915 109.368 3.925 ;
     RECT  2.4 2.151 2.712 4.501 ;
     RECT  5.1 3.925 109.416 4.501 ;
     RECT  110.4 2.915 110.712 4.501 ;
     RECT  5.1 4.501 110.712 4.595 ;
     RECT  12.192 4.595 110.712 5.219 ;
     RECT  83.232 5.219 110.712 5.267 ;
     RECT  5.1 4.595 11.016 5.605 ;
     RECT  12.192 5.219 82.152 5.605 ;
     RECT  5.1 5.605 82.152 5.699 ;
     RECT  5.1 5.699 5.544 5.747 ;
     RECT  6.672 5.699 82.152 5.747 ;
     RECT  83.28 5.267 110.712 5.795 ;
     RECT  2.4 4.501 3.528 6.181 ;
     RECT  2.4 6.181 3.624 6.229 ;
     RECT  5.1 5.747 5.412 6.229 ;
     RECT  15.264 5.747 82.152 6.229 ;
     RECT  83.28 5.795 105.576 6.275 ;
     RECT  15.264 6.229 82.2 6.323 ;
     RECT  106.56 5.795 110.712 6.371 ;
     RECT  50.064 6.323 82.2 6.565 ;
     RECT  83.28 6.275 105.528 6.565 ;
     RECT  2.4 6.229 5.412 6.707 ;
     RECT  7.152 5.747 14.232 6.899 ;
     RECT  15.264 6.323 48.984 6.899 ;
     RECT  106.56 6.371 108.984 6.899 ;
     RECT  106.848 6.899 108.984 7.043 ;
     RECT  21.072 6.899 48.984 7.139 ;
     RECT  21.12 7.139 48.984 7.187 ;
     RECT  22.8 7.187 48.984 7.285 ;
     RECT  50.064 6.565 105.528 7.285 ;
     RECT  7.392 6.899 14.232 7.381 ;
     RECT  15.264 6.899 19.896 7.381 ;
     RECT  22.8 7.285 105.528 7.475 ;
     RECT  106.944 7.043 108.984 7.765 ;
     RECT  110.112 6.371 110.712 7.765 ;
     RECT  22.8 7.475 35.4 7.955 ;
     RECT  36.384 7.475 105.528 7.955 ;
     RECT  7.392 7.381 19.896 8.293 ;
     RECT  21.12 7.187 21.72 8.437 ;
     RECT  22.8 7.955 35.304 8.437 ;
     RECT  7.008 8.293 19.896 8.485 ;
     RECT  21.12 8.437 35.304 8.485 ;
     RECT  36.384 7.955 105.432 8.771 ;
     RECT  4.464 6.707 5.412 8.869 ;
     RECT  7.008 8.485 35.304 8.869 ;
     RECT  36.384 8.771 105.312 8.917 ;
     RECT  4.32 8.869 35.304 8.965 ;
     RECT  36.336 8.917 105.312 8.965 ;
     RECT  106.944 7.765 110.712 9.013 ;
     RECT  4.32 8.965 105.312 9.107 ;
     RECT  106.464 9.013 110.712 9.109 ;
     RECT  93.168 9.107 105.312 9.395 ;
     RECT  93.408 9.395 105.312 9.731 ;
     RECT  4.32 9.107 92.088 10.307 ;
     RECT  93.504 9.731 105.312 10.403 ;
     RECT  93.504 10.403 103.224 10.693 ;
     RECT  66.384 10.307 91.812 10.883 ;
     RECT  4.32 10.307 64.968 11.317 ;
     RECT  93.024 10.693 103.224 11.365 ;
     RECT  104.208 10.403 105.312 11.365 ;
     RECT  106.368 9.109 110.712 11.365 ;
     RECT  66.384 10.883 87.288 11.411 ;
     RECT  4.32 11.317 65.4 11.459 ;
     RECT  66.384 11.411 87.096 11.459 ;
     RECT  4.32 11.459 37.944 11.507 ;
     RECT  88.704 10.883 91.812 11.941 ;
     RECT  93.024 11.365 110.712 12.035 ;
     RECT  4.32 11.507 9.096 13.045 ;
     RECT  10.08 11.507 37.944 13.045 ;
     RECT  66.384 11.459 86.76 13.045 ;
     RECT  66.384 13.045 87.096 13.621 ;
     RECT  88.272 11.941 91.812 13.621 ;
     RECT  66.384 13.621 91.812 14.005 ;
     RECT  93.024 12.035 99.912 15.349 ;
     RECT  100.992 12.035 110.712 15.349 ;
     RECT  2.4 6.707 2.712 19.449 ;
     RECT  93.024 15.349 110.712 19.449 ;
     RECT  2.4 19.449 2.52 19.463 ;
     RECT  66.384 14.005 91.944 19.463 ;
     RECT  93.024 19.449 110.52 19.463 ;
     RECT  4.32 13.045 37.944 19.571 ;
     RECT  84.384 19.463 91.944 19.571 ;
     RECT  4.32 19.571 37.752 20.533 ;
     RECT  39.072 11.459 65.4 20.533 ;
     RECT  66.384 19.463 83.352 20.533 ;
     RECT  84.384 19.571 91.848 20.533 ;
     RECT  93.024 19.463 99.672 20.533 ;
     RECT  100.656 19.463 110.184 20.533 ;
     RECT  4.32 20.533 110.184 21.408 ;
     RECT  4.344 21.408 4.464 21.456 ;
     RECT  4.488 21.408 4.656 21.456 ;
     RECT  4.68 21.408 4.8 21.456 ;
     RECT  4.824 21.408 4.992 21.456 ;
     RECT  5.016 21.408 5.136 21.456 ;
     RECT  5.16 21.408 5.328 21.456 ;
     RECT  5.352 21.408 5.472 21.456 ;
     RECT  5.496 21.408 5.664 21.456 ;
     RECT  5.688 21.408 5.856 21.456 ;
     RECT  5.88 21.408 6 21.456 ;
     RECT  6.024 21.408 6.192 21.456 ;
     RECT  6.216 21.408 6.336 21.456 ;
     RECT  6.36 21.408 6.528 21.456 ;
     RECT  6.552 21.408 6.672 21.456 ;
     RECT  6.696 21.408 6.864 21.456 ;
     RECT  6.888 21.408 7.008 21.456 ;
     RECT  7.032 21.408 7.2 21.456 ;
     RECT  7.224 21.408 7.344 21.456 ;
     RECT  7.368 21.408 7.536 21.456 ;
     RECT  7.56 21.408 7.68 21.456 ;
     RECT  7.704 21.408 7.872 21.456 ;
     RECT  7.896 21.408 8.016 21.456 ;
     RECT  8.04 21.408 8.208 21.456 ;
     RECT  8.232 21.408 8.4 21.456 ;
     RECT  8.424 21.408 8.544 21.456 ;
     RECT  8.568 21.408 8.736 21.456 ;
     RECT  8.76 21.408 8.88 21.456 ;
     RECT  8.904 21.408 9.072 21.456 ;
     RECT  9.096 21.408 9.216 21.456 ;
     RECT  9.24 21.408 9.408 21.456 ;
     RECT  9.432 21.408 9.552 21.456 ;
     RECT  9.576 21.408 9.744 21.456 ;
     RECT  9.768 21.408 9.888 21.456 ;
     RECT  9.912 21.408 10.08 21.456 ;
     RECT  10.104 21.408 10.224 21.456 ;
     RECT  10.248 21.408 10.416 21.456 ;
     RECT  10.44 21.408 10.56 21.456 ;
     RECT  10.584 21.408 10.752 21.456 ;
     RECT  10.776 21.408 10.944 21.456 ;
     RECT  10.968 21.408 11.088 21.456 ;
     RECT  11.112 21.408 11.28 21.456 ;
     RECT  11.304 21.408 11.424 21.456 ;
     RECT  11.448 21.408 11.616 21.456 ;
     RECT  11.64 21.408 11.76 21.456 ;
     RECT  11.784 21.408 11.952 21.456 ;
     RECT  11.976 21.408 12.096 21.456 ;
     RECT  12.12 21.408 12.288 21.456 ;
     RECT  12.312 21.408 12.432 21.456 ;
     RECT  12.456 21.408 12.624 21.456 ;
     RECT  12.648 21.408 12.768 21.456 ;
     RECT  12.792 21.408 12.96 21.456 ;
     RECT  12.984 21.408 13.152 21.456 ;
     RECT  13.176 21.408 13.296 21.456 ;
     RECT  13.32 21.408 13.488 21.456 ;
     RECT  13.512 21.408 13.632 21.456 ;
     RECT  13.656 21.408 13.824 21.456 ;
     RECT  13.848 21.408 13.968 21.456 ;
     RECT  13.992 21.408 14.16 21.456 ;
     RECT  14.184 21.408 14.304 21.456 ;
     RECT  14.328 21.408 14.496 21.456 ;
     RECT  14.52 21.408 14.64 21.456 ;
     RECT  14.664 21.408 14.832 21.456 ;
     RECT  14.856 21.408 14.976 21.456 ;
     RECT  15 21.408 15.168 21.456 ;
     RECT  15.192 21.408 15.312 21.456 ;
     RECT  15.336 21.408 15.504 21.456 ;
     RECT  15.528 21.408 15.696 21.456 ;
     RECT  15.72 21.408 15.84 21.456 ;
     RECT  15.864 21.408 16.032 21.456 ;
     RECT  16.056 21.408 16.176 21.456 ;
     RECT  16.2 21.408 16.368 21.456 ;
     RECT  16.392 21.408 16.512 21.456 ;
     RECT  16.536 21.408 16.704 21.456 ;
     RECT  16.728 21.408 16.848 21.456 ;
     RECT  16.872 21.408 17.04 21.456 ;
     RECT  17.064 21.408 17.184 21.456 ;
     RECT  17.208 21.408 17.376 21.456 ;
     RECT  17.4 21.408 17.52 21.456 ;
     RECT  17.544 21.408 17.712 21.456 ;
     RECT  17.736 21.408 17.856 21.456 ;
     RECT  17.88 21.408 18.048 21.456 ;
     RECT  18.072 21.408 18.24 21.456 ;
     RECT  18.264 21.408 18.384 21.456 ;
     RECT  18.408 21.408 18.576 21.456 ;
     RECT  18.6 21.408 18.72 21.456 ;
     RECT  18.744 21.408 18.912 21.456 ;
     RECT  18.936 21.408 19.056 21.456 ;
     RECT  19.08 21.408 19.248 21.456 ;
     RECT  19.272 21.408 19.392 21.456 ;
     RECT  19.416 21.408 19.584 21.456 ;
     RECT  19.608 21.408 19.728 21.456 ;
     RECT  19.752 21.408 19.92 21.456 ;
     RECT  19.944 21.408 20.064 21.456 ;
     RECT  20.088 21.408 20.256 21.456 ;
     RECT  20.28 21.408 20.4 21.456 ;
     RECT  20.424 21.408 20.592 21.456 ;
     RECT  20.616 21.408 20.784 21.456 ;
     RECT  20.808 21.408 20.928 21.456 ;
     RECT  20.952 21.408 21.12 21.456 ;
     RECT  21.144 21.408 21.264 21.456 ;
     RECT  21.288 21.408 21.456 21.456 ;
     RECT  21.48 21.408 21.6 21.456 ;
     RECT  21.624 21.408 21.792 21.456 ;
     RECT  21.816 21.408 21.936 21.456 ;
     RECT  21.96 21.408 22.128 21.456 ;
     RECT  22.152 21.408 22.272 21.456 ;
     RECT  22.296 21.408 22.464 21.456 ;
     RECT  22.488 21.408 22.608 21.456 ;
     RECT  22.632 21.408 22.8 21.456 ;
     RECT  22.824 21.408 22.944 21.456 ;
     RECT  22.968 21.408 23.136 21.456 ;
     RECT  23.16 21.408 23.328 21.456 ;
     RECT  23.352 21.408 23.472 21.456 ;
     RECT  23.496 21.408 23.664 21.456 ;
     RECT  23.688 21.408 23.808 21.456 ;
     RECT  23.832 21.408 24 21.456 ;
     RECT  24.024 21.408 24.144 21.456 ;
     RECT  24.168 21.408 24.336 21.456 ;
     RECT  24.36 21.408 24.48 21.456 ;
     RECT  24.504 21.408 24.672 21.456 ;
     RECT  24.696 21.408 24.816 21.456 ;
     RECT  24.84 21.408 25.008 21.456 ;
     RECT  25.032 21.408 25.152 21.456 ;
     RECT  25.176 21.408 25.344 21.456 ;
     RECT  25.368 21.408 25.488 21.456 ;
     RECT  25.512 21.408 25.68 21.456 ;
     RECT  25.704 21.408 25.872 21.456 ;
     RECT  25.896 21.408 26.016 21.456 ;
     RECT  26.04 21.408 26.208 21.456 ;
     RECT  26.232 21.408 26.352 21.456 ;
     RECT  26.376 21.408 26.544 21.456 ;
     RECT  26.568 21.408 26.688 21.456 ;
     RECT  26.712 21.408 26.88 21.456 ;
     RECT  26.904 21.408 27.024 21.456 ;
     RECT  27.048 21.408 27.216 21.456 ;
     RECT  27.24 21.408 27.36 21.456 ;
     RECT  27.384 21.408 27.552 21.456 ;
     RECT  27.576 21.408 27.696 21.456 ;
     RECT  27.72 21.408 27.888 21.456 ;
     RECT  27.912 21.408 28.032 21.456 ;
     RECT  28.056 21.408 28.224 21.456 ;
     RECT  28.248 21.408 28.416 21.456 ;
     RECT  28.44 21.408 28.56 21.456 ;
     RECT  28.584 21.408 28.752 21.456 ;
     RECT  28.776 21.408 28.896 21.456 ;
     RECT  28.92 21.408 29.088 21.456 ;
     RECT  29.112 21.408 29.232 21.456 ;
     RECT  29.256 21.408 29.424 21.456 ;
     RECT  29.448 21.408 29.568 21.456 ;
     RECT  29.592 21.408 29.76 21.456 ;
     RECT  29.784 21.408 29.904 21.456 ;
     RECT  29.928 21.408 30.096 21.456 ;
     RECT  30.12 21.408 30.24 21.456 ;
     RECT  30.264 21.408 30.432 21.456 ;
     RECT  30.456 21.408 30.576 21.456 ;
     RECT  30.6 21.408 30.768 21.456 ;
     RECT  30.792 21.408 30.96 21.456 ;
     RECT  30.984 21.408 31.104 21.456 ;
     RECT  31.128 21.408 31.296 21.456 ;
     RECT  31.32 21.408 31.44 21.456 ;
     RECT  31.464 21.408 31.632 21.456 ;
     RECT  31.656 21.408 31.776 21.456 ;
     RECT  31.8 21.408 31.968 21.456 ;
     RECT  31.992 21.408 32.112 21.456 ;
     RECT  32.136 21.408 32.304 21.456 ;
     RECT  32.328 21.408 32.448 21.456 ;
     RECT  32.472 21.408 32.64 21.456 ;
     RECT  32.664 21.408 32.784 21.456 ;
     RECT  32.808 21.408 32.976 21.456 ;
     RECT  33 21.408 33.12 21.456 ;
     RECT  33.144 21.408 33.312 21.456 ;
     RECT  33.336 21.408 33.504 21.456 ;
     RECT  33.528 21.408 33.648 21.456 ;
     RECT  33.672 21.408 33.84 21.456 ;
     RECT  33.864 21.408 33.984 21.456 ;
     RECT  34.008 21.408 34.176 21.456 ;
     RECT  34.2 21.408 34.32 21.456 ;
     RECT  34.344 21.408 34.512 21.456 ;
     RECT  34.536 21.408 34.656 21.456 ;
     RECT  34.68 21.408 34.848 21.456 ;
     RECT  34.872 21.408 34.992 21.456 ;
     RECT  35.016 21.408 35.184 21.456 ;
     RECT  35.208 21.408 35.328 21.456 ;
     RECT  35.352 21.408 35.52 21.456 ;
     RECT  35.544 21.408 35.664 21.456 ;
     RECT  35.688 21.408 35.856 21.456 ;
     RECT  35.88 21.408 36.048 21.456 ;
     RECT  36.072 21.408 36.192 21.456 ;
     RECT  36.216 21.408 36.384 21.456 ;
     RECT  36.408 21.408 36.528 21.456 ;
     RECT  36.552 21.408 36.72 21.456 ;
     RECT  36.744 21.408 36.864 21.456 ;
     RECT  36.888 21.408 37.056 21.456 ;
     RECT  37.08 21.408 37.2 21.456 ;
     RECT  37.224 21.408 37.392 21.456 ;
     RECT  37.416 21.408 37.536 21.456 ;
     RECT  37.56 21.408 37.728 21.456 ;
     RECT  37.752 21.408 37.872 21.456 ;
     RECT  37.896 21.408 38.064 21.456 ;
     RECT  38.088 21.408 38.208 21.456 ;
     RECT  38.232 21.408 38.4 21.456 ;
     RECT  38.424 21.408 38.592 21.456 ;
     RECT  38.616 21.408 38.736 21.456 ;
     RECT  38.76 21.408 38.928 21.456 ;
     RECT  38.952 21.408 39.072 21.456 ;
     RECT  39.096 21.408 39.264 21.456 ;
     RECT  39.288 21.408 39.408 21.456 ;
     RECT  39.432 21.408 39.6 21.456 ;
     RECT  39.624 21.408 39.744 21.456 ;
     RECT  39.768 21.408 39.936 21.456 ;
     RECT  39.96 21.408 40.08 21.456 ;
     RECT  40.104 21.408 40.272 21.456 ;
     RECT  40.296 21.408 40.416 21.456 ;
     RECT  40.44 21.408 40.608 21.456 ;
     RECT  40.632 21.408 40.752 21.456 ;
     RECT  40.776 21.408 40.944 21.456 ;
     RECT  40.968 21.408 41.136 21.456 ;
     RECT  41.16 21.408 41.28 21.456 ;
     RECT  41.304 21.408 41.472 21.456 ;
     RECT  41.496 21.408 41.616 21.456 ;
     RECT  41.64 21.408 41.808 21.456 ;
     RECT  41.832 21.408 41.952 21.456 ;
     RECT  41.976 21.408 42.144 21.456 ;
     RECT  42.168 21.408 42.288 21.456 ;
     RECT  42.312 21.408 42.48 21.456 ;
     RECT  42.504 21.408 42.624 21.456 ;
     RECT  42.648 21.408 42.816 21.456 ;
     RECT  42.84 21.408 42.96 21.456 ;
     RECT  42.984 21.408 43.152 21.456 ;
     RECT  43.176 21.408 43.296 21.456 ;
     RECT  43.32 21.408 43.488 21.456 ;
     RECT  43.512 21.408 43.68 21.456 ;
     RECT  43.704 21.408 43.824 21.456 ;
     RECT  43.848 21.408 44.016 21.456 ;
     RECT  44.04 21.408 44.16 21.456 ;
     RECT  44.184 21.408 44.352 21.456 ;
     RECT  44.376 21.408 44.496 21.456 ;
     RECT  44.52 21.408 44.688 21.456 ;
     RECT  44.712 21.408 44.832 21.456 ;
     RECT  44.856 21.408 45.024 21.456 ;
     RECT  45.048 21.408 45.168 21.456 ;
     RECT  45.192 21.408 45.36 21.456 ;
     RECT  45.384 21.408 45.504 21.456 ;
     RECT  45.528 21.408 45.696 21.456 ;
     RECT  45.72 21.408 45.84 21.456 ;
     RECT  45.864 21.408 46.032 21.456 ;
     RECT  46.056 21.408 46.224 21.456 ;
     RECT  46.248 21.408 46.368 21.456 ;
     RECT  46.392 21.408 46.56 21.456 ;
     RECT  46.584 21.408 46.704 21.456 ;
     RECT  46.728 21.408 46.896 21.456 ;
     RECT  46.92 21.408 47.04 21.456 ;
     RECT  47.064 21.408 47.232 21.456 ;
     RECT  47.256 21.408 47.376 21.456 ;
     RECT  47.4 21.408 47.568 21.456 ;
     RECT  47.592 21.408 47.712 21.456 ;
     RECT  47.736 21.408 47.904 21.456 ;
     RECT  47.928 21.408 48.048 21.456 ;
     RECT  48.072 21.408 48.24 21.456 ;
     RECT  48.264 21.408 48.384 21.456 ;
     RECT  48.408 21.408 48.576 21.456 ;
     RECT  48.6 21.408 48.768 21.456 ;
     RECT  48.792 21.408 48.912 21.456 ;
     RECT  48.936 21.408 49.104 21.456 ;
     RECT  49.128 21.408 49.248 21.456 ;
     RECT  49.272 21.408 49.44 21.456 ;
     RECT  49.464 21.408 49.584 21.456 ;
     RECT  49.608 21.408 49.776 21.456 ;
     RECT  49.8 21.408 49.92 21.456 ;
     RECT  49.944 21.408 50.112 21.456 ;
     RECT  50.136 21.408 50.256 21.456 ;
     RECT  50.28 21.408 50.448 21.456 ;
     RECT  50.472 21.408 50.592 21.456 ;
     RECT  50.616 21.408 50.784 21.456 ;
     RECT  50.808 21.408 50.976 21.456 ;
     RECT  51 21.408 51.12 21.456 ;
     RECT  51.144 21.408 51.312 21.456 ;
     RECT  51.336 21.408 51.456 21.456 ;
     RECT  51.48 21.408 51.648 21.456 ;
     RECT  51.672 21.408 51.792 21.456 ;
     RECT  51.816 21.408 51.984 21.456 ;
     RECT  52.008 21.408 52.128 21.456 ;
     RECT  52.152 21.408 52.32 21.456 ;
     RECT  52.344 21.408 52.464 21.456 ;
     RECT  52.488 21.408 52.656 21.456 ;
     RECT  52.68 21.408 52.8 21.456 ;
     RECT  52.824 21.408 52.992 21.456 ;
     RECT  53.016 21.408 53.136 21.456 ;
     RECT  53.16 21.408 53.328 21.456 ;
     RECT  53.352 21.408 53.52 21.456 ;
     RECT  53.544 21.408 53.664 21.456 ;
     RECT  53.688 21.408 53.856 21.456 ;
     RECT  53.88 21.408 54 21.456 ;
     RECT  54.024 21.408 54.192 21.456 ;
     RECT  54.216 21.408 54.336 21.456 ;
     RECT  54.36 21.408 54.528 21.456 ;
     RECT  54.552 21.408 54.672 21.456 ;
     RECT  54.696 21.408 54.864 21.456 ;
     RECT  54.888 21.408 55.008 21.456 ;
     RECT  55.032 21.408 55.2 21.456 ;
     RECT  55.224 21.408 55.344 21.456 ;
     RECT  55.368 21.408 55.536 21.456 ;
     RECT  55.56 21.408 55.68 21.456 ;
     RECT  55.704 21.408 55.872 21.456 ;
     RECT  55.896 21.408 56.064 21.456 ;
     RECT  56.088 21.408 56.208 21.456 ;
     RECT  56.232 21.408 56.4 21.456 ;
     RECT  56.424 21.408 56.544 21.456 ;
     RECT  56.568 21.408 56.736 21.456 ;
     RECT  56.76 21.408 56.88 21.456 ;
     RECT  56.904 21.408 57.072 21.456 ;
     RECT  57.096 21.408 57.216 21.456 ;
     RECT  57.24 21.408 57.408 21.456 ;
     RECT  57.432 21.408 57.552 21.456 ;
     RECT  57.576 21.408 57.744 21.456 ;
     RECT  57.768 21.408 57.888 21.456 ;
     RECT  57.912 21.408 58.08 21.456 ;
     RECT  58.104 21.408 58.224 21.456 ;
     RECT  58.248 21.408 58.416 21.456 ;
     RECT  58.44 21.408 58.608 21.456 ;
     RECT  58.632 21.408 58.752 21.456 ;
     RECT  58.776 21.408 58.944 21.456 ;
     RECT  58.968 21.408 59.088 21.456 ;
     RECT  59.112 21.408 59.28 21.456 ;
     RECT  59.304 21.408 59.424 21.456 ;
     RECT  59.448 21.408 59.616 21.456 ;
     RECT  59.64 21.408 59.76 21.456 ;
     RECT  59.784 21.408 59.952 21.456 ;
     RECT  59.976 21.408 60.096 21.456 ;
     RECT  60.12 21.408 60.288 21.456 ;
     RECT  60.312 21.408 60.432 21.456 ;
     RECT  60.456 21.408 60.624 21.456 ;
     RECT  60.648 21.408 60.768 21.456 ;
     RECT  60.792 21.408 60.96 21.456 ;
     RECT  60.984 21.408 61.152 21.456 ;
     RECT  61.176 21.408 61.296 21.456 ;
     RECT  61.32 21.408 61.488 21.456 ;
     RECT  61.512 21.408 61.632 21.456 ;
     RECT  61.656 21.408 61.824 21.456 ;
     RECT  61.848 21.408 61.968 21.456 ;
     RECT  61.992 21.408 62.16 21.456 ;
     RECT  62.184 21.408 62.304 21.456 ;
     RECT  62.328 21.408 62.496 21.456 ;
     RECT  62.52 21.408 62.64 21.456 ;
     RECT  62.664 21.408 62.832 21.456 ;
     RECT  62.856 21.408 62.976 21.456 ;
     RECT  63 21.408 63.168 21.456 ;
     RECT  63.192 21.408 63.312 21.456 ;
     RECT  63.336 21.408 63.504 21.456 ;
     RECT  63.528 21.408 63.696 21.456 ;
     RECT  63.72 21.408 63.84 21.456 ;
     RECT  63.864 21.408 64.032 21.456 ;
     RECT  64.056 21.408 64.176 21.456 ;
     RECT  64.2 21.408 64.368 21.456 ;
     RECT  64.392 21.408 64.512 21.456 ;
     RECT  64.536 21.408 64.704 21.456 ;
     RECT  64.728 21.408 64.848 21.456 ;
     RECT  64.872 21.408 65.04 21.456 ;
     RECT  65.064 21.408 65.184 21.456 ;
     RECT  65.208 21.408 65.376 21.456 ;
     RECT  65.4 21.408 65.52 21.456 ;
     RECT  65.544 21.408 65.712 21.456 ;
     RECT  65.736 21.408 65.856 21.456 ;
     RECT  65.88 21.408 66.048 21.456 ;
     RECT  66.072 21.408 66.24 21.456 ;
     RECT  66.264 21.408 66.384 21.456 ;
     RECT  66.408 21.408 66.576 21.456 ;
     RECT  66.6 21.408 66.72 21.456 ;
     RECT  66.744 21.408 66.912 21.456 ;
     RECT  66.936 21.408 67.056 21.456 ;
     RECT  67.08 21.408 67.248 21.456 ;
     RECT  67.272 21.408 67.392 21.456 ;
     RECT  67.416 21.408 67.584 21.456 ;
     RECT  67.608 21.408 67.728 21.456 ;
     RECT  67.752 21.408 67.92 21.456 ;
     RECT  67.944 21.408 68.064 21.456 ;
     RECT  68.088 21.408 68.256 21.456 ;
     RECT  68.28 21.408 68.4 21.456 ;
     RECT  68.424 21.408 68.592 21.456 ;
     RECT  68.616 21.408 68.784 21.456 ;
     RECT  68.808 21.408 68.928 21.456 ;
     RECT  68.952 21.408 69.12 21.456 ;
     RECT  69.144 21.408 69.264 21.456 ;
     RECT  69.288 21.408 69.456 21.456 ;
     RECT  69.48 21.408 69.6 21.456 ;
     RECT  69.624 21.408 69.792 21.456 ;
     RECT  69.816 21.408 69.936 21.456 ;
     RECT  69.96 21.408 70.128 21.456 ;
     RECT  70.152 21.408 70.272 21.456 ;
     RECT  70.296 21.408 70.464 21.456 ;
     RECT  70.488 21.408 70.608 21.456 ;
     RECT  70.632 21.408 70.8 21.456 ;
     RECT  70.824 21.408 70.944 21.456 ;
     RECT  70.968 21.408 71.136 21.456 ;
     RECT  71.16 21.408 71.328 21.456 ;
     RECT  71.352 21.408 71.472 21.456 ;
     RECT  71.496 21.408 71.664 21.456 ;
     RECT  71.688 21.408 71.808 21.456 ;
     RECT  71.832 21.408 72 21.456 ;
     RECT  72.024 21.408 72.144 21.456 ;
     RECT  72.168 21.408 72.336 21.456 ;
     RECT  72.36 21.408 72.48 21.456 ;
     RECT  72.504 21.408 72.672 21.456 ;
     RECT  72.696 21.408 72.816 21.456 ;
     RECT  72.84 21.408 73.008 21.456 ;
     RECT  73.032 21.408 73.152 21.456 ;
     RECT  73.176 21.408 73.344 21.456 ;
     RECT  73.368 21.408 73.488 21.456 ;
     RECT  73.512 21.408 73.68 21.456 ;
     RECT  73.704 21.408 73.872 21.456 ;
     RECT  73.896 21.408 74.016 21.456 ;
     RECT  74.04 21.408 74.208 21.456 ;
     RECT  74.232 21.408 74.352 21.456 ;
     RECT  74.376 21.408 74.544 21.456 ;
     RECT  74.568 21.408 74.688 21.456 ;
     RECT  74.712 21.408 74.88 21.456 ;
     RECT  74.904 21.408 75.024 21.456 ;
     RECT  75.048 21.408 75.216 21.456 ;
     RECT  75.24 21.408 75.36 21.456 ;
     RECT  75.384 21.408 75.552 21.456 ;
     RECT  75.576 21.408 75.696 21.456 ;
     RECT  75.72 21.408 75.888 21.456 ;
     RECT  75.912 21.408 76.032 21.456 ;
     RECT  76.056 21.408 76.224 21.456 ;
     RECT  76.248 21.408 76.416 21.456 ;
     RECT  76.44 21.408 76.56 21.456 ;
     RECT  76.584 21.408 76.752 21.456 ;
     RECT  76.776 21.408 76.896 21.456 ;
     RECT  76.92 21.408 77.088 21.456 ;
     RECT  77.112 21.408 77.232 21.456 ;
     RECT  77.256 21.408 77.424 21.456 ;
     RECT  77.448 21.408 77.568 21.456 ;
     RECT  77.592 21.408 77.76 21.456 ;
     RECT  77.784 21.408 77.904 21.456 ;
     RECT  77.928 21.408 78.096 21.456 ;
     RECT  78.12 21.408 78.24 21.456 ;
     RECT  78.264 21.408 78.432 21.456 ;
     RECT  78.456 21.408 78.576 21.456 ;
     RECT  78.6 21.408 78.768 21.456 ;
     RECT  78.792 21.408 78.96 21.456 ;
     RECT  78.984 21.408 79.104 21.456 ;
     RECT  79.128 21.408 79.296 21.456 ;
     RECT  79.32 21.408 79.44 21.456 ;
     RECT  79.464 21.408 79.632 21.456 ;
     RECT  79.656 21.408 79.776 21.456 ;
     RECT  79.8 21.408 79.968 21.456 ;
     RECT  79.992 21.408 80.112 21.456 ;
     RECT  80.136 21.408 80.304 21.456 ;
     RECT  80.328 21.408 80.448 21.456 ;
     RECT  80.472 21.408 80.64 21.456 ;
     RECT  80.664 21.408 80.784 21.456 ;
     RECT  80.808 21.408 80.976 21.456 ;
     RECT  81 21.408 81.12 21.456 ;
     RECT  81.144 21.408 81.312 21.456 ;
     RECT  81.336 21.408 81.504 21.456 ;
     RECT  81.528 21.408 81.648 21.456 ;
     RECT  81.672 21.408 81.84 21.456 ;
     RECT  81.864 21.408 81.984 21.456 ;
     RECT  82.008 21.408 82.176 21.456 ;
     RECT  82.2 21.408 82.32 21.456 ;
     RECT  82.344 21.408 82.512 21.456 ;
     RECT  82.536 21.408 82.656 21.456 ;
     RECT  82.68 21.408 82.848 21.456 ;
     RECT  82.872 21.408 82.992 21.456 ;
     RECT  83.016 21.408 83.184 21.456 ;
     RECT  83.208 21.408 83.328 21.456 ;
     RECT  83.352 21.408 83.52 21.456 ;
     RECT  83.544 21.408 83.664 21.456 ;
     RECT  83.688 21.408 83.856 21.456 ;
     RECT  83.88 21.408 84.048 21.456 ;
     RECT  84.072 21.408 84.192 21.456 ;
     RECT  84.216 21.408 84.384 21.456 ;
     RECT  84.408 21.408 84.528 21.456 ;
     RECT  84.552 21.408 84.72 21.456 ;
     RECT  84.744 21.408 84.864 21.456 ;
     RECT  84.888 21.408 85.056 21.456 ;
     RECT  85.08 21.408 85.2 21.456 ;
     RECT  85.224 21.408 85.392 21.456 ;
     RECT  85.416 21.408 85.536 21.456 ;
     RECT  85.56 21.408 85.728 21.456 ;
     RECT  85.752 21.408 85.872 21.456 ;
     RECT  85.896 21.408 86.064 21.456 ;
     RECT  86.088 21.408 86.256 21.456 ;
     RECT  86.28 21.408 86.4 21.456 ;
     RECT  86.424 21.408 86.592 21.456 ;
     RECT  86.616 21.408 86.736 21.456 ;
     RECT  86.76 21.408 86.928 21.456 ;
     RECT  86.952 21.408 87.072 21.456 ;
     RECT  87.096 21.408 87.264 21.456 ;
     RECT  87.288 21.408 87.408 21.456 ;
     RECT  87.432 21.408 87.6 21.456 ;
     RECT  87.624 21.408 87.744 21.456 ;
     RECT  87.768 21.408 87.936 21.456 ;
     RECT  87.96 21.408 88.08 21.456 ;
     RECT  88.104 21.408 88.272 21.456 ;
     RECT  88.296 21.408 88.416 21.456 ;
     RECT  88.44 21.408 88.608 21.456 ;
     RECT  88.632 21.408 88.8 21.456 ;
     RECT  88.824 21.408 88.944 21.456 ;
     RECT  88.968 21.408 89.136 21.456 ;
     RECT  89.16 21.408 89.28 21.456 ;
     RECT  89.304 21.408 89.472 21.456 ;
     RECT  89.496 21.408 89.616 21.456 ;
     RECT  89.64 21.408 89.808 21.456 ;
     RECT  89.832 21.408 89.952 21.456 ;
     RECT  89.976 21.408 90.144 21.456 ;
     RECT  90.168 21.408 90.288 21.456 ;
     RECT  90.312 21.408 90.48 21.456 ;
     RECT  90.504 21.408 90.624 21.456 ;
     RECT  90.648 21.408 90.816 21.456 ;
     RECT  90.84 21.408 90.96 21.456 ;
     RECT  90.984 21.408 91.152 21.456 ;
     RECT  91.176 21.408 91.344 21.456 ;
     RECT  91.368 21.408 91.488 21.456 ;
     RECT  91.512 21.408 91.68 21.456 ;
     RECT  91.704 21.408 91.824 21.456 ;
     RECT  91.848 21.408 92.016 21.456 ;
     RECT  92.04 21.408 92.16 21.456 ;
     RECT  92.184 21.408 92.352 21.456 ;
     RECT  92.376 21.408 92.496 21.456 ;
     RECT  92.52 21.408 92.688 21.456 ;
     RECT  92.712 21.408 92.832 21.456 ;
     RECT  92.856 21.408 93.024 21.456 ;
     RECT  93.048 21.408 93.168 21.456 ;
     RECT  93.192 21.408 93.36 21.456 ;
     RECT  93.384 21.408 93.504 21.456 ;
     RECT  93.528 21.408 93.696 21.456 ;
     RECT  93.72 21.408 93.888 21.456 ;
     RECT  93.912 21.408 94.032 21.456 ;
     RECT  94.056 21.408 94.224 21.456 ;
     RECT  94.248 21.408 94.368 21.456 ;
     RECT  94.392 21.408 94.56 21.456 ;
     RECT  94.584 21.408 94.704 21.456 ;
     RECT  94.728 21.408 94.896 21.456 ;
     RECT  94.92 21.408 95.04 21.456 ;
     RECT  95.064 21.408 95.232 21.456 ;
     RECT  95.256 21.408 95.376 21.456 ;
     RECT  95.4 21.408 95.568 21.456 ;
     RECT  95.592 21.408 95.712 21.456 ;
     RECT  95.736 21.408 95.904 21.456 ;
     RECT  95.928 21.408 96.048 21.456 ;
     RECT  96.072 21.408 96.24 21.456 ;
     RECT  96.264 21.408 96.432 21.456 ;
     RECT  96.456 21.408 96.576 21.456 ;
     RECT  96.6 21.408 96.768 21.456 ;
     RECT  96.792 21.408 96.912 21.456 ;
     RECT  96.936 21.408 97.104 21.456 ;
     RECT  97.128 21.408 97.248 21.456 ;
     RECT  97.272 21.408 97.44 21.456 ;
     RECT  97.464 21.408 97.584 21.456 ;
     RECT  97.608 21.408 97.776 21.456 ;
     RECT  97.8 21.408 97.92 21.456 ;
     RECT  97.944 21.408 98.112 21.456 ;
     RECT  98.136 21.408 98.256 21.456 ;
     RECT  98.28 21.408 98.448 21.456 ;
     RECT  98.472 21.408 98.592 21.456 ;
     RECT  98.616 21.408 98.784 21.456 ;
     RECT  98.808 21.408 98.976 21.456 ;
     RECT  99 21.408 99.12 21.456 ;
     RECT  99.144 21.408 99.312 21.456 ;
     RECT  99.336 21.408 99.456 21.456 ;
     RECT  99.48 21.408 99.648 21.456 ;
     RECT  99.672 21.408 99.792 21.456 ;
     RECT  99.816 21.408 99.984 21.456 ;
     RECT  100.008 21.408 100.128 21.456 ;
     RECT  100.152 21.408 100.32 21.456 ;
     RECT  100.344 21.408 100.464 21.456 ;
     RECT  100.488 21.408 100.656 21.456 ;
     RECT  100.68 21.408 100.8 21.456 ;
     RECT  100.824 21.408 100.992 21.456 ;
     RECT  101.016 21.408 101.136 21.456 ;
     RECT  101.16 21.408 101.328 21.456 ;
     RECT  101.352 21.408 101.52 21.456 ;
     RECT  101.544 21.408 101.664 21.456 ;
     RECT  101.688 21.408 101.856 21.456 ;
     RECT  101.88 21.408 102 21.456 ;
     RECT  102.024 21.408 102.192 21.456 ;
     RECT  102.216 21.408 102.336 21.456 ;
     RECT  102.36 21.408 102.528 21.456 ;
     RECT  102.552 21.408 102.672 21.456 ;
     RECT  102.696 21.408 102.864 21.456 ;
     RECT  102.888 21.408 103.008 21.456 ;
     RECT  103.032 21.408 103.2 21.456 ;
     RECT  103.224 21.408 103.344 21.456 ;
     RECT  103.368 21.408 103.536 21.456 ;
     RECT  103.56 21.408 103.68 21.456 ;
     RECT  103.704 21.408 103.872 21.456 ;
     RECT  103.896 21.408 104.064 21.456 ;
     RECT  104.088 21.408 104.208 21.456 ;
     RECT  104.232 21.408 104.4 21.456 ;
     RECT  104.424 21.408 104.544 21.456 ;
     RECT  104.568 21.408 104.736 21.456 ;
     RECT  104.76 21.408 104.88 21.456 ;
     RECT  104.904 21.408 105.072 21.456 ;
     RECT  105.096 21.408 105.216 21.456 ;
     RECT  105.24 21.408 105.408 21.456 ;
     RECT  105.432 21.408 105.552 21.456 ;
     RECT  105.576 21.408 105.744 21.456 ;
     RECT  105.768 21.408 105.888 21.456 ;
     RECT  105.912 21.408 106.08 21.456 ;
     RECT  106.104 21.408 106.224 21.456 ;
     RECT  106.248 21.408 106.416 21.456 ;
     RECT  106.44 21.408 106.608 21.456 ;
     RECT  106.632 21.408 106.752 21.456 ;
     RECT  106.776 21.408 106.944 21.456 ;
     RECT  106.968 21.408 107.088 21.456 ;
     RECT  107.112 21.408 107.28 21.456 ;
     RECT  107.304 21.408 107.424 21.456 ;
     RECT  107.448 21.408 107.616 21.456 ;
     RECT  107.64 21.408 107.76 21.456 ;
     RECT  107.784 21.408 107.952 21.456 ;
     RECT  107.976 21.408 108.096 21.456 ;
     RECT  108.12 21.408 108.288 21.456 ;
     RECT  108.312 21.408 108.432 21.456 ;
     RECT  108.456 21.408 108.624 21.456 ;
     RECT  108.648 21.408 108.768 21.456 ;
     RECT  108.792 21.408 108.96 21.456 ;
     RECT  108.984 21.408 109.152 21.456 ;
     RECT  109.176 21.408 109.296 21.456 ;
     RECT  109.32 21.408 109.488 21.456 ;
     RECT  109.512 21.408 109.632 21.456 ;
     RECT  109.656 21.408 109.824 21.456 ;
     RECT  109.848 21.408 109.968 21.456 ;
     RECT  109.992 21.408 110.16 21.456 ;
     RECT  11.136 21.456 11.16 21.491 ;
     RECT  15.264 21.456 15.288 21.491 ;
     RECT  33.024 21.456 33.048 21.491 ;
     RECT  34.128 21.456 34.152 21.491 ;
     RECT  37.344 21.456 37.368 21.491 ;
     RECT  69.648 21.456 69.792 21.491 ;
     RECT  69.816 21.456 69.936 21.491 ;
     RECT  69.96 21.456 70.128 21.491 ;
     RECT  70.152 21.456 70.272 21.491 ;
     RECT  70.296 21.456 70.464 21.491 ;
     RECT  70.488 21.456 70.608 21.491 ;
     RECT  70.632 21.456 70.8 21.491 ;
     RECT  70.824 21.456 70.944 21.491 ;
     RECT  70.968 21.456 71.016 21.491 ;
     RECT  102.144 21.456 102.192 21.491 ;
     RECT  102.216 21.456 102.336 21.491 ;
     RECT  102.36 21.456 102.528 21.491 ;
     RECT  102.552 21.456 102.672 21.491 ;
     RECT  102.696 21.456 102.84 21.491 ;
     RECT  106.464 21.456 106.488 21.491 ;
     RECT  13.512 1.763 14.496 3.205 ;
     RECT  84.408 1.811 85.392 2.339 ;
     RECT  14.52 1.859 15.9 2.869 ;
     RECT  84.36 2.339 85.392 3.925 ;
     RECT  109.368 2.915 110.4 3.925 ;
     RECT  109.416 3.925 110.4 4.501 ;
     RECT  11.016 4.595 12.192 5.605 ;
     RECT  82.152 5.219 83.232 5.267 ;
     RECT  82.152 5.267 83.28 6.229 ;
     RECT  5.544 5.699 6.672 5.747 ;
     RECT  14.232 5.747 15.264 7.381 ;
     RECT  105.576 5.795 106.56 6.275 ;
     RECT  3.624 6.181 5.1 6.229 ;
     RECT  82.2 6.229 83.28 6.565 ;
     RECT  105.528 6.275 106.56 6.899 ;
     RECT  48.984 6.323 50.064 7.285 ;
     RECT  108.984 6.371 110.112 7.765 ;
     RECT  7.152 6.899 7.392 8.293 ;
     RECT  19.896 6.899 21.072 7.139 ;
     RECT  105.528 6.899 106.848 7.043 ;
     RECT  105.528 7.043 106.944 7.955 ;
     RECT  19.896 7.139 21.12 8.485 ;
     RECT  21.72 7.187 22.8 8.437 ;
     RECT  35.4 7.475 36.384 7.955 ;
     RECT  35.304 7.955 36.384 8.917 ;
     RECT  105.432 7.955 106.944 8.771 ;
     RECT  105.312 8.771 106.944 9.013 ;
     RECT  35.304 8.917 36.336 8.965 ;
     RECT  105.312 9.013 106.464 9.109 ;
     RECT  92.088 9.107 93.168 9.395 ;
     RECT  105.312 9.109 106.368 11.365 ;
     RECT  92.088 9.395 93.408 9.731 ;
     RECT  92.088 9.731 93.504 10.307 ;
     RECT  64.968 10.307 66.384 11.317 ;
     RECT  91.812 10.307 93.504 10.693 ;
     RECT  103.224 10.403 104.208 11.365 ;
     RECT  91.812 10.693 93.024 14.005 ;
     RECT  87.288 10.883 88.704 11.411 ;
     RECT  65.4 11.317 66.384 20.533 ;
     RECT  87.096 11.411 88.704 11.459 ;
     RECT  37.944 11.459 39.072 19.571 ;
     RECT  86.76 11.459 88.704 11.941 ;
     RECT  9.096 11.507 10.08 13.045 ;
     RECT  86.76 11.941 88.272 13.045 ;
     RECT  99.912 12.035 100.992 15.349 ;
     RECT  87.096 13.045 88.272 13.621 ;
     RECT  91.944 14.005 93.024 19.571 ;
     RECT  83.352 19.463 84.384 20.533 ;
     RECT  99.672 19.463 100.656 20.533 ;
     RECT  37.752 19.571 39.072 20.533 ;
     RECT  91.848 19.571 93.024 20.533 ;
     RECT  33.048 21.456 33.072 21.491 ;
     RECT  33.192 21.456 33.264 21.491 ;
     RECT  33.384 21.456 33.456 21.491 ;
     RECT  33.576 21.456 33.6 21.491 ;
     RECT  33.72 21.456 33.792 21.491 ;
     RECT  33.912 21.456 33.936 21.491 ;
     RECT  34.056 21.456 34.128 21.491 ;
  END
END hbfd_rly_624_SN_fc
END LIBRARY
